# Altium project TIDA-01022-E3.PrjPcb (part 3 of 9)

## Sheet TIDA-01022-E3_ADC12DJxx00_1.SchDoc: ADC12DJxx00_1
size 431 x 279 mm; Date: Not shown in title block; ApprovedBy: Not shown in title block; CheckedBy: Not shown in title block; Author: Not shown in title block; CompanyName: Not shown in title block; DrawnBy: Avinash N; Engineer: Not shown in title block; Organization: Not shown in title block; Address1: Not shown in title block; Address2: Not shown in title block; Address3: Not shown in title block; Address4: Not shown in title block; DocumentNumber: 1; Revision: Use project parameter SCH_Rev; SheetNumber: 6; SheetTotal: 26; PageSetup: Record=PageOptions¦CenterHorizontal=True¦CenterVertical=True¦PrintScale=1.00¦XCorrection=1.00¦YCorrection=1.00¦PrintKind=0¦BorderSize=5000000¦LeftOffset=0¦BottomOffset=0¦Orientation=2¦PaperLength=1000¦PaperWidth=1000¦Scale=100¦PaperSource=15¦PrintQuality=600¦MediaType=1¦DitherType=10¦PaperKind=Letter¦PrintScaleMode=1

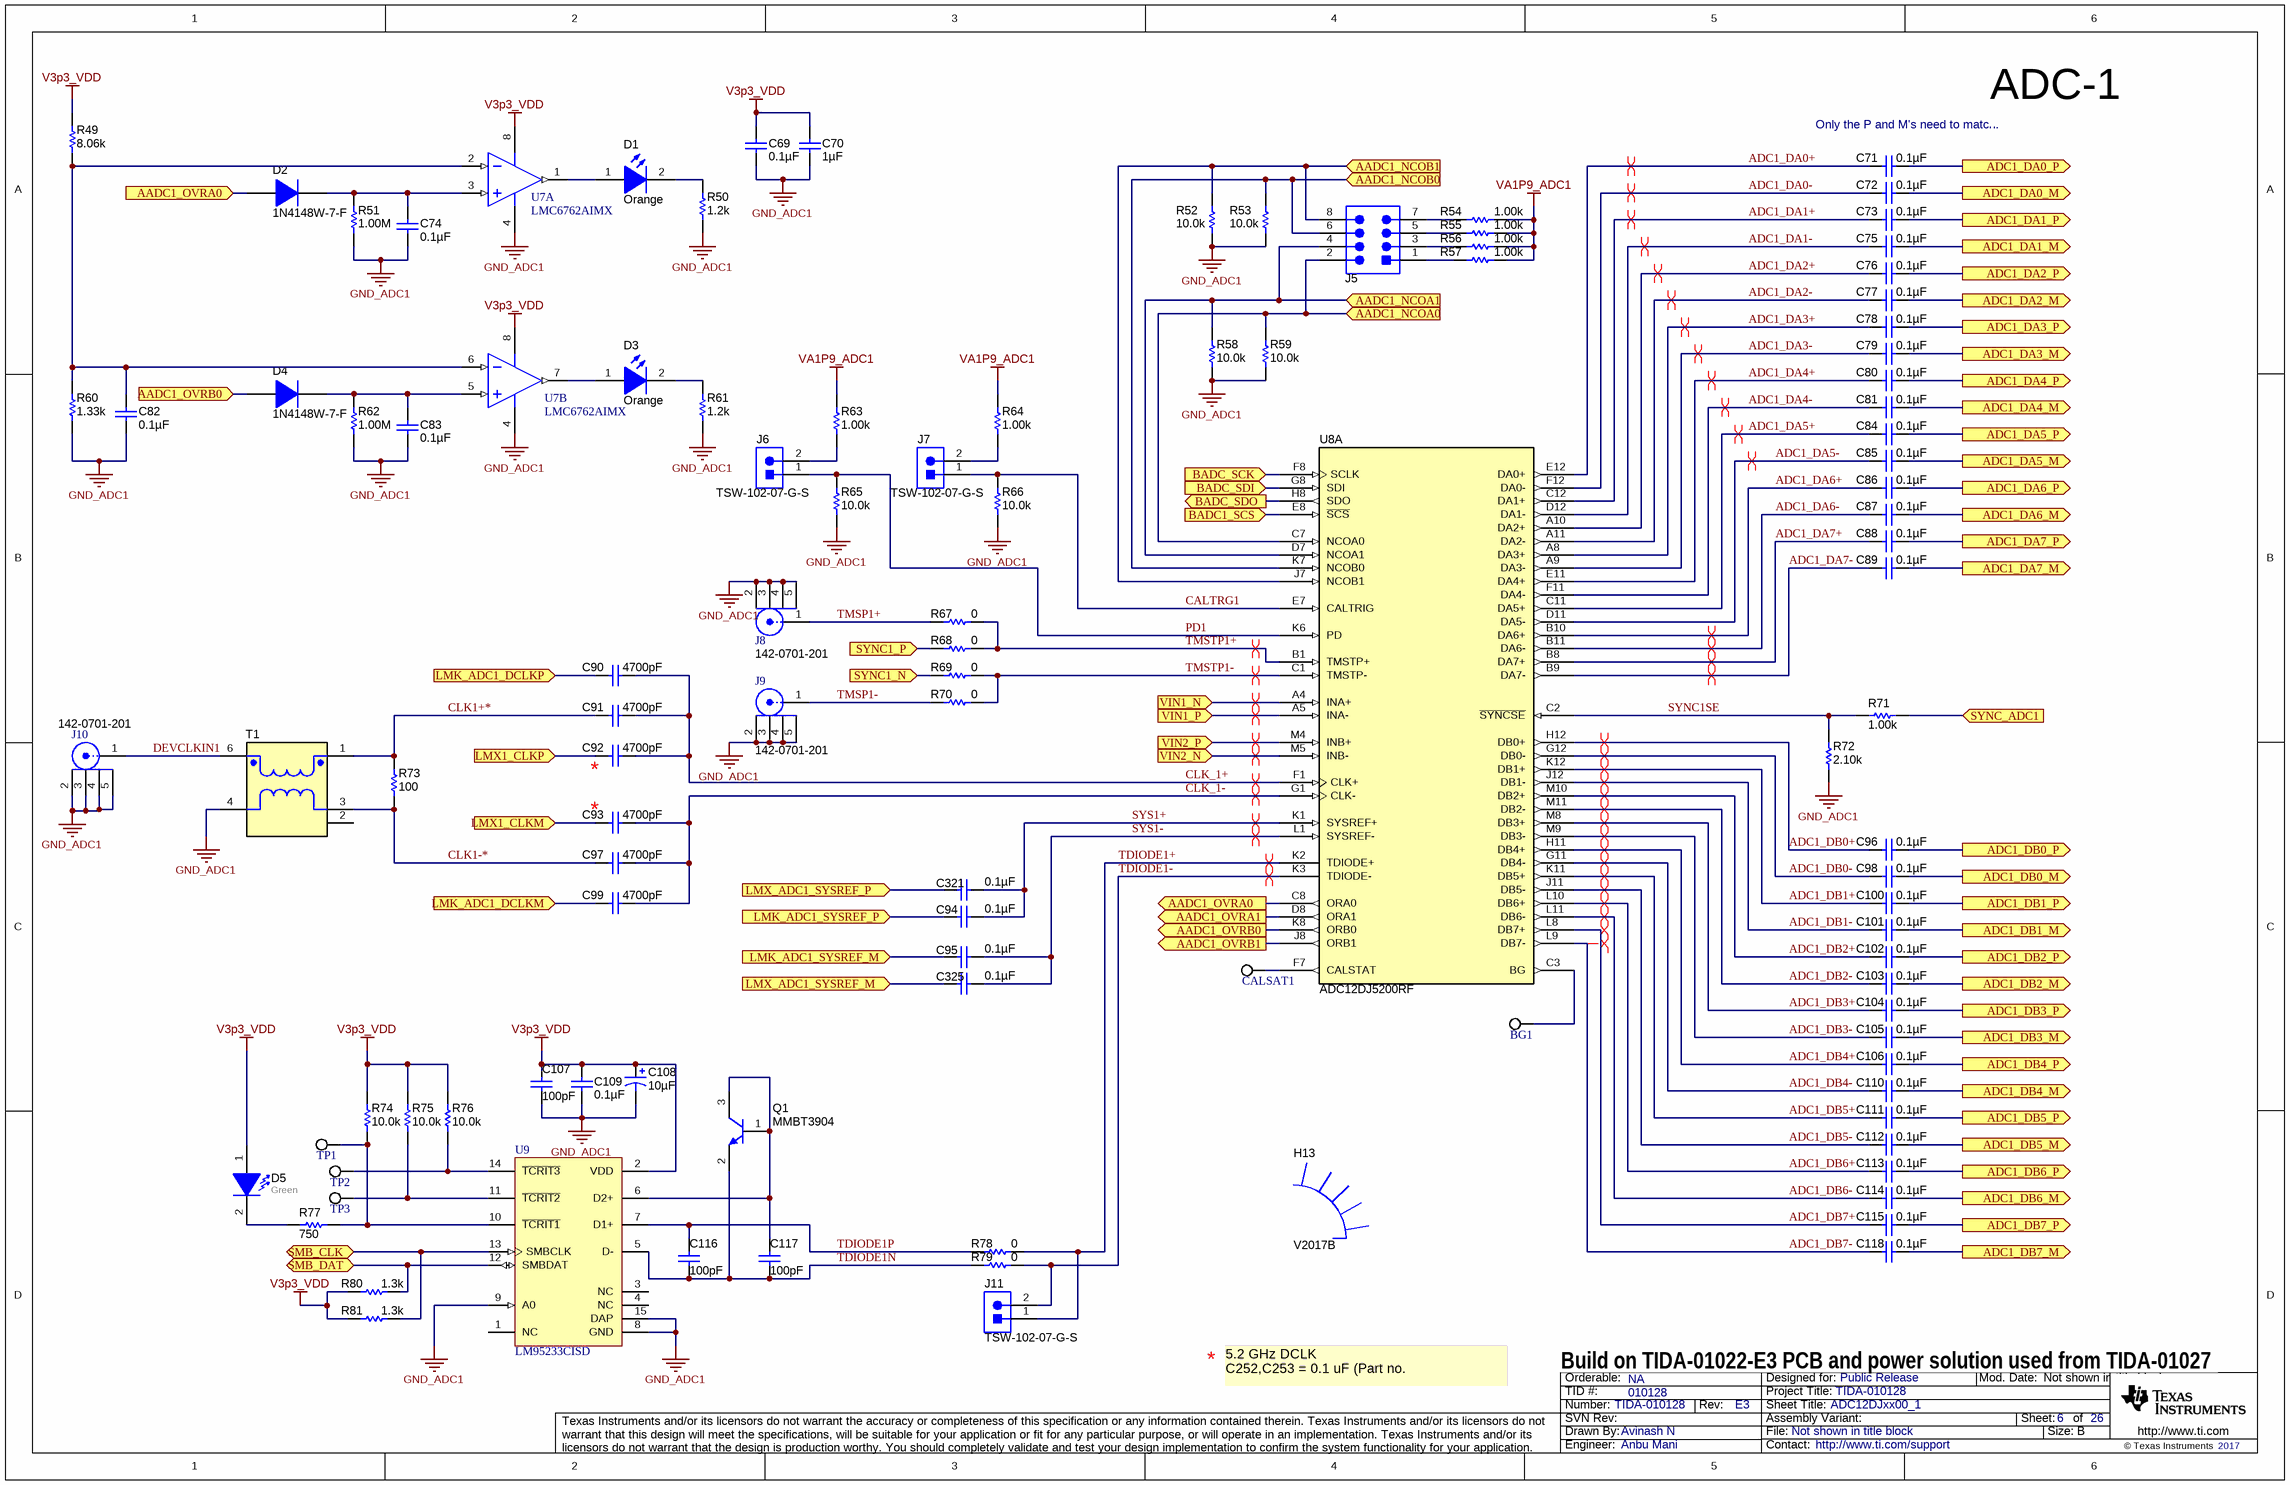
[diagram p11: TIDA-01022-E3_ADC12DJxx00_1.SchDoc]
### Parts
BG1  5002  [Keystone5002]  (value not drawn)
C69  ValueDisplayed: 0.1µF  [0402]  (hidden comment: C1005X7R1E104M050BB)
C70  ValueDisplayed: 1µF  [0603]  (hidden comment: C1608X5R1A105K080AC)
C71  ValueDisplayed: 0.1µF  [0201_adc]  (hidden comment: GRM033C71A104KE14D)
C72  ValueDisplayed: 0.1µF  [0201_adc]  (hidden comment: GRM033C71A104KE14D)
C73  ValueDisplayed: 0.1µF  [0201_adc]  (hidden comment: GRM033C71A104KE14D)
C74  ValueDisplayed: 0.1µF  [0402]  (hidden comment: C1005X7R1E104M050BB)
C75  ValueDisplayed: 0.1µF  [0201_adc]  (hidden comment: GRM033C71A104KE14D)
C76  ValueDisplayed: 0.1µF  [0201_adc]  (hidden comment: GRM033C71A104KE14D)
C77  ValueDisplayed: 0.1µF  [0201_adc]  (hidden comment: GRM033C71A104KE14D)
C78  ValueDisplayed: 0.1µF  [0201_adc]  (hidden comment: GRM033C71A104KE14D)
C79  ValueDisplayed: 0.1µF  [0201_adc]  (hidden comment: GRM033C71A104KE14D)
C80  ValueDisplayed: 0.1µF  [0201_adc]  (hidden comment: GRM033C71A104KE14D)
C81  ValueDisplayed: 0.1µF  [0201_adc]  (hidden comment: GRM033C71A104KE14D)
C82  ValueDisplayed: 0.1µF  [0402]  (hidden comment: C1005X7R1E104M050BB)
C83  ValueDisplayed: 0.1µF  [0402]  (hidden comment: C1005X7R1E104M050BB)
C84  ValueDisplayed: 0.1µF  [0201_adc]  (hidden comment: GRM033C71A104KE14D)
C85  ValueDisplayed: 0.1µF  [0201_adc]  (hidden comment: GRM033C71A104KE14D)
C86  ValueDisplayed: 0.1µF  [0201_adc]  (hidden comment: GRM033C71A104KE14D)
C87  ValueDisplayed: 0.1µF  [0201_adc]  (hidden comment: GRM033C71A104KE14D)
C88  ValueDisplayed: 0.1µF  [0201_adc]  (hidden comment: GRM033C71A104KE14D)
C89  ValueDisplayed: 0.1µF  [0201_adc]  (hidden comment: GRM033C71A104KE14D)
C90  ValueDisplayed: 4700pF  [0402]  (hidden comment: GRM155R71H472KA01D)
C91  ValueDisplayed: 4700pF  [0402]  (hidden comment: GRM155R71H472KA01D)
C92  ValueDisplayed: 4700pF  [0402]  (hidden comment: GRM155R71H472KA01D)
C93  ValueDisplayed: 4700pF  [0402]  (hidden comment: GRM155R71H472KA01D)
C94  ValueDisplayed: 0.1µF  [0402]  (hidden comment: C1005X7R1E104M050BB)
C95  ValueDisplayed: 0.1µF  [0402]  (hidden comment: C1005X7R1E104M050BB)
C96  ValueDisplayed: 0.1µF  [0201_adc]  (hidden comment: GRM033C71A104KE14D)
C97  ValueDisplayed: 4700pF  [0402]  (hidden comment: GRM155R71H472KA01D)
C98  ValueDisplayed: 0.1µF  [0201_adc]  (hidden comment: GRM033C71A104KE14D)
C99  ValueDisplayed: 4700pF  [0402]  (hidden comment: GRM155R71H472KA01D)
C100  ValueDisplayed: 0.1µF  [0201_adc]  (hidden comment: GRM033C71A104KE14D)
C101  ValueDisplayed: 0.1µF  [0201_adc]  (hidden comment: GRM033C71A104KE14D)
C102  ValueDisplayed: 0.1µF  [0201_adc]  (hidden comment: GRM033C71A104KE14D)
C103  ValueDisplayed: 0.1µF  [0201_adc]  (hidden comment: GRM033C71A104KE14D)
C104  ValueDisplayed: 0.1µF  [0201_adc]  (hidden comment: GRM033C71A104KE14D)
C105  ValueDisplayed: 0.1µF  [0201_adc]  (hidden comment: GRM033C71A104KE14D)
C106  ValueDisplayed: 0.1µF  [0201_adc]  (hidden comment: GRM033C71A104KE14D)
C107  ValueDisplayed: 100pF  [0402]  (hidden comment: GRM1555C1H101JA01D)
C108  ValueDisplayed: 10µF  [3528-21]  (hidden comment: 293D106X0010B2TE3)
C109  ValueDisplayed: 0.1µF  [0402]  (hidden comment: C1005X7R1E104M050BB)
C110  ValueDisplayed: 0.1µF  [0201_adc]  (hidden comment: GRM033C71A104KE14D)
C111  ValueDisplayed: 0.1µF  [0201_adc]  (hidden comment: GRM033C71A104KE14D)
C112  ValueDisplayed: 0.1µF  [0201_adc]  (hidden comment: GRM033C71A104KE14D)
C113  ValueDisplayed: 0.1µF  [0201_adc]  (hidden comment: GRM033C71A104KE14D)
C114  ValueDisplayed: 0.1µF  [0201_adc]  (hidden comment: GRM033C71A104KE14D)
C115  ValueDisplayed: 0.1µF  [0201_adc]  (hidden comment: GRM033C71A104KE14D)
C116  ValueDisplayed: 100pF  [0402]  (hidden comment: GRM1555C1H101JA01D)
C117  ValueDisplayed: 100pF  [0402]  (hidden comment: GRM1555C1H101JA01D)
C118  ValueDisplayed: 0.1µF  [0201_adc]  (hidden comment: GRM033C71A104KE14D)
C321  ValueDisplayed: 0.1µF  [0402]  (hidden comment: C1005X7R1E104M050BB)
C325  ValueDisplayed: 0.1µF  [0402]  (hidden comment: C1005X7R1E104M050BB)
CALSAT1  5002  [Keystone5002]  (value not drawn)
D1  value Orange  [LED_LTST-C190]  (hidden comment: LTST-C190KFKT)
D2  1N4148W-7-F  [SOD-123]
D3  value Orange  [LED_LTST-C190]  (hidden comment: LTST-C190KFKT)
D4  1N4148W-7-F  [SOD-123]
D5  value Green  [LED_LTST-C190]  (hidden comment: LTST-C190GKT)
H13  V2017B  [ASMN_V2017B]  (mechanical)
J5  TSW-104-07-G-D  [TSW-104-07-G-D]  (value not drawn)
J6  TSW-102-07-G-S  [TSW-102-07-G-S]
J7  TSW-102-07-G-S  [TSW-102-07-G-S]
J8  142-0701-201  [Johnson_142-0701-20x]
J9  142-0701-201  [Johnson_142-0701-20x]
J10  142-0701-201  [Johnson_142-0701-20x]
J11  TSW-102-07-G-S  [TSW-102-07-G-S]
Q1  MMBT3904  [SOT-23]
R49  ValueDisplayed: 8.06k  [0402]  (hidden comment: CRCW04028K06FKED)
R50  ValueDisplayed: 1.2k  [0402]  (hidden comment: CRCW04021K20JNED)
R51  ValueDisplayed: 1.00M  [0402]  (hidden comment: ERJ-2RKF1004X)
R52  ValueDisplayed: 10.0k  [0402]  (hidden comment: ERJ-2RKF1002X)
R53  ValueDisplayed: 10.0k  [0402]  (hidden comment: ERJ-2RKF1002X)
R54  ValueDisplayed: 1.00k  [0402]  (hidden comment: ERJ-2RKF1001X)
R55  ValueDisplayed: 1.00k  [0402]  (hidden comment: ERJ-2RKF1001X)
R56  ValueDisplayed: 1.00k  [0402]  (hidden comment: ERJ-2RKF1001X)
R57  ValueDisplayed: 1.00k  [0402]  (hidden comment: ERJ-2RKF1001X)
R58  ValueDisplayed: 10.0k  [0402]  (hidden comment: ERJ-2RKF1002X)
R59  ValueDisplayed: 10.0k  [0402]  (hidden comment: ERJ-2RKF1002X)
R60  ValueDisplayed: 1.33k  [0402]  (hidden comment: CRCW04021K33FKED)
R61  ValueDisplayed: 1.2k  [0402]  (hidden comment: CRCW04021K20JNED)
R62  ValueDisplayed: 1.00M  [0402]  (hidden comment: ERJ-2RKF1004X)
R63  ValueDisplayed: 1.00k  [0402]  (hidden comment: ERJ-2RKF1001X)
R64  ValueDisplayed: 1.00k  [0402]  (hidden comment: ERJ-2RKF1001X)
R65  ValueDisplayed: 10.0k  [0402]  (hidden comment: ERJ-2RKF1002X)
R66  ValueDisplayed: 10.0k  [0402]  (hidden comment: ERJ-2RKF1002X)
R67  ValueDisplayed: 0  [0402]  (hidden comment: CRCW04020000Z0ED)
R68  ValueDisplayed: 0  [0402]  (hidden comment: CRCW04020000Z0ED)
R69  ValueDisplayed: 0  [0402]  (hidden comment: CRCW04020000Z0ED)
R70  ValueDisplayed: 0  [0402]  (hidden comment: CRCW04020000Z0ED)
R71  ValueDisplayed: 1.00k  [0402]  (hidden comment: ERJ-2RKF1001X)
R72  ValueDisplayed: 2.10k  [0402]  (hidden comment: CRCW04022K10FKED)
R73  ValueDisplayed: 100  [0402]  (hidden comment: CRCW0402100RFKED)
R74  ValueDisplayed: 10.0k  [0402]  (hidden comment: ERJ-2RKF1002X)
R75  ValueDisplayed: 10.0k  [0402]  (hidden comment: ERJ-2RKF1002X)
R76  ValueDisplayed: 10.0k  [0402]  (hidden comment: ERJ-2RKF1002X)
R77  ValueDisplayed: 750  [0603]  (hidden comment: CRCW0603750RJNEA)
R78  ValueDisplayed: 0  [0402]  (hidden comment: CRCW04020000Z0ED)
R79  ValueDisplayed: 0  [0402]  (hidden comment: CRCW04020000Z0ED)
R80  ValueDisplayed: 1.3k  [0603]  (hidden comment: RC0603JR-071K3L)
R81  ValueDisplayed: 1.3k  [0603]  (hidden comment: RC0603JR-071K3L)
T1  TC1-1-43X+  [MNC_AT1521]  (value not drawn)
TP1  5002  [Keystone5002]  (value not drawn)
TP2  5002  [Keystone5002]  (value not drawn)
TP3  5002  [Keystone5002]  (value not drawn)
U7  LMC6762AIMX  [M08A_N]  (parts A,B of 2)
U8  ADC12DJ5200RF  [AAV0144A]  (part A of 2)
U9  LM95233CISD  [SDA14B]

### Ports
AADC1_NCOA0 (in), AADC1_NCOA1 (in), AADC1_NCOB0 (in), AADC1_NCOB1 (in), AADC1_OVRA0 (in), AADC1_OVRA0 (out), AADC1_OVRA1 (out), AADC1_OVRB0 (in), AADC1_OVRB0 (out), AADC1_OVRB1 (out), ADC1_DA0_M (out), ADC1_DA0_P (out), ADC1_DA1_M (out), ADC1_DA1_P (out), ADC1_DA2_M (out), ADC1_DA2_P (out), ADC1_DA3_M (out), ADC1_DA3_P (out), ADC1_DA4_M (out), ADC1_DA4_P (out), ADC1_DA5_M (out), ADC1_DA5_P (out), ADC1_DA6_M (out), ADC1_DA6_P (out), ADC1_DA7_M (out), ADC1_DA7_P (out), ADC1_DB0_M (out), ADC1_DB0_P (out), ADC1_DB1_M (out), ADC1_DB1_P (out), ADC1_DB2_M (out), ADC1_DB2_P (out), ADC1_DB3_M (out), ADC1_DB3_P (out), ADC1_DB4_M (out), ADC1_DB4_P (out), ADC1_DB5_M (out), ADC1_DB5_P (out), ADC1_DB6_M (out), ADC1_DB6_P (out), ADC1_DB7_M (out), ADC1_DB7_P (out), BADC1_SCS (in), BADC_SCK (in), BADC_SDI (in), BADC_SDO (out), LMK_ADC1_DCLKM (in), LMK_ADC1_DCLKP (in), LMK_ADC1_SYSREF_M (in), LMK_ADC1_SYSREF_P (in), LMX1_CLKM (in), LMX1_CLKP (in), LMX_ADC1_SYSREF_M (in), LMX_ADC1_SYSREF_P (in), SMB_CLK (bidir), SMB_DAT (bidir), SYNC1_N (in), SYNC1_P (in), SYNC_ADC1 (in), VIN1_N (in), VIN1_P (in), VIN2_N (in), VIN2_P (in)

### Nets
GND_ADC1: C69.1 C70.2 C74.1 C82.1 C83.1 C107.2 C108.2(-) C109.2 J8.2 J8.3 J8.4 J8.5 J9.2 J9.3 J9.4 J9.5 J10.2 J10.3 J10.4 J10.5 R50.1 R51.1 R52.2 R53.2 R58.2 R59.2 R60.1 R61.1 R62.1 R65.1 R66.1 R72.1 T1.4 U7.4(V-) U9.8(GND) U9.9(A0) U9.15(DAP)  [project net DGND]
V3p3_VDD: C69.2 C70.1 C107.1 C108.1(+) C109.1 D5.1(A) R49.2 R74.2 R75.2 R76.2 R80.2 R81.2 U7.8(V+) U9.2(VDD)
VA1P9_ADC1: R54.1 R55.1 R56.1 R57.1 R63.2 R64.2
AADC1_NCOA0: J5.2 R59.1 U8.C7(NCOA0) ; port AADC1_NCOA0
AADC1_NCOA1: J5.4 R58.1 U8.D7(NCOA1) ; port AADC1_NCOA1
AADC1_NCOB0: J5.6 R53.1 U8.K7(NCOB0) ; port AADC1_NCOB0
AADC1_NCOB1: J5.8 R52.1 U8.J7(NCOB1) ; port AADC1_NCOB1
AADC1_OVRA0: D2.2(A) U8.C8(ORA0) ; port AADC1_OVRA0
AADC1_OVRA1: U8.D8(ORA1) ; port AADC1_OVRA1
AADC1_OVRB0: D4.2(A) U8.K8(ORB0) ; port AADC1_OVRB0
AADC1_OVRB1: U8.J8(ORB1) ; port AADC1_OVRB1
ADC1_DA0+: C71.1 U8.E12(DA0+)
ADC1_DA0-: C72.1 U8.F12(DA0-)
ADC1_DA0_M: C72.2 ; port ADC1_DA0_M
ADC1_DA0_P: C71.2 ; port ADC1_DA0_P
ADC1_DA1+: C73.1 U8.C12(DA1+)
ADC1_DA1-: C75.1 U8.D12(DA1-)
ADC1_DA1_M: C75.2 ; port ADC1_DA1_M
ADC1_DA1_P: C73.2 ; port ADC1_DA1_P
ADC1_DA2+: C76.1 U8.A10(DA2+)
ADC1_DA2-: C77.1 U8.A11(DA2-)
ADC1_DA2_M: C77.2 ; port ADC1_DA2_M
ADC1_DA2_P: C76.2 ; port ADC1_DA2_P
ADC1_DA3+: C78.1 U8.A8(DA3+)
ADC1_DA3-: C79.1 U8.A9(DA3-)
ADC1_DA3_M: C79.2 ; port ADC1_DA3_M
ADC1_DA3_P: C78.2 ; port ADC1_DA3_P
ADC1_DA4+: C80.1 U8.E11(DA4+)
ADC1_DA4-: C81.1 U8.F11(DA4-)
ADC1_DA4_M: C81.2 ; port ADC1_DA4_M
ADC1_DA4_P: C80.2 ; port ADC1_DA4_P
ADC1_DA5+: C84.1 U8.C11(DA5+)
ADC1_DA5-: C85.1 U8.D11(DA5-)
ADC1_DA5_M: C85.2 ; port ADC1_DA5_M
ADC1_DA5_P: C84.2 ; port ADC1_DA5_P
ADC1_DA6+: C86.1 U8.B10(DA6+)
ADC1_DA6-: C87.1 U8.B11(DA6-)
ADC1_DA6_M: C87.2 ; port ADC1_DA6_M
ADC1_DA6_P: C86.2 ; port ADC1_DA6_P
ADC1_DA7+: C88.1 U8.B8(DA7+)
ADC1_DA7-: C89.1 U8.B9(DA7-)
ADC1_DA7_M: C89.2 ; port ADC1_DA7_M
ADC1_DA7_P: C88.2 ; port ADC1_DA7_P
ADC1_DB0+: C96.1 U8.H12(DB0+)
ADC1_DB0-: C98.1 U8.G12(DB0-)
ADC1_DB0_M: C98.2 ; port ADC1_DB0_M
ADC1_DB0_P: C96.2 ; port ADC1_DB0_P
ADC1_DB1+: C100.1 U8.K12(DB1+)
ADC1_DB1-: C101.1 U8.J12(DB1-)
ADC1_DB1_M: C101.2 ; port ADC1_DB1_M
ADC1_DB1_P: C100.2 ; port ADC1_DB1_P
ADC1_DB2+: C102.1 U8.M10(DB2+)
ADC1_DB2-: C103.1 U8.M11(DB2-)
ADC1_DB2_M: C103.2 ; port ADC1_DB2_M
ADC1_DB2_P: C102.2 ; port ADC1_DB2_P
ADC1_DB3+: C104.1 U8.M8(DB3+)
ADC1_DB3-: C105.1 U8.M9(DB3-)
ADC1_DB3_M: C105.2 ; port ADC1_DB3_M
ADC1_DB3_P: C104.2 ; port ADC1_DB3_P
ADC1_DB4+: C106.1 U8.H11(DB4+)
ADC1_DB4-: C110.1 U8.G11(DB4-)
ADC1_DB4_M: C110.2 ; port ADC1_DB4_M
ADC1_DB4_P: C106.2 ; port ADC1_DB4_P
ADC1_DB5+: C111.1 U8.K11(DB5+)
ADC1_DB5-: C112.1 U8.J11(DB5-)
ADC1_DB5_M: C112.2 ; port ADC1_DB5_M
ADC1_DB5_P: C111.2 ; port ADC1_DB5_P
ADC1_DB6+: C113.1 U8.L10(DB6+)
ADC1_DB6-: C114.1 U8.L11(DB6-)
ADC1_DB6_M: C114.2 ; port ADC1_DB6_M
ADC1_DB6_P: C113.2 ; port ADC1_DB6_P
ADC1_DB7+: C115.1 U8.L8(DB7+)
ADC1_DB7-: C118.1 U8.L9(DB7-)
ADC1_DB7_M: C118.2 ; port ADC1_DB7_M
ADC1_DB7_P: C115.2 ; port ADC1_DB7_P
BADC1_SCS: U8.E8(~{SCS}) ; port BADC1_SCS
BADC_SCK: U8.F8(SCLK) ; port BADC_SCK
BADC_SDI: U8.G8(SDI) ; port BADC_SDI
BADC_SDO: U8.H8(SDO) ; port BADC_SDO
CALTRG1: J7.1 R66.2 U8.E7(CALTRIG)
CLK1+*: C91.2 R73.2 T1.1
CLK1-*: C97.2 R73.1 T1.3
CLK_1+: C90.1 C91.1 C92.1 U8.F1(CLK+)
CLK_1-: C93.1 C97.1 C99.1 U8.G1(CLK-)
DEVCLKIN1: J10.1 T1.6
LMK_ADC1_DCLKM: C99.2 ; port LMK_ADC1_DCLKM
LMK_ADC1_DCLKP: C90.2 ; port LMK_ADC1_DCLKP
LMK_ADC1_SYSREF_M: C95.1 ; port LMK_ADC1_SYSREF_M
LMK_ADC1_SYSREF_P: C94.1 ; port LMK_ADC1_SYSREF_P
LMX1_CLKM: C93.2 ; port LMX1_CLKM
LMX1_CLKP: C92.2 ; port LMX1_CLKP
LMX_ADC1_SYSREF_M: C325.1 ; port LMX_ADC1_SYSREF_M
LMX_ADC1_SYSREF_P: C321.1 ; port LMX_ADC1_SYSREF_P
PD1: J6.1 R65.2 U8.K6(PD)
SMB_CLK: R81.1 U9.13(SMBCLK) ; port SMB_CLK
SMB_DAT: R80.1 U9.12(SMBDAT) ; port SMB_DAT
SYNC1_N: R69.1 ; port SYNC1_N
SYNC1_P: R68.1 ; port SYNC1_P
SYNC1SE: R71.1 R72.2 U8.C2(~{SYNCSE})
SYNC_ADC1: R71.2 ; port SYNC_ADC1
SYS1+: C94.2 C321.2 U8.K1(SYSREF+)
SYS1-: C95.2 C325.2 U8.L1(SYSREF-)
TDIODE1+: J11.1 R78.2 U8.K2(TDIODE+)
TDIODE1-: J11.2 R79.2 U8.K3(TDIODE-)
TDIODE1N: C116.2 C117.2 Q1.2(E) R79.1 U9.5(D-)
TDIODE1P: C116.1 R78.1 U9.7(D1+)
TMSP1+: J8.1 R67.1
TMSP1-: J9.1 R70.1
TMSTP1+: R67.2 R68.2 U8.B1(TMSTP+)
TMSTP1-: R69.2 R70.2 U8.C1(TMSTP-)
VIN1_N: U8.A4(INA+) ; port VIN1_N
VIN1_P: U8.A5(INA-) ; port VIN1_P
VIN2_N: U8.M5(INB-) ; port VIN2_N
VIN2_P: U8.M4(INB+) ; port VIN2_P
NetBG1_1: BG1.1 U8.C3(BG)
NetC74_2: C74.2 D2.1(K) R51.2 U7.3(INA+)
NetC82_2: C82.2 R49.1 R60.2 U7.2(INA-) U7.6(INB-)
NetC83_2: C83.2 D4.1(K) R62.2 U7.5(INB+)
NetC117_1: C117.1 Q1.1(B) Q1.3(C) U9.6(D2+)
NetCALSAT1_1: CALSAT1.1 U8.F7(CALSTAT)
NetD1_1: D1.1(A) U7.1(OUTA)
NetD1_2: D1.2(K) R50.2
NetD3_1: D3.1(A) U7.7(OUTB)
NetD3_2: D3.2(K) R61.2
NetD5_2: D5.2(K) R77.2
NetJ5_1: J5.1 R57.2
NetJ5_3: J5.3 R56.2
NetJ5_5: J5.5 R55.2
NetJ5_7: J5.7 R54.2
NetJ6_2: J6.2 R63.1
NetJ7_2: J7.2 R64.1
NetR74_1: R74.1 R77.1 TP1.1 U9.10(~{TCRIT1})
NetR75_1: R75.1 TP3.1 U9.11(~{TCRIT2})
NetR76_1: R76.1 TP2.1 U9.14(~{TCRIT3})

Not connected (* = marked no-connect by the designer): T1 2; U9 1(NC) 3(NC) 4(NC)

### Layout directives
differential pair: ADC1_DA0+, ADC1_DA0-, ADC1_DA1+, ADC1_DA1-, ADC1_DA2+, ADC1_DA2-, ADC1_DA3+, ADC1_DA3-, ADC1_DA4+, ADC1_DA4-, ADC1_DA5+, ADC1_DA5-, ADC1_DA6+, ADC1_DA6-, ADC1_DA7+, ADC1_DA7-, ADC1_DB0+, ADC1_DB0-, ADC1_DB1+, ADC1_DB1-, ADC1_DB2+, ADC1_DB2-, ADC1_DB3+, ADC1_DB3-, ADC1_DB4+, ADC1_DB4-, ADC1_DB5+, ADC1_DB5-, ADC1_DB6+, ADC1_DB6-, ADC1_DB7+, ADC1_DB7-, CLK_1+, CLK_1-, SYS1+, SYS1-, TDIODE1+, TDIODE1-, TMSTP1+, TMSTP1-, VIN1_N, VIN1_P, VIN2_N, VIN2_P

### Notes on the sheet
- (near C71) Only the P and M's need to match.
- ADC-1
- (near C92) *
- (near C93) *
- *
- Build on TIDA-01022-E3 PCB and power solution used from TIDA-01027
- 5.2 GHz DCLK
  C252,C253 = 0.1 uF (Part no. 530Z104KT10T))

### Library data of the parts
BG1 CALSAT1 TP1-TP3 = 5002: Test Point, Miniature, White, TH; Manufacturer: Keystone; CompType: Test Point Loop; ContactFinish: Silver; Green_Lifecycle: Active; Green_REACh: Passed
C69 C74 C82 C83 C94 C95 C109 C321 C325 = C1005X7R1E104M050BB: CAP, CERM, 0.1 µF, 25 V, +/- 20%, X7R, 0402; Manufacturer: TDK; Polarized: N; TaMax_C: 125; TaMin_C: -55; Tolerance_%: 20; VDC_V: 25; Cap_F: 0.0000001; CompType: Capacitor; Value: 0.1uF; Value1: Unknown; Value2: 25V; U/M: EA; SizeArea_mm2: 0.5; SizeAreaWB_mm2: 3; SizeX_mm: 1; SizeZ_mm: 0.6; AEC Category: Q200
C70 = C1608X5R1A105K080AC: CAP, CERM, 1 µF, 10 V, +/- 10%, X5R, 0603; Manufacturer: TDK; Polarized: N; CompType: Capacitor; Value: 1uF; U/M: EA; Cap_F: 0.000001; Tolerance_%: 10; Value1: Unknown; Value2: 10V; TaMin_C: -55; TaMax_C: 85; SizeArea_mm2: 1.28; SizeAreaWB_mm2: 4.68; SizeX_mm: 1.6; SizeY_mm: 0.8; SizeZ_mm: 1; AEC Category: Q200
C71-C73 C75-C81 C84-C89 C96 C98 C100-C106 C110-C115 C118 = GRM033C71A104KE14D: CAP, CERM, 0.1 µF, 10 V, +/- 10%, X7S, 0201; Manufacturer: MuRata; Cap_Case: 0201; Polarized: N; TaMax_C: 125; TaMin_C: -55; Tolerance_%: 10; Cap_F: 0.0000001; CompType: Capacitor; Value: 0.1uF; Value1: Unknown; Value2: 10V; U/M: EA; SizeArea_mm2: 0.18; SizeAreaWB_mm2: 2.08; SizeX_mm: 0.6; SizeY_mm: 0.3; SizeZ_mm: 0.26; AEC Category: Q200
C90-C93 C97 C99 = GRM155R71H472KA01D: CAP, CERM, 4700 pF, 50 V, +/- 10%, X7R, 0402; Manufacturer: MuRata; Polarized: N; CompType: Capacitor; Value: 4700pF; U/M: EA; Cap_F: 0.0000000047; Tolerance_%: 10; Value1: Unknown; VDC_V: 50; Value2: 50V; TaMin_C: -55; TaMax_C: 125; SizeArea_mm2: 0.5; SizeAreaWB_mm2: 3; SizeX_mm: 1; SizeZ_mm: 0.6; AEC Category: Q200
C107 C116 C117 = GRM1555C1H101JA01D: CAP, CERM, 100 pF, 50 V, +/- 5%, C0G/NP0, 0402; Manufacturer: MuRata; Polarized: N; CompType: Capacitor; Value: 100pF; U/M: EA; Cap_F: 0.0000000001; Tolerance_%: 5; Value1: Unknown; VDC_V: 50; Value2: 50V; TaMin_C: -55; TaMax_C: 125; SizeArea_mm2: 0.5; SizeAreaWB_mm2: 3; SizeX_mm: 1; SizeZ_mm: 0.6; AEC Category: Q200
C108 = 293D106X0010B2TE3: CAP, TA, 10 µF, 10 V, +/- 20%, 2.5 ohm, SMD; Manufacturer: Vishay-Sprague; Polarized: Y; CompType: Capacitor; Value: 10uF; U/M: EA; Cap_F: 0.00001; Tolerance_%: 20; Value1: 2.5 ohm; VDC_V: 10; Value2: 10V; ESR_ohm: 2.5; IRMS_A: 0.18; TaMin_C: -55; TaMax_C: 125; Cap_Case: B; SizeAreaWB_mm2: 17.1; SizeArea_mm2: 9.8; SizeX_mm: 3.5; SizeY_mm: 2.8; SizeZ_mm: 2.1; AEC Category: Q200
D1 D3 = LTST-C190KFKT: LED, Orange, SMD; Manufacturer: Lite-On; Type: AlInGaP; Vf_V: 2; Value2: 2V; Io_A: 0.02; Power_TotalModule: 0.075; Value1: 0.075W; U/M: EA
D2 D4 = 1N4148W-7-F: Diode, Ultrafast, 100 V, 0.15 A, SOD-123; Manufacturer: Diodes Inc.; U/M: EA; Vf_V: 1.25; Value: 100V; Value1: 0.15A; Value2: 1.25V; Io_A: 0.15; Vr_V: 100; TJmax_C: 150; SizeAreaWB_mm2: 13.095; SizeArea_mm2: 6.545; SizeX_mm: 3.85; SizeY_mm: 1.7; SizeZ_mm: 1.35; AEC Category: Q101
D5 = LTST-C190GKT: LED, Green, SMD; Manufacturer: Lite-On; Vf_V: 2.1; Value2: 2.1V; Io_A: 0.02; Power_TotalModule: 0.1; Value1: 0.1W; U/M: EA
H13 = V2017B: Heatsink, 10X10X7 mm; Manufacturer: Assman WSW; SymbolCreator: a0412235
J5 = TSW-104-07-G-D: Header, 100mil, 4x2, Gold, TH; Manufacturer: Samtec; SymbolCreator: a0411947; Pitch_mm: 2.54; Gender: Male; Shrouded: N; Row_Count: 2; Current_A: 6.3; Voltage_V: 550; Cert_CSA: Y
J6 J7 J11 = TSW-102-07-G-S: Header, 100mil, 2x1, Gold, TH; Manufacturer: Samtec; SymbolCreator: a0412235; Pitch_mm: 2.54; Gender: Male; Shrouded: N; Row_Count: 1; Current_A: 6.3; Voltage_V: 550; Cert_CSA: Y
J8 J9 = 142-0701-201: Connector, TH, SMA; Manufacturer: Emerson Network Power; SymbolCreator: X0208326
J10 = 142-0701-201: Connector, SMA, TH; Manufacturer: Cinch Connectivity; SymbolCreator: X0208326; Green_Lifecycle: Not Set; Green_REACh: Incomplete
Q1 = MMBT3904, Fairchild Semiconductor: Transistor, NPN, 40 V, 0.2 A, SOT-23; CompType: BJT; PNP: 0; NPN: 1; Vceo_V: 40; Vcesat1_V: 0.2; Value: 40 V; Value1: 0.2 A; HfeMax: 300; TaMin_C: -55; TaMax_C: 150; SizeAreaWB_mm2: 14; SizeArea_mm2: 7.5; SizeX_mm: 2.5; SizeY_mm: 3; SizeZ_mm: 1.1; U/M: EA; AEC Category: Q101
R49 = CRCW04028K06FKED: RES, 8.06 k, 1%, 0.063 W, 0402; Manufacturer: Vishay-Dale; CompType: Resistor; Value: 8.06k; Res_ohm: 8060; Value_Code: 8k06; Tolerance_%: 1; Power_W: 0.063; Value2: 0.063W; VDC_V: 50; TempCo: 100 ppm/C; SizeArea_mm2: 0.5; SizeZ_mm: 0.6; EIA_Code: E96; U/M: EA; AEC Category: Q200
R50 R61 = CRCW04021K20JNED: RES, 1.2 k, 5%, 0.063 W, 0402; Manufacturer: Vishay-Dale; CompType: Resistor; Value: 1.2k; Res_ohm: 1200; Value_Code: 1k20; Tolerance_%: 5; Power_W: 0.063; Value2: 0.063W; VDC_V: 50; TempCo: 200 ppm/C; SizeArea_mm2: 0.5; SizeX_mm: 1; SizeZ_mm: 0.6; EIA_Code: E24; U/M: EA; AEC Category: Q200
R51 R62 = ERJ-2RKF1004X: RES, 1.00 M, 1%, 0.1 W, 0402; Manufacturer: Panasonic; CompType: Resistor; Value: 1.00Meg; Res_ohm: 1000000; Value_Code: 1M00; Tolerance_%: 1; Power_W: 0.1; Value2: 0.1W; VDC_V: 50; TempCo: 100 ppm/C; SizeArea_mm2: 0.5; SizeZ_mm: 0.6; EIA_Code: E96; U/M: EA; AEC Category: Q200
R52 R53 R58 R59 R65 R66 R74-R76 = ERJ-2RKF1002X: RES, 10.0 k, 1%, 0.1 W, 0402; Manufacturer: Panasonic; CompType: Resistor; Value: 10.0k; Res_ohm: 10000; Value_Code: 10k0; Tolerance_%: 1; Power_W: 0.1; Value2: 0.1W; VDC_V: 50; TempCo: 100 ppm/C; SizeArea_mm2: 0.5; SizeZ_mm: 0.6; EIA_Code: E96; U/M: EA; AEC Category: Q200
R54-R57 R63 R64 R71 = ERJ-2RKF1001X: RES, 1.00 k, 1%, 0.1 W, 0402; Manufacturer: Panasonic; CompType: Resistor; Value: 1.00k; Res_ohm: 1000; Value_Code: 1k00; Tolerance_%: 1; Power_W: 0.1; Value2: 0.1W; VDC_V: 50; TempCo: 100 ppm/C; SizeArea_mm2: 0.5; SizeZ_mm: 0.6; EIA_Code: E96; U/M: EA; AEC Category: Q200
R60 = CRCW04021K33FKED: RES, 1.33 k, 1%, 0.063 W, 0402; Manufacturer: Vishay-Dale; CompType: Resistor; Value: 1.33k; Res_ohm: 1330; Value_Code: 1k33; Tolerance_%: 1; Power_W: 0.063; Value2: 0.063W; VDC_V: 50; TempCo: 100 ppm/C; SizeArea_mm2: 0.5; SizeZ_mm: 0.6; EIA_Code: E96; U/M: EA; AEC Category: Q200
R67-R70 R78 R79 = CRCW04020000Z0ED: RES, 0, 5%, 0.063 W, 0402; Manufacturer: Vishay-Dale; CompType: Resistor; Value: 0; Value_Code: 0000; Tolerance_%: 5; Power_W: 0.063; Value2: 0.063W; VDC_V: 50; TempCo: 200 ppm/C; SizeArea_mm2: 0.5; SizeX_mm: 1; SizeZ_mm: 0.6; EIA_Code: E24; U/M: EA; AEC Category: Q200
R72 = CRCW04022K10FKED: RES, 2.10 k, 1%, 0.063 W, 0402; Manufacturer: Vishay-Dale; CompType: Resistor; Value: 2.10k; Res_ohm: 2100; Value_Code: 2k10; Tolerance_%: 1; Power_W: 0.063; Value2: 0.063W; VDC_V: 50; TempCo: 100 ppm/C; SizeArea_mm2: 0.5; SizeZ_mm: 0.6; EIA_Code: E96; U/M: EA; AEC Category: Q200
R73 = CRCW0402100RFKED: RES, 100, 1%, 0.063 W, 0402; Manufacturer: Vishay-Dale; CompType: Resistor; Value: 100; Value_Code: 100R; Tolerance_%: 1; Power_W: 0.063; Value2: 0.063W; VDC_V: 50; TempCo: 100 ppm/C; SizeArea_mm2: 0.5; SizeZ_mm: 0.6; EIA_Code: E96; U/M: EA; AEC Category: Q200
R77 = CRCW0603750RJNEA: RES, 750, 5%, 0.1 W, 0603; Manufacturer: Vishay-Dale; CompType: Resistor; Value: 750; Value_Code: 750R; Tolerance_%: 5; Power_W: 0.1; Value2: 0.1W; VDC_V: 75; TempCo: 200 ppm/C; SizeArea_mm2: 1.28; SizeX_mm: 1.6; SizeY_mm: 0.8; SizeZ_mm: 1; EIA_Code: E24; U/M: EA; AEC Category: Q200
R80 R81 = RC0603JR-071K3L: RES, 1.3 k, 5%, 0.1 W, 0603; Manufacturer: Yageo America; CompType: Resistor; Value: 1.3k; Res_ohm: 1300; Value_Code: 1k30; Tolerance_%: 5; Power_W: 0.1; Value2: 0.1W; VDC_V: 50; TempCo: 100 ppm/C; SizeArea_mm2: 1.28; SizeX_mm: 1.6; SizeY_mm: 0.8; SizeZ_mm: 1; EIA_Code: E24; U/M: EA; AEC Category: Q200
T1 = TC1-1-43X+: RF Transformer, 50 ohm, SMT; Manufacturer: Minicircuits; SymbolCreator: Altium
U7 = LMC6762AIMX: Dual Micro-Power Rail-to-Rail Input CMOS Comparator with Push-Pull Output, 8-pin Narrow SOIC; PartNumber: LMC6762AIM/NOPB-ND; Manufacturer: Texas Instruments; PackageTopMarking: NSZXTT*LMC67*62AIM; PowerWise: N
U8 = ADC12DJ3200AAVR: 6.4-GSPS Single Channel or 3.2-GSPS Dual Channel 12-bit Analog-to-Digital Converter (ADC) Family, AAV0144A (FCBGA-144); Manufacturer: Texas Instruments; SymbolCreator: Altium; SizeArea_mm2: 100; SizeAreaWB_mm2: 144; SizeX_mm: 10; SizeZ_mm: 1.94; CompType: IC; U/M: EA
U9 = LM95233CISD: Dual Remote Diode and Local Temperature Sensor with SMBus Interface and TruTherm Technology, 15-pin LLP; PartNumber: LM95233CISD/NOPB; Manufacturer: Texas Instruments; PackageTopMarking: NS*UZXYTT*95233CI; PowerWise: Y; CompType: Temp Sensor IC

## Sheet TIDA-01022-E3_ADC12DJxx00_1PWR.SchDoc: ADC12DJxx00_1PWR
size 431 x 279 mm; Date: Not shown in title block; ApprovedBy: Not shown in title block; CheckedBy: Not shown in title block; Author: Not shown in title block; CompanyName: Not shown in title block; DrawnBy: Avinash N; Engineer: Not shown in title block; Organization: Not shown in title block; Address1: Not shown in title block; Address2: Not shown in title block; Address3: Not shown in title block; Address4: Not shown in title block; DocumentNumber: 1; Revision: Use project parameter SCH_Rev; SheetNumber: 7; SheetTotal: 26; PageSetup: Record=PageOptions¦CenterHorizontal=True¦CenterVertical=True¦PrintScale=1.00¦XCorrection=1.00¦YCorrection=1.00¦PrintKind=0¦BorderSize=5000000¦LeftOffset=0¦BottomOffset=0¦Orientation=2¦PaperLength=1000¦PaperWidth=1000¦Scale=100¦PaperSource=15¦PrintQuality=600¦MediaType=1¦DitherType=10¦PaperKind=Letter¦PrintScaleMode=1

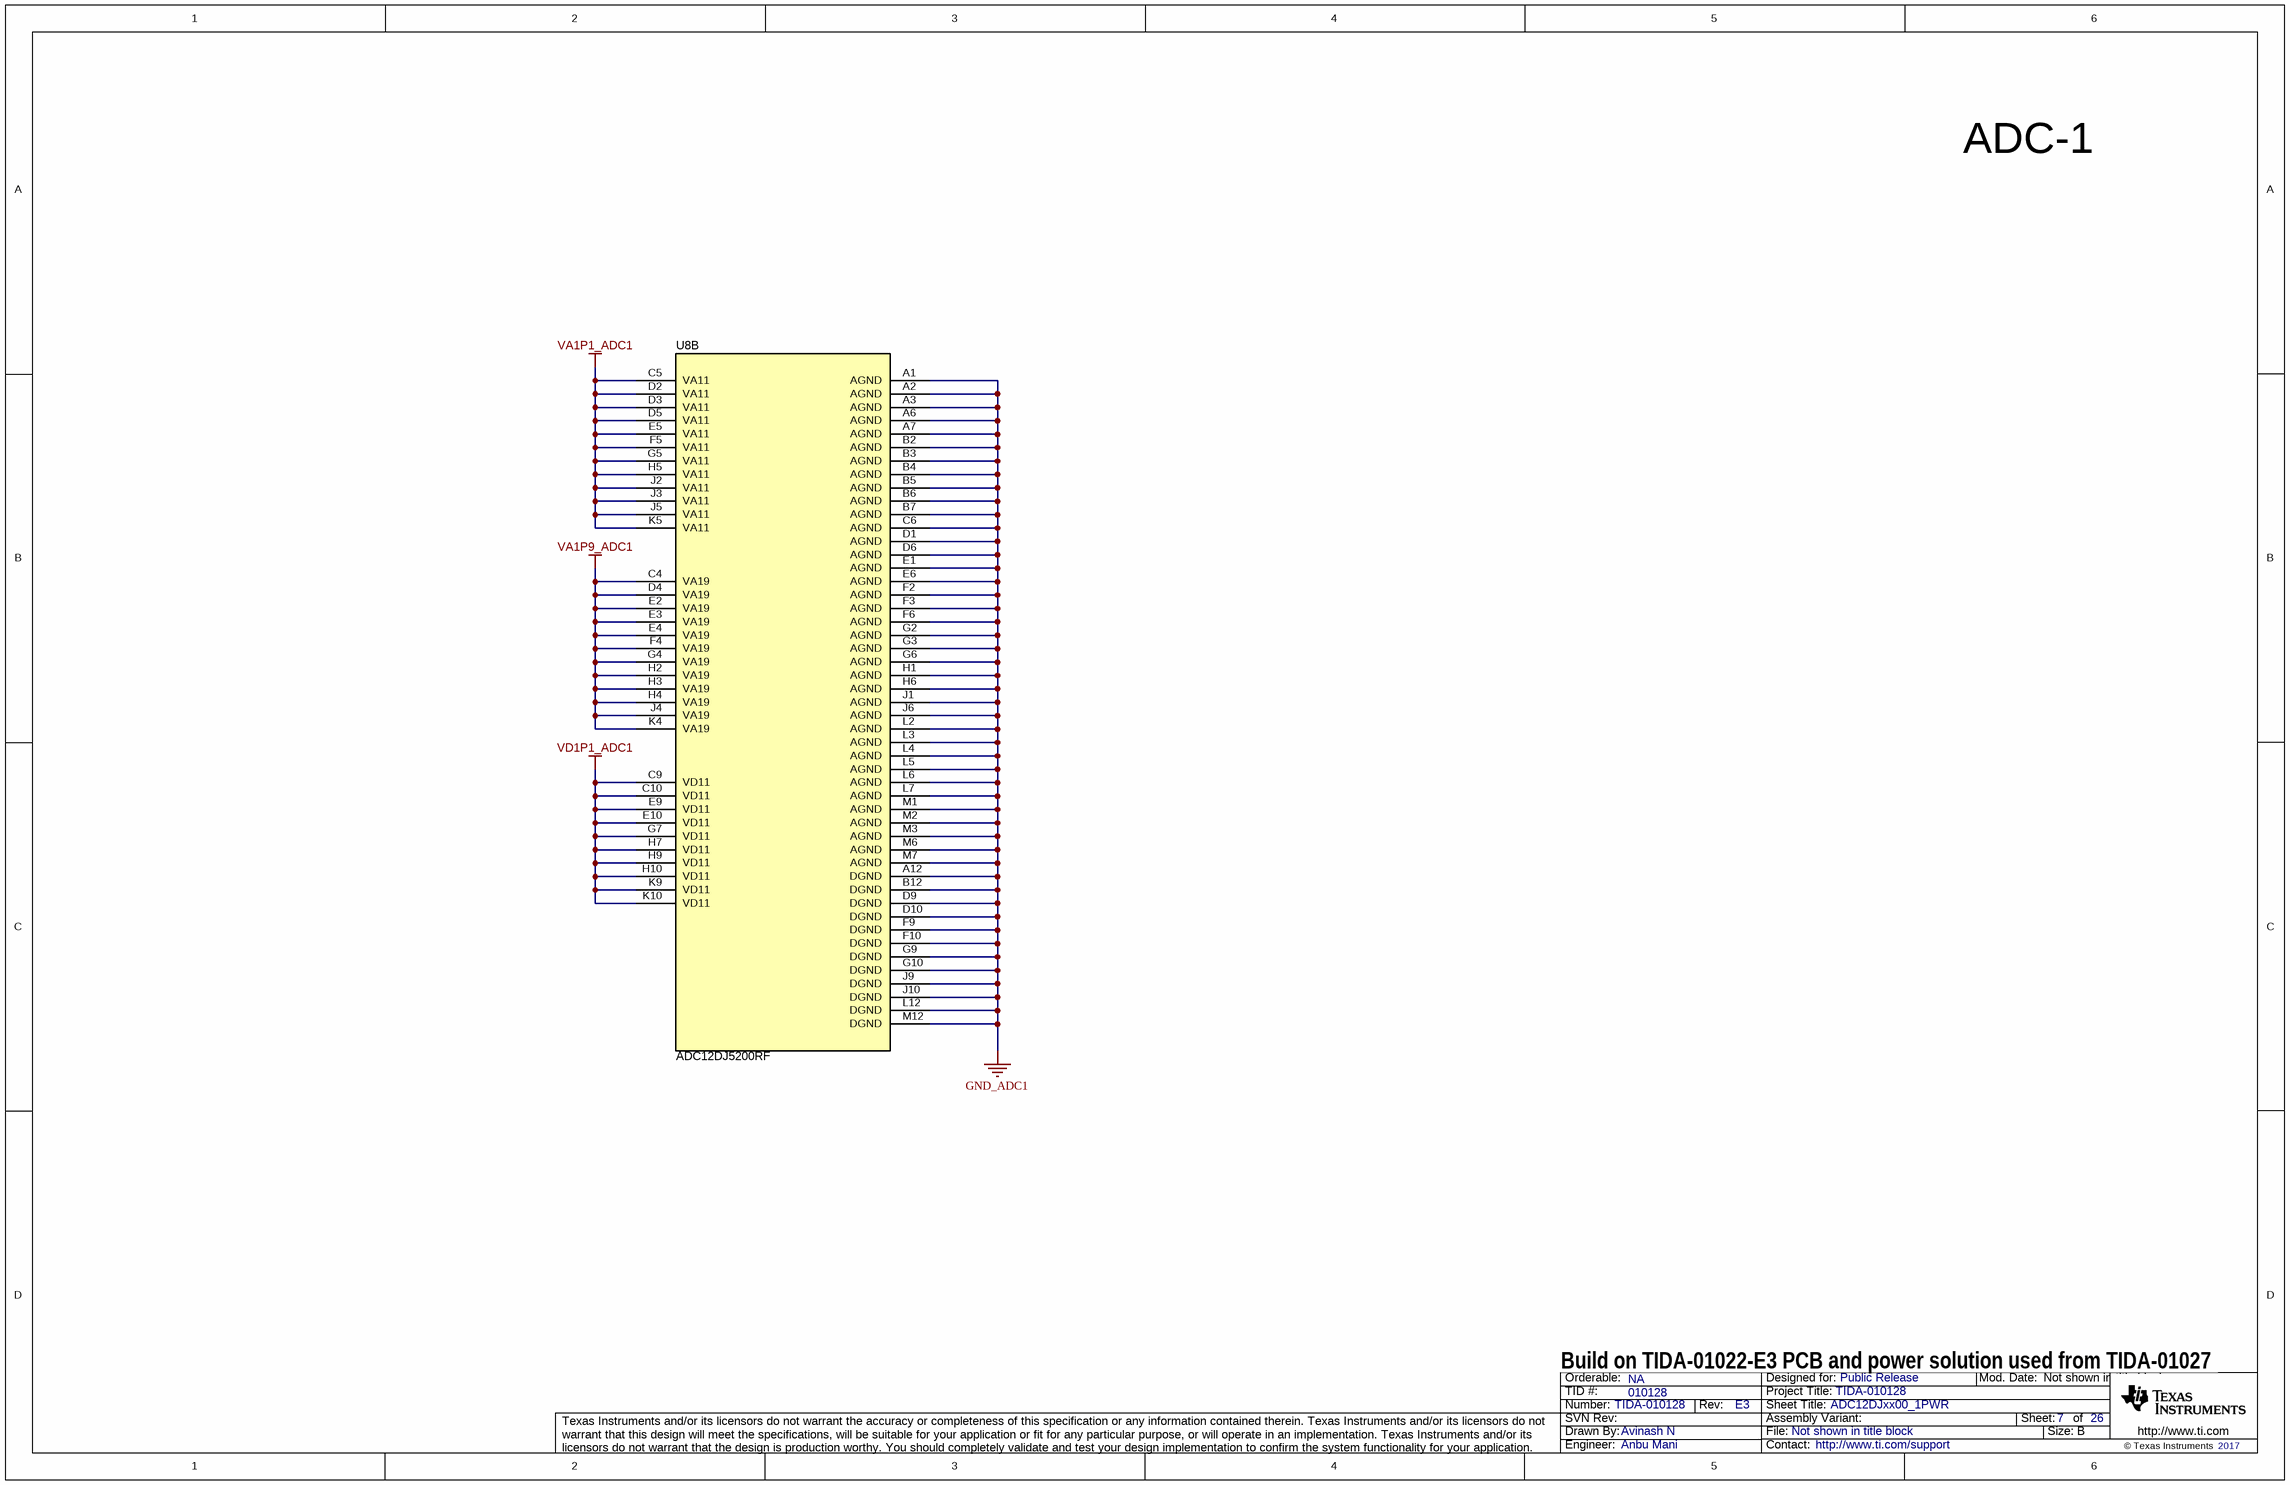
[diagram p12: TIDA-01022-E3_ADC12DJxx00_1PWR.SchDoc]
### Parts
U8  ADC12DJ5200RF  [AAV0144A]  (part B of 2)

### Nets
GND_ADC1: U8.A1(AGND) U8.A2(AGND) U8.A3(AGND) U8.A6(AGND) U8.A7(AGND) U8.A12(DGND) U8.B2(AGND) U8.B3(AGND) U8.B4(AGND) U8.B5(AGND) U8.B6(AGND) U8.B7(AGND) U8.B12(DGND) U8.C6(AGND) U8.D1(AGND) U8.D6(AGND) U8.D9(DGND) U8.D10(DGND) U8.E1(AGND) U8.E6(AGND) U8.F2(AGND) U8.F3(AGND) U8.F6(AGND) U8.F9(DGND) U8.F10(DGND) U8.G2(AGND) U8.G3(AGND) U8.G6(AGND) U8.G9(DGND) U8.G10(DGND) U8.H1(AGND) U8.H6(AGND) U8.J1(AGND) U8.J6(AGND) U8.J9(DGND) U8.J10(DGND) U8.L2(AGND) U8.L3(AGND) U8.L4(AGND) U8.L5(AGND) U8.L6(AGND) U8.L7(AGND) U8.L12(DGND) U8.M1(AGND) U8.M2(AGND) U8.M3(AGND) U8.M6(AGND) U8.M7(AGND) U8.M12(DGND)  [project net DGND]
VA1P1_ADC1: U8.C5(VA11) U8.D2(VA11) U8.D3(VA11) U8.D5(VA11) U8.E5(VA11) U8.F5(VA11) U8.G5(VA11) U8.H5(VA11) U8.J2(VA11) U8.J3(VA11) U8.J5(VA11) U8.K5(VA11)
VA1P9_ADC1: U8.C4(VA19) U8.D4(VA19) U8.E2(VA19) U8.E3(VA19) U8.E4(VA19) U8.F4(VA19) U8.G4(VA19) U8.H2(VA19) U8.H3(VA19) U8.H4(VA19) U8.J4(VA19) U8.K4(VA19)
VD1P1_ADC1: U8.C9(VD11) U8.C10(VD11) U8.E9(VD11) U8.E10(VD11) U8.G7(VD11) U8.H7(VD11) U8.H9(VD11) U8.H10(VD11) U8.K9(VD11) U8.K10(VD11)

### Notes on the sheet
- ADC-1
- Build on TIDA-01022-E3 PCB and power solution used from TIDA-01027

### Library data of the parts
U8 = ADC12DJ3200AAVR: as U8 on sheet TIDA-01022-E3_ADC12DJxx00_1

## Sheet TIDA-01022-E3_ADC12DJxx00_2.SchDoc: ADC12DJxx00_2
size 431 x 279 mm; Date: Not shown in title block; ApprovedBy: Not shown in title block; CheckedBy: Not shown in title block; Author: Not shown in title block; CompanyName: Not shown in title block; DrawnBy: Avinash N; Engineer: Not shown in title block; Organization: Not shown in title block; Address1: Not shown in title block; Address2: Not shown in title block; Address3: Not shown in title block; Address4: Not shown in title block; DocumentNumber: 1; Revision: Use project parameter SCH_Rev; SheetNumber: 8; SheetTotal: 26; PageSetup: Record=PageOptions¦CenterHorizontal=True¦CenterVertical=True¦PrintScale=1.00¦XCorrection=1.00¦YCorrection=1.00¦PrintKind=0¦BorderSize=5000000¦LeftOffset=0¦BottomOffset=0¦Orientation=2¦PaperLength=1000¦PaperWidth=1000¦Scale=100¦PaperSource=15¦PrintQuality=600¦MediaType=1¦DitherType=10¦PaperKind=Letter¦PrintScaleMode=1

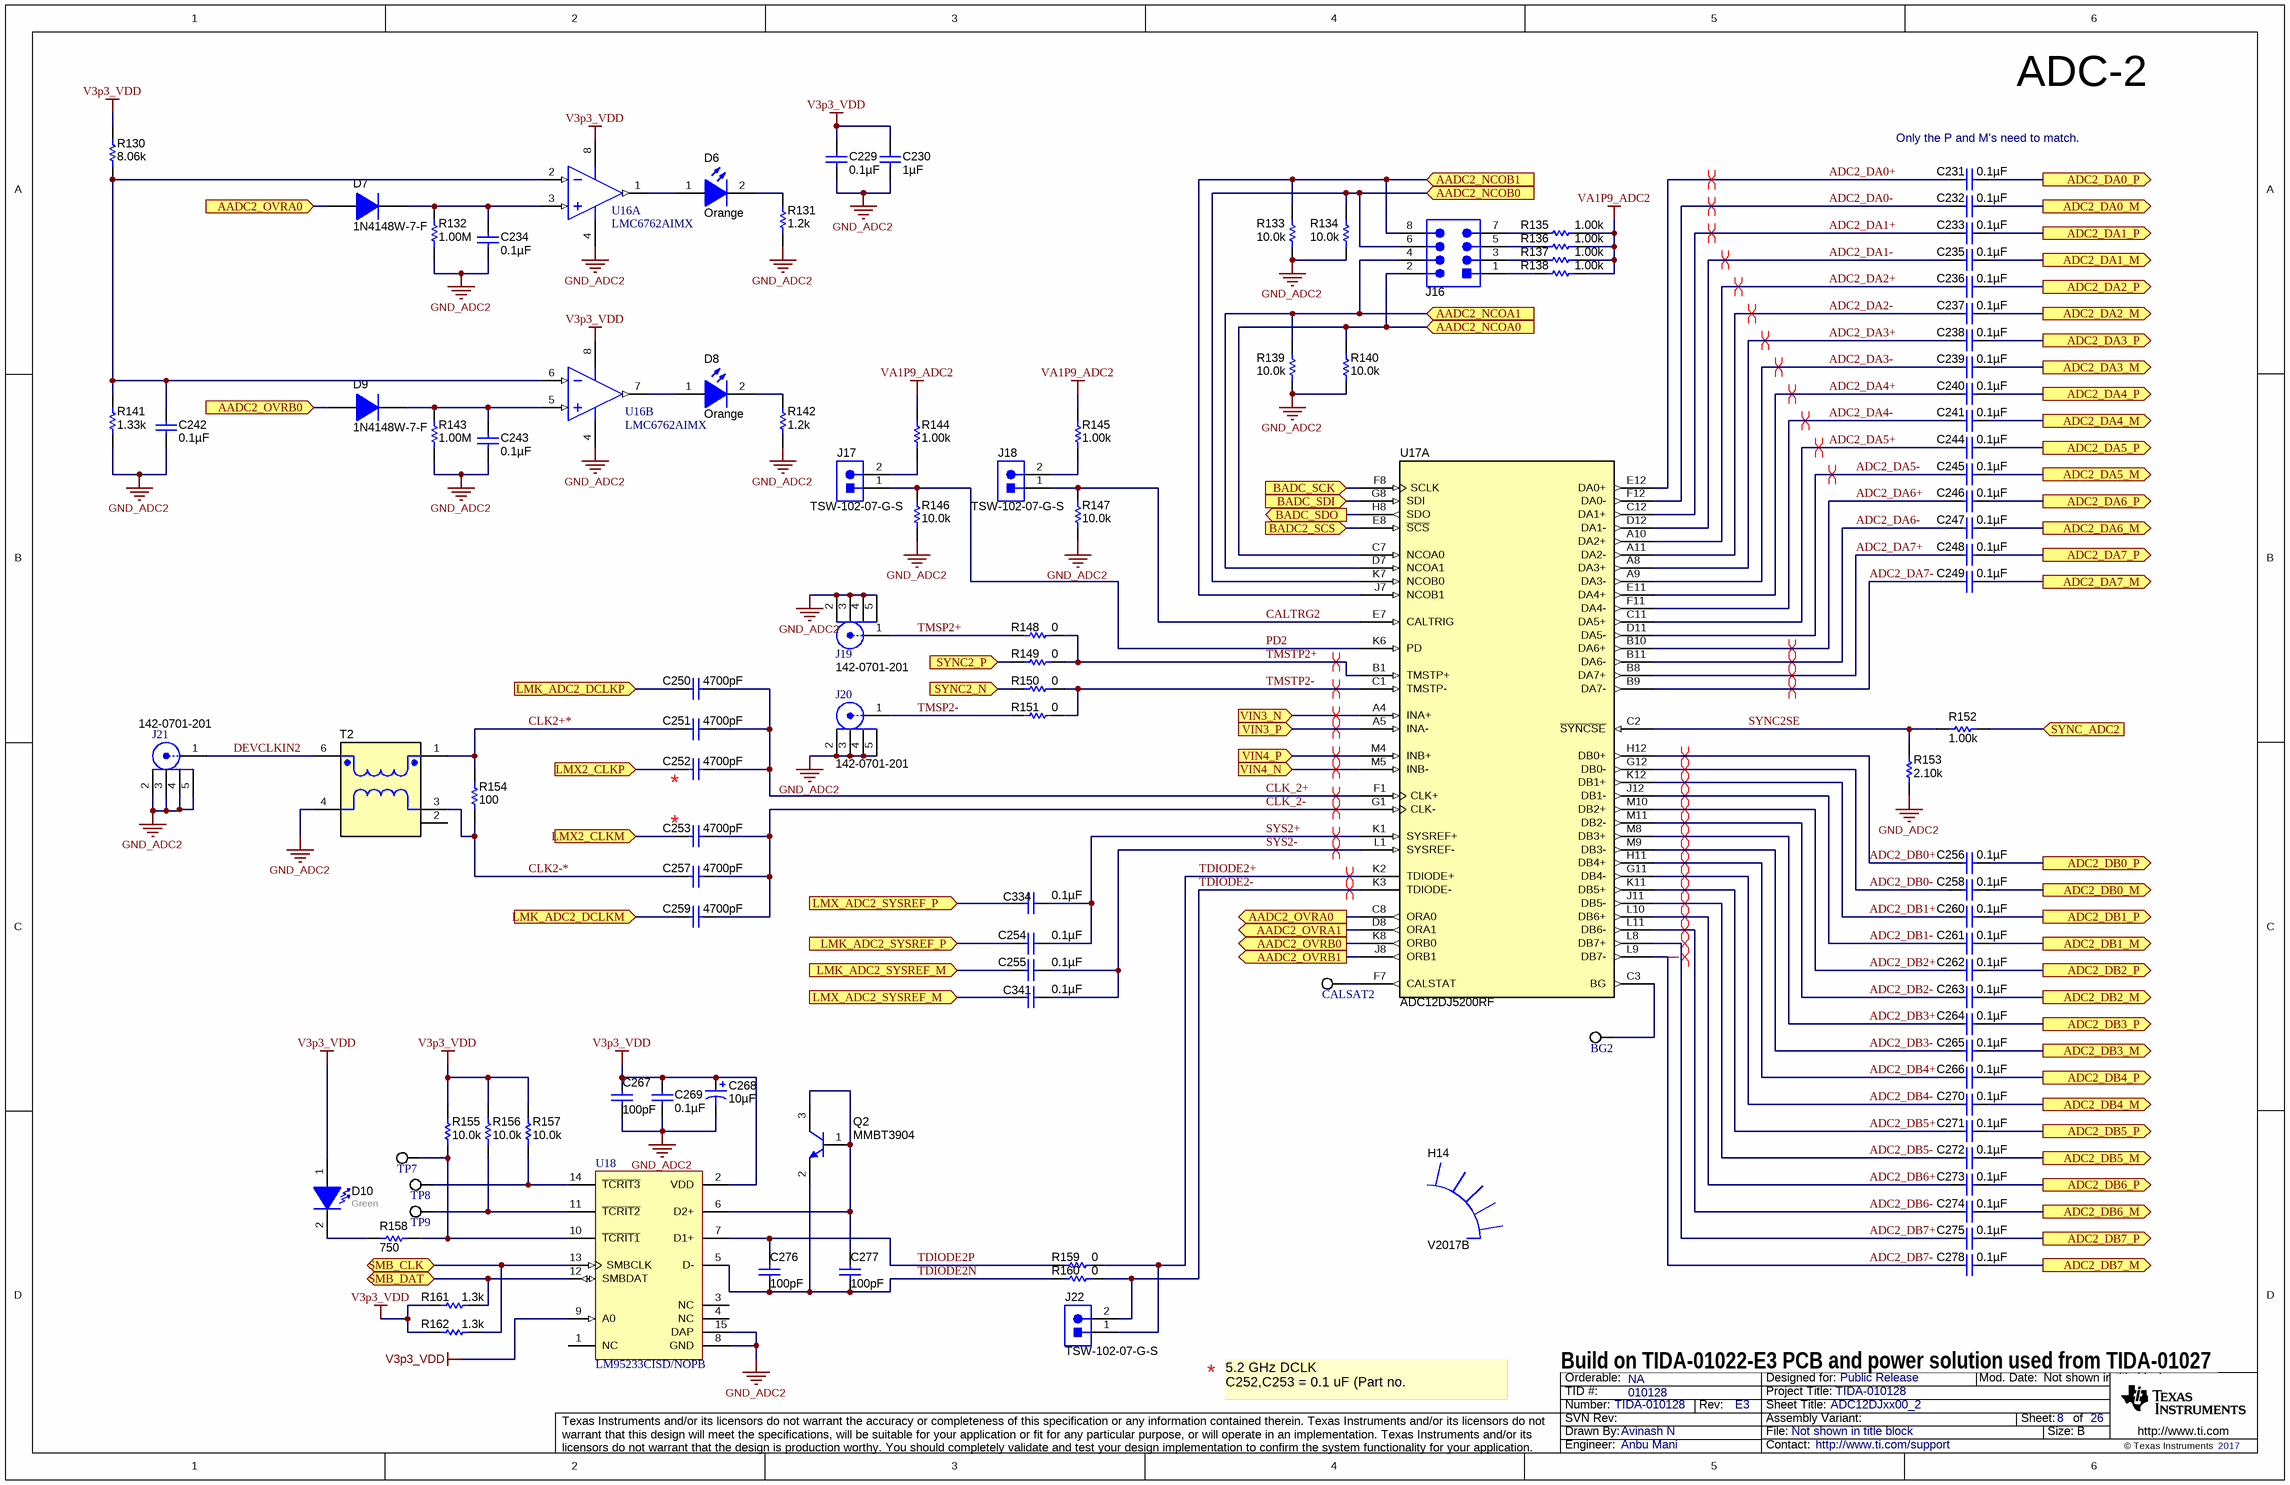
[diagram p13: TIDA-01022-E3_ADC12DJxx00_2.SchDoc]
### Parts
BG2  5002  [Keystone5002]  (value not drawn)
C229  ValueDisplayed: 0.1µF  [0402]  (hidden comment: C1005X7R1E104M050BB)
C230  ValueDisplayed: 1µF  [0603]  (hidden comment: C1608X5R1A105K080AC)
C231  ValueDisplayed: 0.1µF  [0201_adc]  (hidden comment: GRM033C71A104KE14D)
C232  ValueDisplayed: 0.1µF  [0201_adc]  (hidden comment: GRM033C71A104KE14D)
C233  ValueDisplayed: 0.1µF  [0201_adc]  (hidden comment: GRM033C71A104KE14D)
C234  ValueDisplayed: 0.1µF  [0402]  (hidden comment: C1005X7R1E104M050BB)
C235  ValueDisplayed: 0.1µF  [0201_adc]  (hidden comment: GRM033C71A104KE14D)
C236  ValueDisplayed: 0.1µF  [0201_adc]  (hidden comment: GRM033C71A104KE14D)
C237  ValueDisplayed: 0.1µF  [0201_adc]  (hidden comment: GRM033C71A104KE14D)
C238  ValueDisplayed: 0.1µF  [0201_adc]  (hidden comment: GRM033C71A104KE14D)
C239  ValueDisplayed: 0.1µF  [0201_adc]  (hidden comment: GRM033C71A104KE14D)
C240  ValueDisplayed: 0.1µF  [0201_adc]  (hidden comment: GRM033C71A104KE14D)
C241  ValueDisplayed: 0.1µF  [0201_adc]  (hidden comment: GRM033C71A104KE14D)
C242  ValueDisplayed: 0.1µF  [0402]  (hidden comment: C1005X7R1E104M050BB)
C243  ValueDisplayed: 0.1µF  [0402]  (hidden comment: C1005X7R1E104M050BB)
C244  ValueDisplayed: 0.1µF  [0201_adc]  (hidden comment: GRM033C71A104KE14D)
C245  ValueDisplayed: 0.1µF  [0201_adc]  (hidden comment: GRM033C71A104KE14D)
C246  ValueDisplayed: 0.1µF  [0201_adc]  (hidden comment: GRM033C71A104KE14D)
C247  ValueDisplayed: 0.1µF  [0201_adc]  (hidden comment: GRM033C71A104KE14D)
C248  ValueDisplayed: 0.1µF  [0201_adc]  (hidden comment: GRM033C71A104KE14D)
C249  ValueDisplayed: 0.1µF  [0201_adc]  (hidden comment: GRM033C71A104KE14D)
C250  ValueDisplayed: 4700pF  [0402]  (hidden comment: GRM155R71H472KA01D)
C251  ValueDisplayed: 4700pF  [0402]  (hidden comment: GRM155R71H472KA01D)
C252  ValueDisplayed: 4700pF  [0402]  (hidden comment: GRM155R71H472KA01D)
C253  ValueDisplayed: 4700pF  [0402]  (hidden comment: GRM155R71H472KA01D)
C254  ValueDisplayed: 0.1µF  [0402]  (hidden comment: C1005X7R1E104M050BB)
C255  ValueDisplayed: 0.1µF  [0402]  (hidden comment: C1005X7R1E104M050BB)
C256  ValueDisplayed: 0.1µF  [0201_adc]  (hidden comment: GRM033C71A104KE14D)
C257  ValueDisplayed: 4700pF  [0402]  (hidden comment: GRM155R71H472KA01D)
C258  ValueDisplayed: 0.1µF  [0201_adc]  (hidden comment: GRM033C71A104KE14D)
C259  ValueDisplayed: 4700pF  [0402]  (hidden comment: GRM155R71H472KA01D)
C260  ValueDisplayed: 0.1µF  [0201_adc]  (hidden comment: GRM033C71A104KE14D)
C261  ValueDisplayed: 0.1µF  [0201_adc]  (hidden comment: GRM033C71A104KE14D)
C262  ValueDisplayed: 0.1µF  [0201_adc]  (hidden comment: GRM033C71A104KE14D)
C263  ValueDisplayed: 0.1µF  [0201_adc]  (hidden comment: GRM033C71A104KE14D)
C264  ValueDisplayed: 0.1µF  [0201_adc]  (hidden comment: GRM033C71A104KE14D)
C265  ValueDisplayed: 0.1µF  [0201_adc]  (hidden comment: GRM033C71A104KE14D)
C266  ValueDisplayed: 0.1µF  [0201_adc]  (hidden comment: GRM033C71A104KE14D)
C267  ValueDisplayed: 100pF  [0402]  (hidden comment: GRM1555C1H101JA01D)
C268  ValueDisplayed: 10µF  [3528-21]  (hidden comment: 293D106X0010B2TE3)
C269  ValueDisplayed: 0.1µF  [0402]  (hidden comment: C1005X7R1E104M050BB)
C270  ValueDisplayed: 0.1µF  [0201_adc]  (hidden comment: GRM033C71A104KE14D)
C271  ValueDisplayed: 0.1µF  [0201_adc]  (hidden comment: GRM033C71A104KE14D)
C272  ValueDisplayed: 0.1µF  [0201_adc]  (hidden comment: GRM033C71A104KE14D)
C273  ValueDisplayed: 0.1µF  [0201_adc]  (hidden comment: GRM033C71A104KE14D)
C274  ValueDisplayed: 0.1µF  [0201_adc]  (hidden comment: GRM033C71A104KE14D)
C275  ValueDisplayed: 0.1µF  [0201_adc]  (hidden comment: GRM033C71A104KE14D)
C276  ValueDisplayed: 100pF  [0402]  (hidden comment: GRM1555C1H101JA01D)
C277  ValueDisplayed: 100pF  [0402]  (hidden comment: GRM1555C1H101JA01D)
C278  ValueDisplayed: 0.1µF  [0201_adc]  (hidden comment: GRM033C71A104KE14D)
C334  ValueDisplayed: 0.1µF  [0402]  (hidden comment: C1005X7R1E104M050BB)
C341  ValueDisplayed: 0.1µF  [0402]  (hidden comment: C1005X7R1E104M050BB)
CALSAT2  5002  [Keystone5002]  (value not drawn)
D6  value Orange  [LED_LTST-C190]  (hidden comment: LTST-C190KFKT)
D7  1N4148W-7-F  [SOD-123]
D8  value Orange  [LED_LTST-C190]  (hidden comment: LTST-C190KFKT)
D9  1N4148W-7-F  [SOD-123]
D10  value Green  [LED_LTST-C190]  (hidden comment: LTST-C190GKT)
H14  V2017B  [ASMN_V2017B]  (mechanical)
J16  TSW-104-07-G-D  [TSW-104-07-G-D]  (value not drawn)
J17  TSW-102-07-G-S  [TSW-102-07-G-S]
J18  TSW-102-07-G-S  [TSW-102-07-G-S]
J19  142-0701-201  [Johnson_142-0701-20x]
J20  142-0701-201  [Johnson_142-0701-20x]
J21  142-0701-201  [Johnson_142-0701-20x]
J22  TSW-102-07-G-S  [TSW-102-07-G-S]
Q2  MMBT3904  [SOT-23]
R130  ValueDisplayed: 8.06k  [0402]  (hidden comment: CRCW04028K06FKED)
R131  ValueDisplayed: 1.2k  [0402]  (hidden comment: CRCW04021K20JNED)
R132  ValueDisplayed: 1.00M  [0402]  (hidden comment: ERJ-2RKF1004X)
R133  ValueDisplayed: 10.0k  [0402]  (hidden comment: ERJ-2RKF1002X)
R134  ValueDisplayed: 10.0k  [0402]  (hidden comment: ERJ-2RKF1002X)
R135  ValueDisplayed: 1.00k  [0402]  (hidden comment: ERJ-2RKF1001X)
R136  ValueDisplayed: 1.00k  [0402]  (hidden comment: ERJ-2RKF1001X)
R137  ValueDisplayed: 1.00k  [0402]  (hidden comment: ERJ-2RKF1001X)
R138  ValueDisplayed: 1.00k  [0402]  (hidden comment: ERJ-2RKF1001X)
R139  ValueDisplayed: 10.0k  [0402]  (hidden comment: ERJ-2RKF1002X)
R140  ValueDisplayed: 10.0k  [0402]  (hidden comment: ERJ-2RKF1002X)
R141  ValueDisplayed: 1.33k  [0402]  (hidden comment: CRCW04021K33FKED)
R142  ValueDisplayed: 1.2k  [0402]  (hidden comment: CRCW04021K20JNED)
R143  ValueDisplayed: 1.00M  [0402]  (hidden comment: ERJ-2RKF1004X)
R144  ValueDisplayed: 1.00k  [0402]  (hidden comment: ERJ-2RKF1001X)
R145  ValueDisplayed: 1.00k  [0402]  (hidden comment: ERJ-2RKF1001X)
R146  ValueDisplayed: 10.0k  [0402]  (hidden comment: ERJ-2RKF1002X)
R147  ValueDisplayed: 10.0k  [0402]  (hidden comment: ERJ-2RKF1002X)
R148  ValueDisplayed: 0  [0402]  (hidden comment: CRCW04020000Z0ED)
R149  ValueDisplayed: 0  [0402]  (hidden comment: CRCW04020000Z0ED)
R150  ValueDisplayed: 0  [0402]  (hidden comment: CRCW04020000Z0ED)
R151  ValueDisplayed: 0  [0402]  (hidden comment: CRCW04020000Z0ED)
R152  ValueDisplayed: 1.00k  [0402]  (hidden comment: ERJ-2RKF1001X)
R153  ValueDisplayed: 2.10k  [0402]  (hidden comment: CRCW04022K10FKED)
R154  ValueDisplayed: 100  [0402]  (hidden comment: CRCW0402100RFKED)
R155  ValueDisplayed: 10.0k  [0402]  (hidden comment: ERJ-2RKF1002X)
R156  ValueDisplayed: 10.0k  [0402]  (hidden comment: ERJ-2RKF1002X)
R157  ValueDisplayed: 10.0k  [0402]  (hidden comment: ERJ-2RKF1002X)
R158  ValueDisplayed: 750  [0603]  (hidden comment: CRCW0603750RJNEA)
R159  ValueDisplayed: 0  [0402]  (hidden comment: CRCW04020000Z0ED)
R160  ValueDisplayed: 0  [0402]  (hidden comment: CRCW04020000Z0ED)
R161  ValueDisplayed: 1.3k  [0603]  (hidden comment: RC0603JR-071K3L)
R162  ValueDisplayed: 1.3k  [0603]  (hidden comment: RC0603JR-071K3L)
T2  TC1-1-43X+  [MNC_AT1521]  (value not drawn)
TP7  5002  [Keystone5002]  (value not drawn)
TP8  5002  [Keystone5002]  (value not drawn)
TP9  5002  [Keystone5002]  (value not drawn)
U16  LMC6762AIMX  [M08A_N]  (parts A,B of 2)
U17  ADC12DJ5200RF  [AAV0144A]  (part A of 2)
U18  LM95233CISD/NOPB  [SDA14B]

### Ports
AADC2_NCOA0 (in), AADC2_NCOA1 (in), AADC2_NCOB0 (in), AADC2_NCOB1 (in), AADC2_OVRA0 (in), AADC2_OVRA0 (out), AADC2_OVRA1 (out), AADC2_OVRB0 (in), AADC2_OVRB0 (out), AADC2_OVRB1 (out), ADC2_DA0_M (out), ADC2_DA0_P (out), ADC2_DA1_M (out), ADC2_DA1_P (out), ADC2_DA2_M (out), ADC2_DA2_P (out), ADC2_DA3_M (out), ADC2_DA3_P (out), ADC2_DA4_M (out), ADC2_DA4_P (out), ADC2_DA5_M (out), ADC2_DA5_P (out), ADC2_DA6_M (out), ADC2_DA6_P (out), ADC2_DA7_M (out), ADC2_DA7_P (out), ADC2_DB0_M (out), ADC2_DB0_P (out), ADC2_DB1_M (out), ADC2_DB1_P (out), ADC2_DB2_M (out), ADC2_DB2_P (out), ADC2_DB3_M (out), ADC2_DB3_P (out), ADC2_DB4_M (out), ADC2_DB4_P (out), ADC2_DB5_M (out), ADC2_DB5_P (out), ADC2_DB6_M (out), ADC2_DB6_P (out), ADC2_DB7_M (out), ADC2_DB7_P (out), BADC2_SCS (in), BADC_SCK (in), BADC_SDI (in), BADC_SDO (out), LMK_ADC2_DCLKM (in), LMK_ADC2_DCLKP (in), LMK_ADC2_SYSREF_M (in), LMK_ADC2_SYSREF_P (in), LMX2_CLKM (in), LMX2_CLKP (in), LMX_ADC2_SYSREF_M (in), LMX_ADC2_SYSREF_P (in), SMB_CLK (bidir), SMB_DAT (bidir), SYNC2_N (in), SYNC2_P (in), SYNC_ADC2 (in), VIN3_N (in), VIN3_P (in), VIN4_N (in), VIN4_P (in)

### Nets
GND_ADC2: C229.1 C230.2 C234.1 C242.1 C243.1 C267.2 C268.2(-) C269.2 J19.2 J19.3 J19.4 J19.5 J20.2 J20.3 J20.4 J20.5 J21.2 J21.3 J21.4 J21.5 R131.1 R132.1 R133.2 R134.2 R139.2 R140.2 R141.1 R142.1 R143.1 R146.1 R147.1 R153.1 T2.4 U16.4(V-) U18.8(GND) U18.15(DAP)  [project net DGND]
V3p3_VDD: C229.2 C230.1 C267.1 C268.1(+) C269.1 D10.1(A) R130.2 R155.2 R156.2 R157.2 R161.2 R162.2 U16.8(V+) U18.2(VDD) U18.9(A0)
VA1P9_ADC2: R135.1 R136.1 R137.1 R138.1 R144.2 R145.2
AADC2_NCOA0: J16.2 R140.1 U17.C7(NCOA0) ; port AADC2_NCOA0
AADC2_NCOA1: J16.4 R139.1 U17.D7(NCOA1) ; port AADC2_NCOA1
AADC2_NCOB0: J16.6 R134.1 U17.K7(NCOB0) ; port AADC2_NCOB0
AADC2_NCOB1: J16.8 R133.1 U17.J7(NCOB1) ; port AADC2_NCOB1
AADC2_OVRA0: D7.2(A) U17.C8(ORA0) ; port AADC2_OVRA0
AADC2_OVRA1: U17.D8(ORA1) ; port AADC2_OVRA1
AADC2_OVRB0: D9.2(A) U17.K8(ORB0) ; port AADC2_OVRB0
AADC2_OVRB1: U17.J8(ORB1) ; port AADC2_OVRB1
ADC2_DA0+: C231.1 U17.E12(DA0+)
ADC2_DA0-: C232.1 U17.F12(DA0-)
ADC2_DA0_M: C232.2 ; port ADC2_DA0_M
ADC2_DA0_P: C231.2 ; port ADC2_DA0_P
ADC2_DA1+: C233.1 U17.C12(DA1+)
ADC2_DA1-: C235.1 U17.D12(DA1-)
ADC2_DA1_M: C235.2 ; port ADC2_DA1_M
ADC2_DA1_P: C233.2 ; port ADC2_DA1_P
ADC2_DA2+: C236.1 U17.A10(DA2+)
ADC2_DA2-: C237.1 U17.A11(DA2-)
ADC2_DA2_M: C237.2 ; port ADC2_DA2_M
ADC2_DA2_P: C236.2 ; port ADC2_DA2_P
ADC2_DA3+: C238.1 U17.A8(DA3+)
ADC2_DA3-: C239.1 U17.A9(DA3-)
ADC2_DA3_M: C239.2 ; port ADC2_DA3_M
ADC2_DA3_P: C238.2 ; port ADC2_DA3_P
ADC2_DA4+: C240.1 U17.E11(DA4+)
ADC2_DA4-: C241.1 U17.F11(DA4-)
ADC2_DA4_M: C241.2 ; port ADC2_DA4_M
ADC2_DA4_P: C240.2 ; port ADC2_DA4_P
ADC2_DA5+: C244.1 U17.C11(DA5+)
ADC2_DA5-: C245.1 U17.D11(DA5-)
ADC2_DA5_M: C245.2 ; port ADC2_DA5_M
ADC2_DA5_P: C244.2 ; port ADC2_DA5_P
ADC2_DA6+: C246.1 U17.B10(DA6+)
ADC2_DA6-: C247.1 U17.B11(DA6-)
ADC2_DA6_M: C247.2 ; port ADC2_DA6_M
ADC2_DA6_P: C246.2 ; port ADC2_DA6_P
ADC2_DA7+: C248.1 U17.B8(DA7+)
ADC2_DA7-: C249.1 U17.B9(DA7-)
ADC2_DA7_M: C249.2 ; port ADC2_DA7_M
ADC2_DA7_P: C248.2 ; port ADC2_DA7_P
ADC2_DB0+: C256.1 U17.H12(DB0+)
ADC2_DB0-: C258.1 U17.G12(DB0-)
ADC2_DB0_M: C258.2 ; port ADC2_DB0_M
ADC2_DB0_P: C256.2 ; port ADC2_DB0_P
ADC2_DB1+: C260.1 U17.K12(DB1+)
ADC2_DB1-: C261.1 U17.J12(DB1-)
ADC2_DB1_M: C261.2 ; port ADC2_DB1_M
ADC2_DB1_P: C260.2 ; port ADC2_DB1_P
ADC2_DB2+: C262.1 U17.M10(DB2+)
ADC2_DB2-: C263.1 U17.M11(DB2-)
ADC2_DB2_M: C263.2 ; port ADC2_DB2_M
ADC2_DB2_P: C262.2 ; port ADC2_DB2_P
ADC2_DB3+: C264.1 U17.M8(DB3+)
ADC2_DB3-: C265.1 U17.M9(DB3-)
ADC2_DB3_M: C265.2 ; port ADC2_DB3_M
ADC2_DB3_P: C264.2 ; port ADC2_DB3_P
ADC2_DB4+: C266.1 U17.H11(DB4+)
ADC2_DB4-: C270.1 U17.G11(DB4-)
ADC2_DB4_M: C270.2 ; port ADC2_DB4_M
ADC2_DB4_P: C266.2 ; port ADC2_DB4_P
ADC2_DB5+: C271.1 U17.K11(DB5+)
ADC2_DB5-: C272.1 U17.J11(DB5-)
ADC2_DB5_M: C272.2 ; port ADC2_DB5_M
ADC2_DB5_P: C271.2 ; port ADC2_DB5_P
ADC2_DB6+: C273.1 U17.L10(DB6+)
ADC2_DB6-: C274.1 U17.L11(DB6-)
ADC2_DB6_M: C274.2 ; port ADC2_DB6_M
ADC2_DB6_P: C273.2 ; port ADC2_DB6_P
ADC2_DB7+: C275.1 U17.L8(DB7+)
ADC2_DB7-: C278.1 U17.L9(DB7-)
ADC2_DB7_M: C278.2 ; port ADC2_DB7_M
ADC2_DB7_P: C275.2 ; port ADC2_DB7_P
BADC2_SCS: U17.E8(~{SCS}) ; port BADC2_SCS
BADC_SCK: U17.F8(SCLK) ; port BADC_SCK
BADC_SDI: U17.G8(SDI) ; port BADC_SDI
BADC_SDO: U17.H8(SDO) ; port BADC_SDO
CALTRG2: J18.1 R147.2 U17.E7(CALTRIG)
CLK2+*: C251.2 R154.2 T2.1
CLK2-*: C257.2 R154.1 T2.3
CLK_2+: C250.1 C251.1 C252.1 U17.F1(CLK+)
CLK_2-: C253.1 C257.1 C259.1 U17.G1(CLK-)
DEVCLKIN2: J21.1 T2.6
LMK_ADC2_DCLKM: C259.2 ; port LMK_ADC2_DCLKM
LMK_ADC2_DCLKP: C250.2 ; port LMK_ADC2_DCLKP
LMK_ADC2_SYSREF_M: C255.1 ; port LMK_ADC2_SYSREF_M
LMK_ADC2_SYSREF_P: C254.1 ; port LMK_ADC2_SYSREF_P
LMX2_CLKM: C253.2 ; port LMX2_CLKM
LMX2_CLKP: C252.2 ; port LMX2_CLKP
LMX_ADC2_SYSREF_M: C341.1 ; port LMX_ADC2_SYSREF_M
LMX_ADC2_SYSREF_P: C334.1 ; port LMX_ADC2_SYSREF_P
PD2: J17.1 R146.2 U17.K6(PD)
SMB_CLK: R162.1 U18.13(SMBCLK) ; port SMB_CLK
SMB_DAT: R161.1 U18.12(SMBDAT) ; port SMB_DAT
SYNC2_N: R150.1 ; port SYNC2_N
SYNC2_P: R149.1 ; port SYNC2_P
SYNC2SE: R152.1 R153.2 U17.C2(~{SYNCSE})
SYNC_ADC2: R152.2 ; port SYNC_ADC2
SYS2+: C254.2 C334.2 U17.K1(SYSREF+)
SYS2-: C255.2 C341.2 U17.L1(SYSREF-)
TDIODE2+: J22.1 R159.2 U17.K2(TDIODE+)
TDIODE2-: J22.2 R160.2 U17.K3(TDIODE-)
TDIODE2N: C276.2 C277.2 Q2.2(E) R160.1 U18.5(D-)
TDIODE2P: C276.1 R159.1 U18.7(D1+)
TMSP2+: J19.1 R148.1
TMSP2-: J20.1 R151.1
TMSTP2+: R148.2 R149.2 U17.B1(TMSTP+)
TMSTP2-: R150.2 R151.2 U17.C1(TMSTP-)
VIN3_N: U17.A4(INA+) ; port VIN3_N
VIN3_P: U17.A5(INA-) ; port VIN3_P
VIN4_N: U17.M5(INB-) ; port VIN4_N
VIN4_P: U17.M4(INB+) ; port VIN4_P
NetBG2_1: BG2.1 U17.C3(BG)
NetC234_2: C234.2 D7.1(K) R132.2 U16.3(INA+)
NetC242_2: C242.2 R130.1 R141.2 U16.2(INA-) U16.6(INB-)
NetC243_2: C243.2 D9.1(K) R143.2 U16.5(INB+)
NetC277_1: C277.1 Q2.1(B) Q2.3(C) U18.6(D2+)
NetCALSAT2_1: CALSAT2.1 U17.F7(CALSTAT)
NetD6_1: D6.1(A) U16.1(OUTA)
NetD6_2: D6.2(K) R131.2
NetD8_1: D8.1(A) U16.7(OUTB)
NetD8_2: D8.2(K) R142.2
NetD10_2: D10.2(K) R158.2
NetJ16_1: J16.1 R138.2
NetJ16_3: J16.3 R137.2
NetJ16_5: J16.5 R136.2
NetJ16_7: J16.7 R135.2
NetJ17_2: J17.2 R144.1
NetJ18_2: J18.2 R145.1
NetR155_1: R155.1 R158.1 TP7.1 U18.10(~{TCRIT1})
NetR156_1: R156.1 TP9.1 U18.11(~{TCRIT2})
NetR157_1: R157.1 TP8.1 U18.14(~{TCRIT3})

Not connected (* = marked no-connect by the designer): T2 2; U18 1(NC) 3(NC) 4(NC)

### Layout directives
differential pair: ADC2_DA0+, ADC2_DA0-, ADC2_DA1+, ADC2_DA1-, ADC2_DA2+, ADC2_DA2-, ADC2_DA3+, ADC2_DA3-, ADC2_DA4+, ADC2_DA4-, ADC2_DA5+, ADC2_DA5-, ADC2_DA6+, ADC2_DA6-, ADC2_DA7+, ADC2_DA7-, ADC2_DB0+, ADC2_DB0-, ADC2_DB1+, ADC2_DB1-, ADC2_DB2+, ADC2_DB2-, ADC2_DB3+, ADC2_DB3-, ADC2_DB4+, ADC2_DB4-, ADC2_DB5+, ADC2_DB5-, ADC2_DB6+, ADC2_DB6-, ADC2_DB7+, ADC2_DB7-, CLK_2+, CLK_2-, SYS2+, SYS2-, TDIODE2+, TDIODE2-, TMSTP2+, TMSTP2-, VIN3_N, VIN3_P, VIN4_N, VIN4_P

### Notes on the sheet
- (near C231) Only the P and M's need to match.
- ADC-2
- (near C252) *
- (near C253) *
- *
- Build on TIDA-01022-E3 PCB and power solution used from TIDA-01027
- 5.2 GHz DCLK
  C252,C253 = 0.1 uF (Part no. 530Z104KT10T))

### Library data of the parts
BG2 CALSAT2 TP7-TP9 = 5002: as BG1 on sheet TIDA-01022-E3_ADC12DJxx00_1
C229 C234 C242 C243 C254 C255 C269 C334 C341 = C1005X7R1E104M050BB: as C69 on sheet TIDA-01022-E3_ADC12DJxx00_1
C230 = C1608X5R1A105K080AC: as C70 on sheet TIDA-01022-E3_ADC12DJxx00_1
C231-C233 C235-C241 C244-C249 C256 C258 C260-C266 C270-C275 C278 = GRM033C71A104KE14D: as C71 on sheet TIDA-01022-E3_ADC12DJxx00_1
C250-C253 C257 C259 = GRM155R71H472KA01D: as C90 on sheet TIDA-01022-E3_ADC12DJxx00_1
C267 C276 C277 = GRM1555C1H101JA01D: as C107 on sheet TIDA-01022-E3_ADC12DJxx00_1
C268 = 293D106X0010B2TE3: as C108 on sheet TIDA-01022-E3_ADC12DJxx00_1
D6 D8 = LTST-C190KFKT: as D1 on sheet TIDA-01022-E3_ADC12DJxx00_1
D7 D9 = 1N4148W-7-F: as D2 on sheet TIDA-01022-E3_ADC12DJxx00_1
D10 = LTST-C190GKT: as D5 on sheet TIDA-01022-E3_ADC12DJxx00_1
H14 = V2017B: as H13 on sheet TIDA-01022-E3_ADC12DJxx00_1
J16 = TSW-104-07-G-D: as J5 on sheet TIDA-01022-E3_ADC12DJxx00_1
J17 J18 J22 = TSW-102-07-G-S: as J6 on sheet TIDA-01022-E3_ADC12DJxx00_1
J19 J20 = 142-0701-201: as J8 on sheet TIDA-01022-E3_ADC12DJxx00_1
J21 = 142-0701-201: as J10 on sheet TIDA-01022-E3_ADC12DJxx00_1
Q2 = MMBT3904, Fairchild Semiconductor: as Q1 on sheet TIDA-01022-E3_ADC12DJxx00_1
R130 = CRCW04028K06FKED: as R49 on sheet TIDA-01022-E3_ADC12DJxx00_1
R131 R142 = CRCW04021K20JNED: as R50 on sheet TIDA-01022-E3_ADC12DJxx00_1
R132 R143 = ERJ-2RKF1004X: as R51 on sheet TIDA-01022-E3_ADC12DJxx00_1
R133 R134 R139 R140 R146 R147 R155-R157 = ERJ-2RKF1002X: as R52 on sheet TIDA-01022-E3_ADC12DJxx00_1
R135-R138 R144 R145 R152 = ERJ-2RKF1001X: as R54-R57 on sheet TIDA-01022-E3_ADC12DJxx00_1
R141 = CRCW04021K33FKED: as R60 on sheet TIDA-01022-E3_ADC12DJxx00_1
R148-R151 R159 R160 = CRCW04020000Z0ED: as R67-R70 on sheet TIDA-01022-E3_ADC12DJxx00_1
R153 = CRCW04022K10FKED: as R72 on sheet TIDA-01022-E3_ADC12DJxx00_1
R154 = CRCW0402100RFKED: as R73 on sheet TIDA-01022-E3_ADC12DJxx00_1
R158 = CRCW0603750RJNEA: as R77 on sheet TIDA-01022-E3_ADC12DJxx00_1
R161 R162 = RC0603JR-071K3L: as R80 on sheet TIDA-01022-E3_ADC12DJxx00_1
T2 = TC1-1-43X+: as T1 on sheet TIDA-01022-E3_ADC12DJxx00_1
U16 = LMC6762AIMX: Dual Micro-Power Rail-to-Rail Input CMOS Comparator with Push-Pull Output, 8-pin Narrow SOIC; Manufacturer: Texas Instruments; PackageTopMarking: NSZXTT*LMC67*62AIM; PowerWise: N
U17 = ADC12DJ3200AAVR: as U8 on sheet TIDA-01022-E3_ADC12DJxx00_1
U18 = LM95233CISD: Dual Remote Diode and Local Temperature Sensor with SMBus Interface and TruTherm Technology, 15-pin LLP; Manufacturer: Texas Instruments; PackageTopMarking: NS*UZXYTT*95233CI; PowerWise: Y; CompType: Temp Sensor IC

## Sheet TIDA-01022-E3_ADC12DJxx00_2PWR.SchDoc: ADC12DJxx00_1PWR
size 431 x 279 mm; Date: Not shown in title block; ApprovedBy: Not shown in title block; CheckedBy: Not shown in title block; Author: Not shown in title block; CompanyName: Not shown in title block; DrawnBy: Avinash N; Engineer: Not shown in title block; Organization: Not shown in title block; Address1: Not shown in title block; Address2: Not shown in title block; Address3: Not shown in title block; Address4: Not shown in title block; DocumentNumber: 1; Revision: Use project parameter SCH_Rev; SheetNumber: 9; SheetTotal: 26; PageSetup: Record=PageOptions¦CenterHorizontal=True¦CenterVertical=True¦PrintScale=1.00¦XCorrection=1.00¦YCorrection=1.00¦PrintKind=0¦BorderSize=5000000¦LeftOffset=0¦BottomOffset=0¦Orientation=2¦PaperLength=1000¦PaperWidth=1000¦Scale=100¦PaperSource=15¦PrintQuality=600¦MediaType=1¦DitherType=10¦PaperKind=Letter¦PrintScaleMode=1

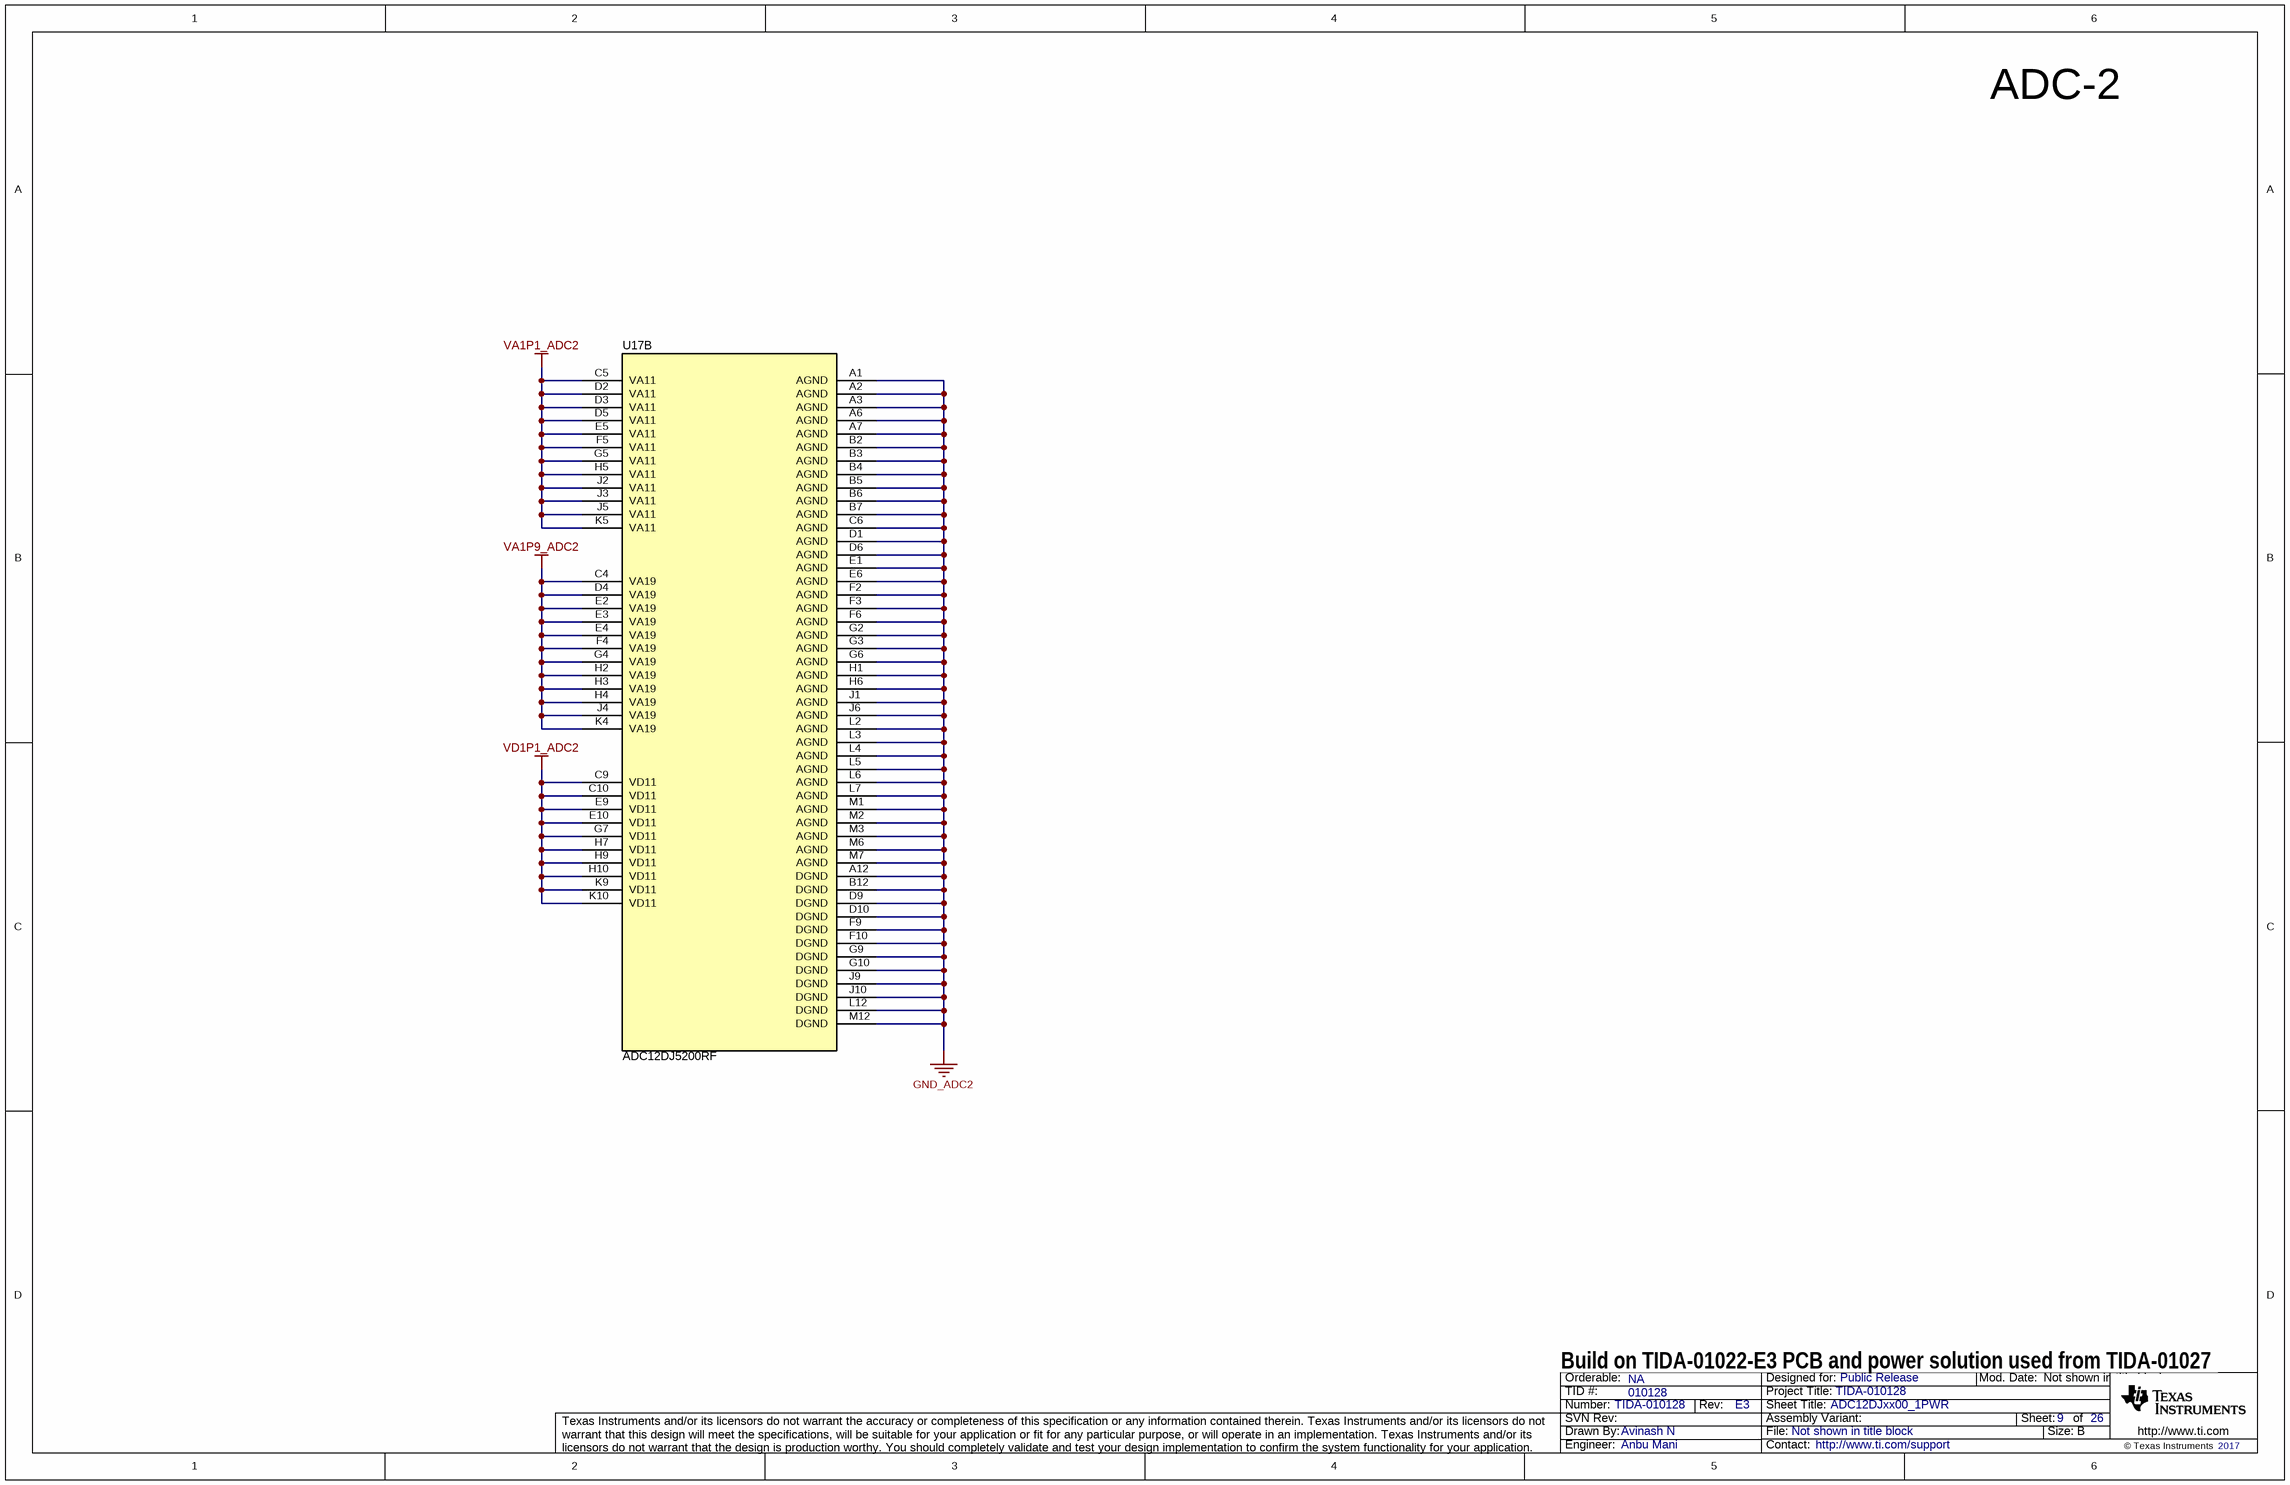
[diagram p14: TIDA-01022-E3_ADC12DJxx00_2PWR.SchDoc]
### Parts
U17  ADC12DJ5200RF  [AAV0144A]  (part B of 2)

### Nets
GND_ADC2: U17.A1(AGND) U17.A2(AGND) U17.A3(AGND) U17.A6(AGND) U17.A7(AGND) U17.A12(DGND) U17.B2(AGND) U17.B3(AGND) U17.B4(AGND) U17.B5(AGND) U17.B6(AGND) U17.B7(AGND) U17.B12(DGND) U17.C6(AGND) U17.D1(AGND) U17.D6(AGND) U17.D9(DGND) U17.D10(DGND) U17.E1(AGND) U17.E6(AGND) U17.F2(AGND) U17.F3(AGND) U17.F6(AGND) U17.F9(DGND) U17.F10(DGND) U17.G2(AGND) U17.G3(AGND) U17.G6(AGND) U17.G9(DGND) U17.G10(DGND) U17.H1(AGND) U17.H6(AGND) U17.J1(AGND) U17.J6(AGND) U17.J9(DGND) U17.J10(DGND) U17.L2(AGND) U17.L3(AGND) U17.L4(AGND) U17.L5(AGND) U17.L6(AGND) U17.L7(AGND) U17.L12(DGND) U17.M1(AGND) U17.M2(AGND) U17.M3(AGND) U17.M6(AGND) U17.M7(AGND) U17.M12(DGND)  [project net DGND]
VA1P1_ADC2: U17.C5(VA11) U17.D2(VA11) U17.D3(VA11) U17.D5(VA11) U17.E5(VA11) U17.F5(VA11) U17.G5(VA11) U17.H5(VA11) U17.J2(VA11) U17.J3(VA11) U17.J5(VA11) U17.K5(VA11)
VA1P9_ADC2: U17.C4(VA19) U17.D4(VA19) U17.E2(VA19) U17.E3(VA19) U17.E4(VA19) U17.F4(VA19) U17.G4(VA19) U17.H2(VA19) U17.H3(VA19) U17.H4(VA19) U17.J4(VA19) U17.K4(VA19)
VD1P1_ADC2: U17.C9(VD11) U17.C10(VD11) U17.E9(VD11) U17.E10(VD11) U17.G7(VD11) U17.H7(VD11) U17.H9(VD11) U17.H10(VD11) U17.K9(VD11) U17.K10(VD11)

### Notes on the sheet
- ADC-2
- Build on TIDA-01022-E3 PCB and power solution used from TIDA-01027

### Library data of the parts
U17 = ADC12DJ3200AAVR: as U8 on sheet TIDA-01022-E3_ADC12DJxx00_1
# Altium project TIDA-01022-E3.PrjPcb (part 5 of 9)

## Sheet TIDA-01022-E3_LMK0482x _PWR.SchDoc: LMK0482x_PWR
size 431 x 279 mm; Date: Not shown in title block; ApprovedBy: Not shown in title block; CheckedBy: Not shown in title block; Author: Not shown in title block; CompanyName: Not shown in title block; DrawnBy: Avinash N; Engineer: Not shown in title block; Organization: Not shown in title block; Address1: Not shown in title block; Address2: Not shown in title block; Address3: Not shown in title block; Address4: Not shown in title block; DocumentNumber: 1; Revision: Use project parameter SCH_Rev; SheetNumber: 14; SheetTotal: 26; PageSetup: Record=PageOptions¦CenterHorizontal=True¦CenterVertical=True¦PrintScale=1.00¦XCorrection=1.00¦YCorrection=1.00¦PrintKind=0¦BorderSize=5000000¦LeftOffset=0¦BottomOffset=0¦Orientation=2¦PaperLength=1000¦PaperWidth=1000¦Scale=100¦PaperSource=15¦PrintQuality=600¦MediaType=1¦DitherType=10¦PaperKind=Letter¦PrintScaleMode=1

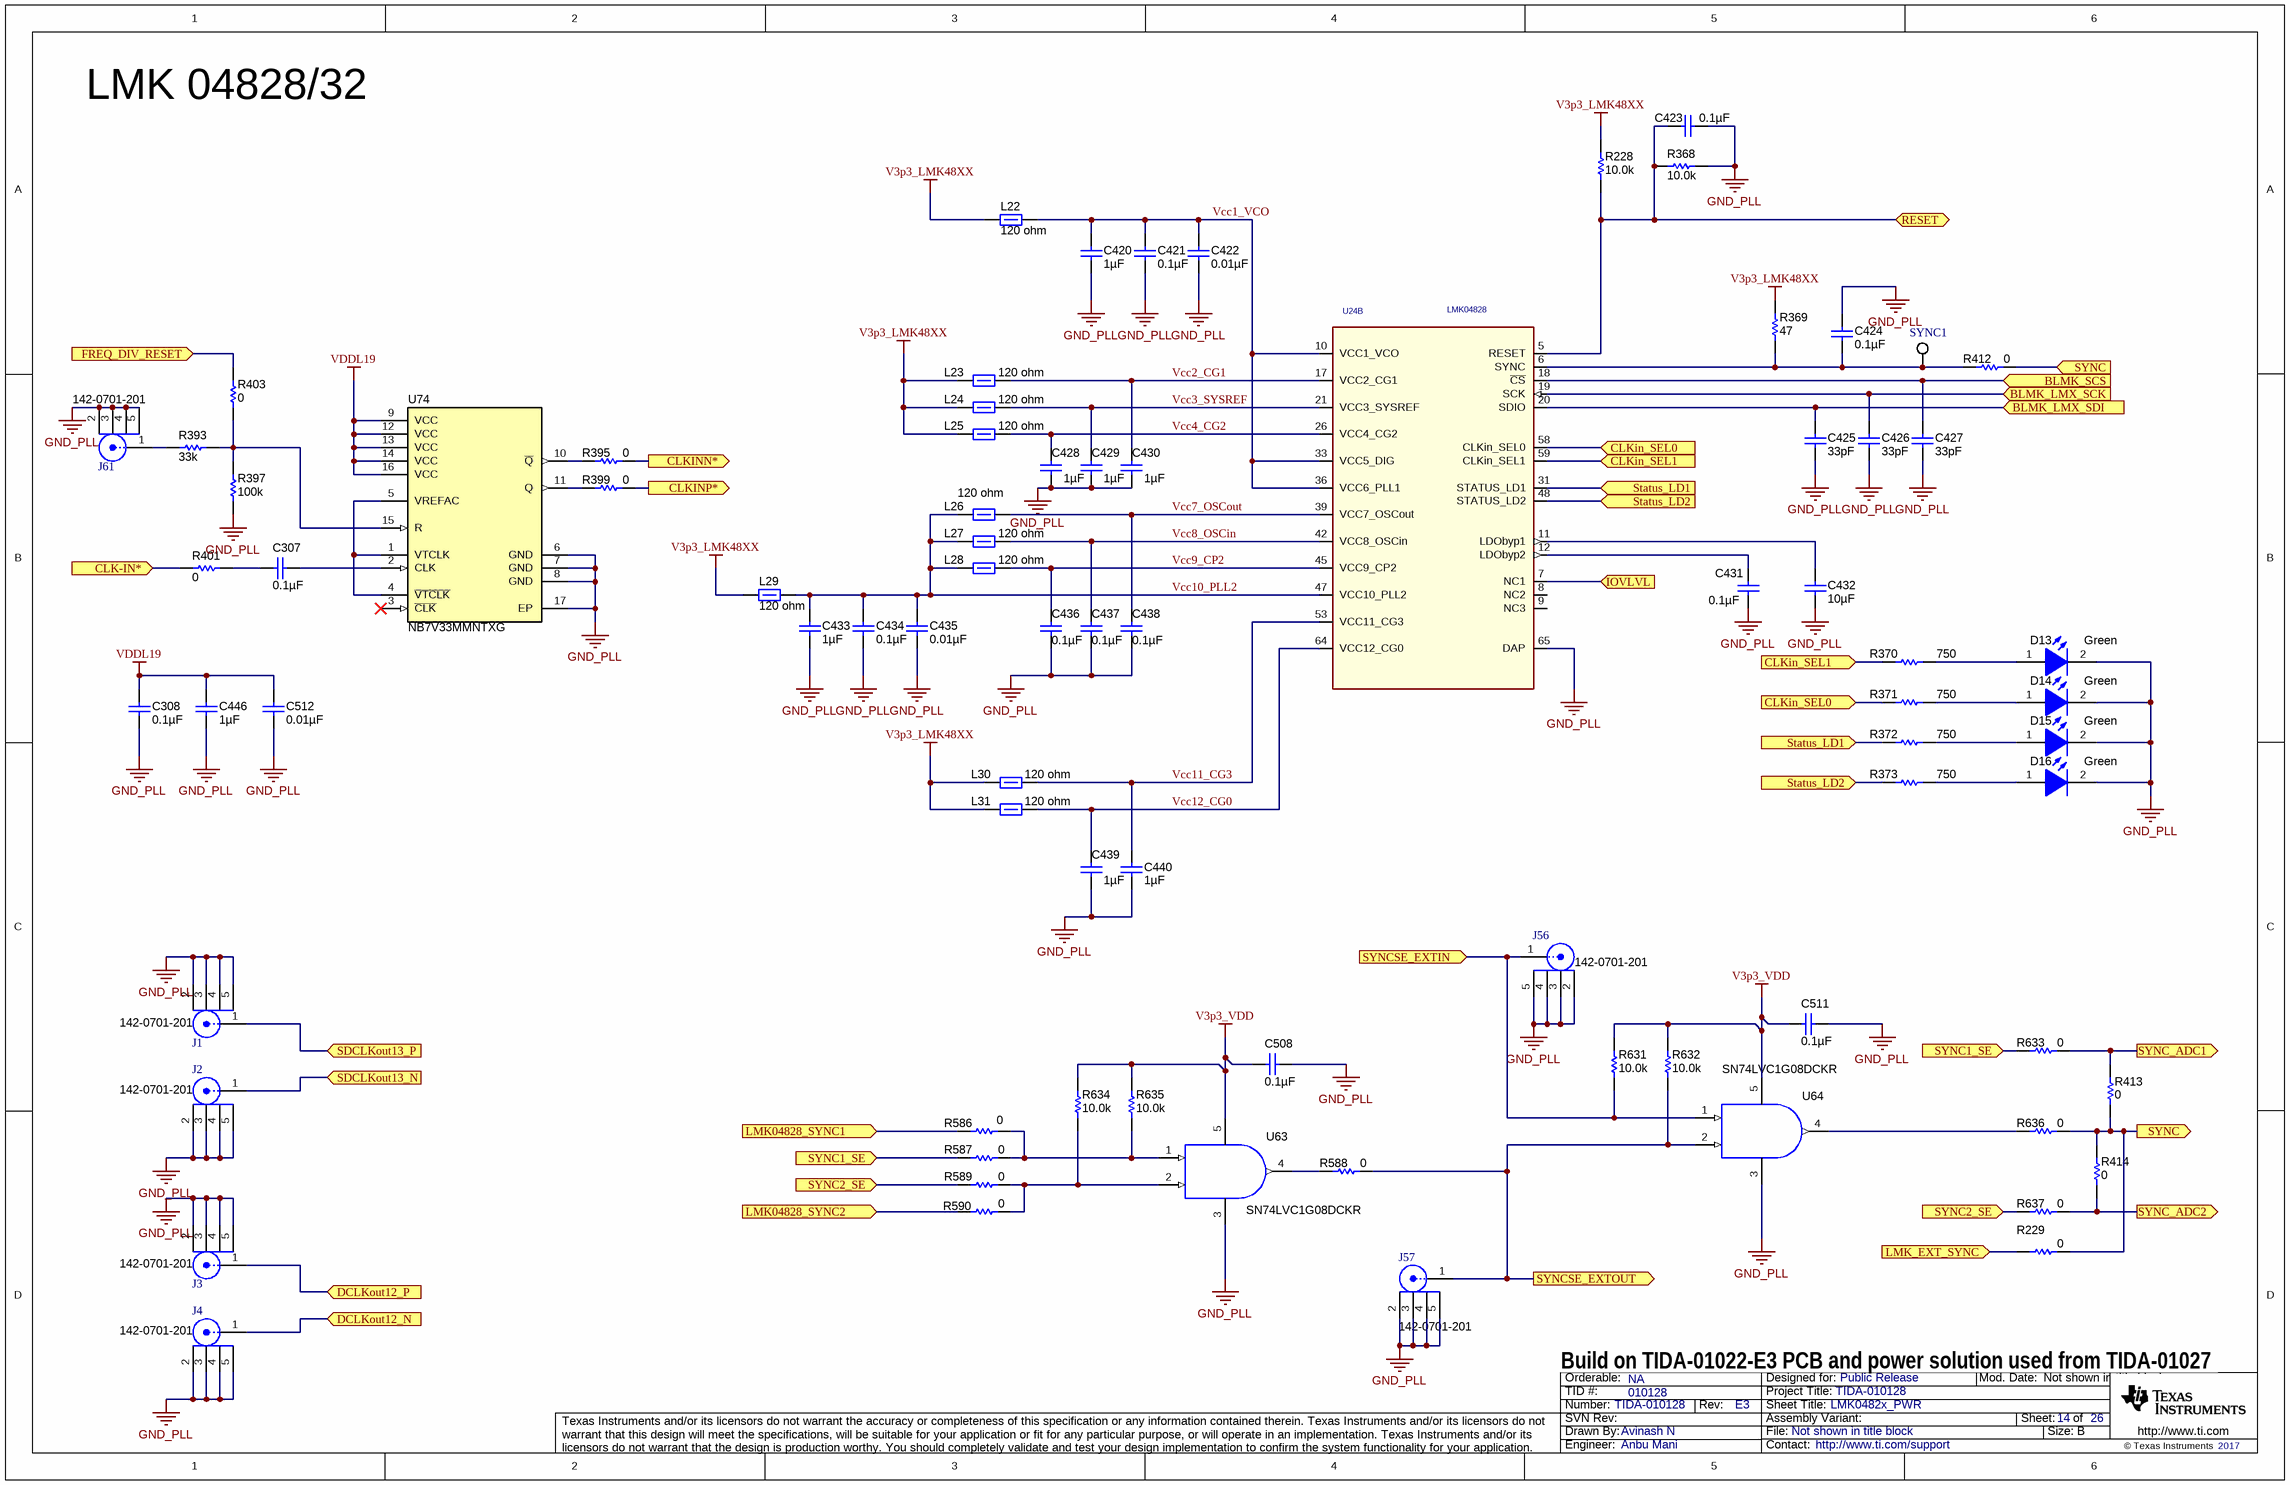
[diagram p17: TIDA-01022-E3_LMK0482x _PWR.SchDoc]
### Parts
C307  ValueDisplayed: 0.1µF  [0201_033]  (hidden comment: GRM033R60J104KE19D)
C308  ValueDisplayed: 0.1µF  [0402]  (hidden comment: C1005X7R1E104M050BB)
C420  ValueDisplayed: 1µF  [0402]  (hidden comment: C1005X7S1A105K050BC)
C421  ValueDisplayed: 0.1µF  [0402]  (hidden comment: GRM155R71C104KA88D)
C422  ValueDisplayed: 0.01µF  [0402]  (hidden comment: GRM155R71E103KA01D)
C423  ValueDisplayed: 0.1µF  [0402]  (hidden comment: C1005X7R1E104M050BB)
C424  ValueDisplayed: 0.1µF  [0402]  (hidden comment: C1005X7R1E104M050BB)
C425  ValueDisplayed: 33pF  [0603L]  (hidden comment: C0603C330J5GACTU)
C426  ValueDisplayed: 33pF  [0603L]  (hidden comment: C0603C330J5GACTU)
C427  ValueDisplayed: 33pF  [0603L]  (hidden comment: C0603C330J5GACTU)
C428  ValueDisplayed: 1µF  [0402]  (hidden comment: C1005X7S1A105K050BC)
C429  ValueDisplayed: 1µF  [0402]  (hidden comment: C1005X7S1A105K050BC)
C430  ValueDisplayed: 1µF  [0402]  (hidden comment: C1005X7S1A105K050BC)
C431  ValueDisplayed: 0.1µF  [0603]  (hidden comment: C0603C104J3RACTU)
C432  ValueDisplayed: 10µF  [0805_HV]  (hidden comment: C0805C106K8PACTU)
C433  ValueDisplayed: 1µF  [0402]  (hidden comment: C1005X7S1A105K050BC)
C434  ValueDisplayed: 0.1µF  [0402]  (hidden comment: GRM155R71C104KA88D)
C435  ValueDisplayed: 0.01µF  [0402]  (hidden comment: GRM155R71E103KA01D)
C436  ValueDisplayed: 0.1µF  [0402]  (hidden comment: C1005X7R1E104M050BB)
C437  ValueDisplayed: 0.1µF  [0402]  (hidden comment: C1005X7R1E104M050BB)
C438  ValueDisplayed: 0.1µF  [0402]  (hidden comment: C1005X7R1E104M050BB)
C439  ValueDisplayed: 1µF  [0402]  (hidden comment: C1005X7S1A105K050BC)
C440  ValueDisplayed: 1µF  [0402]  (hidden comment: C1005X7S1A105K050BC)
C446  ValueDisplayed: 1µF  [0402]  (hidden comment: C1005X7S1A105K050BC)
C508  ValueDisplayed: 0.1µF  [0402]  (hidden comment: GRM155R71C104KA88D)
C511  ValueDisplayed: 0.1µF  [0402]  (hidden comment: GRM155R71C104KA88D)
C512  ValueDisplayed: 0.01µF  [0402]  (hidden comment: GRM155R71E103KA01D)
D13  value Green  [LTST-C191_Green]  (hidden comment: LTST-C191TGKT)
D14  value Green  [LTST-C191_Green]  (hidden comment: LTST-C191TGKT)
D15  value Green  [LTST-C191_Green]  (hidden comment: LTST-C191TGKT)
D16  value Green  [LTST-C191_Green]  (hidden comment: LTST-C191TGKT)
J1  142-0701-201  [Johnson_142-0701-20x]
J2  142-0701-201  [Johnson_142-0701-20x]
J3  142-0701-201  [Johnson_142-0701-20x]
J4  142-0701-201  [Johnson_142-0701-20x]
J56  142-0701-201  [Johnson_142-0701-20x]
J57  142-0701-201  [Johnson_142-0701-20x]
J61  142-0701-201  [Johnson_142-0701-20x]
L22  ValueDisplayed: 120 ohm  [0603]  (hidden comment: BLM18AG121SN1D)
L23  ValueDisplayed: 120 ohm  [0603]  (hidden comment: BLM18AG121SN1D)
L24  ValueDisplayed: 120 ohm  [0603]  (hidden comment: BLM18AG121SN1D)
L25  ValueDisplayed: 120 ohm  [0603]  (hidden comment: BLM18AG121SN1D)
L26  ValueDisplayed: 120 ohm  [0603]  (hidden comment: BLM18AG121SN1D)
L27  ValueDisplayed: 120 ohm  [0603]  (hidden comment: BLM18AG121SN1D)
L28  ValueDisplayed: 120 ohm  [0603]  (hidden comment: BLM18AG121SN1D)
L29  ValueDisplayed: 120 ohm  [0603]  (hidden comment: BLM18AG121SN1D)
L30  ValueDisplayed: 120 ohm  [0603]  (hidden comment: BLM18AG121SN1D)
L31  ValueDisplayed: 120 ohm  [0603]  (hidden comment: BLM18AG121SN1D)
R228  ValueDisplayed: 10.0k  [0402]  (hidden comment: ERJ-2RKF1002X)
R229  ValueDisplayed: 0  [0402]  (hidden comment: CRCW04020000Z0ED)
R368  ValueDisplayed: 10.0k  [0402]  (hidden comment: ERJ-2RKF1002X)
R369  ValueDisplayed: 47  [0402]  (hidden comment: CRCW040247R0JNED)
R370  ValueDisplayed: 750  [0603]  (hidden comment: CRCW0603750RFKEA)
R371  ValueDisplayed: 750  [0603]  (hidden comment: CRCW0603750RFKEA)
R372  ValueDisplayed: 750  [0603]  (hidden comment: CRCW0603750RFKEA)
R373  ValueDisplayed: 750  [0603]  (hidden comment: CRCW0603750RFKEA)
R393  ValueDisplayed: 33k  [0402]  (hidden comment: CRCW040233K0JNED)
R395  ValueDisplayed: 0  [0201]  (hidden comment: ERJ-1GN0R00C)
R397  ValueDisplayed: 100k  [0402]  (hidden comment: CRCW0402100KFKED)
R399  ValueDisplayed: 0  [0201]  (hidden comment: ERJ-1GN0R00C)
R401  ValueDisplayed: 0  [0201_ADC]  (hidden comment: CRCW02010000Z0ED)
R403  ValueDisplayed: 0  [0603]  (hidden comment: CRCW06030000Z0EA)
R412  ValueDisplayed: 0  [0402]  (hidden comment: CRCW04020000Z0ED)
R413  ValueDisplayed: 0  [0402]  (hidden comment: CRCW04020000Z0ED)
R414  ValueDisplayed: 0  [0402]  (hidden comment: CRCW04020000Z0ED)
R586  ValueDisplayed: 0  [0402]  (hidden comment: CRCW04020000Z0ED)
R587  ValueDisplayed: 0  [0402]  (hidden comment: CRCW04020000Z0ED)
R588  ValueDisplayed: 0  [0402]  (hidden comment: CRCW04020000Z0ED)
R589  ValueDisplayed: 0  [0402]  (hidden comment: CRCW04020000Z0ED)
R590  ValueDisplayed: 0  [0402]  (hidden comment: CRCW04020000Z0ED)
R631  ValueDisplayed: 10.0k  [0603]  (hidden comment: RT0603DRE0710KL)
R632  ValueDisplayed: 10.0k  [0603]  (hidden comment: RT0603DRE0710KL)
R633  ValueDisplayed: 0  [0402]  (hidden comment: CRCW04020000Z0ED)
R634  ValueDisplayed: 10.0k  [0603]  (hidden comment: RT0603DRE0710KL)
R635  ValueDisplayed: 10.0k  [0603]  (hidden comment: RT0603DRE0710KL)
R636  ValueDisplayed: 0  [0402]  (hidden comment: CRCW04020000Z0ED)
R637  ValueDisplayed: 0  [0402]  (hidden comment: CRCW04020000Z0ED)
SYNC1  5002  [Keystone5002]  (value not drawn)
U24  LMK04828  [NKD0064A]  (part B of 2)
U63  SN74LVC1G08DCKR  [DCK0005A_N]
U64  SN74LVC1G08DCKR  [DCK0005A_N]
U74  NB7V33MMNTXG  [QFN16-3x3MM_0_5]

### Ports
BLMK_LMX_SCK (in), BLMK_LMX_SDI (in), BLMK_SCS (in), CLK-IN* (in), CLKin_SEL0 (in), CLKin_SEL1 (in), CLKINN* (out), CLKINP* (out), DCLKout12_N (in), DCLKout12_P (in), FREQ_DIV_RESET (in), IOVLVL (in), LMK04828_SYNC1 (in), LMK04828_SYNC2 (in), LMK_EXT_SYNC (in), RESET (bidir), SDCLKout13_N (in), SDCLKout13_P (in), Status_LD1 (in), Status_LD2 (in), SYNC1_SE (in), SYNC2_SE (in), SYNC (in), SYNC (out), SYNC_ADC1 (out), SYNC_ADC2 (out), SYNCSE_EXTIN (in), SYNCSE_EXTOUT (out)

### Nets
GND_PLL: C308.1 C420.2 C421.2 C422.2 C423.1 C424.1 C425.1 C426.1 C427.1 C428.2 C429.2 C430.2 C431.2 C432.2 C433.2 C434.2 C435.2 C436.1 C437.1 C438.1 C439.2 C440.2 C446.1 C508.2 C511.2 C512.1 D13.2(K) D14.2(K) D15.2(K) D16.2(K) J1.2 J1.3 J1.4 J1.5 J2.2 J2.3 J2.4 J2.5 J3.2 J3.3 J3.4 J3.5 J4.2 J4.3 J4.4 J4.5 J56.2 J56.3 J56.4 J56.5 J57.2 J57.3 J57.4 J57.5 J61.2 J61.3 J61.4 J61.5 R368.1 R397.1 U24.65(DAP) U63.3(V-) U64.3(V-) U74.6(GND) U74.7(GND) U74.8(GND) U74.17(EP)  [project net DGND]
V3p3_LMK48XX: L22.1 L23.1 L24.1 L25.1 L29.1 L30.1 L31.1 R228.1 R369.1
V3p3_VDD: C508.1 C511.1 R631.2 R632.2 R634.2 R635.2 U63.5(V+) U64.5(V+)
VDDL19: C308.2 C446.2 C512.2 U74.9(VCC) U74.12(VCC) U74.13(VCC) U74.14(VCC) U74.16(VCC)
BLMK_LMX_SCK: C426.2 U24.19(SCK) ; port BLMK_LMX_SCK
BLMK_LMX_SDI: C425.2 U24.20(SDIO) ; port BLMK_LMX_SDI
BLMK_SCS: C427.2 U24.18(~{CS}) ; port BLMK_SCS
CLK-IN*: R401.1 ; port CLK-IN*
CLKin_SEL0: R371.1 U24.58(CLKin_SEL0) ; port CLKin_SEL0
CLKin_SEL1: R370.1 U24.59(CLKin_SEL1) ; port CLKin_SEL1
CLKINN*: R395.1 ; port CLKINN*
CLKINP*: R399.1 ; port CLKINP*
DCLKout12_N: J4.1 ; port DCLKout12_N
DCLKout12_P: J3.1 ; port DCLKout12_P
FREQ_DIV_RESET: R403.2 ; port FREQ_DIV_RESET
IOVLVL: U24.7(NC1) ; port IOVLVL
LMK04828_SYNC1: R586.2 ; port LMK04828_SYNC1
LMK04828_SYNC2: R590.1 ; port LMK04828_SYNC2
LMK_EXT_SYNC: R229.1 ; port LMK_EXT_SYNC
RESET: C423.2 R228.2 R368.2 U24.5(RESET) ; port RESET
SDCLKout13_N: J2.1 ; port SDCLKout13_N
SDCLKout13_P: J1.1 ; port SDCLKout13_P
Status_LD1: R372.1 U24.31(STATUS_LD1) ; port Status_LD1
Status_LD2: R373.1 U24.48(STATUS_LD2) ; port Status_LD2
SYNC: R229.2 R412.2 R413.1 R414.2 R636.2 ; port SYNC
SYNC1_SE: R587.1 R633.1 ; port SYNC1_SE
SYNC2_SE: R589.1 R637.1 ; port SYNC2_SE
SYNC_ADC1: R413.2 R633.2 ; port SYNC_ADC1
SYNC_ADC2: R414.1 R637.2 ; port SYNC_ADC2
SYNCSE_EXTIN: J56.1 R631.1 U64.1(A) ; port SYNCSE_EXTIN
SYNCSE_EXTOUT: J57.1 R588.2 R632.1 U64.2(B) ; port SYNCSE_EXTOUT
Vcc1_VCO: C420.1 C421.1 C422.1 L22.2 U24.10(VCC1_VCO) U24.33(VCC5_DIG) U24.36(VCC6_PLL1)
Vcc2_CG1: C430.1 L23.2 U24.17(VCC2_CG1)
Vcc3_SYSREF: C429.1 L24.2 U24.21(VCC3_SYSREF)
Vcc4_CG2: C428.1 L25.2 U24.26(VCC4_CG2)
Vcc7_OSCout: C438.2 L26.2 U24.39(VCC7_OSCout)
Vcc8_OSCin: C437.2 L27.2 U24.42(VCC8_OSCin)
Vcc9_CP2: C436.2 L28.2 U24.45(VCC9_CP2)
Vcc10_PLL2: C433.1 C434.1 C435.1 L26.1 L27.1 L28.1 L29.2 U24.47(VCC10_PLL2)
Vcc11_CG3: C440.1 L30.2 U24.53(VCC11_CG3)
Vcc12_CG0: C439.1 L31.2 U24.64(VCC12_CG0)
NetC307_1: C307.1 R401.2
NetC307_2: C307.2 U74.2(CLK)
NetC424_2: C424.2 R369.2 R412.1 SYNC1.1 U24.6(SYNC)
NetC431_1: C431.1 U24.12(LDObyp2)
NetC432_1: C432.1 U24.11(LDObyp1)
NetD13_1: D13.1(A) R370.2
NetD14_1: D14.1(A) R371.2
NetD15_1: D15.1(A) R372.2
NetD16_1: D16.1(A) R373.2
NetJ61_1: J61.1 R393.1
NetR393_2: R393.2 R397.2 R403.1 U74.15(R)
NetR395_2: R395.2 U74.10(~{Q})
NetR399_2: R399.2 U74.11(Q)
NetR586_1: R586.1 R587.2 R635.1 U63.1(A)
NetR588_1: R588.1 U63.4(Y)
NetR589_2: R589.2 R590.2 R634.1 U63.2(B)
NetR636_1: R636.1 U64.4(Y)
NetU74_1: U74.1(VTCLK) U74.4(~{VTCLK}) U74.5(VREFAC)

Not connected (* = marked no-connect by the designer): U24 8(NC2) 9(NC3); U74 3(~{CLK})*

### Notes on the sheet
- LMK 04828/32
- Build on TIDA-01022-E3 PCB and power solution used from TIDA-01027

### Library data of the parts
C307 = GRM033R60J104KE19D: CAP, CERM, 0.1 µF, 6.3 V,+/- 10%, X5R, 0201; Manufacturer: MuRata; Cap_Case: 0201; Polarized: N; TaMax_C: 85; TaMin_C: -55; Tolerance_%: 10; VDC_V: 6.3; Cap_F: 0.0000001; CompType: Capacitor; Value: 0.1uF; Value2: 6.3V; U/M: EA; SizeArea_mm2: 0.18; SizeAreaWB_mm2: 2.08; SizeX_mm: 0.6; SizeY_mm: 0.3; SizeZ_mm: 0.33; AEC Category: Q200; Green_Lifecycle: Active; Green_REACh: Passed
C308 = C1005X7R1E104M050BB: CAP, CERM, 0.1 µF, 25 V,+/- 20%, X7R, 0402; Manufacturer: TDK; Polarized: N; TaMax_C: 125; TaMin_C: -55; Tolerance_%: 20; VDC_V: 25; Cap_F: 0.0000001; CompType: Capacitor; Value: 0.1uF; Value2: 25V; U/M: EA; SizeArea_mm2: 0.5; SizeAreaWB_mm2: 3; SizeX_mm: 1; SizeZ_mm: 0.6; AEC Category: Q200; Green_Lifecycle: NRND; Green_REACh: Passed
C420 C428-C430 C433 C439 C440 = C1005X7S1A105K050BC: CAP, CERM, 1 µF, 10 V, +/- 10%, X7S, 0402; Manufacturer: TDK; Polarized: N; CompType: Capacitor; Value: 1uF; U/M: EA; Cap_F: 0.000001; Tolerance_%: 10; ESR_ohm: 0.011416; Value1: 0.011416 ohm; Value2: 10V; IRMS_A: 1.483; TaMin_C: -55; TaMax_C: 125; SizeArea_mm2: 0.5; SizeAreaWB_mm2: 3; SizeX_mm: 1; SizeZ_mm: 0.6; AEC Category: Q200
C421 C434 C508 C511 = GRM155R71C104KA88D: CAP, CERM, 0.1 µF, 16 V, +/- 10%, X7R, 0402; Manufacturer: MuRata; Polarized: N; CompType: Capacitor; Value: 0.1uF; U/M: EA; Cap_F: 0.0000001; Tolerance_%: 10; Value1: Unknown; VDC_V: 16; Value2: 16V; TaMin_C: -55; TaMax_C: 125; SizeArea_mm2: 0.5; SizeAreaWB_mm2: 3; SizeX_mm: 1; SizeZ_mm: 0.6; AEC Category: Q200
C422 C435 = GRM155R71E103KA01D: CAP, CERM, 0.01 µF, 25 V, +/- 10%, X7R, 0402; Manufacturer: MuRata; Polarized: N; CompType: Capacitor; Value: 0.01uF; U/M: EA; Cap_F: 0.00000001; Tolerance_%: 10; Value1: Unknown; VDC_V: 25; Value2: 25V; TaMin_C: -55; TaMax_C: 125; SizeArea_mm2: 0.5; SizeAreaWB_mm2: 3; SizeX_mm: 1; SizeZ_mm: 0.6; AEC Category: Q200
C423 C424 C436-C438 = C1005X7R1E104M050BB: CAP, CERM, 0.1 µF, 25 V, +/- 20%, X7R, 0402; Manufacturer: TDK; Polarized: N; TaMax_C: 125; TaMin_C: -55; Tolerance_%: 20; VDC_V: 25; Cap_F: 0.0000001; CompType: Capacitor; Value: 0.1uF; Value1: Unknown; Value2: 25V; U/M: EA; SizeArea_mm2: 0.5; SizeAreaWB_mm2: 3; SizeX_mm: 1; SizeZ_mm: 0.6; AEC Category: Q200
C425-C427 = C0603C330J5GACTU: CAP, CERM, 33pF, 50V, +/-5%, C0G/NP0, 0603; Manufacturer: Kemet; Cap_Case: 0603; Polarized: N; TaMax_C: 125; TaMin_C: -55; Tolerance_%: 5; VDC_V: 50; Cap_F: 0.000000000033; CompType: Capacitor; U/M: EA; Value1: Unknown
C431 = C0603C104J3RACTU: CAP, CERM, 0.1uF, 25V, +/-5%, X7R, 0603; Manufacturer: Kemet; Polarized: N; TaMax_C: 125; TaMin_C: -55; Tolerance_%: 5; VDC_V: 25; Cap_F: 0.0000001; CompType: Capacitor; Value1: Unknown; U/M: EA
C432 = C0805C106K8PACTU: CAP, CERM, 10uF, 10V, +/-10%, X5R, 0805; Manufacturer: Kemet; Cap_Case: 0805; ESR_Ohm: 0.003; IRMS_A: 11.43; Polarized: N; TaMax_C: 85; TaMin_C: -55; Tolerance_%: 10; Cap_F: 0.00001; CompType: Capacitor; Value1: 0.003 ohm; U/M: EA
C446 = C1005X7S1A105K050BC: CAP, CERM, 1 µF, 10 V,+/- 10%, X7S, 0402; Manufacturer: TDK; ESR_ohm: 0.011416; IRMS_A: 1.483; Polarized: N; TaMax_C: 125; TaMin_C: -55; Tolerance_%: 10; Cap_F: 0.000001; CompType: Capacitor; Value: 1uF; Value1: 0.011416 ohm; Value2: 10V; U/M: EA; SizeArea_mm2: 0.5; SizeAreaWB_mm2: 3; SizeX_mm: 1; SizeZ_mm: 0.6; AEC Category: Q200; Green_Lifecycle: Active; Green_REACh: Passed
C512 = GRM155R71E103KA01D: CAP, CERM, 0.01 µF, 25 V,+/- 10%, X7R, 0402; Manufacturer: MuRata; Polarized: N; TaMax_C: 125; TaMin_C: -55; Tolerance_%: 10; VDC_V: 25; Cap_F: 0.00000001; CompType: Capacitor; Value: 0.01uF; Value2: 25V; U/M: EA; SizeArea_mm2: 0.5; SizeAreaWB_mm2: 3; SizeX_mm: 1; SizeZ_mm: 0.6; AEC Category: Q200; Green_Lifecycle: Active; Green_REACh: Passed
D13-D16 = LTST-C191TGKT: LED, Green, SMD; Manufacturer: Lite-On; Type: InGaN; Vf_V: 3.2; Value2: 3.2V; Io_A: 0.02; Value1: W; U/M: EA
J1-J4 J56 J57 J61 = 142-0701-201: Connector, TH, SMA; Manufacturer: Emerson Network Power; SymbolCreator: X0208326
L22-L31 = BLM18AG121SN1D: Ferrite Bead, 120 ohm @ 100 MHz, 0.5 A, 0603; Manufacturer: MuRata; Value: 120 ohm; Imax_A: 0.5; DCR_ohm: 0.18; Value1: 0.18 ohm; Value2: 0.5A; SizeAreaWB_mm2: 4.68; SizeArea_mm2: 1.28; SizeX_mm: 1.6; SizeY_mm: 0.8; SizeZ_mm: 1; ZTyp@100MHz_Ohm: 120
R228 R368 = ERJ-2RKF1002X: RES, 10.0 k, 1%, 0.1 W, 0402; Manufacturer: Panasonic; CompType: Resistor; Value: 10.0k; Res_ohm: 10000; Value_Code: 10k0; Tolerance_%: 1; Power_W: 0.1; Value2: 0.1W; VDC_V: 50; TempCo: 100 ppm/C; SizeArea_mm2: 0.5; SizeZ_mm: 0.6; EIA_Code: E96; U/M: EA; AEC Category: Q200
R229 R412-R414 R586-R590 R633 R636 R637 = CRCW04020000Z0ED: RES, 0, 5%, 0.063 W, 0402; Manufacturer: Vishay-Dale; CompType: Resistor; Value: 0; Value_Code: 0000; Tolerance_%: 5; Power_W: 0.063; Value2: 0.063W; VDC_V: 50; TempCo: 200 ppm/C; SizeArea_mm2: 0.5; SizeX_mm: 1; SizeZ_mm: 0.6; EIA_Code: E24; U/M: EA; AEC Category: Q200
R369 = CRCW040247R0JNED: RES, 47, 5%, 0.063 W, 0402; Manufacturer: Vishay-Dale; CompType: Resistor; Value: 47; Value_Code: 47R0; Tolerance_%: 5; Power_W: 0.063; Value2: 0.063W; VDC_V: 50; TempCo: 200 ppm/C; SizeArea_mm2: 0.5; SizeX_mm: 1; SizeZ_mm: 0.6; EIA_Code: E24; U/M: EA; AEC Category: Q200
R370-R373 = CRCW0603750RFKEA: RES, 750, 1%, 0.1 W, 0603; Manufacturer: Vishay-Dale; CompType: Resistor; Value: 750; Value_Code: 750R; Tolerance_%: 1; Power_W: 0.1; Value2: 0.1W; VDC_V: 75; TempCo: 100 ppm/C; SizeArea_mm2: 1.28; SizeX_mm: 1.6; SizeY_mm: 0.8; EIA_Code: E96; U/M: EA; AEC Category: Q200
R393 = CRCW040233K0JNED: RES, 33 k, 5%, 0.063 W, 0402; Manufacturer: Vishay-Dale; CompType: Resistor; Value: 33k; Res_ohm: 33000; Value_Code: 33k0; Tolerance_%: 5; Power_W: 0.063; Value2: 0.063W; VDC_V: 50; TempCo: 200 ppm/C; SizeArea_mm2: 0.5; SizeX_mm: 1; SizeZ_mm: 0.6; EIA_Code: E24; U/M: EA; AEC Category: Q200; Green_Lifecycle: Active; Green_REACh: Passed
R395 R399 = ERJ-1GN0R00C: RES, 0, 5%, 0.05 W, AEC-Q200 Grade 0, 0201; Manufacturer: Panasonic; CompType: Resistor; Tolerance_%: 5; Power_W: 0.05; Value: 0; U/M: EA; Value_Code: 0000; Value2: 0.05W; EIA_Code: E24; TempCo: ppm/C; SizeArea_mm2: 0.18; SizeX_mm: 0.6; SizeY_mm: 0.3; SizeZ_mm: 0.26; AEC Category: Q200; AEC Qualified: Y
R397 = CRCW0402100KFKED: RES, 100 k, 1%, 0.063 W, 0402; Manufacturer: Vishay-Dale; CompType: Resistor; Value: 100k; Res_ohm: 100000; Tolerance_%: 1; Power_W: 0.063; Value2: 0.063W; VDC_V: 50; TempCo: 100 ppm/C; SizeArea_mm2: 0.5; SizeZ_mm: 0.6; EIA_Code: E96; U/M: EA; AEC Category: Q200; Green_Lifecycle: Active; Green_REACh: Passed
R401 = CRCW02010000Z0ED: RES, 0, 5%, 0.05 W, 0201; Manufacturer: Vishay-Dale; CompType: Resistor; Tolerance_%: 5; Power_W: 0.05; Value: 0; U/M: EA; Value_Code: 0000; Value2: 0.05W; EIA_Code: E24; TempCo: ppm/C; SizeArea_mm2: 0.18; SizeX_mm: 0.6; SizeY_mm: 0.3; SizeZ_mm: 0.26; AEC Category: Q200; AEC Qualified: N
R403 = CRCW06030000Z0EA: RES, 0, 5%, 0.1 W, 0603; Manufacturer: Vishay-Dale; CompType: Resistor; Tolerance_%: 5; VDC_V: 75; Power_W: 0.1; Value: 0; U/M: EA; Value_Code: 0000; Value2: 0.1W; EIA_Code: E24; TempCo: 200 ppm/C; SizeArea_mm2: 1.28; SizeX_mm: 1.6; SizeY_mm: 0.8; SizeZ_mm: 1; AEC Category: Q200; Green_Lifecycle: Active; Green_REACh: Passed
R631 R632 R634 R635 = RT0603DRE0710KL: RES, 10.0 k, 0.5%, 0.1 W, 0603; Manufacturer: Yageo America; CompType: Resistor; Value: 10.0k; Res_ohm: 10000; Value_Code: 10k0; Tolerance_%: 0.5; Power_W: 0.1; Value2: 0.1W; VDC_V: 75; TempCo: 50 ppm/C; SizeArea_mm2: 1.28; SizeX_mm: 1.6; SizeY_mm: 0.8; SizeZ_mm: 1; EIA_Code: E192; U/M: EA; AEC Category: Q200
SYNC1 = 5002: Test Point, Miniature, White, TH; Manufacturer: Keystone; CompType: Test Point Loop; ContactFinish: Silver; Green_Lifecycle: Active; Green_REACh: Passed
U24 = LMK04828: LMK04828BISQE/NOPB; Manufacturer: Texas Instruments
U63 U64 = SN74LVC1G08DCKR: Single 2-Input Positive-AND Gate, DCK0005A (SOT-5); Alternate PartNumber: SN74LVC1G08DCKT; Manufacturer: Texas Instruments; CompType: IC; SizeArea_mm2: 4.2; SizeAreaWB_mm2: 9.3; SizeX_mm: 2.1; SizeY_mm: 2; SizeZ_mm: 1.1; U/M: EA
U74 = NB7V32M: 1.8V / 2.5V, 10GHz ÷4 Clock Divider with CML Outputs, QFN-16; Manufacturer: ON Semiconductor

## Sheet TIDA-01022-E3_LMX2594R_1.SchDoc: LMX2594R
size 431 x 279 mm; Date: Not shown in title block; ApprovedBy: Not shown in title block; CheckedBy: Not shown in title block; Author: Not shown in title block; CompanyName: Not shown in title block; DrawnBy: Avinash N; Engineer: Not shown in title block; Organization: Not shown in title block; Address1: Not shown in title block; Address2: Not shown in title block; Address3: Not shown in title block; Address4: Not shown in title block; DocumentNumber: 1; Revision: Use project parameter SCH_Rev; SheetNumber: 10; SheetTotal: 26; PageSetup: Record=PageOptions¦CenterHorizontal=True¦CenterVertical=True¦PrintScale=1.00¦XCorrection=1.00¦YCorrection=1.00¦PrintKind=0¦BorderSize=5000000¦LeftOffset=0¦BottomOffset=0¦Orientation=2¦PaperLength=1000¦PaperWidth=1000¦Scale=100¦PaperSource=15¦PrintQuality=600¦MediaType=1¦DitherType=10¦PaperKind=Letter¦PrintScaleMode=1

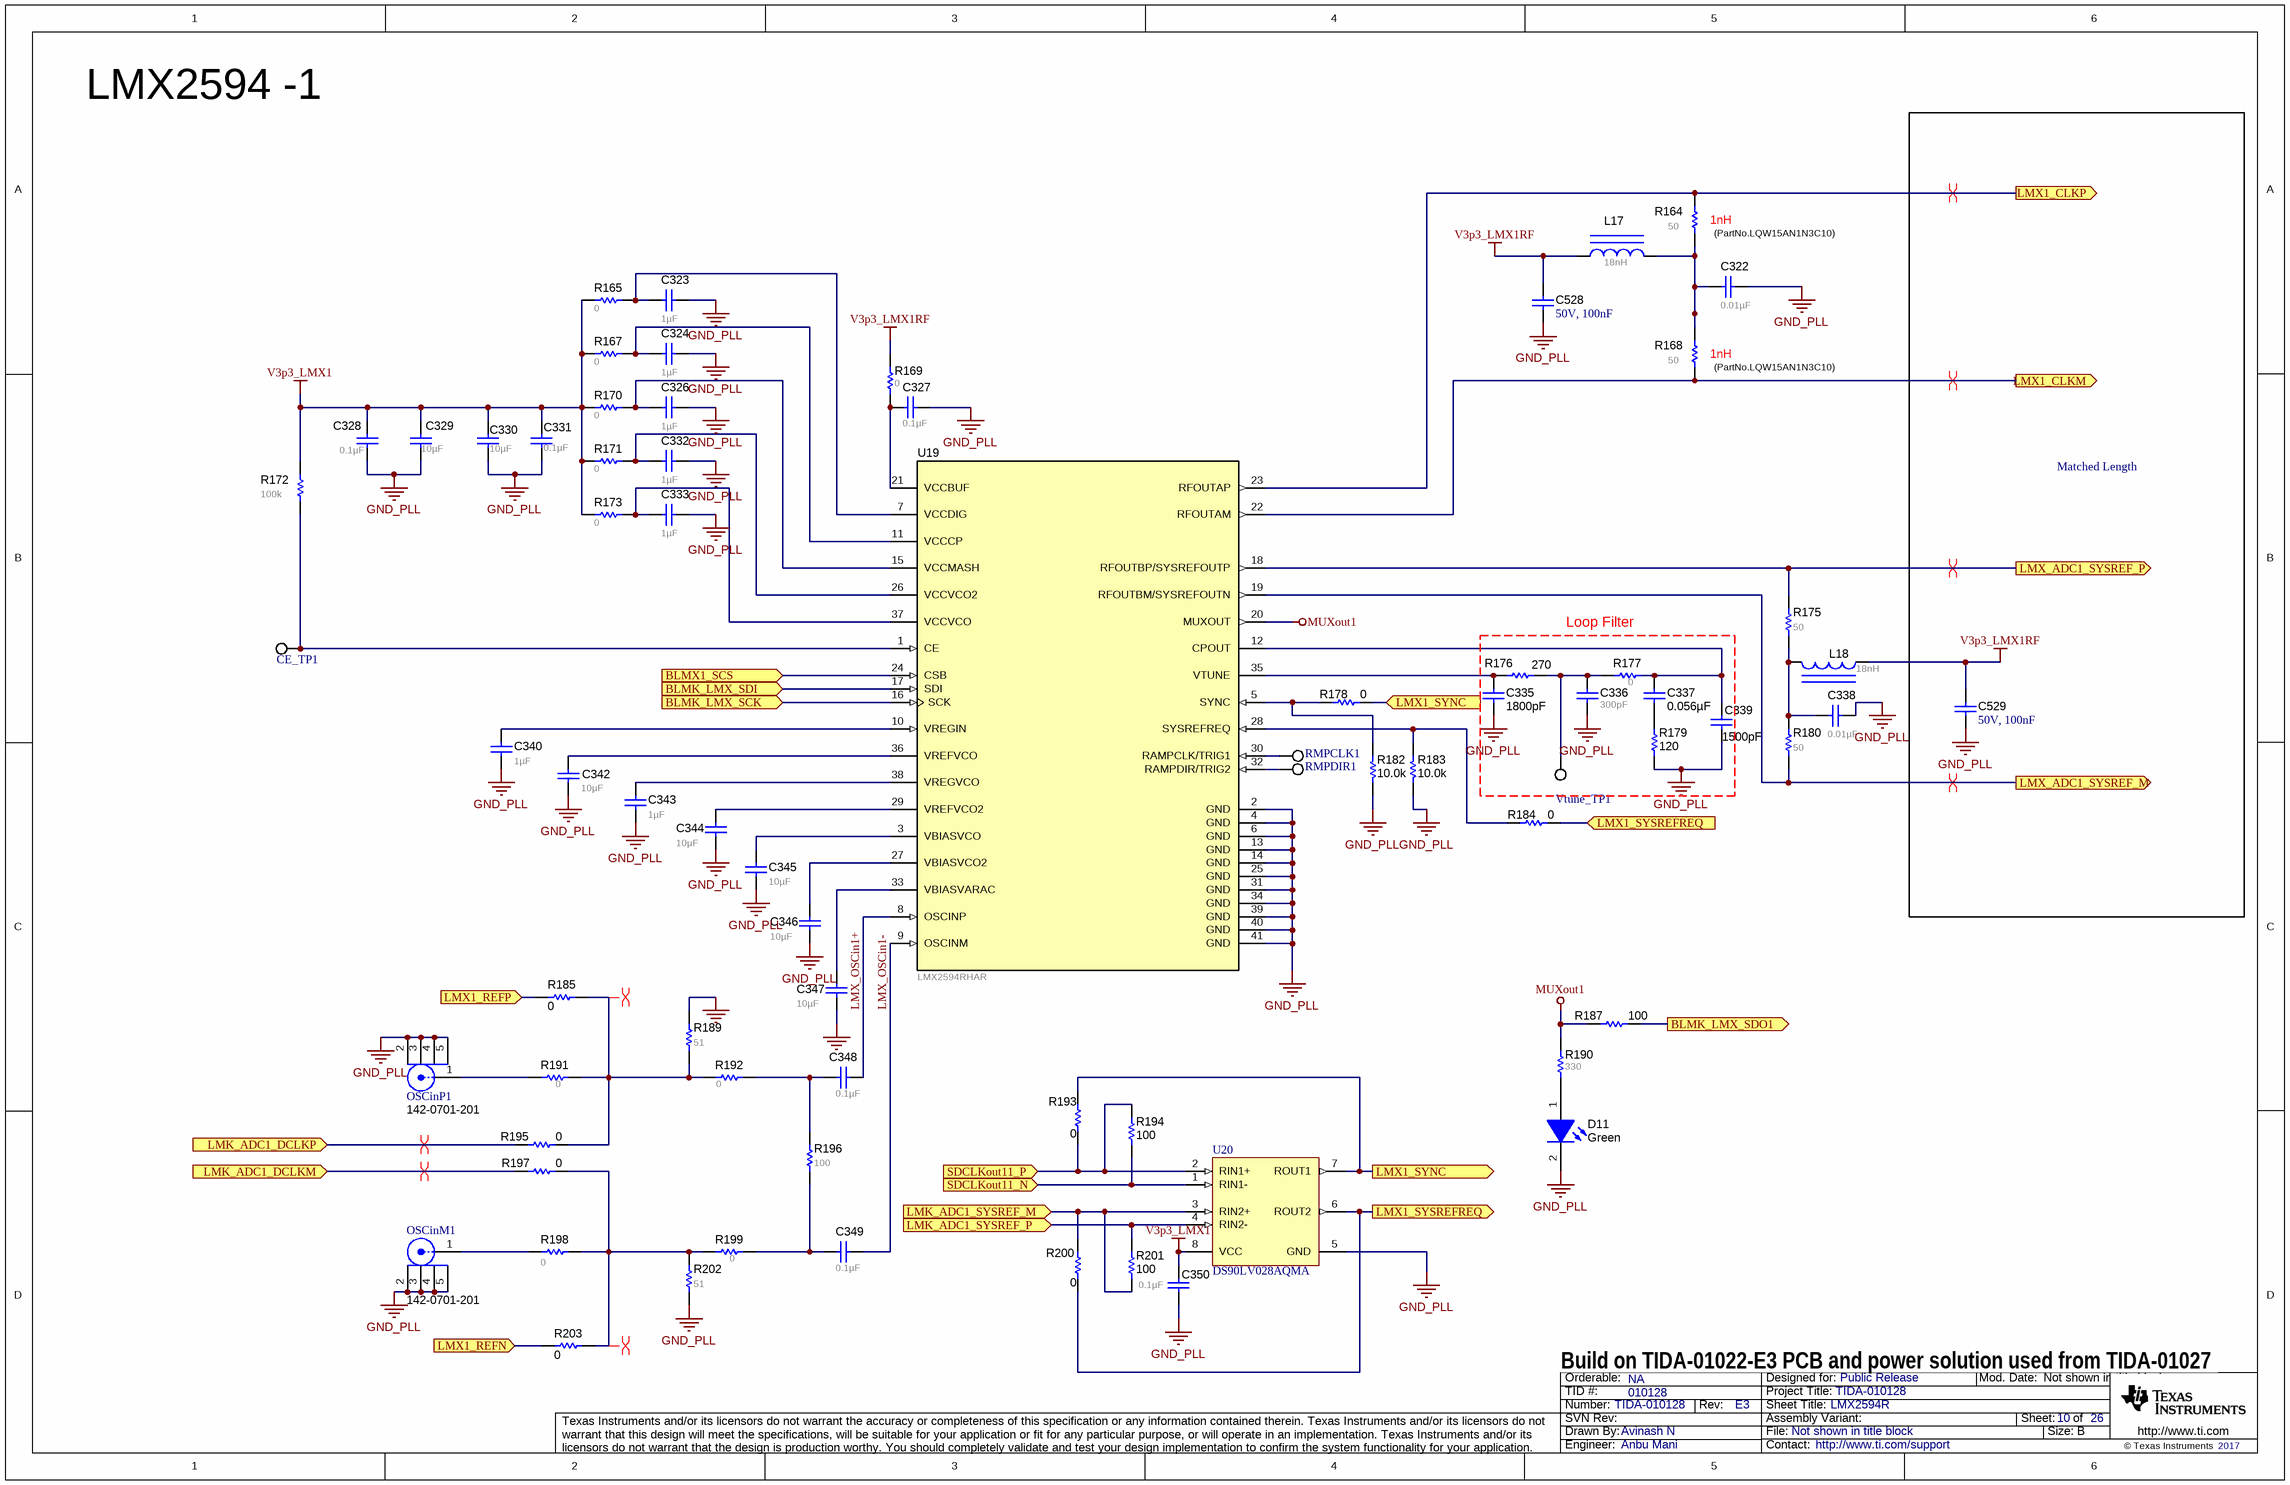
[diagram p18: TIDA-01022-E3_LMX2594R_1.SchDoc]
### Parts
C322  ValueDisplayed: 0.01µF  [0402_065]  (hidden comment: 520L103KT16T)
C323  ValueDisplayed: 1µF  [0603]  (hidden comment: C1608X7R1C105K080AC)
C324  ValueDisplayed: 1µF  [0603L]  (hidden comment: C1608X7R1C105K080AC)
C326  ValueDisplayed: 1µF  [0603L]  (hidden comment: C1608X7R1C105K080AC)
C327  ValueDisplayed: 0.1µF  [0603L]  (hidden comment: 0603YC104JAT2A)
C328  ValueDisplayed: 0.1µF  [0603]  (hidden comment: 0603YC104JAT2A)
C329  ValueDisplayed: 10µF  [0805]  (hidden comment: C0805C106K8PACTU)
C330  ValueDisplayed: 10µF  [0805]  (hidden comment: C0805C106K8PACTU)
C331  ValueDisplayed: 0.1µF  [0603]  (hidden comment: 0603YC104JAT2A)
C332  ValueDisplayed: 1µF  [0603]  (hidden comment: C1608X7R1C105K080AC)
C333  ValueDisplayed: 1µF  [0603]  (hidden comment: C1608X7R1C105K080AC)
C335  ValueDisplayed: 1800pF  [0603]  (hidden comment: GRM1885C1H182JA01D)
C336  ValueDisplayed: 300pF  [0603]  (hidden comment: GRM1885C2A301JA01D)
C337  ValueDisplayed: 0.056µF  [0603]  (hidden comment: C0603C563J4RACTU)
C338  ValueDisplayed: 0.01µF  [0402_065]  (hidden comment: 520L103KT16T)
C339  ValueDisplayed: 1500pF  [0603]  (hidden comment: 06031C152JAT2A)
C340  ValueDisplayed: 1µF  [0603]  (hidden comment: C1608X7R1C105K080AC)
C342  ValueDisplayed: 10µF  [0603]  (hidden comment: C1608X5R1A106M080AC)
C343  ValueDisplayed: 1µF  [0603]  (hidden comment: C1608X7R1C105K080AC)
C344  ValueDisplayed: 10µF  [0603]  (hidden comment: C1608X5R1A106M080AC)
C345  ValueDisplayed: 10µF  [0603]  (hidden comment: C1608X5R1A106M080AC)
C346  ValueDisplayed: 10µF  [0603]  (hidden comment: C1608X5R1A106M080AC)
C347  ValueDisplayed: 10µF  [0603]  (hidden comment: C1608X5R1A106M080AC)
C348  ValueDisplayed: 0.1µF  [0603L]  (hidden comment: 0603YC104JAT2A)
C349  ValueDisplayed: 0.1µF  [0603L]  (hidden comment: 0603YC104JAT2A)
C350  ValueDisplayed: 0.1µF  [0603]  (hidden comment: 0603YC104JAT2A)
C528  50V, 100nF  [0603_1.6x0.8x0.8mm_Reflow Soldering]
C529  50V, 100nF  [0603_1.6x0.8x0.8mm_Reflow Soldering]
CE_TP1  5002  [Keystone5002]  (value not drawn)
D11  value Green  [LTST-C191_Green]  (hidden comment: LTST-C191TGKT)
L17  ValueDisplayed: 18nH  [IND_LQG15H]  (hidden comment: LQG15HS18NJ02D)
L18  ValueDisplayed: 18nH  [IND_LQG15H]  (hidden comment: LQG15HS18NJ02D)
OSCinM1  142-0701-201  [Johnson_142-0701-20x]
OSCinP1  142-0701-201  [Johnson_142-0701-20x]
R164  ValueDisplayed: 50  [0402L]  (hidden comment: FC0402E50R0BST1)
R165  value 0  [0603]  (hidden comment: CRCW06030000Z0EA)
R167  value 0  [0603L]  (hidden comment: CRCW06030000Z0EA)
R168  ValueDisplayed: 50  [0402L]  (hidden comment: FC0402E50R0BST1)
R169  value 0  [0603L]  (hidden comment: CRCW06030000Z0EA)
R170  value 0  [0603L]  (hidden comment: CRCW06030000Z0EA)
R171  value 0  [0603]  (hidden comment: CRCW06030000Z0EA)
R172  ValueDisplayed: 100k  [0603]  (hidden comment: CRCW0603100KJNEA)
R173  value 0  [0603]  (hidden comment: CRCW06030000Z0EA)
R175  ValueDisplayed: 50  [0402L]  (hidden comment: FC0402E50R0BST1)
R176  ValueDisplayed: 270  [0603]  (hidden comment: RC0603JR-07270RL)
R177  ValueDisplayed: 0  [0603]  (hidden comment: CRCW06030000Z0EA)
R178  ValueDisplayed: 0  [0402]  (hidden comment: CRCW04020000Z0ED)
R179  ValueDisplayed: 120  [0603]  (hidden comment: RT0603DRE07120RL)
R180  ValueDisplayed: 50  [0402L]  (hidden comment: FC0402E50R0BST1)
R182  ValueDisplayed: 10.0k  [0402]  (hidden comment: CRCW040210K0DHEDP)
R183  ValueDisplayed: 10.0k  [0402]  (hidden comment: CRCW040210K0DHEDP)
R184  ValueDisplayed: 0  [0402]  (hidden comment: CRCW04020000Z0ED)
R185  ValueDisplayed: 0  [0402]  (hidden comment: CRCW04020000Z0ED)
R187  ValueDisplayed: 100  [0603]  (hidden comment: CRCW0603100RFKEA)
R189  ValueDisplayed: 51  [0603]  (hidden comment: CRCW060351R0JNEA)
R190  value 330  [0603]  (hidden comment: RC0603JR-07330RL)
R191  ValueDisplayed: 0  [0603]  (hidden comment: CRCW06030000Z0EA)
R192  ValueDisplayed: 0  [0603]  (hidden comment: CRCW06030000Z0EA)
R193  ValueDisplayed: 0  [0402]  (hidden comment: CRCW04020000Z0ED)
R194  ValueDisplayed: 100  [0402]  (hidden comment: CRCW0402100RJNED)
R195  ValueDisplayed: 0  [0402]  (hidden comment: CRCW04020000Z0ED)
R196  ValueDisplayed: 100  [0603L]  (hidden comment: CRCW0603100RFKEA)
R197  ValueDisplayed: 0  [0402]  (hidden comment: CRCW04020000Z0ED)
R198  ValueDisplayed: 0  [0603]  (hidden comment: CRCW06030000Z0EA)
R199  ValueDisplayed: 0  [0603]  (hidden comment: CRCW06030000Z0EA)
R200  ValueDisplayed: 0  [0402]  (hidden comment: CRCW04020000Z0ED)
R201  ValueDisplayed: 100  [0402]  (hidden comment: CRCW0402100RJNED)
R202  ValueDisplayed: 51  [0603]  (hidden comment: CRCW060351R0JNEA)
R203  ValueDisplayed: 0  [0402]  (hidden comment: CRCW04020000Z0ED)
RMPCLK1  5002  [Keystone5002]  (value not drawn)
RMPDIR1  5002  [Keystone5002]  (value not drawn)
U19  LMX2594RHAR  [RHA0040A]
U20  DS90LV028AQMA  [M08A_N]
Vtune_TP1  5002  [Keystone5002]  (value not drawn)

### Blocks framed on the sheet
Matched Length: C529
Loop Filter: C335-C337 C339 R176 R177 R179 Vtune_TP1

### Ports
BLMK_LMX_SCK (in), BLMK_LMX_SDI (in), BLMK_LMX_SDO1 (out), BLMX1_SCS (in), LMK_ADC1_DCLKM (in), LMK_ADC1_DCLKP (in), LMK_ADC1_SYSREF_M (in), LMK_ADC1_SYSREF_P (in), LMX1_CLKM (out), LMX1_CLKP (out), LMX1_REFN (in), LMX1_REFP (in), LMX1_SYNC (in), LMX1_SYNC (out), LMX1_SYSREFREQ (in), LMX1_SYSREFREQ (out), LMX_ADC1_SYSREF_M (out), LMX_ADC1_SYSREF_P (out), SDCLKout11_N (in), SDCLKout11_P (in)

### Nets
GND_PLL: C322.1 C323.1 C324.1 C326.2 C327.1 C328.1 C329.1 C330.1 C331.1 C332.1 C333.1 C335.1 C336.2 C338.1 C339.2 C340.1 C342.2 C343.1 C344.2 C345.2 C346.1 C347.1 C350.1 C528.2 C529.2 D11.2(K) OSCinM1.2 OSCinM1.3 OSCinM1.4 OSCinM1.5 OSCinP1.2 OSCinP1.3 OSCinP1.4 OSCinP1.5 R179.2 R182.2 R183.2 R189.2 R202.1 U19.2(GND) U19.4(GND) U19.6(GND) U19.13(GND) U19.14(GND) U19.25(GND) U19.31(GND) U19.34(GND) U19.39(GND) U19.40(GND) U19.41(GND) U20.5(GND)  [project net DGND]
MUXout1: R187.1 R190.2 U19.20(MUXOUT)
V3p3_LMX1: C328.2 C329.2 C330.2 C331.2 C350.2 R165.1 R167.1 R170.1 R171.2 R172.1 R173.2 U20.8(VCC)
V3p3_LMX1RF: C528.1 C529.1 L17.1 L18.1 R169.1
BLMK_LMX_SCK: U19.16(SCK) ; port BLMK_LMX_SCK
BLMK_LMX_SDI: U19.17(SDI) ; port BLMK_LMX_SDI
BLMK_LMX_SDO1: R187.2 ; port BLMK_LMX_SDO1
BLMX1_SCS: U19.24(CSB) ; port BLMX1_SCS
LMK_ADC1_DCLKM: R197.1 ; port LMK_ADC1_DCLKM
LMK_ADC1_DCLKP: R195.1 ; port LMK_ADC1_DCLKP
LMK_ADC1_SYSREF_M: R200.1 R201.1 U20.3(RIN2+) ; port LMK_ADC1_SYSREF_M
LMK_ADC1_SYSREF_P: R201.2 U20.4(RIN2-) ; port LMK_ADC1_SYSREF_P
LMX1_CLKM: R168.1 U19.22(RFOUTAM) ; port LMX1_CLKM
LMX1_CLKP: R164.1 U19.23(RFOUTAP) ; port LMX1_CLKP
LMX1_REFN: R203.1 ; port LMX1_REFN
LMX1_REFP: R185.2 ; port LMX1_REFP
LMX1_SYNC: R178.2 R193.1 U20.7(ROUT1) ; port LMX1_SYNC
LMX1_SYSREFREQ: R184.2 R200.2 U20.6(ROUT2) ; port LMX1_SYSREFREQ
LMX_ADC1_SYSREF_M: R180.1 U19.19(RFOUTBM/SYSREFOUTN) ; port LMX_ADC1_SYSREF_M
LMX_ADC1_SYSREF_P: R175.2 U19.18(RFOUTBP/SYSREFOUTP) ; port LMX_ADC1_SYSREF_P
LMX_OSCin1+: C348.2 U19.8(OSCINP)
LMX_OSCin1-: C349.2 U19.9(OSCINM)
SDCLKout11_N: R194.1 U20.1(RIN1-) ; port SDCLKout11_N
SDCLKout11_P: R193.2 R194.2 U20.2(RIN1+) ; port SDCLKout11_P
NetC322_2: C322.2 L17.2 R164.2 R168.2
NetC323_2: C323.2 R165.2 U19.7(VCCDIG)
NetC324_2: C324.2 R167.2 U19.11(VCCCP)
NetC326_1: C326.1 R170.2 U19.15(VCCMASH)
NetC327_2: C327.2 R169.2 U19.21(VCCBUF)
NetC332_2: C332.2 R171.1 U19.26(VCCVCO2)
NetC333_2: C333.2 R173.1 U19.37(VCCVCO)
NetC335_2: C335.2 R176.1 U19.35(VTUNE)
NetC336_1: C336.1 R176.2 R177.2 Vtune_TP1.1
NetC337_1: C337.1 C339.1 R177.1 U19.12(CPOUT)
NetC337_2: C337.2 R179.1
NetC338_2: C338.2 L18.2 R175.1 R180.2
NetC340_2: C340.2 U19.10(VREGIN)
NetC342_1: C342.1 U19.36(VREFVCO)
NetC343_2: C343.2 U19.38(VREGVCO)
NetC344_1: C344.1 U19.29(VREFVCO2)
NetC345_1: C345.1 U19.3(VBIASVCO)
NetC346_2: C346.2 U19.27(VBIASVCO2)
NetC347_2: C347.2 U19.33(VBIASVARAC)
NetC348_1: C348.1 R192.2 R196.2
NetC349_1: C349.1 R196.1 R199.1
NetCE_TP1_1: CE_TP1.1 R172.2 U19.1(CE)
NetD11_1: D11.1(A) R190.1
NetOSCinM1_1: OSCinM1.1 R198.1
NetOSCinP1_1: OSCinP1.1 R191.1
NetR178_1: R178.1 R182.1 U19.5(SYNC)
NetR183_1: R183.1 R184.1 U19.28(SYSREFREQ)
NetR185_1: R185.1 R189.1 R191.2 R192.1 R195.2
NetR197_2: R197.2 R198.2 R199.2 R202.2 R203.2
NetRMPCLK1_1: RMPCLK1.1 U19.30(RAMPCLK/TRIG1)
NetRMPDIR1_1: RMPDIR1.1 U19.32(RAMPDIR/TRIG2)

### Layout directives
differential pair: LMK_ADC1_DCLKM, LMK_ADC1_DCLKP, LMX1_CLKM, LMX1_CLKP, LMX_ADC1_SYSREF_M, LMX_ADC1_SYSREF_P, NetR185_1, NetR197_2

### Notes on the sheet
- LMX2594 -1
- (near R164) 1nH
- (near R164) (PartNo.LQW15AN1N3C10)
- (near R168) 1nH
- (near R168) (PartNo.LQW15AN1N3C10)
- Build on TIDA-01022-E3 PCB and power solution used from TIDA-01027

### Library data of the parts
C322 C338 = 520L103KT16T: CAP, CERM, 0.01 µF, 16 V, +/- 10%, X7R, 0402; Manufacturer: AT Ceramics; Polarized: N; CompType: Capacitor; Value: 0.01uF; U/M: EA; Cap_F: 0.00000001; Tolerance_%: 10; Value1: Unknown; VDC_V: 16; Value2: 16V; TaMin_C: -55; TaMax_C: 125; Cap_Case: 0402; AEC Category: Q200; SizeArea_mm2: 0.5; SizeAreaWB_mm2: 3; SizeX_mm: 1; SizeZ_mm: 0.65
C323 C332 C333 = C1608X7R1C105K080AC: CAP, CERM, 1 µF, 16 V, +/- 10%, X7R, 0603; Manufacturer: TDK; ESR_ohm: 0.0057; Polarized: N; TaMax_C: 125; TaMin_C: -55; Tolerance_%: 10; VDC_V: 16; Cap_F: 0.000001; CompType: Capacitor; Value: 1uF; Value1: 0.0057 ohm; Value2: 16V; U/M: EA; SizeArea_mm2: 1.28; SizeAreaWB_mm2: 4.68; SizeX_mm: 1.6; SizeY_mm: 0.8; SizeZ_mm: 1; AEC Category: Q200
C324 C326 = C1608X7R1C105K080AC: CAP, CERM, 1 µF, 16 V, +/- 10%, X7R, 0603; Manufacturer: TDK; Cap_Case: 0603; ESR_ohm: 0.0057; Polarized: N; TaMax_C: 125; TaMin_C: -55; Tolerance_%: 10; VDC_V: 16; Cap_F: 0.000001; CompType: Capacitor; Value: 1uF; Value1: 0.0057 ohm; Value2: 16V; U/M: EA; SizeArea_mm2: 1.28; SizeAreaWB_mm2: 4.68; SizeX_mm: 1.6; SizeY_mm: 0.8; SizeZ_mm: 1; AEC Category: Q200
C327 C348 C349 = 0603YC104JAT2A: CAP, CERM, 0.1uF, 16V, +/-5%, X7R, 0603; Manufacturer: AVX; Cap_Case: 0603; ESR_Ohm: 0.039; Polarized: N; TaMax_C: 125; TaMin_C: -55; Tolerance_%: 5; VDC_V: 16; Cap_F: 0.0000001; CompType: Capacitor; Value1: 0.039 ohm; U/M: EA
C328 C331 C350 = 0603YC104JAT2A: CAP, CERM, 0.1uF, 16V, +/-5%, X7R, 0603; Manufacturer: AVX; ESR_Ohm: 0.039; Polarized: N; TaMax_C: 125; TaMin_C: -55; Tolerance_%: 5; VDC_V: 16; Cap_F: 0.0000001; CompType: Capacitor; Value1: 0.039 ohm; U/M: EA
C329 C330 = C0805C106K8PACTU: CAP, CERM, 10uF, 10V, +/-10%, X5R, 0805; Manufacturer: Kemet; ESR_Ohm: 0.003; IRMS_A: 11.43; Polarized: N; TaMax_C: 85; TaMin_C: -55; Tolerance_%: 10; Cap_F: 0.00001; CompType: Capacitor; U/M: EA; Value1: 0.003 ohm
C335 = GRM1885C1H182JA01D: CAP, CERM, 1800 pF, 50 V, +/- 5%, C0G/NP0, 0603; Manufacturer: MuRata; Polarized: N; TaMax_C: 125; TaMin_C: -55; Tolerance_%: 5; VDC_V: 50; Cap_F: 0.0000000018; CompType: Capacitor; Value: 1800pF; Value1: Unknown; Value2: 50V; U/M: EA; SizeArea_mm2: 1.28; SizeAreaWB_mm2: 4.68; SizeX_mm: 1.6; SizeY_mm: 0.8; SizeZ_mm: 1; AEC Category: Q200
C336 = GRM1885C2A301JA01D: CAP, CERM, 300pF, 100V, +/-5%, C0G/NP0, 0603; Manufacturer: MuRata; Polarized: N; TaMax_C: 125; TaMin_C: -55; Tolerance_%: 5; VDC_V: 100; Cap_F: 0.0000000003; CompType: Capacitor; Value1: Unknown; U/M: EA
C337 = C0603C563J4RACTU: CAP, CERM, 0.056 µF, 16 V, +/- 5%, X7R, 0603; Manufacturer: Kemet; Polarized: N; TaMax_C: 125; TaMin_C: -55; Tolerance_%: 5; VDC_V: 16; Cap_F: 0.000000056; CompType: Capacitor; Value: 0.056uF; Value1: Unknown; Value2: 16V; U/M: EA; AEC Category: Q200; SizeArea_mm2: 1.28; SizeAreaWB_mm2: 4.68; SizeX_mm: 1.6; SizeY_mm: 0.8; SizeZ_mm: 1
C339 = 06031C152JAT2A: CAP, CERM, 1500 pF, 100 V, +/- 5%, X7R, 0603; Manufacturer: AVX; ESR_ohm: 0.229; Polarized: N; TaMax_C: 125; TaMin_C: -55; Tolerance_%: 5; VDC_V: 100; Cap_F: 0.0000000015; CompType: Capacitor; Value: 1500pF; Value1: 0.229 ohm; Value2: 100V; U/M: EA; AEC Category: Q200; SizeArea_mm2: 1.28; SizeAreaWB_mm2: 4.68; SizeX_mm: 1.6; SizeY_mm: 0.8; SizeZ_mm: 1
C340 = C1608X7R1C105K080AC: CAP, CERM, 1 µF, 16 V, +/- 10%, X7R, 0603; Manufacturer: TDK; Polarized: N; CompType: Capacitor; Value: 1uF; U/M: EA; Cap_F: 0.000001; Tolerance_%: 10; ESR_ohm: 0.0057; Value1: 0.0057 ohm; VDC_V: 16; Value2: 16V; TaMin_C: -55; TaMax_C: 125; AEC Category: Q200
C342 C344-C347 = C1608X5R1A106M080AC: CAP, CERM, 10 µF, 10 V, +/- 20%, X5R, 0603; Manufacturer: TDK; ESR_ohm: 0.0078; IRMS_A: 1.85; Polarized: N; TaMax_C: 85; TaMin_C: -55; Tolerance_%: 20; VDC_V: 10; Cap_F: 0.00001; CompType: Capacitor; Value: 10uF; U/M: EA; Value1: 0.0078 ohm; Value2: 10V; AEC Category: Q200
C343 = C1608X7R1C105K080AC: CAP, CERM, 1 µF, 16 V, +/- 10%, X7R, 0603; Manufacturer: TDK; ESR_ohm: 0.0057; Polarized: N; TaMax_C: 125; TaMin_C: -55; Tolerance_%: 10; VDC_V: 16; Cap_F: 0.000001; CompType: Capacitor; Value: 1uF; U/M: EA; Value1: 0.0057 ohm; Value2: 16V; AEC Category: Q200
C528 C529 = 885012206095: WCAP-CSGP Ceramic Capacitors, 0603, X7R, 50V, 100nF; Rated Voltage: 50V DC
CE_TP1 RMPCLK1 RMPDIR1 Vtune_TP1 = 5002: as SYNC1 on sheet TIDA-01022-E3_LMK0482x _PWR
D11 = LTST-C191TGKT: as D13 on sheet TIDA-01022-E3_LMK0482x _PWR
L17 L18 = LQG15HS18NJ02D: Inductor, Multilayer, Air Core, 18 nH, 0.3 A, 0.36 ohm, SMD; Manufacturer: MuRata; Value: 18nH; Ind_H: 18.0E-9; Imax_A: 0.3; Irms: 0.3A @ C rise; Isat: 0.3A @ % inductance drop; DCR_ohm: 0.36; Value2: 0.3A; AEC Category: Q200
OSCinM1 OSCinP1 = 142-0701-201: as J1-J4 on sheet TIDA-01022-E3_LMK0482x _PWR
R164 R168 R175 R180 = FC0402E50R0BST1: RES, 50, 0.1%, 0.05 W, 0402; Manufacturer: Vishay-Dale; CompType: Resistor; Value: 50; Value_Code: 50R0; Tolerance_%: 0.1; Power_W: 0.05; Value2: 0.05W; TempCo: 25 ppm/C; U/M: EA; SizeArea_mm2: 0.5; SizeX_mm: 1; SizeZ_mm: 0.6; AEC Category: Q200; AEC Qualified: N
R165 R167 R169-R171 R173 = CRCW06030000Z0EA: RES, 0 ohm, 5%, 0.1W, 0603; Manufacturer: Vishay-Dale; CompType: Resistor; Tolerance_%: 5; VDC_V: 75; Power_W: 0.1; U/M: EA; Value_Code: 0000; EIA_Code: E24
R172 = CRCW0603100KJNEA: RES, 100 k, 5%, 0.1 W, 0603; Manufacturer: Vishay-Dale; CompType: Resistor; Tolerance_%: 5; VDC_V: 75; Power_W: 0.1; Res_ohm: 100000; Value: 100k; U/M: EA; Value2: 0.1W; EIA_Code: E24; TempCo: 200 ppm/C; SizeArea_mm2: 1.28; SizeX_mm: 1.6; SizeY_mm: 0.8; SizeZ_mm: 1; AEC Category: Q200
R176 = RC0603JR-07270RL: RES, 270, 5%, 0.1 W, 0603; Manufacturer: Yageo America; CompType: Resistor; Tolerance_%: 5; VDC_V: 50; Power_W: 0.1; Value: 270; U/M: EA; Value_Code: 270R; Value2: 0.1W; EIA_Code: E24; TempCo: 100 ppm/C; SizeArea_mm2: 1.28; SizeX_mm: 1.6; SizeY_mm: 0.8; SizeZ_mm: 1; AEC Category: Q200
R177 R191 R192 R198 R199 = CRCW06030000Z0EA: RES, 0, 5%, 0.1 W, 0603; Manufacturer: Vishay-Dale; CompType: Resistor; Tolerance_%: 5; VDC_V: 75; Power_W: 0.1; Value: 0; U/M: EA; Value_Code: 0000; Value2: 0.1W; EIA_Code: E24; TempCo: 200 ppm/C; SizeArea_mm2: 1.28; SizeX_mm: 1.6; SizeY_mm: 0.8; SizeZ_mm: 1; AEC Category: Q200
R178 R184 R193 R195 R197 R200 = CRCW04020000Z0ED: as R229 on sheet TIDA-01022-E3_LMK0482x _PWR
R179 = RT0603DRE07120RL: RES, 120, 0.5%, 0.1 W, 0603; Manufacturer: Yageo America; CompType: Resistor; Tolerance_%: 0.5; VDC_V: 75; Power_W: 0.1; Value: 120; U/M: EA; Value_Code: 120R; Value2: 0.1W; TempCo: 50 ppm/C; EIA_Code: E192; SizeArea_mm2: 1.28; SizeX_mm: 1.6; SizeY_mm: 0.8; SizeZ_mm: 1; AEC Category: Q200
R182 R183 = CRCW040210K0DHEDP: RES, 10.0 k, 0.5%, 0.063 W, 0402; Manufacturer: Vishay-Dale; CompType: Resistor; Value: 10.0k; Res_ohm: 10000; Value_Code: 10k0; Tolerance_%: 0.5; Power_W: 0.063; Value2: 0.063W; VDC_V: 50; TempCo: 50 ppm/C; SizeX_mm: 1; SizeZ_mm: 0.6; EIA_Code: E192; U/M: EA; AEC Category: Q200
R185 R203 = CRCW04020000Z0ED: RES, 0, 5%, 0.063 W, 0402; Manufacturer: Vishay-Dale; CompType: Resistor; Tolerance_%: 5; VDC_V: 50; Power_W: 0.063; Value: 0; U/M: EA; Value_Code: 0000; Value2: 0.063W; EIA_Code: E24; TempCo: 200 ppm/C; SizeArea_mm2: 0.5; SizeX_mm: 1; SizeZ_mm: 0.6; AEC Category: Q200
R187 = CRCW0603100RFKEA: RES, 100, 1%, 0.1 W, 0603; Manufacturer: Vishay-Dale; CompType: Resistor; Value: 100; Value_Code: 100R; Tolerance_%: 1; Power_W: 0.1; Value2: 0.1W; VDC_V: 75; TempCo: 100 ppm/C; SizeArea_mm2: 1.28; SizeX_mm: 1.6; SizeY_mm: 0.8; EIA_Code: E96; U/M: EA; AEC Category: Q200
R189 R202 = CRCW060351R0JNEA: RES, 51, 5%, 0.1 W, 0603; Manufacturer: Vishay-Dale; CompType: Resistor; Value: 51; Value_Code: 51R0; Tolerance_%: 5; Power_W: 0.1; Value2: 0.1W; VDC_V: 75; TempCo: 200 ppm/C; EIA_Code: E24; U/M: EA; SizeArea_mm2: 1.28; SizeX_mm: 1.6; SizeY_mm: 0.8; SizeZ_mm: 1; AEC Category: Q200
R190 = RC0603JR-07330RL: RES, 330 ohm, 5%, 0.1W, 0603; Manufacturer: Yageo America; CompType: Resistor; Tolerance_%: 5; VDC_V: 50; Power_W: 0.1; U/M: EA; Value_Code: 330R; EIA_Code: E24
R194 R201 = CRCW0402100RJNED: RES, 100, 5%, 0.063 W, 0402; Manufacturer: Vishay-Dale; CompType: Resistor; Value: 100; Value_Code: 100R; Tolerance_%: 5; Power_W: 0.063; Value2: 0.063W; VDC_V: 50; TempCo: 200 ppm/C; SizeArea_mm2: 0.5; SizeX_mm: 1; SizeZ_mm: 0.6; EIA_Code: E24; U/M: EA; AEC Category: Q200
R196 = CRCW0603100RFKEA: RES, 100, 1%, 0.1 W, 0603; Manufacturer: Vishay-Dale; CompType: Resistor; Tolerance_%: 1; VDC_V: 75; Power_W: 0.1; Value: 100; U/M: EA; Value_Code: 100R; Value2: 0.1W; EIA_Code: E96; TempCo: 100 ppm/C; SizeArea_mm2: 1.28; SizeX_mm: 1.6; SizeY_mm: 0.8; AEC Category: Q200
U19 = LMX2594RHAR: High Performance, Wideband PLLatinum RF Synthesizer, RHA0040A (VQFN-40); Alternate PartNumber: LMX2594RHAT; Manufacturer: Texas Instruments; SymbolCreator: Altium; SizeArea_mm2: 36; SizeAreaWB_mm2: 64; SizeX_mm: 6; SizeZ_mm: 1; CompType: IC; U/M: EA
U20 = DS90LV028AQMA: Automotive LVDS Dual Differential Line Receiver, 8-pin Narrow SOIC; Manufacturer: Texas Instruments; PackageTopMarking: NSZXTT*90LV0*28AQM; PowerWise: N; CompType: Interface IC

## Sheet TIDA-01022-E3_LMX2594R_2.SchDoc: LMX2594R
size 431 x 279 mm; Date: Not shown in title block; ApprovedBy: Not shown in title block; CheckedBy: Not shown in title block; Author: Not shown in title block; CompanyName: Not shown in title block; DrawnBy: Avinash N; Engineer: Not shown in title block; Organization: Not shown in title block; Address1: Not shown in title block; Address2: Not shown in title block; Address3: Not shown in title block; Address4: Not shown in title block; DocumentNumber: 1; Revision: Use project parameter SCH_Rev; SheetNumber: 11; SheetTotal: 26; PageSetup: Record=PageOptions¦CenterHorizontal=True¦CenterVertical=True¦PrintScale=0.59¦XCorrection=1.00¦YCorrection=1.00¦PrintKind=0¦BorderSize=5000000¦LeftOffset=0¦BottomOffset=0¦Orientation=2¦PaperLength=1000¦PaperWidth=1000¦Scale=100¦PaperSource=15¦PrintQuality=600¦MediaType=1¦DitherType=10¦PrintScaleMode=1¦PaperKind=Letter

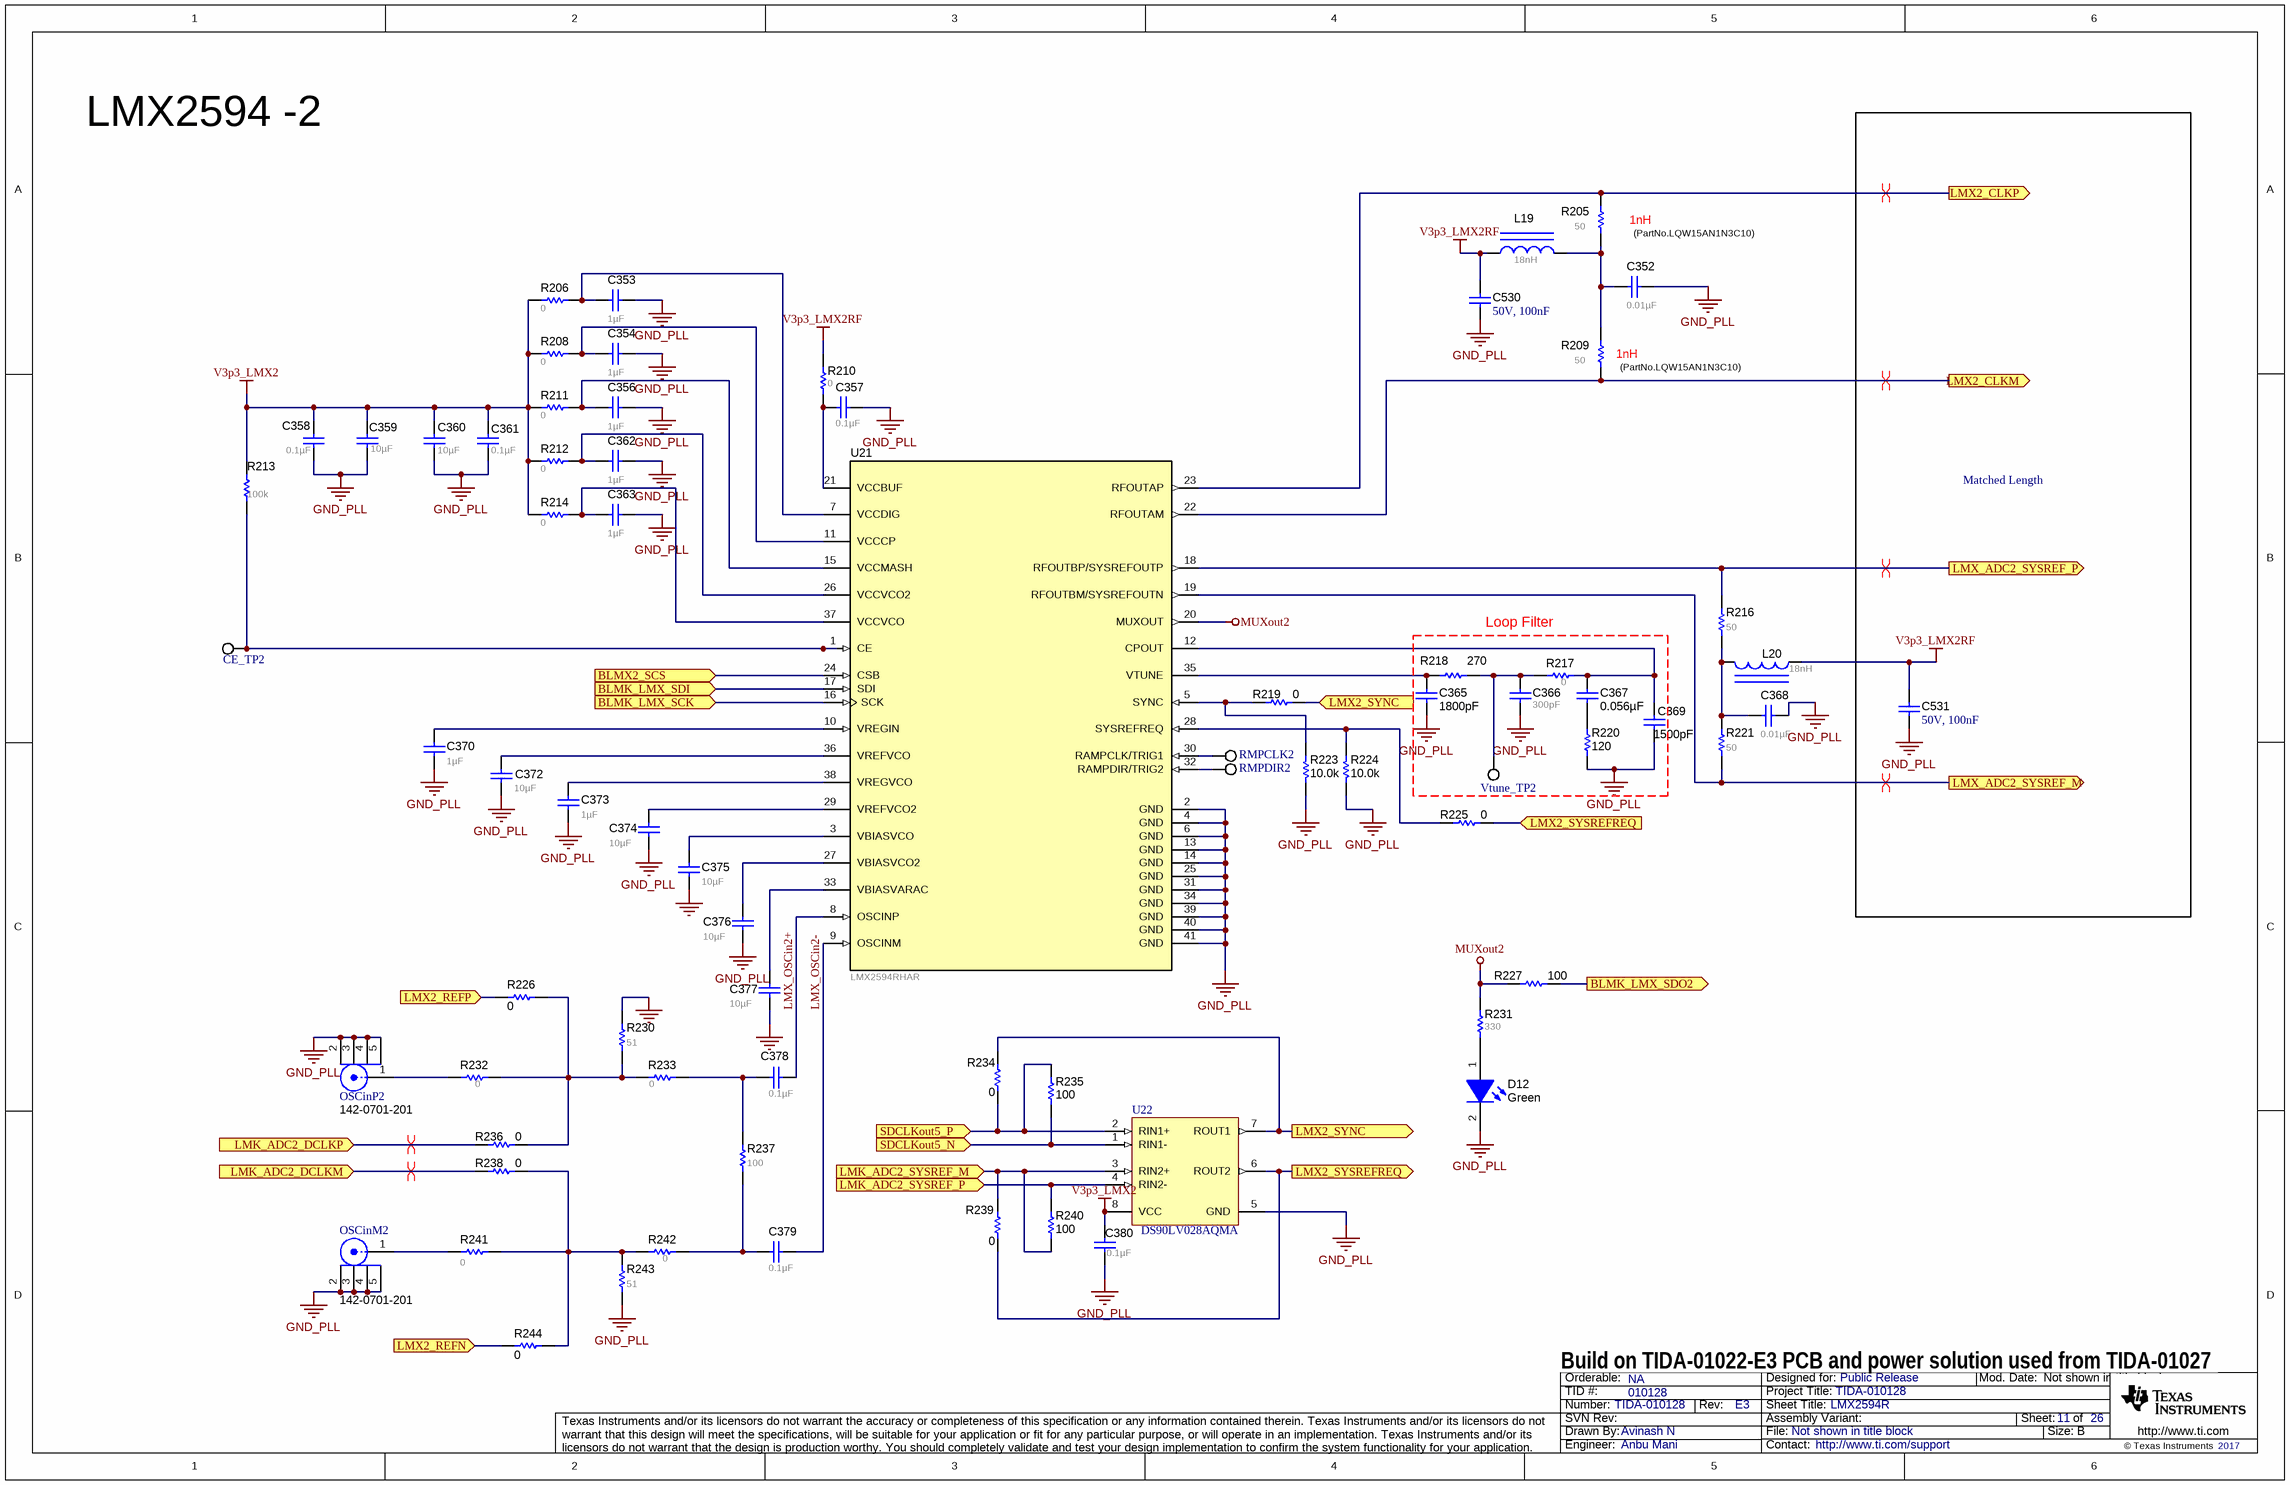
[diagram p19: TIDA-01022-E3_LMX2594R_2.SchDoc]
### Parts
C352  ValueDisplayed: 0.01µF  [0402_065]  (hidden comment: 520L103KT16T)
C353  ValueDisplayed: 1µF  [0603]  (hidden comment: C1608X7R1C105K080AC)
C354  ValueDisplayed: 1µF  [0603L]  (hidden comment: C1608X7R1C105K080AC)
C356  ValueDisplayed: 1µF  [0603L]  (hidden comment: C1608X7R1C105K080AC)
C357  ValueDisplayed: 0.1µF  [0603L]  (hidden comment: 0603YC104JAT2A)
C358  ValueDisplayed: 0.1µF  [0603]  (hidden comment: 0603YC104JAT2A)
C359  ValueDisplayed: 10µF  [0805]  (hidden comment: C0805C106K8PACTU)
C360  ValueDisplayed: 10µF  [0805]  (hidden comment: C0805C106K8PACTU)
C361  ValueDisplayed: 0.1µF  [0603]  (hidden comment: 0603YC104JAT2A)
C362  ValueDisplayed: 1µF  [0603]  (hidden comment: C1608X7R1C105K080AC)
C363  ValueDisplayed: 1µF  [0603]  (hidden comment: C1608X7R1C105K080AC)
C365  ValueDisplayed: 1800pF  [0603]  (hidden comment: GRM1885C1H182JA01D)
C366  ValueDisplayed: 300pF  [0603]  (hidden comment: GRM1885C2A301JA01D)
C367  ValueDisplayed: 0.056µF  [0603]  (hidden comment: C0603C563J4RACTU)
C368  ValueDisplayed: 0.01µF  [0402_065]  (hidden comment: 520L103KT16T)
C369  ValueDisplayed: 1500pF  [0603]  (hidden comment: 06031C152JAT2A)
C370  ValueDisplayed: 1µF  [0603]  (hidden comment: C1608X7R1C105K080AC)
C372  ValueDisplayed: 10µF  [0603]  (hidden comment: C1608X5R1A106M080AC)
C373  ValueDisplayed: 1µF  [0603]  (hidden comment: C1608X7R1C105K080AC)
C374  ValueDisplayed: 10µF  [0603]  (hidden comment: C1608X5R1A106M080AC)
C375  ValueDisplayed: 10µF  [0603]  (hidden comment: C1608X5R1A106M080AC)
C376  ValueDisplayed: 10µF  [0603]  (hidden comment: C1608X5R1A106M080AC)
C377  ValueDisplayed: 10µF  [0603]  (hidden comment: C1608X5R1A106M080AC)
C378  ValueDisplayed: 0.1µF  [0603L]  (hidden comment: 0603YC104JAT2A)
C379  ValueDisplayed: 0.1µF  [0603L]  (hidden comment: 0603YC104JAT2A)
C380  ValueDisplayed: 0.1µF  [0603]  (hidden comment: 0603YC104JAT2A)
C530  50V, 100nF  [0603_1.6x0.8x0.8mm_Reflow Soldering]
C531  50V, 100nF  [0603_1.6x0.8x0.8mm_Reflow Soldering]
CE_TP2  5002  [Keystone5002]  (value not drawn)
D12  value Green  [LTST-C191_Green]  (hidden comment: LTST-C191TGKT)
L19  ValueDisplayed: 18nH  [IND_LQG15H]  (hidden comment: LQG15HS18NJ02D)
L20  ValueDisplayed: 18nH  [IND_LQG15H]  (hidden comment: LQG15HS18NJ02D)
OSCinM2  142-0701-201  [Johnson_142-0701-20x]
OSCinP2  142-0701-201  [Johnson_142-0701-20x]
R205  ValueDisplayed: 50  [0402L]  (hidden comment: FC0402E50R0BST1)
R206  value 0  [0603]  (hidden comment: CRCW06030000Z0EA)
R208  value 0  [0603L]  (hidden comment: CRCW06030000Z0EA)
R209  ValueDisplayed: 50  [0402L]  (hidden comment: FC0402E50R0BST1)
R210  value 0  [0603L]  (hidden comment: CRCW06030000Z0EA)
R211  value 0  [0603L]  (hidden comment: CRCW06030000Z0EA)
R212  value 0  [0603]  (hidden comment: CRCW06030000Z0EA)
R213  ValueDisplayed: 100k  [0603]  (hidden comment: CRCW0603100KJNEA)
R214  value 0  [0603]  (hidden comment: CRCW06030000Z0EA)
R216  ValueDisplayed: 50  [0402L]  (hidden comment: FC0402E50R0BST1)
R217  ValueDisplayed: 0  [0603]  (hidden comment: CRCW06030000Z0EA)
R218  ValueDisplayed: 270  [0603]  (hidden comment: RC0603JR-07270RL)
R219  ValueDisplayed: 0  [0402]  (hidden comment: CRCW04020000Z0ED)
R220  ValueDisplayed: 120  [0603]  (hidden comment: RT0603DRE07120RL)
R221  ValueDisplayed: 50  [0402L]  (hidden comment: FC0402E50R0BST1)
R223  ValueDisplayed: 10.0k  [0402]  (hidden comment: CRCW040210K0DHEDP)
R224  ValueDisplayed: 10.0k  [0402]  (hidden comment: CRCW040210K0DHEDP)
R225  ValueDisplayed: 0  [0402]  (hidden comment: CRCW04020000Z0ED)
R226  ValueDisplayed: 0  [0402]  (hidden comment: CRCW04020000Z0ED)
R227  ValueDisplayed: 100  [0603]  (hidden comment: CRCW0603100RFKEA)
R230  ValueDisplayed: 51  [0603]  (hidden comment: CRCW060351R0JNEA)
R231  value 330  [0603]  (hidden comment: RC0603JR-07330RL)
R232  ValueDisplayed: 0  [0603]  (hidden comment: CRCW06030000Z0EA)
R233  ValueDisplayed: 0  [0603]  (hidden comment: CRCW06030000Z0EA)
R234  ValueDisplayed: 0  [0402]  (hidden comment: CRCW04020000Z0ED)
R235  ValueDisplayed: 100  [0402]  (hidden comment: CRCW0402100RJNED)
R236  ValueDisplayed: 0  [0402]  (hidden comment: CRCW04020000Z0ED)
R237  ValueDisplayed: 100  [0603L]  (hidden comment: CRCW0603100RFKEA)
R238  ValueDisplayed: 0  [0402]  (hidden comment: CRCW04020000Z0ED)
R239  ValueDisplayed: 0  [0402]  (hidden comment: CRCW04020000Z0ED)
R240  ValueDisplayed: 100  [0402]  (hidden comment: CRCW0402100RJNED)
R241  ValueDisplayed: 0  [0603]  (hidden comment: CRCW06030000Z0EA)
R242  ValueDisplayed: 0  [0603]  (hidden comment: CRCW06030000Z0EA)
R243  ValueDisplayed: 51  [0603]  (hidden comment: CRCW060351R0JNEA)
R244  ValueDisplayed: 0  [0402]  (hidden comment: CRCW04020000Z0ED)
RMPCLK2  5002  [Keystone5002]  (value not drawn)
RMPDIR2  5002  [Keystone5002]  (value not drawn)
U21  LMX2594RHAR  [RHA0040A]
U22  DS90LV028AQMA  [M08A_N]
Vtune_TP2  5002  [Keystone5002]  (value not drawn)

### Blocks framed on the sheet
Matched Length: C531
Loop Filter: C365-C367 C369 R217 R218 R220 Vtune_TP2

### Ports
BLMK_LMX_SCK (in), BLMK_LMX_SDI (in), BLMK_LMX_SDO2 (out), BLMX2_SCS (in), LMK_ADC2_DCLKM (in), LMK_ADC2_DCLKP (in), LMK_ADC2_SYSREF_M (in), LMK_ADC2_SYSREF_P (in), LMX2_CLKM (out), LMX2_CLKP (out), LMX2_REFN (in), LMX2_REFP (in), LMX2_SYNC (in), LMX2_SYNC (out), LMX2_SYSREFREQ (in), LMX2_SYSREFREQ (out), LMX_ADC2_SYSREF_M (out), LMX_ADC2_SYSREF_P (out), SDCLKout5_N (in), SDCLKout5_P (in)

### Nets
GND_PLL: C352.1 C353.1 C354.1 C356.2 C357.1 C358.1 C359.1 C360.1 C361.1 C362.1 C363.1 C365.1 C366.2 C368.1 C369.2 C370.1 C372.2 C373.1 C374.2 C375.2 C376.1 C377.1 C380.1 C530.2 C531.2 D12.2(K) OSCinM2.2 OSCinM2.3 OSCinM2.4 OSCinM2.5 OSCinP2.2 OSCinP2.3 OSCinP2.4 OSCinP2.5 R220.2 R223.2 R224.2 R230.2 R243.1 U21.2(GND) U21.4(GND) U21.6(GND) U21.13(GND) U21.14(GND) U21.25(GND) U21.31(GND) U21.34(GND) U21.39(GND) U21.40(GND) U21.41(GND) U22.5(GND)  [project net DGND]
MUXout2: R227.1 R231.2 U21.20(MUXOUT)
V3p3_LMX2: C358.2 C359.2 C360.2 C361.2 C380.2 R206.1 R208.1 R211.1 R212.2 R213.1 R214.2 U22.8(VCC)
V3p3_LMX2RF: C530.1 C531.1 L19.1 L20.1 R210.1
BLMK_LMX_SCK: U21.16(SCK) ; port BLMK_LMX_SCK
BLMK_LMX_SDI: U21.17(SDI) ; port BLMK_LMX_SDI
BLMK_LMX_SDO2: R227.2 ; port BLMK_LMX_SDO2
BLMX2_SCS: U21.24(CSB) ; port BLMX2_SCS
LMK_ADC2_DCLKM: R238.1 ; port LMK_ADC2_DCLKM
LMK_ADC2_DCLKP: R236.1 ; port LMK_ADC2_DCLKP
LMK_ADC2_SYSREF_M: R239.1 R240.1 U22.3(RIN2+) ; port LMK_ADC2_SYSREF_M
LMK_ADC2_SYSREF_P: R240.2 U22.4(RIN2-) ; port LMK_ADC2_SYSREF_P
LMX2_CLKM: R209.1 U21.22(RFOUTAM) ; port LMX2_CLKM
LMX2_CLKP: R205.1 U21.23(RFOUTAP) ; port LMX2_CLKP
LMX2_REFN: R244.1 ; port LMX2_REFN
LMX2_REFP: R226.2 ; port LMX2_REFP
LMX2_SYNC: R219.2 R234.1 U22.7(ROUT1) ; port LMX2_SYNC
LMX2_SYSREFREQ: R225.2 R239.2 U22.6(ROUT2) ; port LMX2_SYSREFREQ
LMX_ADC2_SYSREF_M: R221.1 U21.19(RFOUTBM/SYSREFOUTN) ; port LMX_ADC2_SYSREF_M
LMX_ADC2_SYSREF_P: R216.2 U21.18(RFOUTBP/SYSREFOUTP) ; port LMX_ADC2_SYSREF_P
LMX_OSCin2+: C378.2 U21.8(OSCINP)
LMX_OSCin2-: C379.2 U21.9(OSCINM)
SDCLKout5_N: R235.1 U22.1(RIN1-) ; port SDCLKout5_N
SDCLKout5_P: R234.2 R235.2 U22.2(RIN1+) ; port SDCLKout5_P
NetC352_2: C352.2 L19.2 R205.2 R209.2
NetC353_2: C353.2 R206.2 U21.7(VCCDIG)
NetC354_2: C354.2 R208.2 U21.11(VCCCP)
NetC356_1: C356.1 R211.2 U21.15(VCCMASH)
NetC357_2: C357.2 R210.2 U21.21(VCCBUF)
NetC362_2: C362.2 R212.1 U21.26(VCCVCO2)
NetC363_2: C363.2 R214.1 U21.37(VCCVCO)
NetC365_2: C365.2 R218.1 U21.35(VTUNE)
NetC366_1: C366.1 R217.2 R218.2 Vtune_TP2.1
NetC367_1: C367.1 C369.1 R217.1 U21.12(CPOUT)
NetC367_2: C367.2 R220.1
NetC368_2: C368.2 L20.2 R216.1 R221.2
NetC370_2: C370.2 U21.10(VREGIN)
NetC372_1: C372.1 U21.36(VREFVCO)
NetC373_2: C373.2 U21.38(VREGVCO)
NetC374_1: C374.1 U21.29(VREFVCO2)
NetC375_1: C375.1 U21.3(VBIASVCO)
NetC376_2: C376.2 U21.27(VBIASVCO2)
NetC377_2: C377.2 U21.33(VBIASVARAC)
NetC378_1: C378.1 R233.2 R237.2
NetC379_1: C379.1 R237.1 R242.1
NetCE_TP2_1: CE_TP2.1 R213.2 U21.1(CE)
NetD12_1: D12.1(A) R231.1
NetOSCinM2_1: OSCinM2.1 R241.1
NetOSCinP2_1: OSCinP2.1 R232.1
NetR219_1: R219.1 R223.1 U21.5(SYNC)
NetR224_1: R224.1 R225.1 U21.28(SYSREFREQ)
NetR226_1: R226.1 R230.1 R232.2 R233.1 R236.2
NetR238_2: R238.2 R241.2 R242.2 R243.2 R244.2
NetRMPCLK2_1: RMPCLK2.1 U21.30(RAMPCLK/TRIG1)
NetRMPDIR2_1: RMPDIR2.1 U21.32(RAMPDIR/TRIG2)

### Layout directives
differential pair: LMK_ADC2_DCLKM, LMK_ADC2_DCLKP, LMX2_CLKM, LMX2_CLKP, LMX_ADC2_SYSREF_M, LMX_ADC2_SYSREF_P

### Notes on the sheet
- LMX2594 -2
- (near R205) 1nH
- (PartNo.LQW15AN1N3C10)
- (near R209) 1nH
- (near R209) (PartNo.LQW15AN1N3C10)
- Build on TIDA-01022-E3 PCB and power solution used from TIDA-01027

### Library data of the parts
C352 C368 = 520L103KT16T: as C322 on sheet TIDA-01022-E3_LMX2594R_1
C353 C362 C363 = C1608X7R1C105K080AC: as C323 on sheet TIDA-01022-E3_LMX2594R_1
C354 C356 = C1608X7R1C105K080AC: as C324 on sheet TIDA-01022-E3_LMX2594R_1
C357 C378 C379 = 0603YC104JAT2A: as C327 on sheet TIDA-01022-E3_LMX2594R_1
C358 C361 C380 = 0603YC104JAT2A: as C328 on sheet TIDA-01022-E3_LMX2594R_1
C359 C360 = C0805C106K8PACTU: as C329 on sheet TIDA-01022-E3_LMX2594R_1
C365 = GRM1885C1H182JA01D: as C335 on sheet TIDA-01022-E3_LMX2594R_1
C366 = GRM1885C2A301JA01D: as C336 on sheet TIDA-01022-E3_LMX2594R_1
C367 = C0603C563J4RACTU: as C337 on sheet TIDA-01022-E3_LMX2594R_1
C369 = 06031C152JAT2A: as C339 on sheet TIDA-01022-E3_LMX2594R_1
C370 = C1608X7R1C105K080AC: as C340 on sheet TIDA-01022-E3_LMX2594R_1
C372 C374-C377 = C1608X5R1A106M080AC: as C342 on sheet TIDA-01022-E3_LMX2594R_1
C373 = C1608X7R1C105K080AC: as C343 on sheet TIDA-01022-E3_LMX2594R_1
C530 C531 = 885012206095: as C528 on sheet TIDA-01022-E3_LMX2594R_1
CE_TP2 RMPCLK2 RMPDIR2 Vtune_TP2 = 5002: as SYNC1 on sheet TIDA-01022-E3_LMK0482x _PWR
D12 = LTST-C191TGKT: as D13 on sheet TIDA-01022-E3_LMK0482x _PWR
L19 L20 = LQG15HS18NJ02D: as L17 on sheet TIDA-01022-E3_LMX2594R_1
OSCinM2 OSCinP2 = 142-0701-201: as J1-J4 on sheet TIDA-01022-E3_LMK0482x _PWR
R205 R209 R216 R221 = FC0402E50R0BST1: as R164 on sheet TIDA-01022-E3_LMX2594R_1
R206 R208 R210-R212 R214 = CRCW06030000Z0EA: as R165 on sheet TIDA-01022-E3_LMX2594R_1
R213 = CRCW0603100KJNEA: as R172 on sheet TIDA-01022-E3_LMX2594R_1
R217 R232 R233 R241 R242 = CRCW06030000Z0EA: as R177 on sheet TIDA-01022-E3_LMX2594R_1
R218 = RC0603JR-07270RL: as R176 on sheet TIDA-01022-E3_LMX2594R_1
R219 R225 R234 R236 R238 R239 = CRCW04020000Z0ED: as R229 on sheet TIDA-01022-E3_LMK0482x _PWR
R220 = RT0603DRE07120RL: as R179 on sheet TIDA-01022-E3_LMX2594R_1
R223 R224 = CRCW040210K0DHEDP: as R182 on sheet TIDA-01022-E3_LMX2594R_1
R226 R244 = CRCW04020000Z0ED: as R185 on sheet TIDA-01022-E3_LMX2594R_1
R227 = CRCW0603100RFKEA: as R187 on sheet TIDA-01022-E3_LMX2594R_1
R230 R243 = CRCW060351R0JNEA: as R189 on sheet TIDA-01022-E3_LMX2594R_1
R231 = RC0603JR-07330RL: as R190 on sheet TIDA-01022-E3_LMX2594R_1
R235 R240 = CRCW0402100RJNED: as R194 on sheet TIDA-01022-E3_LMX2594R_1
R237 = CRCW0603100RFKEA: as R196 on sheet TIDA-01022-E3_LMX2594R_1
U21 = LMX2594RHAR: as U19 on sheet TIDA-01022-E3_LMX2594R_1
U22 = DS90LV028AQMA: as U20 on sheet TIDA-01022-E3_LMX2594R_1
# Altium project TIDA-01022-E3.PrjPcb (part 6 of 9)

## Sheet TIDA-01022-E3_Programming for ADC_LMK _LMX.SchDoc: Programming for ADC, LMK , LMX
size 431 x 279 mm; Date: Not shown in title block; ApprovedBy: Not shown in title block; CheckedBy: Not shown in title block; Author: Not shown in title block; CompanyName: Not shown in title block; DrawnBy: Avinash N; Engineer: Anbu Mani; Organization: Not shown in title block; Address1: Not shown in title block; Address2: Not shown in title block; Address3: Not shown in title block; Address4: Not shown in title block; DocumentNumber: 1; Revision: Use project parameter SCH_Rev; SheetNumber: 15; SheetTotal: 26; PageSetup: Record=PageOptions¦CenterHorizontal=True¦CenterVertical=True¦PrintScale=1.00¦XCorrection=1.00¦YCorrection=1.00¦PrintKind=0¦BorderSize=5000000¦LeftOffset=0¦BottomOffset=0¦Orientation=2¦PaperLength=1000¦PaperWidth=1000¦Scale=100¦PaperSource=15¦PrintQuality=600¦MediaType=1¦DitherType=10¦PaperKind=Letter¦PrintScaleMode=1

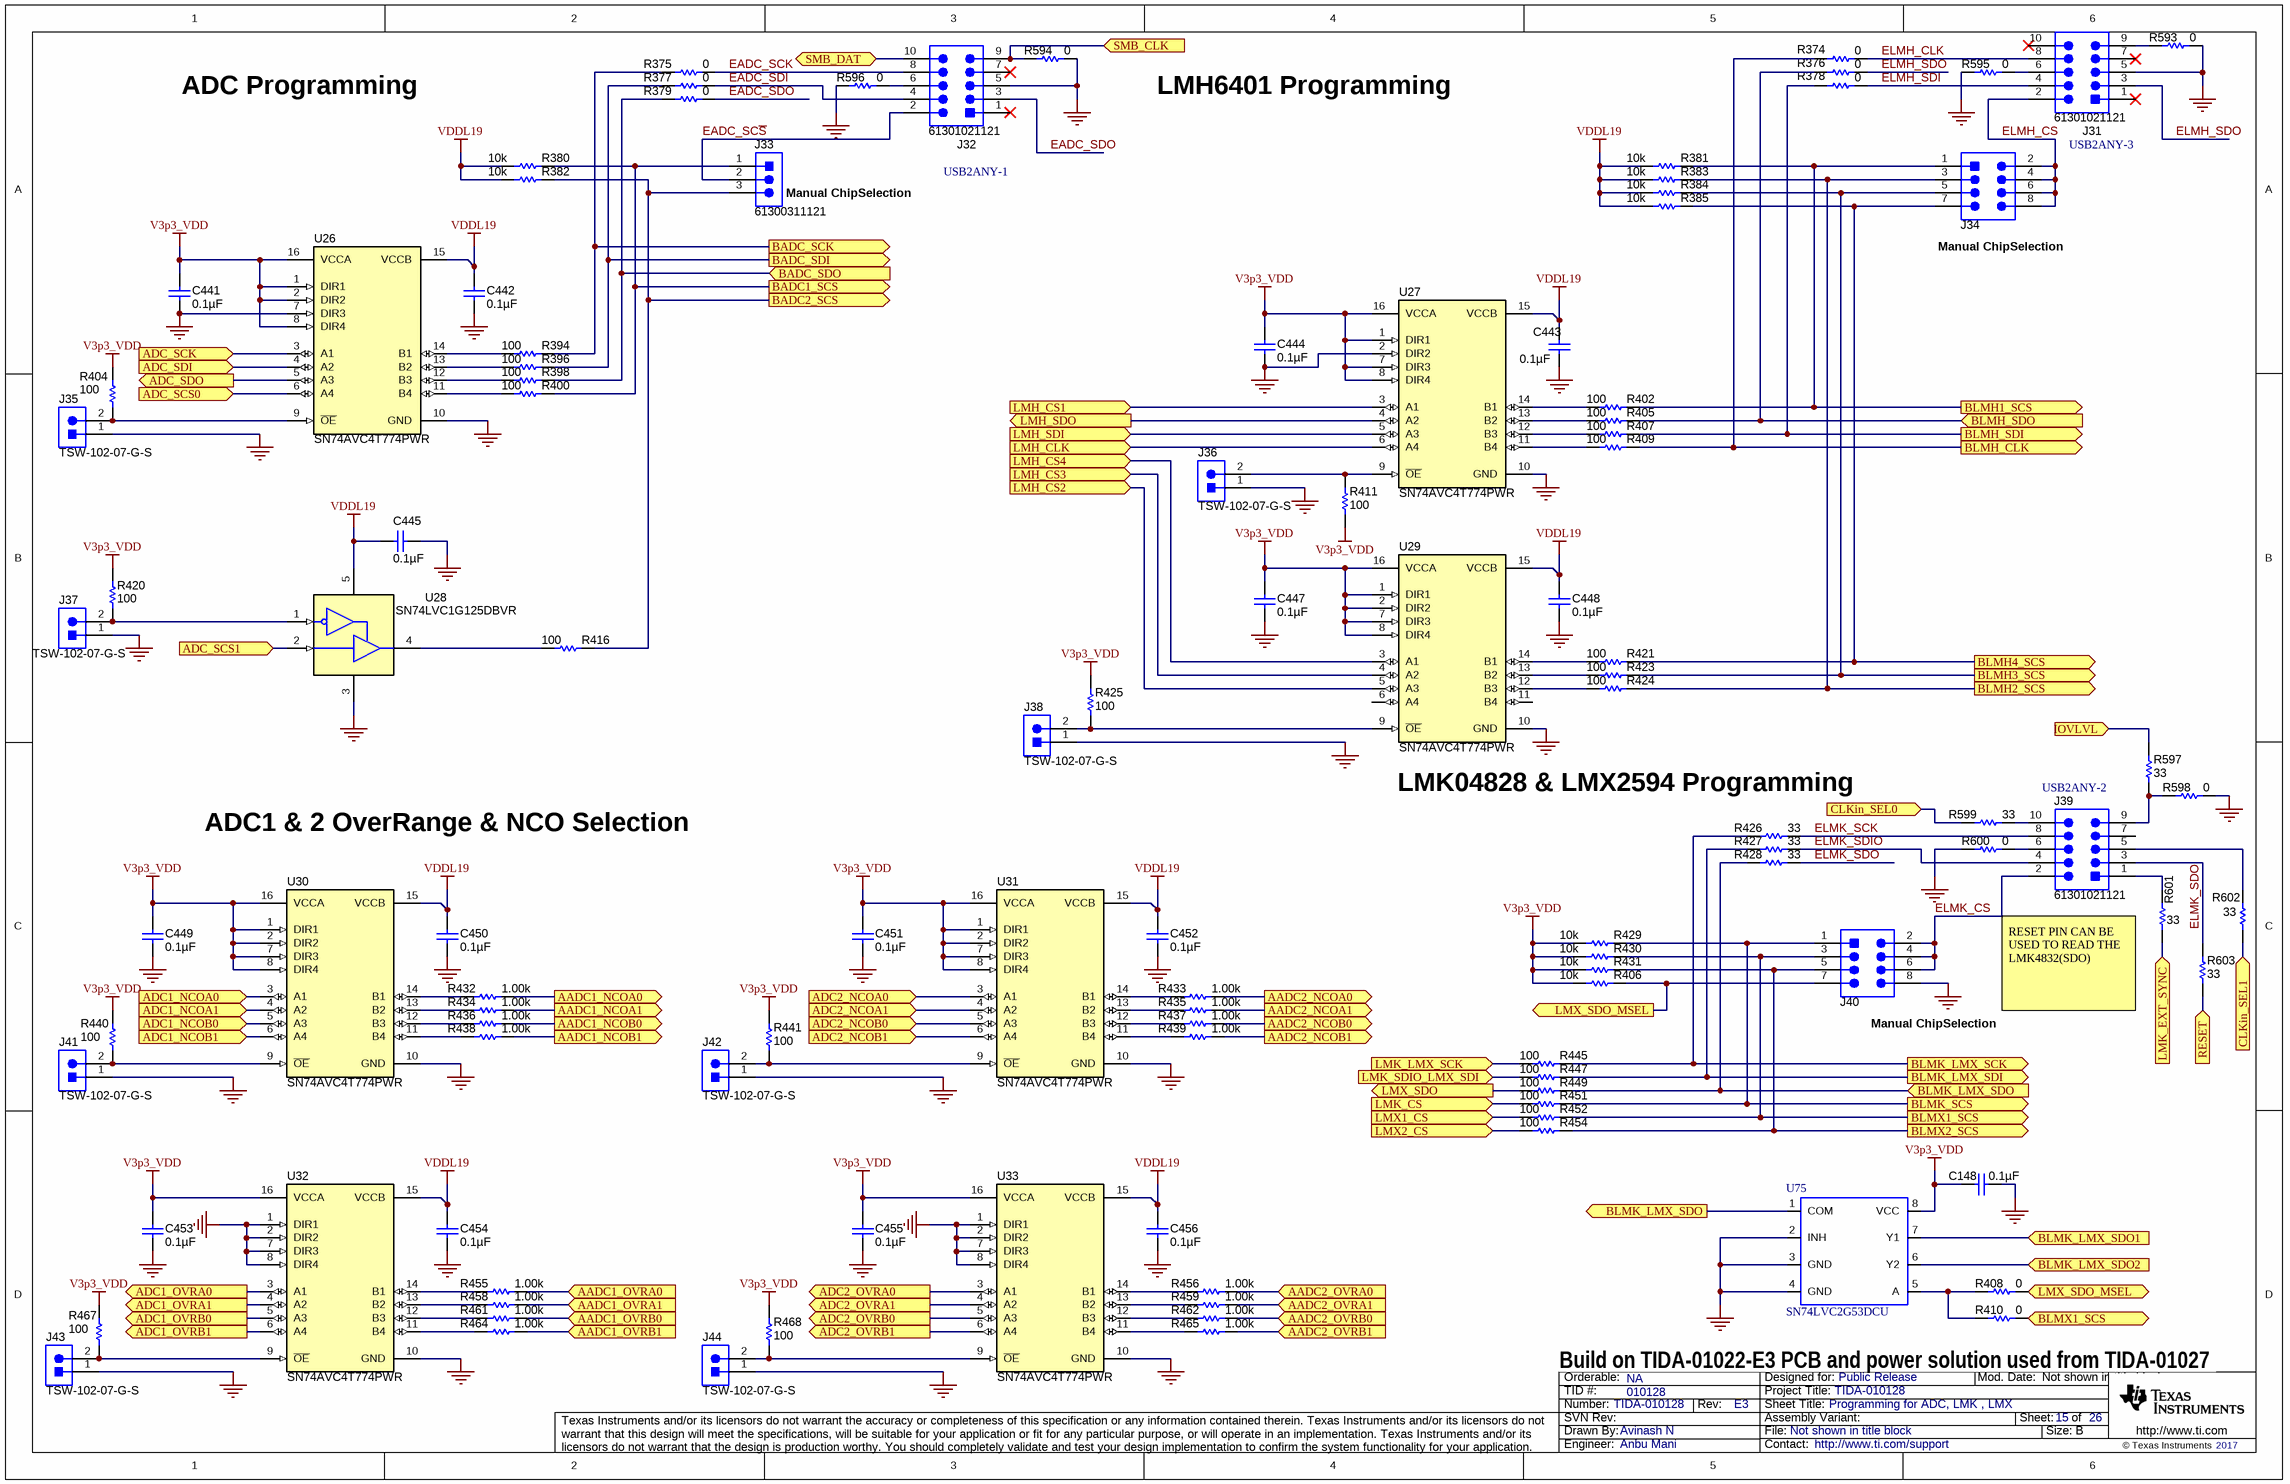
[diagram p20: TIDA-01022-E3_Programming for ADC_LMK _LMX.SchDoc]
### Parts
C148  ValueDisplayed: 0.1µF  [0603]  (hidden comment: C0603C104J3RACTU)
C441  ValueDisplayed: 0.1µF  [0603]  (hidden comment: C0603C104J3RACTU)
C442  ValueDisplayed: 0.1µF  [0603]  (hidden comment: C0603C104J3RACTU)
C443  ValueDisplayed: 0.1µF  [0603]  (hidden comment: C0603C104J3RACTU)
C444  ValueDisplayed: 0.1µF  [0603]  (hidden comment: C0603C104J3RACTU)
C445  ValueDisplayed: 0.1µF  [0603]  (hidden comment: C0603C104J3RACTU)
C447  ValueDisplayed: 0.1µF  [0603]  (hidden comment: C0603C104J3RACTU)
C448  ValueDisplayed: 0.1µF  [0603]  (hidden comment: C0603C104J3RACTU)
C449  ValueDisplayed: 0.1µF  [0603]  (hidden comment: C0603C104J3RACTU)
C450  ValueDisplayed: 0.1µF  [0603]  (hidden comment: C0603C104J3RACTU)
C451  ValueDisplayed: 0.1µF  [0603]  (hidden comment: C0603C104J3RACTU)
C452  ValueDisplayed: 0.1µF  [0603]  (hidden comment: C0603C104J3RACTU)
C453  ValueDisplayed: 0.1µF  [0603]  (hidden comment: C0603C104J3RACTU)
C454  ValueDisplayed: 0.1µF  [0603]  (hidden comment: C0603C104J3RACTU)
C455  ValueDisplayed: 0.1µF  [0603]  (hidden comment: C0603C104J3RACTU)
C456  ValueDisplayed: 0.1µF  [0603]  (hidden comment: C0603C104J3RACTU)
J31  61301021121  [WURTH_61301021121]
J32  61301021121  [WURTH_61301021121]
J33  61300311121  [WURTH_61300311121]
J34  TSW-104-07-G-D  [TSW-104-07-G-D]  (value not drawn)
J35  TSW-102-07-G-S  [TSW-102-07-G-S]
J36  TSW-102-07-G-S  [TSW-102-07-G-S]
J37  TSW-102-07-G-S  [TSW-102-07-G-S]
J38  TSW-102-07-G-S  [TSW-102-07-G-S]
J39  61301021121  [WURTH_61301021121]
J40  TSW-104-07-G-D  [TSW-104-07-G-D]  (value not drawn)
J41  TSW-102-07-G-S  [TSW-102-07-G-S]
J42  TSW-102-07-G-S  [TSW-102-07-G-S]
J43  TSW-102-07-G-S  [TSW-102-07-G-S]
J44  TSW-102-07-G-S  [TSW-102-07-G-S]
R374  ValueDisplayed: 0  [0603]  (hidden comment: CRCW06030000Z0EA)
R375  ValueDisplayed: 0  [0603]  (hidden comment: CRCW06030000Z0EA)
R376  ValueDisplayed: 0  [0603]  (hidden comment: CRCW06030000Z0EA)
R377  ValueDisplayed: 0  [0603]  (hidden comment: CRCW06030000Z0EA)
R378  ValueDisplayed: 0  [0603]  (hidden comment: CRCW06030000Z0EA)
R379  ValueDisplayed: 0  [0603]  (hidden comment: CRCW06030000Z0EA)
R380  ValueDisplayed: 10k  [0603]  (hidden comment: CRCW060310K0JNEA)
R381  ValueDisplayed: 10k  [0603]  (hidden comment: CRCW060310K0JNEA)
R382  ValueDisplayed: 10k  [0603]  (hidden comment: CRCW060310K0JNEA)
R383  ValueDisplayed: 10k  [0603]  (hidden comment: CRCW060310K0JNEA)
R384  ValueDisplayed: 10k  [0603]  (hidden comment: CRCW060310K0JNEA)
R385  ValueDisplayed: 10k  [0603]  (hidden comment: CRCW060310K0JNEA)
R394  ValueDisplayed: 100  [0603]  (hidden comment: RC0603FR-07100RL)
R396  ValueDisplayed: 100  [0603]  (hidden comment: RC0603FR-07100RL)
R398  ValueDisplayed: 100  [0603]  (hidden comment: RC0603FR-07100RL)
R400  ValueDisplayed: 100  [0603]  (hidden comment: RC0603FR-07100RL)
R402  ValueDisplayed: 100  [0603]  (hidden comment: RC0603FR-07100RL)
R404  ValueDisplayed: 100  [0603]  (hidden comment: RC0603FR-07100RL)
R405  ValueDisplayed: 100  [0603]  (hidden comment: RC0603FR-07100RL)
R406  ValueDisplayed: 10k  [0603]  (hidden comment: CRCW060310K0JNEA)
R407  ValueDisplayed: 100  [0603]  (hidden comment: RC0603FR-07100RL)
R408  ValueDisplayed: 0  [0603]  (hidden comment: CRCW06030000Z0EA)
R409  ValueDisplayed: 100  [0603]  (hidden comment: RC0603FR-07100RL)
R410  ValueDisplayed: 0  [0603]  (hidden comment: CRCW06030000Z0EA)
R411  ValueDisplayed: 100  [0603]  (hidden comment: RC0603FR-07100RL)
R416  ValueDisplayed: 100  [0603]  (hidden comment: RC0603FR-07100RL)
R420  ValueDisplayed: 100  [0603]  (hidden comment: RC0603FR-07100RL)
R421  ValueDisplayed: 100  [0603]  (hidden comment: RC0603FR-07100RL)
R423  ValueDisplayed: 100  [0603]  (hidden comment: RC0603FR-07100RL)
R424  ValueDisplayed: 100  [0603]  (hidden comment: RC0603FR-07100RL)
R425  ValueDisplayed: 100  [0603]  (hidden comment: RC0603FR-07100RL)
R426  ValueDisplayed: 33  [0603]  (hidden comment: CRCW060333R0JNEA)
R427  ValueDisplayed: 33  [0603]  (hidden comment: CRCW060333R0JNEA)
R428  ValueDisplayed: 33  [0603]  (hidden comment: CRCW060333R0JNEA)
R429  ValueDisplayed: 10k  [0603]  (hidden comment: CRCW060310K0JNEA)
R430  ValueDisplayed: 10k  [0603]  (hidden comment: CRCW060310K0JNEA)
R431  ValueDisplayed: 10k  [0603]  (hidden comment: CRCW060310K0JNEA)
R432  ValueDisplayed: 1.00k  [0603]  (hidden comment: CRCW06031K00FKEA)
R433  ValueDisplayed: 1.00k  [0603]  (hidden comment: CRCW06031K00FKEA)
R434  ValueDisplayed: 1.00k  [0603]  (hidden comment: CRCW06031K00FKEA)
R435  ValueDisplayed: 1.00k  [0603]  (hidden comment: CRCW06031K00FKEA)
R436  ValueDisplayed: 1.00k  [0603]  (hidden comment: CRCW06031K00FKEA)
R437  ValueDisplayed: 1.00k  [0603]  (hidden comment: CRCW06031K00FKEA)
R438  ValueDisplayed: 1.00k  [0603]  (hidden comment: CRCW06031K00FKEA)
R439  ValueDisplayed: 1.00k  [0603]  (hidden comment: CRCW06031K00FKEA)
R440  ValueDisplayed: 100  [0603]  (hidden comment: RC0603FR-07100RL)
R441  ValueDisplayed: 100  [0603]  (hidden comment: RC0603FR-07100RL)
R445  ValueDisplayed: 100  [0603]  (hidden comment: RC0603FR-07100RL)
R447  ValueDisplayed: 100  [0603]  (hidden comment: RC0603FR-07100RL)
R449  ValueDisplayed: 100  [0603]  (hidden comment: RC0603FR-07100RL)
R451  ValueDisplayed: 100  [0603]  (hidden comment: RC0603FR-07100RL)
R452  ValueDisplayed: 100  [0603]  (hidden comment: RC0603FR-07100RL)
R454  ValueDisplayed: 100  [0603]  (hidden comment: RC0603FR-07100RL)
R455  ValueDisplayed: 1.00k  [0603]  (hidden comment: CRCW06031K00FKEA)
R456  ValueDisplayed: 1.00k  [0603]  (hidden comment: CRCW06031K00FKEA)
R458  ValueDisplayed: 1.00k  [0603]  (hidden comment: CRCW06031K00FKEA)
R459  ValueDisplayed: 1.00k  [0603]  (hidden comment: CRCW06031K00FKEA)
R461  ValueDisplayed: 1.00k  [0603]  (hidden comment: CRCW06031K00FKEA)
R462  ValueDisplayed: 1.00k  [0603]  (hidden comment: CRCW06031K00FKEA)
R464  ValueDisplayed: 1.00k  [0603]  (hidden comment: CRCW06031K00FKEA)
R465  ValueDisplayed: 1.00k  [0603]  (hidden comment: CRCW06031K00FKEA)
R467  ValueDisplayed: 100  [0603]  (hidden comment: RC0603FR-07100RL)
R468  ValueDisplayed: 100  [0603]  (hidden comment: RC0603FR-07100RL)
R593  ValueDisplayed: 0  [0603]  (hidden comment: CRCW06030000Z0EA)
R594  ValueDisplayed: 0  [0603]  (hidden comment: CRCW06030000Z0EA)
R595  ValueDisplayed: 0  [0603]  (hidden comment: CRCW06030000Z0EA)
R596  ValueDisplayed: 0  [0603]  (hidden comment: CRCW06030000Z0EA)
R597  ValueDisplayed: 33  [0603]  (hidden comment: CRCW060333R0JNEA)
R598  ValueDisplayed: 0  [0603]  (hidden comment: CRCW06030000Z0EA)
R599  ValueDisplayed: 33  [0603]  (hidden comment: CRCW060333R0JNEA)
R600  ValueDisplayed: 0  [0603]  (hidden comment: CRCW06030000Z0EA)
R601  ValueDisplayed: 33  [0603]  (hidden comment: CRCW060333R0JNEA)
R602  ValueDisplayed: 33  [0603]  (hidden comment: CRCW060333R0JNEA)
R603  ValueDisplayed: 33  [0603]  (hidden comment: CRCW060333R0JNEA)
U26  SN74AVC4T774PWR  [PW0016A_N]
U27  SN74AVC4T774PWR  [PW0016A_N]
U28  SN74LVC1G125DBVR  [DBV0005A_N]
U29  SN74AVC4T774PWR  [PW0016A_N]
U30  SN74AVC4T774PWR  [PW0016A_N]
U31  SN74AVC4T774PWR  [PW0016A_N]
U32  SN74AVC4T774PWR  [PW0016A_N]
U33  SN74AVC4T774PWR  [PW0016A_N]
U75  SN74LVC2G53DCU  [DCU0008A_N]

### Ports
AADC1_NCOA0 (out), AADC1_NCOA1 (out), AADC1_NCOB0 (out), AADC1_NCOB1 (out), AADC1_OVRA0 (in), AADC1_OVRA1 (in), AADC1_OVRB0 (in), AADC1_OVRB1 (in), AADC2_NCOA0 (out), AADC2_NCOA1 (out), AADC2_NCOB0 (out), AADC2_NCOB1 (out), AADC2_OVRA0 (in), AADC2_OVRA1 (in), AADC2_OVRB0 (in), AADC2_OVRB1 (in), ADC1_NCOA0 (in), ADC1_NCOA1 (in), ADC1_NCOB0 (in), ADC1_NCOB1 (in), ADC1_OVRA0 (out), ADC1_OVRA1 (out), ADC1_OVRB0 (out), ADC1_OVRB1 (out), ADC2_NCOA0 (in), ADC2_NCOA1 (in), ADC2_NCOB0 (in), ADC2_NCOB1 (in), ADC2_OVRA0 (out), ADC2_OVRA1 (out), ADC2_OVRB0 (out), ADC2_OVRB1 (out), ADC_SCK (in), ADC_SCS0 (in), ADC_SCS1 (in), ADC_SDI (in), ADC_SDO (out), BADC1_SCS (out), BADC2_SCS (out), BADC_SCK (out), BADC_SDI (out), BADC_SDO (in), BLMH1_SCS (out), BLMH2_SCS (out), BLMH3_SCS (out), BLMH4_SCS (out), BLMH_CLK (out), BLMH_SDI (out), BLMH_SDO (in), BLMK_LMX_SCK (out), BLMK_LMX_SDI (out), BLMK_LMX_SDO1 (in), BLMK_LMX_SDO2 (in), BLMK_LMX_SDO (in), BLMK_LMX_SDO (out), BLMK_SCS (out), BLMX1_SCS (in), BLMX1_SCS (out), BLMX2_SCS (out), CLKin_SEL0 (in), CLKin_SEL1 (in), IOVLVL (in), LMH_CLK (in), LMH_CS1 (in), LMH_CS2 (in), LMH_CS3 (in), LMH_CS4 (in), LMH_SDI (in), LMH_SDO (out), LMK_CS (in), LMK_EXT_SYNC (in), LMK_LMX_SCK (in), LMK_SDIO_LMX_SDI (in), LMX1_CS (in), LMX2_CS (in), LMX_SDO (out), LMX_SDO_MSEL (in), LMX_SDO_MSEL (out), RESET (in), SMB_CLK (in), SMB_DAT (bidir)

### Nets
GND_PLL: C148.2 C441.1 C442.1 C443.1 C444.1 C445.1 C447.1 C448.1 C449.1 C450.1 C451.1 C452.1 C453.1 C454.1 C455.1 C456.1 J31.5 J32.5 J35.1 J36.1 J37.1 J38.1 J40.8 J41.1 J42.1 J43.1 J44.1 R593.2 R594.2 R595.1 R596.1 R598.2 R600.1 U26.7(DIR3) U26.10(GND) U27.2(DIR2) U27.10(GND) U28.3(GND) U29.10(GND) U30.10(GND) U31.10(GND) U32.1(DIR1) U32.2(DIR2) U32.7(DIR3) U32.8(DIR4) U32.10(GND) U33.1(DIR1) U33.2(DIR2) U33.7(DIR3) U33.8(DIR4) U33.10(GND) U75.2(INH) U75.3(GND) U75.4(GND)  [project net DGND]
V3p3_VDD: C148.1 C441.2 C444.2 C447.2 C449.2 C451.2 C453.2 C455.2 R404.1 R406.1 R411.1 R420.1 R425.1 R429.1 R430.1 R431.1 R440.1 R441.1 R467.1 R468.1 U26.1(DIR1) U26.2(DIR2) U26.8(DIR4) U26.16(VCCA) U27.1(DIR1) U27.7(DIR3) U27.8(DIR4) U27.16(VCCA) U29.1(DIR1) U29.2(DIR2) U29.7(DIR3) U29.8(DIR4) U29.16(VCCA) U30.1(DIR1) U30.2(DIR2) U30.7(DIR3) U30.8(DIR4) U30.16(VCCA) U31.1(DIR1) U31.2(DIR2) U31.7(DIR3) U31.8(DIR4) U31.16(VCCA) U32.16(VCCA) U33.16(VCCA) U75.8(VCC)
VDDL19: C442.2 C443.2 C445.2 C448.2 C450.2 C452.2 C454.2 C456.2 R380.1 R381.1 R382.1 R383.1 R384.1 R385.1 U26.15(VCCB) U27.15(VCCB) U28.5(VCC) U29.15(VCCB) U30.15(VCCB) U31.15(VCCB) U32.15(VCCB) U33.15(VCCB)
AADC1_NCOA0: R432.2 ; port AADC1_NCOA0
AADC1_NCOA1: R434.2 ; port AADC1_NCOA1
AADC1_NCOB0: R436.2 ; port AADC1_NCOB0
AADC1_NCOB1: R438.2 ; port AADC1_NCOB1
AADC1_OVRA0: R455.2 ; port AADC1_OVRA0
AADC1_OVRA1: R458.2 ; port AADC1_OVRA1
AADC1_OVRB0: R461.2 ; port AADC1_OVRB0
AADC1_OVRB1: R464.2 ; port AADC1_OVRB1
AADC2_NCOA0: R433.2 ; port AADC2_NCOA0
AADC2_NCOA1: R435.2 ; port AADC2_NCOA1
AADC2_NCOB0: R437.2 ; port AADC2_NCOB0
AADC2_NCOB1: R439.2 ; port AADC2_NCOB1
AADC2_OVRA0: R456.2 ; port AADC2_OVRA0
AADC2_OVRA1: R459.2 ; port AADC2_OVRA1
AADC2_OVRB0: R462.2 ; port AADC2_OVRB0
AADC2_OVRB1: R465.2 ; port AADC2_OVRB1
ADC1_NCOA0: U30.3(A1) ; port ADC1_NCOA0
ADC1_NCOA1: U30.4(A2) ; port ADC1_NCOA1
ADC1_NCOB0: U30.5(A3) ; port ADC1_NCOB0
ADC1_NCOB1: U30.6(A4) ; port ADC1_NCOB1
ADC1_OVRA0: U32.3(A1) ; port ADC1_OVRA0
ADC1_OVRA1: U32.4(A2) ; port ADC1_OVRA1
ADC1_OVRB0: U32.5(A3) ; port ADC1_OVRB0
ADC1_OVRB1: U32.6(A4) ; port ADC1_OVRB1
ADC2_NCOA0: U31.3(A1) ; port ADC2_NCOA0
ADC2_NCOA1: U31.4(A2) ; port ADC2_NCOA1
ADC2_NCOB0: U31.5(A3) ; port ADC2_NCOB0
ADC2_NCOB1: U31.6(A4) ; port ADC2_NCOB1
ADC2_OVRA0: U33.3(A1) ; port ADC2_OVRA0
ADC2_OVRA1: U33.4(A2) ; port ADC2_OVRA1
ADC2_OVRB0: U33.5(A3) ; port ADC2_OVRB0
ADC2_OVRB1: U33.6(A4) ; port ADC2_OVRB1
ADC_SCK: U26.3(A1) ; port ADC_SCK
ADC_SCS0: U26.6(A4) ; port ADC_SCS0
ADC_SCS1: U28.2(A) ; port ADC_SCS1
ADC_SDI: U26.4(A2) ; port ADC_SDI
ADC_SDO: U26.5(A3) ; port ADC_SDO
BADC1_SCS: J33.1 R380.2 R400.2 ; port BADC1_SCS
BADC2_SCS: J33.3 R382.2 R416.2 ; port BADC2_SCS
BADC_SCK: R375.1 R394.2 ; port BADC_SCK
BADC_SDI: R377.1 R396.2 ; port BADC_SDI
BADC_SDO: R379.1 R398.2 ; port BADC_SDO
BLMH1_SCS: J34.1 R381.2 R402.2 ; port BLMH1_SCS
BLMH2_SCS: J34.3 R383.2 R424.2 ; port BLMH2_SCS
BLMH3_SCS: J34.5 R384.2 R423.2 ; port BLMH3_SCS
BLMH4_SCS: J34.7 R385.2 R421.2 ; port BLMH4_SCS
BLMH_CLK: R374.1 R409.2 ; port BLMH_CLK
BLMH_SDI: R378.1 R407.2 ; port BLMH_SDI
BLMH_SDO: R376.1 R405.2 ; port BLMH_SDO
BLMK_LMX_SCK: R426.1 R445.2 ; port BLMK_LMX_SCK
BLMK_LMX_SDI: R427.1 R447.2 ; port BLMK_LMX_SDI
BLMK_LMX_SDO: R428.1 R449.2 U75.1(COM) ; port BLMK_LMX_SDO
BLMK_LMX_SDO1: U75.7(Y1) ; port BLMK_LMX_SDO1
BLMK_LMX_SDO2: U75.6(Y2) ; port BLMK_LMX_SDO2
BLMK_SCS: J40.1 R429.2 R451.2 ; port BLMK_SCS
BLMX1_SCS: J40.3 R410.2 R430.2 R452.2 ; port BLMX1_SCS
BLMX2_SCS: J40.5 R431.2 R454.2 ; port BLMX2_SCS
CLKin_SEL0: R599.2 ; port CLKin_SEL0
CLKin_SEL1: R602.1 ; port CLKin_SEL1
EADC_SCK: J32.8 R375.2
EADC_SC~{S}: J32.2 J33.2
EADC_SDI: J32.4 R377.2
EADC_SDO: J32.3 R379.2
ELMH_CLK: J31.8 R374.2
ELMH_CS: J31.2 J34.2 J34.4 J34.6 J34.8
ELMH_SDI: J31.4 R378.2
ELMH_SDO: J31.3 R376.2
ELMK_CS: J39.2 J40.2 J40.4 J40.6
ELMK_SCK: J39.8 R426.2
ELMK_SDIO: J39.4 R427.2
ELMK_SDO: J39.3 R428.2 R603.2
IOVLVL: R597.2 ; port IOVLVL
LMH_CLK: U27.6(A4) ; port LMH_CLK
LMH_CS1: U27.3(A1) ; port LMH_CS1
LMH_CS2: U29.5(A3) ; port LMH_CS2
LMH_CS3: U29.4(A2) ; port LMH_CS3
LMH_CS4: U29.3(A1) ; port LMH_CS4
LMH_SDI: U27.5(A3) ; port LMH_SDI
LMH_SDO: U27.4(A2) ; port LMH_SDO
LMK_CS: R451.1 ; port LMK_CS
LMK_EXT_SYNC: R601.1 ; port LMK_EXT_SYNC
LMK_LMX_SCK: R445.1 ; port LMK_LMX_SCK
LMK_SDIO_LMX_SDI: R447.1 ; port LMK_SDIO_LMX_SDI
LMX1_CS: R452.1 ; port LMX1_CS
LMX2_CS: R454.1 ; port LMX2_CS
LMX_SDO: R449.1 ; port LMX_SDO
LMX_SDO_MSEL: J40.7 R406.2 R408.2 ; port LMX_SDO_MSEL
RESET: R603.1 ; port RESET
SMB_CLK: J32.9 R594.1 ; port SMB_CLK
SMB_DAT: J32.10 ; port SMB_DAT
NetJ31_6: J31.6 R595.2
NetJ31_9: J31.9 R593.1
NetJ32_6: J32.6 R596.2
NetJ35_2: J35.2 R404.2 U26.9(~{OE})
NetJ36_2: J36.2 R411.2 U27.9(~{OE})
NetJ37_2: J37.2 R420.2 U28.1(~{OE})
NetJ38_2: J38.2 R425.2 U29.9(~{OE})
NetJ39_1: J39.1 R601.2
NetJ39_5: J39.5 R602.2
NetJ39_6: J39.6 R600.2
NetJ39_9: J39.9 R597.1 R598.1
NetJ39_10: J39.10 R599.1
NetJ41_2: J41.2 R440.2 U30.9(~{OE})
NetJ42_2: J42.2 R441.2 U31.9(~{OE})
NetJ43_2: J43.2 R467.2 U32.9(~{OE})
NetJ44_2: J44.2 R468.2 U33.9(~{OE})
NetR394_1: R394.1 U26.14(B1)
NetR396_1: R396.1 U26.13(B2)
NetR398_1: R398.1 U26.12(B3)
NetR400_1: R400.1 U26.11(B4)
NetR402_1: R402.1 U27.14(B1)
NetR405_1: R405.1 U27.13(B2)
NetR407_1: R407.1 U27.12(B3)
NetR408_1: R408.1 R410.1 U75.5(A)
NetR409_1: R409.1 U27.11(B4)
NetR416_1: R416.1 U28.4(Y)
NetR421_1: R421.1 U29.14(B1)
NetR423_1: R423.1 U29.13(B2)
NetR424_1: R424.1 U29.12(B3)
NetR432_1: R432.1 U30.14(B1)
NetR433_1: R433.1 U31.14(B1)
NetR434_1: R434.1 U30.13(B2)
NetR435_1: R435.1 U31.13(B2)
NetR436_1: R436.1 U30.12(B3)
NetR437_1: R437.1 U31.12(B3)
NetR438_1: R438.1 U30.11(B4)
NetR439_1: R439.1 U31.11(B4)
NetR455_1: R455.1 U32.14(B1)
NetR456_1: R456.1 U33.14(B1)
NetR458_1: R458.1 U32.13(B2)
NetR459_1: R459.1 U33.13(B2)
NetR461_1: R461.1 U32.12(B3)
NetR462_1: R462.1 U33.12(B3)
NetR464_1: R464.1 U32.11(B4)
NetR465_1: R465.1 U33.11(B4)

Not connected (* = marked no-connect by the designer): J31 1* 7* 10*; J32 1* 7*; J39 7; U29 6(A4) 11(B4)

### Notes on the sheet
- ADC Programming
- LMH6401 Programming
- USB2ANY-3
- (near J33) Manual ChipSelection
- USB2ANY-1
- (near J34) Manual ChipSelection
- ADC1 & 2 OverRange & NCO Selection
- LMK04828 & LMX2594 Programming
- (near J39) USB2ANY-2
- (near J40) Manual ChipSelection
- RESET PIN CAN BE USED TO READ THE LMK4832(SDO)
- (near R410) Build on TIDA-01022-E3 PCB and power solution used from TIDA-01027

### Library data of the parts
C148 C441-C445 C447-C456 = C0603C104J3RACTU: CAP, CERM, 0.1uF, 25V, +/-5%, X7R, 0603; Manufacturer: Kemet; Polarized: N; TaMax_C: 125; TaMin_C: -55; Tolerance_%: 5; VDC_V: 25; Cap_F: 0.0000001; CompType: Capacitor; Value1: Unknown; U/M: EA
J31 J32 J39 = 61301021121: Header, 2.54 mm, 5x2, Gold, TH; Manufacturer: Wurth Elektronik; SymbolCreator: a0412235; Green_Lifecycle: Active; Green_REACh: Passed
J33 = 61300311121: Header, 2.54 mm, 3x1, Gold, TH; Manufacturer: Wurth Elektronik; SymbolCreator: a0799628
J34 J40 = TSW-104-07-G-D: Header, 100mil, 4x2, Gold, TH; Manufacturer: Samtec; SymbolCreator: a0411947; Pitch_mm: 2.54; Gender: Male; Shrouded: N; Row_Count: 2; Current_A: 6.3; Voltage_V: 550; Cert_CSA: Y
J35-J38 J41-J44 = TSW-102-07-G-S: Header, 100mil, 2x1, Gold, TH; Manufacturer: Samtec; SymbolCreator: a0412235; Pitch_mm: 2.54; Gender: Male; Shrouded: N; Row_Count: 1; Current_A: 6.3; Voltage_V: 550; Cert_CSA: Y
R374-R379 R408 R410 R593-R596 R598 R600 = CRCW06030000Z0EA: RES, 0, 5%, 0.1 W, 0603; Manufacturer: Vishay-Dale; CompType: Resistor; Value: 0; Value_Code: 0000; Tolerance_%: 5; Power_W: 0.1; Value2: 0.1W; VDC_V: 75; TempCo: 200 ppm/C; SizeArea_mm2: 1.28; SizeX_mm: 1.6; SizeY_mm: 0.8; SizeZ_mm: 1; EIA_Code: E24; U/M: EA; AEC Category: Q200
R380-R385 R406 R429-R431 = CRCW060310K0JNEA: RES, 10 k, 5%, 0.1 W, 0603; Manufacturer: Vishay-Dale; CompType: Resistor; Value: 10k; Res_ohm: 10000; Value_Code: 10k0; Tolerance_%: 5; Power_W: 0.1; Value2: 0.1W; VDC_V: 75; TempCo: 200 ppm/C; SizeArea_mm2: 1.28; SizeX_mm: 1.6; SizeY_mm: 0.8; SizeZ_mm: 1; EIA_Code: E24; U/M: EA; AEC Category: Q200
R394 R396 R398 R400 R402 R404 R405 R407 R409 R411 R416 R420 R421 R423-R425 R440 R441 R445 R447 R449 R451 R452 R454 R467 R468 = RC0603FR-07100RL: RES, 100, 1%, 0.1 W, 0603; Manufacturer: Yageo America; CompType: Resistor; Value: 100; Value_Code: 100R; Tolerance_%: 1; Power_W: 0.1; Value2: 0.1W; VDC_V: 150; TempCo: 200 ppm/C; SizeArea_mm2: 1.28; SizeX_mm: 1.6; SizeY_mm: 0.8; EIA_Code: E96; U/M: EA; AEC Category: Q200
R426-R428 R597 R599 R601-R603 = CRCW060333R0JNEA: RES, 33, 5%, 0.1 W, 0603; Manufacturer: Vishay-Dale; CompType: Resistor; Value: 33; Value_Code: 33R0; Tolerance_%: 5; Power_W: 0.1; Value2: 0.1W; VDC_V: 75; TempCo: 200 ppm/C; SizeArea_mm2: 1.28; SizeX_mm: 1.6; SizeY_mm: 0.8; SizeZ_mm: 1; EIA_Code: E24; U/M: EA; AEC Category: Q200
R432-R439 R455 R456 R458 R459 R461 R462 R464 R465 = CRCW06031K00FKEA: RES, 1.00 k, 1%, 0.1 W, 0603; Manufacturer: Vishay-Dale; CompType: Resistor; Value: 1.00k; Res_ohm: 1000; Value_Code: 1k00; Tolerance_%: 1; Power_W: 0.1; Value2: 0.1W; VDC_V: 75; TempCo: 100 ppm/C; SizeArea_mm2: 1.28; SizeX_mm: 1.6; SizeY_mm: 0.8; EIA_Code: E96; U/M: EA; AEC Category: Q200
U26 U27 U29-U33 = SN74AVC4T774PWR: 4-Bit Dual-Supply Bus Transceiver With Configurable Voltage-Level Shifting and 3-State Outputs, PW0016A (TSSOP-16); Manufacturer: Texas Instruments; SymbolCreator: a0411947; SizeArea_mm2: 32; SizeAreaWB_mm2: 58.8; SizeX_mm: 6.4; SizeY_mm: 5; SizeZ_mm: 1.2; CompType: IC; U/M: EA
U28 = SN74LVC1G125DBVR: Single Bus Buffer Gate With 3-State Outputs, DBV0005A (SOT-5); Alternate PartNumber: SN74LVC1G125DBVT; Manufacturer: Texas Instruments; SymbolCreator: Altium; SizeArea_mm2: 8.12; SizeAreaWB_mm2: 14.82; SizeX_mm: 2.8; SizeY_mm: 2.9; SizeZ_mm: 1.45; CompType: IC; U/M: EA
U75 = SN74LVC2G53DCU: IC, SPDT Analog Switch; Manufacturer: TI; Alternate Manufacturer: None; Area: 36735

## Sheet TIDA-01022-E3_USB.SchDoc: USB
size 431 x 279 mm; Date: Not shown in title block; ApprovedBy: Not shown in title block; CheckedBy: Not shown in title block; Author: Not shown in title block; CompanyName: Not shown in title block; DrawnBy: Avinash N; Engineer: Not shown in title block; Organization: Not shown in title block; Address1: Not shown in title block; Address2: Not shown in title block; Address3: Not shown in title block; Address4: Not shown in title block; DocumentNumber: 1; Revision: Use project parameter SCH_Rev; SheetNumber: 16; SheetTotal: 26; PageSetup: Record=PageOptions¦CenterHorizontal=True¦CenterVertical=True¦PrintScale=1.00¦XCorrection=1.00¦YCorrection=1.00¦PrintKind=0¦BorderSize=5000000¦LeftOffset=0¦BottomOffset=0¦Orientation=2¦PaperLength=1000¦PaperWidth=1000¦Scale=100¦PaperSource=15¦PrintQuality=600¦MediaType=1¦DitherType=10¦PaperKind=Letter¦PrintScaleMode=1

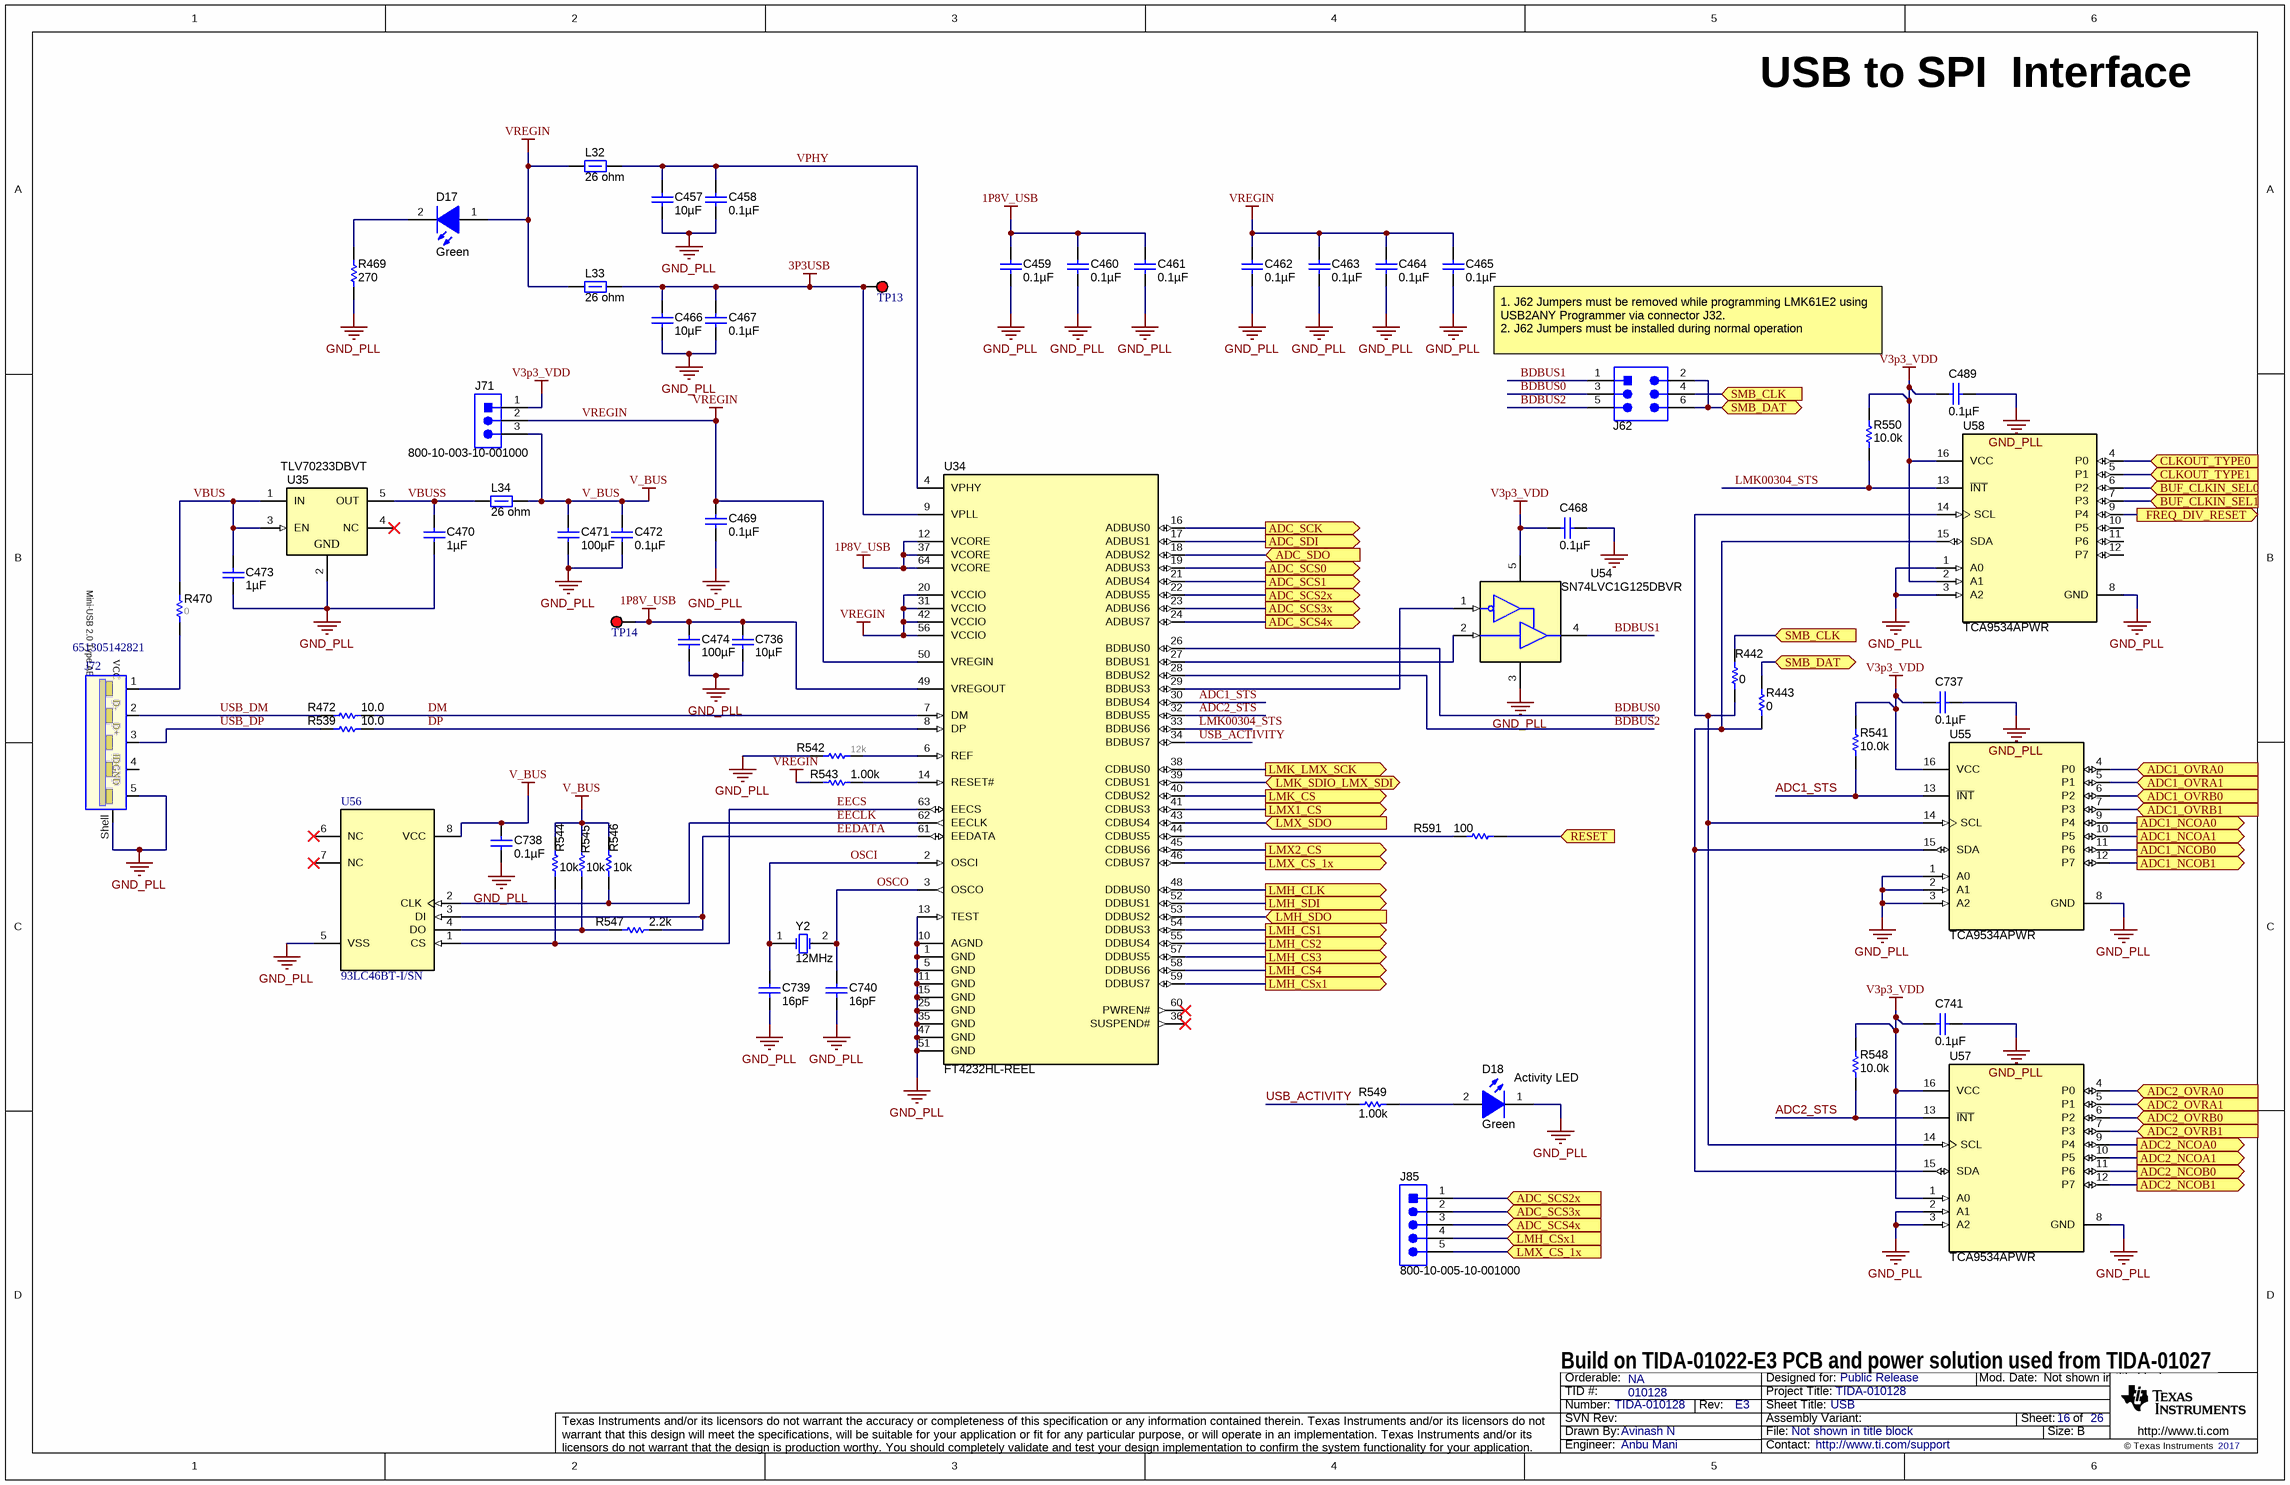
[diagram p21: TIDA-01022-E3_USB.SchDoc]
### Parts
C457  ValueDisplayed: 10µF  [0603]  (hidden comment: GRM188R61A106ME69D)
C458  ValueDisplayed: 0.1µF  [0603]  (hidden comment: C0603C104J3RACTU)
C459  ValueDisplayed: 0.1µF  [0603]  (hidden comment: C0603C104J3RACTU)
C460  ValueDisplayed: 0.1µF  [0603]  (hidden comment: C0603C104J3RACTU)
C461  ValueDisplayed: 0.1µF  [0603]  (hidden comment: C0603C104J3RACTU)
C462  ValueDisplayed: 0.1µF  [0603]  (hidden comment: C0603C104J3RACTU)
C463  ValueDisplayed: 0.1µF  [0603]  (hidden comment: C0603C104J3RACTU)
C464  ValueDisplayed: 0.1µF  [0603]  (hidden comment: C0603C104J3RACTU)
C465  ValueDisplayed: 0.1µF  [0603]  (hidden comment: C0603C104J3RACTU)
C466  ValueDisplayed: 10µF  [0603]  (hidden comment: GRM188R61A106ME69D)
C467  ValueDisplayed: 0.1µF  [0603]  (hidden comment: C0603C104J3RACTU)
C468  ValueDisplayed: 0.1µF  [0603]  (hidden comment: C0603C104J3RACTU)
C469  ValueDisplayed: 0.1µF  [0603]  (hidden comment: C0603C104J3RACTU)
C470  ValueDisplayed: 1µF  [0603]  (hidden comment: C1608X7R1C105K080AC)
C471  ValueDisplayed: 100µF  [1210_270]  (hidden comment: GRM32ER61A107ME20L)
C472  ValueDisplayed: 0.1µF  [0603]  (hidden comment: C0603C104J3RACTU)
C473  ValueDisplayed: 1µF  [0603]  (hidden comment: C1608X7R1C105K080AC)
C474  ValueDisplayed: 100µF  [1210_270]  (hidden comment: GRM32ER61A107ME20L)
C489  ValueDisplayed: 0.1µF  [0603]  (hidden comment: C0603C104J3RACTU)
C736  ValueDisplayed: 10µF  [0603]  (hidden comment: GRM188R61A106ME69D)
C737  ValueDisplayed: 0.1µF  [0603]  (hidden comment: C0603C104J3RACTU)
C738  ValueDisplayed: 0.1µF  [0603]  (hidden comment: C0603C104J3RACTU)
C739  ValueDisplayed: 16pF  [0603]  (hidden comment: GRM1885C2A160JA01D)
C740  ValueDisplayed: 16pF  [0603]  (hidden comment: GRM1885C2A160JA01D)
C741  ValueDisplayed: 0.1µF  [0603]  (hidden comment: C0603C104J3RACTU)
D17  value Green  [LTST-C191_Green]  (hidden comment: LTST-C191TGKT)
D18  value Green  [WL-SMCW_Green_0805]  (hidden comment: 150080GS75000)
J62  802-10-006-10-001000  [Mill-Max_802-10-006-10-001000]  (value not drawn)
J71  800-10-003-10-001000  [Mill-Max_800-10-003-10-001000]
J72  651305142821  [651305142821]
J85  800-10-005-10-001000  [Mill-Max_800-10-005-10-001000]
L32  ValueDisplayed: 26 ohm  [0603]  (hidden comment: BLM18SG260TN1D)
L33  ValueDisplayed: 26 ohm  [0603]  (hidden comment: BLM18SG260TN1D)
L34  ValueDisplayed: 26 ohm  [0603]  (hidden comment: BLM18SG260TN1D)
R442  ValueDisplayed: 0  [0603]  (hidden comment: CRCW06030000Z0EA)
R443  ValueDisplayed: 0  [0603]  (hidden comment: CRCW06030000Z0EA)
R469  ValueDisplayed: 270  [0603]  (hidden comment: CRCW0603270RJNEA)
R470  value 0  [0603]  (hidden comment: CRCW06030000Z0EA)
R472  ValueDisplayed: 10.0  [0603]  (hidden comment: CRCW060310R0FKEAHP)
R539  ValueDisplayed: 10.0  [0603]  (hidden comment: CRCW060310R0FKEAHP)
R541  ValueDisplayed: 10.0k  [1206]  (hidden comment: RC1206FR-0710KL)
R542  value 12k  [0603]  (hidden comment: CRCW060312K0JNEA)
R543  ValueDisplayed: 1.00k  [0603]  (hidden comment: CRCW06031K00FKEA)
R544  ValueDisplayed: 10k  [0603]  (hidden comment: CRCW060310K0JNEA)
R545  ValueDisplayed: 10k  [0603]  (hidden comment: CRCW060310K0JNEA)
R546  ValueDisplayed: 10k  [0603]  (hidden comment: CRCW060310K0JNEA)
R547  ValueDisplayed: 2.2k  [0603]  (hidden comment: CRCW06032K20JNEA)
R548  ValueDisplayed: 10.0k  [1206]  (hidden comment: RC1206FR-0710KL)
R549  ValueDisplayed: 1.00k  [0603]  (hidden comment: CRCW06031K00FKEA)
R550  ValueDisplayed: 10.0k  [1206]  (hidden comment: RC1206FR-0710KL)
R591  ValueDisplayed: 100  [0603]  (hidden comment: RC0603FR-07100RL)
TP13  5000  [Keystone5000]  (value not drawn)
TP14  5000  [Keystone5000]  (value not drawn)
U34  FT4232HL-REEL  [LQFP64_N]
U35  TLV70233DBVT  [DBV0005A_N]
U54  SN74LVC1G125DBVR  [DBV0005A_N]
U55  TCA9534APWR  [PW0016A_N]
U56  93LC46BT-I/SN  [SOIC-8]
U57  TCA9534APWR  [PW0016A_N]
U58  TCA9534APWR  [PW0016A_N]
Y2  Frequency: 12MHz  [XTAL_ABM3]  (hidden comment: ABM3-12.000MHZ-D2Y-T)

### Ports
ADC1_NCOA0 (out), ADC1_NCOA1 (out), ADC1_NCOB0 (out), ADC1_NCOB1 (out), ADC1_OVRA0 (in), ADC1_OVRA1 (in), ADC1_OVRB0 (in), ADC1_OVRB1 (in), ADC2_NCOA0 (out), ADC2_NCOA1 (out), ADC2_NCOB0 (out), ADC2_NCOB1 (out), ADC2_OVRA0 (in), ADC2_OVRA1 (in), ADC2_OVRB0 (in), ADC2_OVRB1 (in), ADC_SCK (out), ADC_SCS0 (out), ADC_SCS1 (out), ADC_SCS2x (in), ADC_SCS2x (out), ADC_SCS3x (in), ADC_SCS3x (out), ADC_SCS4x (in), ADC_SCS4x (out), ADC_SDI (out), ADC_SDO (in), BUF_CLKIN_SEL0 (in), BUF_CLKIN_SEL1 (in), CLKOUT_TYPE0 (in), CLKOUT_TYPE1 (in), FREQ_DIV_RESET (out), LMH_CLK (out), LMH_CS1 (out), LMH_CS2 (out), LMH_CS3 (out), LMH_CS4 (out), LMH_CSx1 (in), LMH_CSx1 (out), LMH_SDI (out), LMH_SDO (in), LMK_CS (out), LMK_LMX_SCK (out), LMK_SDIO_LMX_SDI (bidir), LMX1_CS (out), LMX2_CS (out), LMX_CS_1x (in), LMX_CS_1x (out), LMX_SDO (in), RESET (in), SMB_CLK (in), SMB_DAT (bidir)

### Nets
1P8V_USB: C459.2 C460.2 C461.2 C474.1 C736.1 TP14.1 U34.12(VCORE) U34.37(VCORE) U34.49(VREGOUT) U34.64(VCORE)
3P3USB: C466.1 C467.2 L33.2 TP13.1 U34.9(VPLL)
GND_PLL: C457.2 C458.1 C459.1 C460.1 C461.1 C462.1 C463.1 C464.1 C465.1 C466.2 C467.1 C468.1 C469.1 C470.2 C471.2 C472.1 C473.2 C474.2 C489.1 C736.2 C737.1 C738.1 C739.2 C740.2 C741.1 D18.1(K) J72.5(GND) J72.Shell R469.1 R542.2 U34.1(GND) U34.5(GND) U34.10(AGND) U34.11(GND) U34.13(TEST) U34.15(GND) U34.25(GND) U34.35(GND) U34.47(GND) U34.51(GND) U35.2(GND) U54.3(GND) U55.1(A0) U55.2(A1) U55.3(A2) U55.8(GND) U56.5(VSS) U57.2(A1) U57.3(A2) U57.8(GND) U58.1(A0) U58.3(A2) U58.8(GND)  [project net DGND]
V3p3_VDD: C468.2 C489.2 C737.2 C741.2 J71.1 R541.2 R548.2 R550.2 U54.5(VCC) U55.16(VCC) U57.1(A0) U57.16(VCC) U58.2(A1) U58.16(VCC)
V_BUS: C471.1 C472.2 C738.2 J71.3 L34.2 R544.2 R545.2 R546.2 U56.8(VCC)
VREGIN: C462.2 C463.2 C464.2 C465.2 C469.2 D17.1(A) J71.2 L32.1 L33.1 R543.1 U34.20(VCCIO) U34.31(VCCIO) U34.42(VCCIO) U34.50(VREGIN) U34.56(VCCIO)
ADC1_NCOA0: U55.9(P4) ; port ADC1_NCOA0
ADC1_NCOA1: U55.10(P5) ; port ADC1_NCOA1
ADC1_NCOB0: U55.11(P6) ; port ADC1_NCOB0
ADC1_NCOB1: U55.12(P7) ; port ADC1_NCOB1
ADC1_OVRA0: U55.4(P0) ; port ADC1_OVRA0
ADC1_OVRA1: U55.5(P1) ; port ADC1_OVRA1
ADC1_OVRB0: U55.6(P2) ; port ADC1_OVRB0
ADC1_OVRB1: U55.7(P3) ; port ADC1_OVRB1
ADC1_STS: R541.1 U34.30(BDBUS4) U55.13(~{INT})
ADC2_NCOA0: U57.9(P4) ; port ADC2_NCOA0
ADC2_NCOA1: U57.10(P5) ; port ADC2_NCOA1
ADC2_NCOB0: U57.11(P6) ; port ADC2_NCOB0
ADC2_NCOB1: U57.12(P7) ; port ADC2_NCOB1
ADC2_OVRA0: U57.4(P0) ; port ADC2_OVRA0
ADC2_OVRA1: U57.5(P1) ; port ADC2_OVRA1
ADC2_OVRB0: U57.6(P2) ; port ADC2_OVRB0
ADC2_OVRB1: U57.7(P3) ; port ADC2_OVRB1
ADC2_STS: R548.1 U34.32(BDBUS5) U57.13(~{INT})
ADC_SCK: U34.16(ADBUS0) ; port ADC_SCK
ADC_SCS0: U34.19(ADBUS3) ; port ADC_SCS0
ADC_SCS1: U34.21(ADBUS4) ; port ADC_SCS1
ADC_SCS2x: J85.1 U34.22(ADBUS5) ; port ADC_SCS2x
ADC_SCS3x: J85.2 U34.23(ADBUS6) ; port ADC_SCS3x
ADC_SCS4x: J85.3 U34.24(ADBUS7) ; port ADC_SCS4x
ADC_SDI: U34.17(ADBUS1) ; port ADC_SDI
ADC_SDO: U34.18(ADBUS2) ; port ADC_SDO
BDBUS0: J62.3 U34.26(BDBUS0)
BDBUS1: J62.1 U54.4(Y)
BDBUS2: J62.5 U34.28(BDBUS2)
BUF_CLKIN_SEL0: U58.6(P2) ; port BUF_CLKIN_SEL0
BUF_CLKIN_SEL1: U58.7(P3) ; port BUF_CLKIN_SEL1
CLKOUT_TYPE0: U58.4(P0) ; port CLKOUT_TYPE0
CLKOUT_TYPE1: U58.5(P1) ; port CLKOUT_TYPE1
DM: R472.2 U34.7(DM)
DP: R539.2 U34.8(DP)
EECLK: R546.1 U34.62(EECLK) U56.2(CLK)
EECS: R544.1 U34.63(EECS) U56.1(CS)
EEDATA: R547.2 U34.61(EEDATA) U56.3(DI)
FREQ_DIV_RESET: U58.9(P4) ; port FREQ_DIV_RESET
LMH_CLK: U34.48(DDBUS0) ; port LMH_CLK
LMH_CS1: U34.54(DDBUS3) ; port LMH_CS1
LMH_CS2: U34.55(DDBUS4) ; port LMH_CS2
LMH_CS3: U34.57(DDBUS5) ; port LMH_CS3
LMH_CS4: U34.58(DDBUS6) ; port LMH_CS4
LMH_CSx1: J85.4 U34.59(DDBUS7) ; port LMH_CSx1
LMH_SDI: U34.52(DDBUS1) ; port LMH_SDI
LMH_SDO: U34.53(DDBUS2) ; port LMH_SDO
LMK00304_STS: R550.1 U34.33(BDBUS6) U58.13(~{INT})
LMK_CS: U34.40(CDBUS2) ; port LMK_CS
LMK_LMX_SCK: U34.38(CDBUS0) ; port LMK_LMX_SCK
LMK_SDIO_LMX_SDI: U34.39(CDBUS1) ; port LMK_SDIO_LMX_SDI
LMX1_CS: U34.41(CDBUS3) ; port LMX1_CS
LMX2_CS: U34.45(CDBUS6) ; port LMX2_CS
LMX_CS_1x: J85.5 U34.46(CDBUS7) ; port LMX_CS_1x
LMX_SDO: U34.43(CDBUS4) ; port LMX_SDO
OSCI: C739.1 U34.2(OSCI) Y2.1(OSC1)
OSCO: C740.1 U34.3(OSCO) Y2.2(OSC2)
RESET: R591.2 ; port RESET
SMB_CLK: J62.4 R442.2 ; port SMB_CLK
SMB_DAT: J62.2 J62.6 R443.2 ; port SMB_DAT
USB_ACTIVITY: R549.1 U34.34(BDBUS7)
USB_DM: J72.2(D-) R472.1
USB_DP: J72.3(D+) R539.1
VBUS: C473.1 R470.2 U35.1(IN) U35.3(EN)
VBUSS: C470.1 L34.1 U35.5(OUT)
VPHY: C457.1 C458.2 L32.2 U34.4(VPHY)
NetD17_2: D17.2(K) R469.2
NetD18_2: D18.2(A) R549.2
NetJ72_1: J72.1(VCC) R470.1
NetR442_1: R442.1 U55.14(SCL) U57.14(SCL) U58.14(SCL)
NetR443_1: R443.1 U55.15(SDA) U57.15(SDA) U58.15(SDA)
NetR542_1: R542.1 U34.6(REF)
NetR543_2: R543.2 U34.14(RESET#)
NetR545_1: R545.1 R547.1 U56.4(DO)
NetR591_1: R591.1 U34.44(CDBUS5)
NetU34_27: U34.27(BDBUS1) U54.2(A)
NetU34_29: U34.29(BDBUS3) U54.1(~{OE})

Not connected (* = marked no-connect by the designer): J72 4(ID); U34 36(SUSPEND#)* 60(PWREN#)*; U35 4(NC)*; U56 6(NC)* 7(NC)*; U58 10(P5) 11(P6) 12(P7)

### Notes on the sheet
- USB to SPI  Interface
- 1. J62 Jumpers must be removed while programming LMK61E2 using      USB2ANY Programmer via connector J32.
  2. J62 Jumpers must be installed during normal operation
- (near D18) Activity LED
- Build on TIDA-01022-E3 PCB and power solution used from TIDA-01027

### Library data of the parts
C457 C466 C736 = GRM188R61A106ME69D: CAP, CERM, 10 µF, 10 V, +/- 20%, X5R, 0603; Manufacturer: MuRata; Polarized: N; CompType: Capacitor; Value: 10uF; U/M: EA; Cap_F: 0.00001; Tolerance_%: 20; Value1: Unknown; VDC_V: 10; Value2: 10V; TaMin_C: -55; TaMax_C: 85; SizeArea_mm2: 1.28; SizeAreaWB_mm2: 4.68; SizeX_mm: 1.6; SizeY_mm: 0.8; SizeZ_mm: 1; AEC Category: Q200
C458-C465 C467-C469 C472 C489 C737 C738 C741 = C0603C104J3RACTU: as C148 on sheet TIDA-01022-E3_Programming for ADC_LMK _LMX
C470 C473 = C1608X7R1C105K080AC: CAP, CERM, 1 µF, 16 V, +/- 10%, X7R, 0603; Manufacturer: TDK; Polarized: N; CompType: Capacitor; Value: 1uF; U/M: EA; Cap_F: 0.000001; Tolerance_%: 10; ESR_ohm: 0.0057; Value1: 0.0057 ohm; VDC_V: 16; Value2: 16V; TaMin_C: -55; TaMax_C: 125; SizeArea_mm2: 1.28; SizeAreaWB_mm2: 4.68; SizeX_mm: 1.6; SizeY_mm: 0.8; SizeZ_mm: 1; AEC Category: Q200
C471 C474 = GRM32ER61A107ME20L: CAP, CERM, 100 µF, 10 V, +/- 20%, X5R, 1210; Manufacturer: MuRata; Polarized: N; CompType: Capacitor; Value: 100uF; U/M: EA; Cap_F: 0.0001; Tolerance_%: 20; Value1: Unknown; VDC_V: 10; Value2: 10V; TaMin_C: -55; TaMax_C: 85; Cap_Case: 1210; SizeArea_mm2: 8; SizeAreaWB_mm2: 14.7; SizeX_mm: 3.2; SizeY_mm: 2.5; SizeZ_mm: 2.7; AEC Category: Q200
C739 C740 = GRM1885C2A160JA01D: CAP, CERM, 16 pF, 100 V, +/- 5%, C0G/NP0, 0603; Manufacturer: MuRata; Polarized: N; CompType: Capacitor; Value: 16pF; U/M: EA; Cap_F: 0.000000000016; Tolerance_%: 5; Value1: Unknown; VDC_V: 100; Value2: 100V; TaMin_C: -55; TaMax_C: 125; SizeArea_mm2: 1.28; SizeAreaWB_mm2: 4.68; SizeX_mm: 1.6; SizeY_mm: 0.8; SizeZ_mm: 1; AEC Category: Q200
D17 = LTST-C191TGKT: LED, Green, SMD; Manufacturer: Lite-On; Type: InGaN; Vf_V: 3.2; Value2: 3.2V; Io_A: 0.02; Value1: W; U/M: EA
D18 = 150080GS75000: LED, Green, SMD; Manufacturer: Wurth Elektronik; Type: InGaN; Vf_V: 3.2; Value2: 3.2V; Io_A: 0.02; Vr_V: 5; Ir_A: 1e-005; Tjmax_C: 85; Power_TotalModule: 0.105; Value1: 0.105W; Angle: 140; U/M: EA
J62 = 802-10-006-10-001000: Header, 2.54 mm, 3x2, Gold, TH; Manufacturer: Mill-Max; SymbolCreator: a0412235; Pitch_mm: 2.54; Gender: Male; Shrouded: N; Row_Count: 2
J71 = 800-10-003-10-001000: Header, 100mil, 3x1, TH; Manufacturer: Mill-Max; SymbolCreator: a0799628
J72 = 651305142821: WR-COM Mini USB 2.0 Type AB SMT Horizontal 5 Contacts
J85 = 800-10-005-10-001000: Header, 100mil, 5x1, TH; Manufacturer: Mill-Max; SymbolCreator: a0412235
L32-L34 = BLM18SG260TN1D: Ferrite Bead, 26 ohm @ 100 MHz, 6 A, 0603; Manufacturer: MuRata; Value: 26 ohm; Imax_A: 6; DCR_ohm: 0.007; Value1: 0.007 ohm; Value2: 6A; SizeAreaWB_mm2: 4.68; SizeArea_mm2: 1.28; SizeX_mm: 1.6; SizeY_mm: 0.8; SizeZ_mm: 1; ZTyp@100MHz_Ohm: 26
R442 R443 = CRCW06030000Z0EA: as R374 on sheet TIDA-01022-E3_Programming for ADC_LMK _LMX
R469 = CRCW0603270RJNEA: RES, 270, 5%, 0.1 W, 0603; Manufacturer: Vishay-Dale; CompType: Resistor; Value: 270; Value_Code: 270R; Tolerance_%: 5; Power_W: 0.1; Value2: 0.1W; VDC_V: 75; TempCo: 200 ppm/C; SizeArea_mm2: 1.28; SizeX_mm: 1.6; SizeY_mm: 0.8; SizeZ_mm: 1; EIA_Code: E24; U/M: EA; AEC Category: Q200
R470 = CRCW06030000Z0EA: RES, 0 ohm, 5%, 0.1W, 0603; Manufacturer: Vishay-Dale; CompType: Resistor; Tolerance_%: 5; VDC_V: 75; Power_W: 0.1; U/M: EA; Value_Code: 0000; EIA_Code: E24
R472 R539 = CRCW060310R0FKEAHP: RES, 10.0, 1%, 0.25 W, 0603; Manufacturer: Vishay-Dale; CompType: Resistor; Value: 10.0; Res_ohm: 10; Value_Code: 10R0; Tolerance_%: 1; Power_W: 0.25; Value2: 0.25W; VDC_V: 75; TempCo: 100 ppm/C; SizeArea_mm2: 1.28; SizeX_mm: 1.6; SizeY_mm: 0.8; EIA_Code: E96; U/M: EA; AEC Category: Q200
R541 R548 R550 = RC1206FR-0710KL: RES, 10.0 k, 1%, 0.25 W, 1206; Manufacturer: Yageo America; CompType: Resistor; Value: 10.0k; Res_ohm: 10000; Value_Code: 10k0; Tolerance_%: 1; Power_W: 0.25; Value2: 0.25W; VDC_V: 200; TempCo: 100 ppm/C; SizeArea_mm2: 5.12; SizeX_mm: 3.2; SizeY_mm: 1.6; SizeZ_mm: 1.35; EIA_Code: E96; U/M: EA; AEC Category: Q200
R542 = CRCW060312K0JNEA: RES, 12k ohm, 5%, 0.1W, 0603; Manufacturer: Vishay-Dale; CompType: Resistor; Tolerance_%: 5; VDC_V: 75; Power_W: 0.1; Res_ohm: 12000; U/M: EA; Value_Code: 12k0; EIA_Code: E24
R543 R549 = CRCW06031K00FKEA: as R432 on sheet TIDA-01022-E3_Programming for ADC_LMK _LMX
R544-R546 = CRCW060310K0JNEA: as R380 on sheet TIDA-01022-E3_Programming for ADC_LMK _LMX
R547 = CRCW06032K20JNEA: RES, 2.2 k, 5%, 0.1 W, 0603; Manufacturer: Vishay-Dale; CompType: Resistor; Value: 2.2k; Res_ohm: 2200; Value_Code: 2k20; Tolerance_%: 5; Power_W: 0.1; Value2: 0.1W; VDC_V: 75; TempCo: 200 ppm/C; SizeArea_mm2: 1.28; SizeX_mm: 1.6; SizeY_mm: 0.8; SizeZ_mm: 1; EIA_Code: E24; U/M: EA; AEC Category: Q200
R591 = RC0603FR-07100RL: as R394 on sheet TIDA-01022-E3_Programming for ADC_LMK _LMX
TP13 TP14 = 5000: Test Point, Miniature, Red, TH; Manufacturer: Keystone; CompType: Test Point Loop; ContactFinish: Silver
U34 = FT4232HL: Quad High Speed USB to Multipurpose UART/MPSSE IC; Manufacturer: FTDI; SymbolCreator: a0411947
U35 = TLV70233DBVT: Single Output LDO, 300 mA, Fixed 3.3 V Output, 2 to 5.5 V Input, with Low IQ, 5-pin SOT-23 (DBV), -40 to 125 degC, Green (RoHS & no Sb/Br); Manufacturer: Texas Instruments; Alternate PartNumber: Equivalent; Accuracy(%): 2; Fixed Output Options(V): 3.3; Iout(Max)(A): 0.3; Iq(Typ)(mA): 0.03; SubFamily: Single Channel LDO; Vdo(Typ)(mV): 220; Vin(Max)(V): 5.5
U54 = SN74LVC1G125DBVR: as U28 on sheet TIDA-01022-E3_Programming for ADC_LMK _LMX
U55 U57 U58 = TCA9534APWR: Remote 8-Bit I2C and Low-Power I/O Expander With Interrupt Output and Configuration Registers, PW0016A (TSSOP-16); Manufacturer: Texas Instruments; SymbolCreator: Altium; SizeArea_mm2: 32; SizeAreaWB_mm2: 58.8; SizeX_mm: 6.4; SizeY_mm: 5; SizeZ_mm: 1.2; CompType: IC; U/M: EA
U56 = 93LC46BT-I/SN: 1K Microwire Compatible Serial EEPROM; Manufacturer: Microchip; SymbolCreator: Altium; SizeAreaWB_mm2: 55.131; SizeArea_mm2: 29.351; SizeX_mm: 5.99; SizeY_mm: 4.9; SizeZ_mm: 1.75
Y2 = ABM3-12.000MHZ-D2Y-T: Crystal, 12 MHz, 18 pF, SMD; Manufacturer: Abracon Corporation; SymbolCreator: a0412235; U/M: EA; TaMin_C: -40; TaMax_C: 85; Frequency Stability: ±30ppm

## Sheet TIDA-01022-E3_FMC+CONN1_1.SchDoc: FMC+CONN1
size 431 x 279 mm; Date: Not shown in title block; ApprovedBy: Not shown in title block; CheckedBy: Not shown in title block; Author: Not shown in title block; CompanyName: Not shown in title block; DrawnBy: Avinash N; Engineer: Not shown in title block; Organization: Not shown in title block; Address1: Not shown in title block; Address2: Not shown in title block; Address3: Not shown in title block; Address4: Not shown in title block; DocumentNumber: 1; Revision: Use project parameter SCH_Rev; SheetNumber: 17; SheetTotal: 26; PageSetup: Record=PageOptions¦CenterHorizontal=True¦CenterVertical=True¦PrintScale=1.00¦XCorrection=1.00¦YCorrection=1.00¦PrintKind=0¦BorderSize=5000000¦LeftOffset=0¦BottomOffset=0¦Orientation=2¦PaperLength=1000¦PaperWidth=1000¦Scale=100¦PaperSource=15¦PrintQuality=600¦MediaType=1¦DitherType=10¦PaperKind=Letter¦PrintScaleMode=1

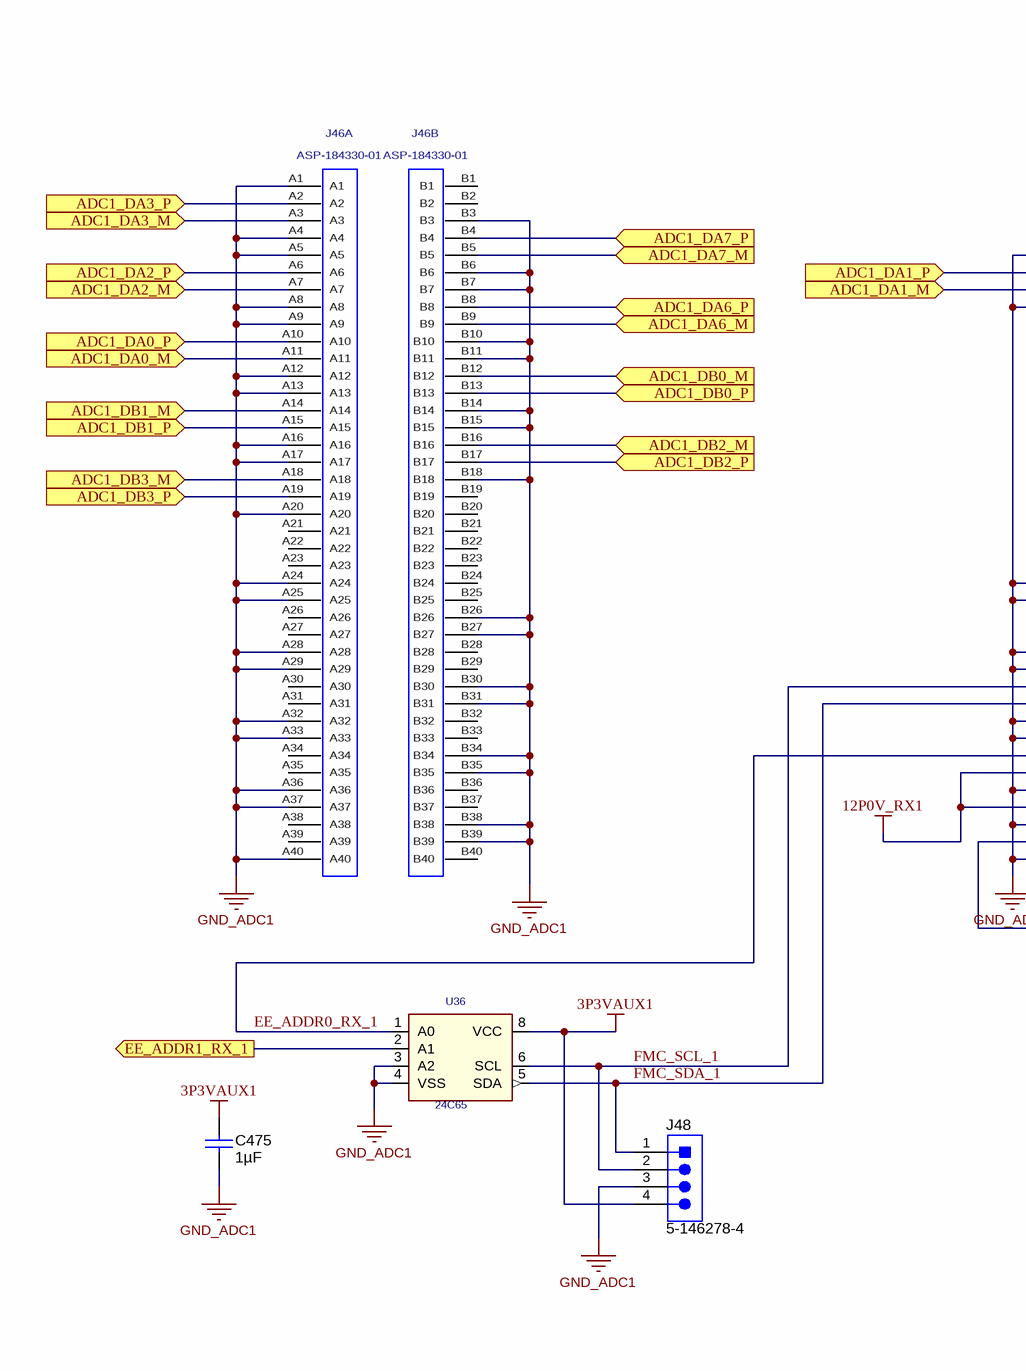
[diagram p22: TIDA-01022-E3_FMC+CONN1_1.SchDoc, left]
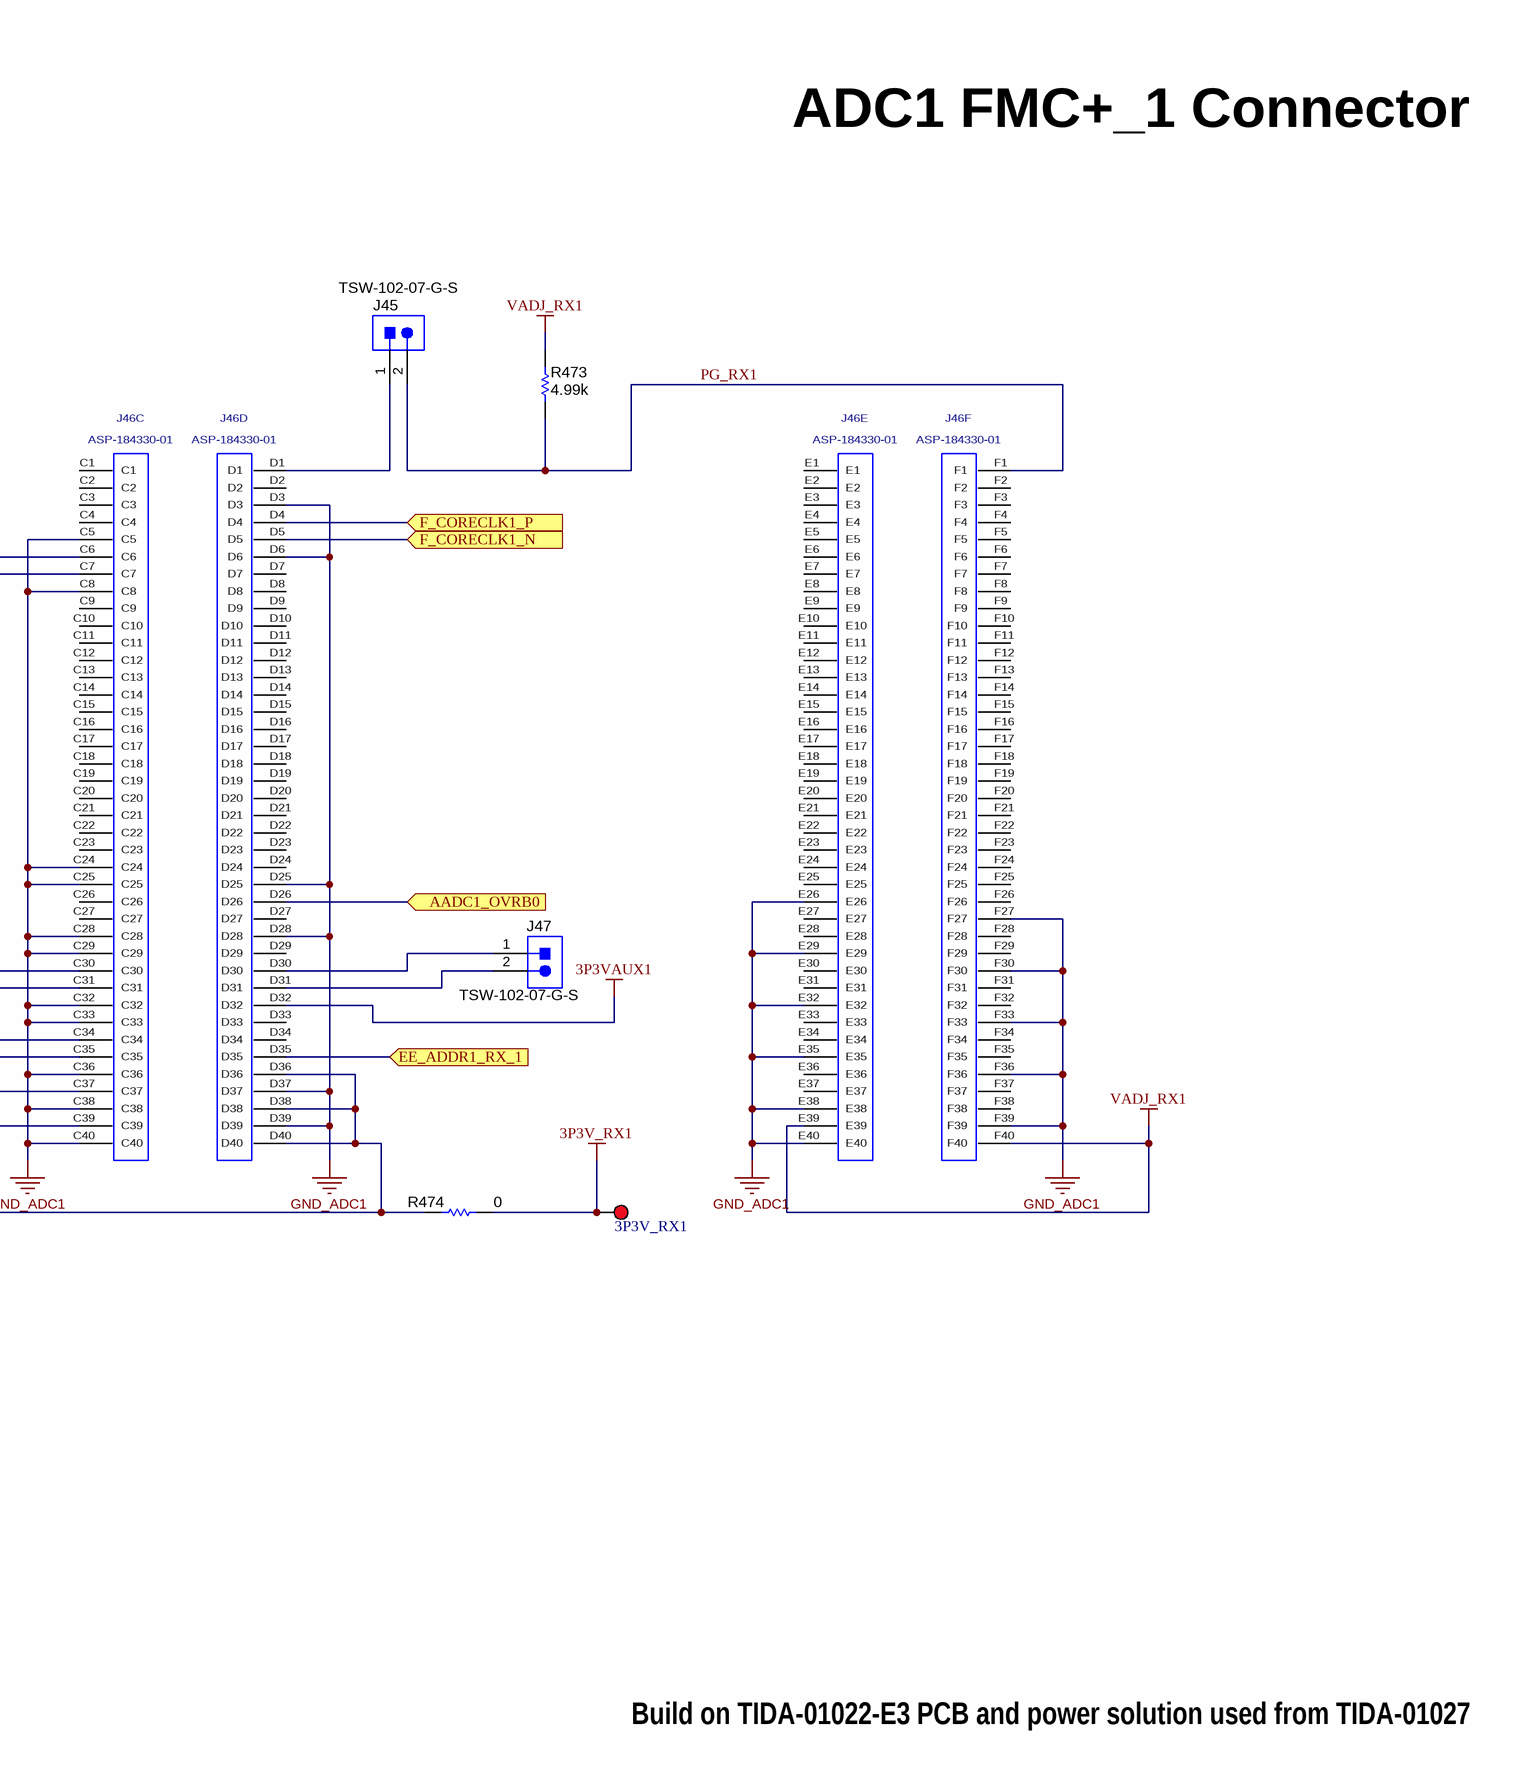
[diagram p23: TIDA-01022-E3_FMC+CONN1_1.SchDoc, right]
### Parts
3P3V_RX1  5000  [Keystone5000]  (value not drawn)
C475  ValueDisplayed: 1µF  [0603]  (hidden comment: C1608X5R1A105K080AC)
J45  TSW-102-07-G-S  [TSW-102-07-G-S]
J46  ASP-184330-01  [ASP-184330-01]  (parts A,B,C,D,E,F of 14)
J47  TSW-102-07-G-S  [TSW-102-07-G-S]
J48  5-146278-4  [TE_5-146278-4]
R473  ValueDisplayed: 4.99k  [0402]  (hidden comment: CRCW04024K99FKED)
R474  ValueDisplayed: 0  [0402]  (hidden comment: CRCW04020000Z0ED)
U36  24C65  [SOIC127P800X216-8N]

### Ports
AADC1_OVRB0 (in), ADC1_DA0_M (in), ADC1_DA0_P (in), ADC1_DA1_M (in), ADC1_DA1_P (in), ADC1_DA2_M (in), ADC1_DA2_P (in), ADC1_DA3_M (in), ADC1_DA3_P (in), ADC1_DA6_M (in), ADC1_DA6_P (in), ADC1_DA7_M (in), ADC1_DA7_P (in), ADC1_DB0_M (in), ADC1_DB0_P (in), ADC1_DB1_M (in), ADC1_DB1_P (in), ADC1_DB2_M (in), ADC1_DB2_P (in), ADC1_DB3_M (in), ADC1_DB3_P (in), EE_ADDR1_RX_1 (in), EE_ADDR1_RX_1 (out), F_CORECLK1_N (in), F_CORECLK1_P (in)

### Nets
3P3V_RX1: 3P3V_RX1.1 R474.1
3P3VAUX1: C475.1 J46.D32 J48.4 U36.8(VCC)
12P0V_RX1: J46.C35 J46.C37
GND_ADC1: C475.2 J46.A1 J46.A4 J46.A5 J46.A8 J46.A9 J46.A12 J46.A13 J46.A16 J46.A17 J46.A20 J46.A24 J46.A25 J46.A28 J46.A29 J46.A32 J46.A33 J46.A36 J46.A37 J46.A40 J46.B3 J46.B6 J46.B7 J46.B10 J46.B11 J46.B14 J46.B15 J46.B18 J46.B26 J46.B27 J46.B30 J46.B31 J46.B34 J46.B35 J46.B38 J46.B39 J46.C5 J46.C8 J46.C24 J46.C25 J46.C28 J46.C29 J46.C32 J46.C33 J46.C36 J46.C38 J46.C40 J46.D3 J46.D6 J46.D25 J46.D28 J46.D37 J46.D39 J46.E26 J46.E29 J46.E32 J46.E35 J46.E38 J46.E40 J46.F27 J46.F30 J46.F33 J46.F36 J46.F39 J48.3 U36.3(A2) U36.4(VSS)  [project net DGND]
VADJ_RX1: J46.E39 J46.F40 R473.2
AADC1_OVRB0: J46.D26 ; port AADC1_OVRB0
ADC1_DA0_M: J46.A11 ; port ADC1_DA0_M
ADC1_DA0_P: J46.A10 ; port ADC1_DA0_P
ADC1_DA1_M: J46.C7 ; port ADC1_DA1_M
ADC1_DA1_P: J46.C6 ; port ADC1_DA1_P
ADC1_DA2_M: J46.A7 ; port ADC1_DA2_M
ADC1_DA2_P: J46.A6 ; port ADC1_DA2_P
ADC1_DA3_M: J46.A3 ; port ADC1_DA3_M
ADC1_DA3_P: J46.A2 ; port ADC1_DA3_P
ADC1_DA6_M: J46.B9 ; port ADC1_DA6_M
ADC1_DA6_P: J46.B8 ; port ADC1_DA6_P
ADC1_DA7_M: J46.B5 ; port ADC1_DA7_M
ADC1_DA7_P: J46.B4 ; port ADC1_DA7_P
ADC1_DB0_M: J46.B12 ; port ADC1_DB0_M
ADC1_DB0_P: J46.B13 ; port ADC1_DB0_P
ADC1_DB1_M: J46.A14 ; port ADC1_DB1_M
ADC1_DB1_P: J46.A15 ; port ADC1_DB1_P
ADC1_DB2_M: J46.B16 ; port ADC1_DB2_M
ADC1_DB2_P: J46.B17 ; port ADC1_DB2_P
ADC1_DB3_M: J46.A18 ; port ADC1_DB3_M
ADC1_DB3_P: J46.A19 ; port ADC1_DB3_P
EE_ADDR0_RX_1: J46.C34 U36.1(A0)
EE_ADDR1_RX_1: J46.D35 U36.2(A1) ; port EE_ADDR1_RX_1
F_CORECLK1_N: J46.D5 ; port F_CORECLK1_N
F_CORECLK1_P: J46.D4 ; port F_CORECLK1_P
FMC_SCL_1: J46.C30 J48.2 U36.6(SCL)
FMC_SDA_1: J46.C31 J48.1 U36.5(SDA)
PG_RX1: J45.2 J46.F1 R473.1
NetJ45_1: J45.1 J46.D1
NetJ46_C39: J46.C39 J46.D36 J46.D38 J46.D40 R474.2
NetJ46_D30: J46.D30 J47.1
NetJ46_D31: J46.D31 J47.2

Not connected (* = marked no-connect by the designer): J46 A21 A22 A23 A26 A27 A30 A31 A34 A35 A38 A39 B1 B2 B19 B20 B21 B22 B23 B24 B25 B28 B29 B32 B33 B36 B37 B40 C1 C2 C3 C4 C9 C10 C11 C12 C13 C14 C15 C16 C17 C18 C19 C20 C21 C22 C23 C26 C27 D2 D7 D8 D9 D10 D11 D12 D13 D14 D15 D16 D17 D18 D19 D20 D21 D22 D23 D24 D27 D29 D33 D34 E1 E2 E3 E4 E5 E6 E7 E8 E9 E10 E11 E12 E13 E14 E15 E16 E17 E18 E19 E20 E21 E22 E23 E24 E25 E27 E28 E30 E31 E33 E34 E36 E37 F2 F3 F4 F5 F6 F7 F8 F9 F10 F11 F12 F13 F14 F15 F16 F17 F18 F19 F20 F21 F22 F23 F24 F25 F26 F28 F29 F31 F32 F34 F35 F37 F38

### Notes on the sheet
- ADC1 FMC+_1 Connector
- Build on TIDA-01022-E3 PCB and power solution used from TIDA-01027

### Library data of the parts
3P3V_RX1 = 5000: Test Point, Miniature, Red, TH; Manufacturer: Keystone; CompType: Test Point Loop; ContactFinish: Silver; Green_Lifecycle: Active; Green_REACh: Passed
C475 = C1608X5R1A105K080AC: CAP, CERM, 1 µF, 10 V, +/- 10%, X5R, 0603; Manufacturer: TDK; Polarized: N; CompType: Capacitor; Value: 1uF; U/M: EA; Cap_F: 0.000001; Tolerance_%: 10; Value1: Unknown; Value2: 10V; TaMin_C: -55; TaMax_C: 85; SizeArea_mm2: 1.28; SizeAreaWB_mm2: 4.68; SizeX_mm: 1.6; SizeY_mm: 0.8; SizeZ_mm: 1; AEC Category: Q200
J45 J47 = TSW-102-07-G-S: as J35-J38 on sheet TIDA-01022-E3_Programming for ADC_LMK _LMX
J46 = ASP-184330-01: 14 ROW .050 PITCH TERMINAL ARRAY ASM.; Manufacturer: SAMTEC
J48 = 5-146278-4: Header, 100mil, 4x1, Tin, TH; Manufacturer: TE Connectivity; SymbolCreator: a0412235
R473 = CRCW04024K99FKED: RES, 4.99 k, 1%, 0.063 W, 0402; Manufacturer: Vishay-Dale; CompType: Resistor; Value: 4.99k; Res_ohm: 4990; Value_Code: 4k99; Tolerance_%: 1; Power_W: 0.063; Value2: 0.063W; VDC_V: 50; TempCo: 100 ppm/C; SizeArea_mm2: 0.5; SizeZ_mm: 0.6; EIA_Code: E96; U/M: EA; AEC Category: Q200
R474 = CRCW04020000Z0ED: RES, 0, 5%, 0.063 W, 0402; Manufacturer: Vishay-Dale; CompType: Resistor; Value: 0; Value_Code: 0000; Tolerance_%: 5; Power_W: 0.063; Value2: 0.063W; VDC_V: 50; TempCo: 200 ppm/C; SizeArea_mm2: 0.5; SizeX_mm: 1; SizeZ_mm: 0.6; EIA_Code: E24; U/M: EA; AEC Category: Q200
U36 = 24LC65: 64K I2C Smart Serial EEPROM, SOIC-8; PartNumber: 24C65T-I/SM; Manufacturer: MICROCHIP TECHNOLOGY_DNI; NC: 7

## Sheet TIDA-01022-E3_FMC+CONN1_2.SchDoc: FMC+CONN1
size 431 x 279 mm; Date: Not shown in title block; ApprovedBy: Not shown in title block; CheckedBy: Not shown in title block; Author: Not shown in title block; CompanyName: Not shown in title block; DrawnBy: Avinash N; Engineer: Not shown in title block; Organization: Not shown in title block; Address1: Not shown in title block; Address2: Not shown in title block; Address3: Not shown in title block; Address4: Not shown in title block; DocumentNumber: 1; Revision: Use project parameter SCH_Rev; SheetNumber: 18; SheetTotal: 26; PageSetup: Record=PageOptions¦CenterHorizontal=True¦CenterVertical=True¦PrintScale=1.00¦XCorrection=1.00¦YCorrection=1.00¦PrintKind=0¦BorderSize=5000000¦LeftOffset=0¦BottomOffset=0¦Orientation=2¦PaperLength=1000¦PaperWidth=1000¦Scale=100¦PaperSource=15¦PrintQuality=600¦MediaType=1¦DitherType=10¦PaperKind=Letter¦PrintScaleMode=1

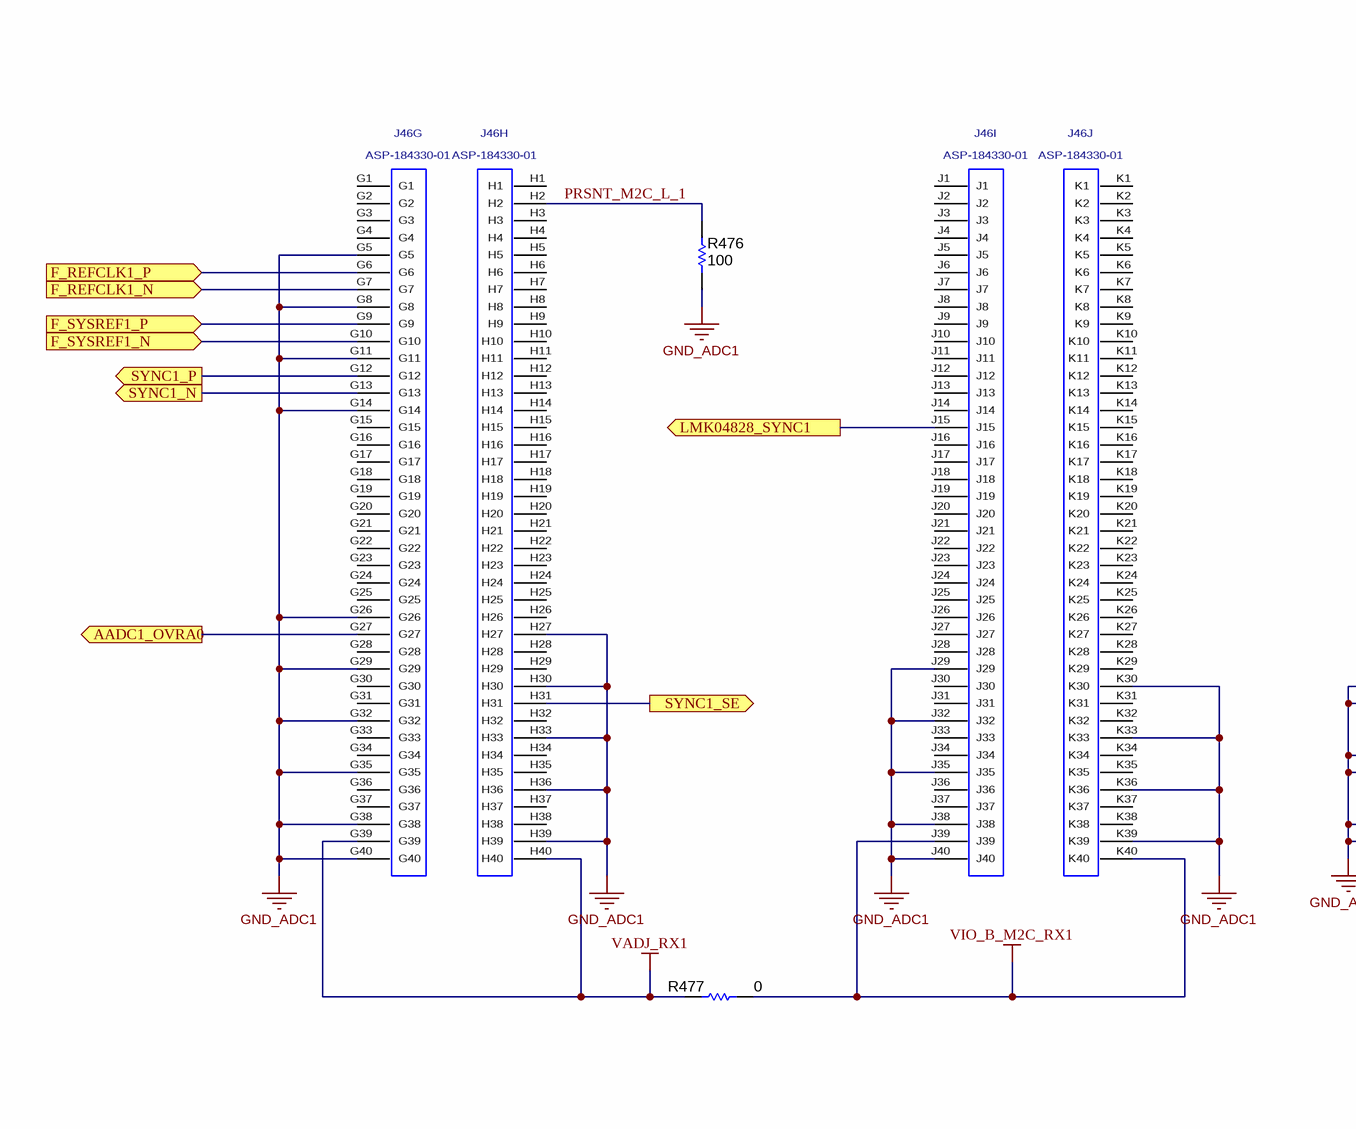
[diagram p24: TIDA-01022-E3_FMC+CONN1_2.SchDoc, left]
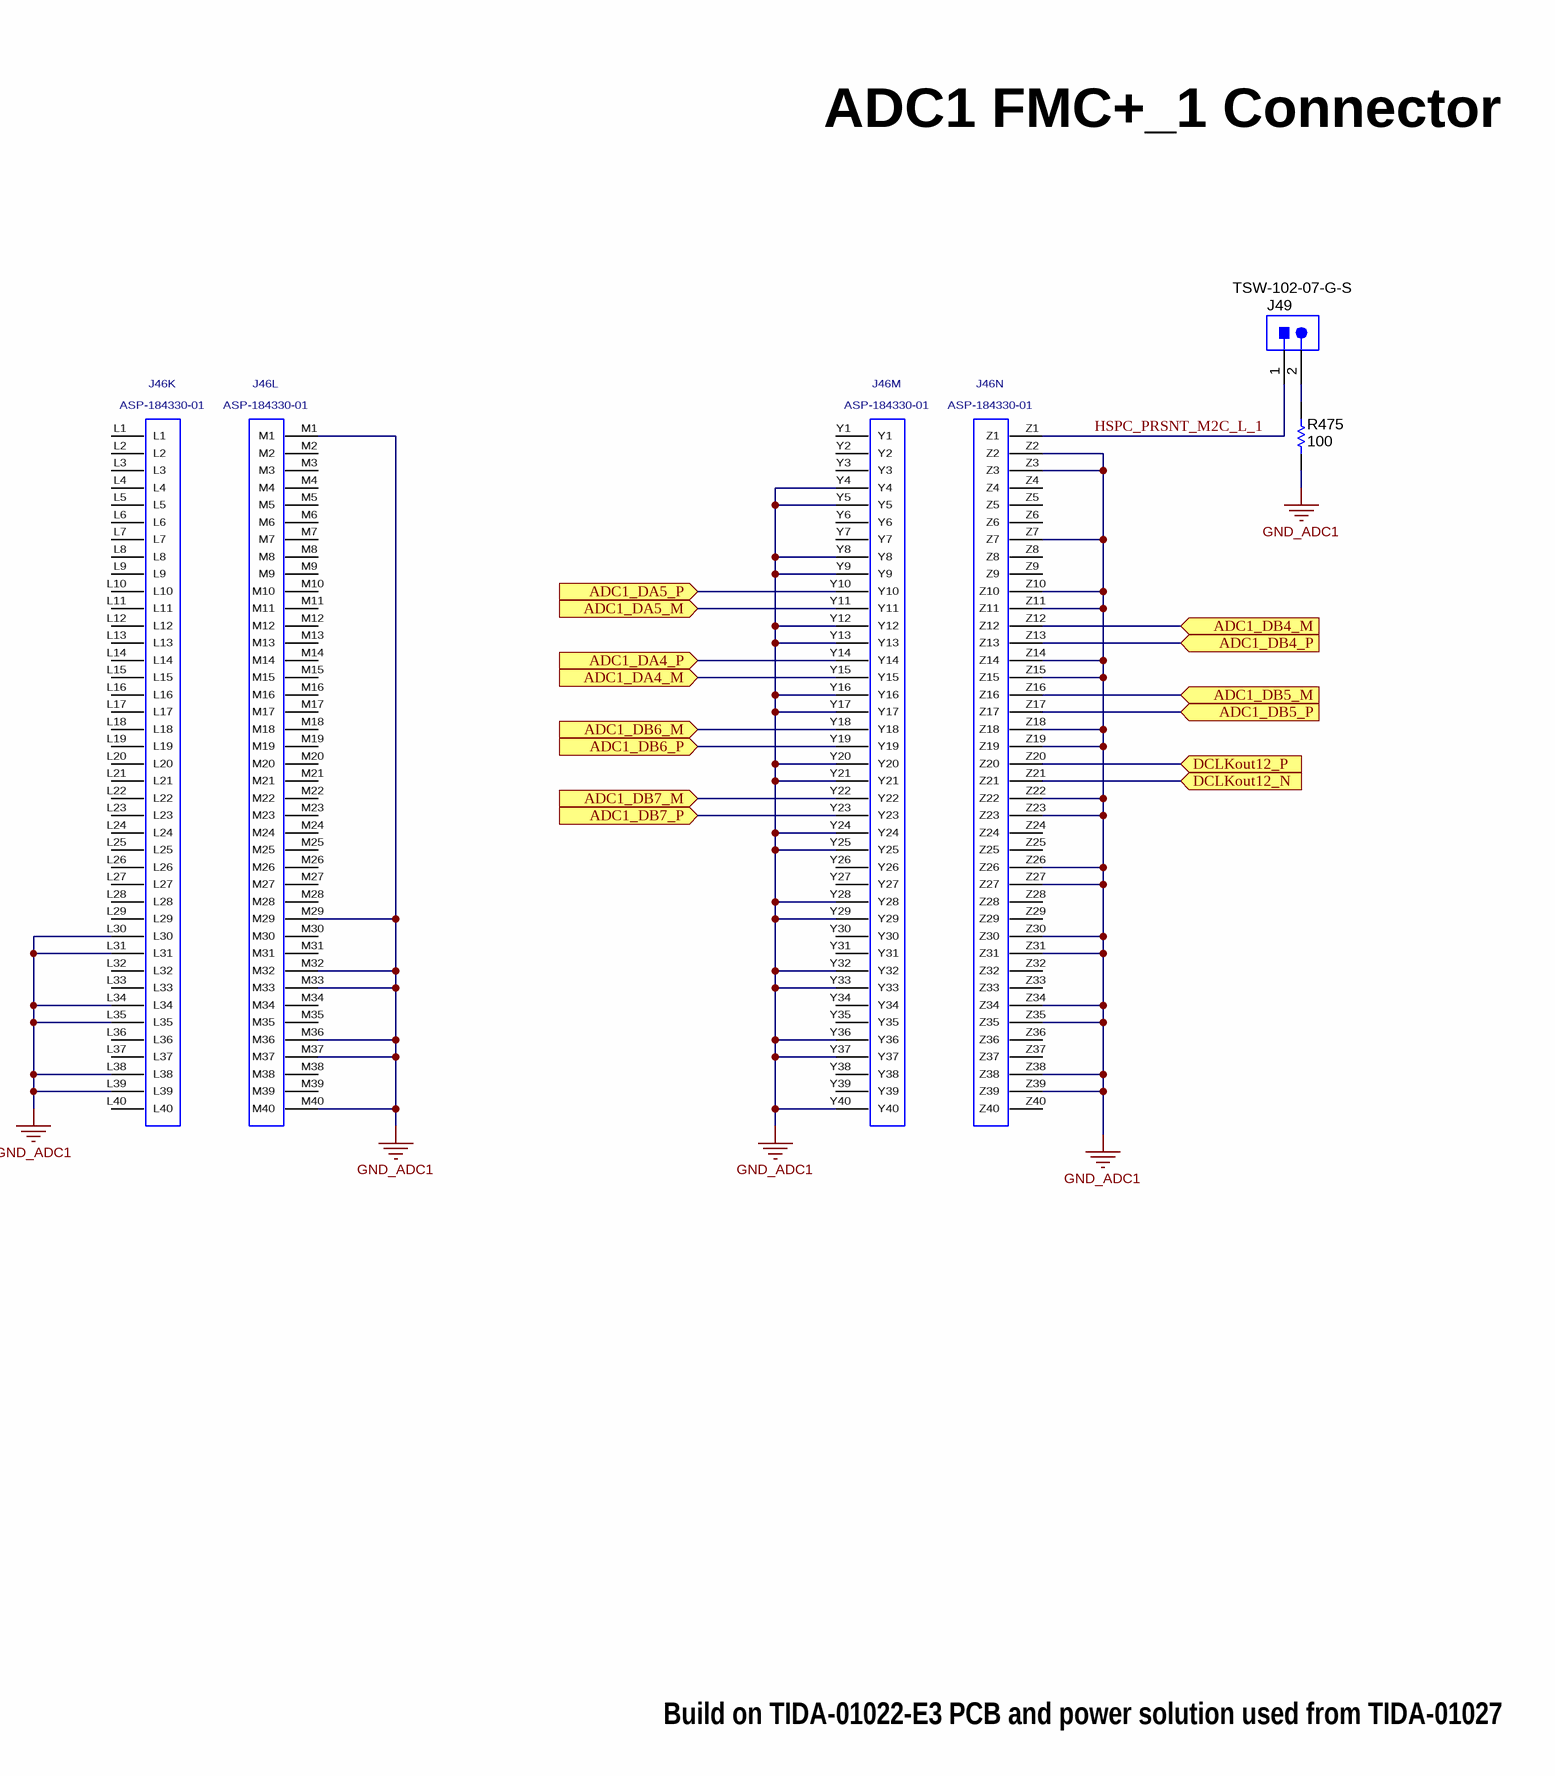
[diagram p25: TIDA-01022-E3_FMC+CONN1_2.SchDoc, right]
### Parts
J46  ASP-184330-01  [ASP-184330-01]  (parts G,H,I,J,K,L,M,N of 14)
J49  TSW-102-07-G-S  [TSW-102-07-G-S]
R475  ValueDisplayed: 100  [0402]  (hidden comment: CRCW0402100RJNED)
R476  ValueDisplayed: 100  [0402]  (hidden comment: CRCW0402100RJNED)
R477  ValueDisplayed: 0  [0402]  (hidden comment: CRCW04020000Z0ED)

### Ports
AADC1_OVRA0 (out), ADC1_DA4_M (in), ADC1_DA4_P (in), ADC1_DA5_M (in), ADC1_DA5_P (in), ADC1_DB4_M (in), ADC1_DB4_P (in), ADC1_DB5_M (in), ADC1_DB5_P (in), ADC1_DB6_M (in), ADC1_DB6_P (in), ADC1_DB7_M (in), ADC1_DB7_P (in), DCLKout12_N (in), DCLKout12_P (in), F_REFCLK1_N (in), F_REFCLK1_P (in), F_SYSREF1_N (in), F_SYSREF1_P (in), LMK04828_SYNC1 (out), SYNC1_N (out), SYNC1_P (out), SYNC1_SE (out)

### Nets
GND_ADC1: J46.G5 J46.G8 J46.G11 J46.G14 J46.G26 J46.G29 J46.G32 J46.G35 J46.G38 J46.G40 J46.H27 J46.H30 J46.H33 J46.H36 J46.H39 J46.J29 J46.J32 J46.J35 J46.J38 J46.J40 J46.K30 J46.K33 J46.K36 J46.K39 J46.L30 J46.L31 J46.L34 J46.L35 J46.L38 J46.L39 J46.M1 J46.M29 J46.M32 J46.M33 J46.M36 J46.M37 J46.M40 J46.Y4 J46.Y5 J46.Y8 J46.Y9 J46.Y12 J46.Y13 J46.Y16 J46.Y17 J46.Y20 J46.Y21 J46.Y24 J46.Y25 J46.Y28 J46.Y29 J46.Y32 J46.Y33 J46.Y36 J46.Y37 J46.Y40 J46.Z2 J46.Z3 J46.Z7 J46.Z10 J46.Z11 J46.Z14 J46.Z15 J46.Z18 J46.Z19 J46.Z22 J46.Z23 J46.Z26 J46.Z27 J46.Z30 J46.Z31 J46.Z34 J46.Z35 J46.Z38 J46.Z39 R475.1 R476.1  [project net DGND]
VADJ_RX1: J46.G39 J46.H40 R477.2
VIO_B_M2C_RX1: J46.J39 J46.K40 R477.1
AADC1_OVRA0: J46.G27 ; port AADC1_OVRA0
ADC1_DA4_M: J46.Y15 ; port ADC1_DA4_M
ADC1_DA4_P: J46.Y14 ; port ADC1_DA4_P
ADC1_DA5_M: J46.Y11 ; port ADC1_DA5_M
ADC1_DA5_P: J46.Y10 ; port ADC1_DA5_P
ADC1_DB4_M: J46.Z12 ; port ADC1_DB4_M
ADC1_DB4_P: J46.Z13 ; port ADC1_DB4_P
ADC1_DB5_M: J46.Z16 ; port ADC1_DB5_M
ADC1_DB5_P: J46.Z17 ; port ADC1_DB5_P
ADC1_DB6_M: J46.Y18 ; port ADC1_DB6_M
ADC1_DB6_P: J46.Y19 ; port ADC1_DB6_P
ADC1_DB7_M: J46.Y22 ; port ADC1_DB7_M
ADC1_DB7_P: J46.Y23 ; port ADC1_DB7_P
DCLKout12_N: J46.Z21 ; port DCLKout12_N
DCLKout12_P: J46.Z20 ; port DCLKout12_P
F_REFCLK1_N: J46.G7 ; port F_REFCLK1_N
F_REFCLK1_P: J46.G6 ; port F_REFCLK1_P
F_SYSREF1_N: J46.G10 ; port F_SYSREF1_N
F_SYSREF1_P: J46.G9 ; port F_SYSREF1_P
HSPC_PRSNT_M2C_L_1: J46.Z1 J49.1
LMK04828_SYNC1: J46.J15 ; port LMK04828_SYNC1
PRSNT_M2C_L_1: J46.H2 R476.2
SYNC1_N: J46.G13 ; port SYNC1_N
SYNC1_P: J46.G12 ; port SYNC1_P
SYNC1_SE: J46.H31 ; port SYNC1_SE
NetJ49_2: J49.2 R475.2

Not connected (* = marked no-connect by the designer): J46 G1 G2 G3 G4 G15 G16 G17 G18 G19 G20 G21 G22 G23 G24 G25 G28 G30 G31 G33 G34 G36 G37 H1 H3 H4 H5 H6 H7 H8 H9 H10 H11 H12 H13 H14 H15 H16 H17 H18 H19 H20 H21 H22 H23 H24 H25 H26 H28 H29 H32 H34 H35 H37 H38 J1 J2 J3 J4 J5 J6 J7 J8 J9 J10 J11 J12 J13 J14 J16 J17 J18 J19 J20 J21 J22 J23 J24 J25 J26 J27 J28 J30 J31 J33 J34 J36 J37 K1 K2 K3 K4 K5 K6 K7 K8 K9 K10 K11 K12 K13 K14 K15 K16 K17 K18 K19 K20 K21 K22 K23 K24 K25 K26 K27 K28 K29 K31 K32 K34 K35 K37 K38 L1 L2 L3 L4 L5 L6 L7 L8 L9 L10 L11 L12 L13 L14 L15 L16 L17 L18 L19 L20 L21 L22 L23 L24 L25 L26 L27 L28 L29 L32 L33 L36 L37 L40 M2 M3 M4 M5 M6 M7 M8 M9 M10 M11 M12 M13 M14 M15 M16 M17 M18 M19 M20 M21 M22 M23 M24 M25 M26 M27 M28 M30 M31 M34 M35 M38 M39 Y1 Y2 Y3 Y6 Y7 Y26 Y27 Y30 Y31 Y34 Y35 Y38 Y39 Z4 Z5 Z6 Z8 Z9 Z24 Z25 Z28 Z29 Z32 Z33 Z36 Z37 Z40

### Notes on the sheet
- ADC1 FMC+_1 Connector
- Build on TIDA-01022-E3 PCB and power solution used from TIDA-01027

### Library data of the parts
J46 = ASP-184330-01: as J46 on sheet TIDA-01022-E3_FMC+CONN1_1
J49 = TSW-102-07-G-S: as J35-J38 on sheet TIDA-01022-E3_Programming for ADC_LMK _LMX
R475 R476 = CRCW0402100RJNED: RES, 100, 5%, 0.063 W, 0402; Manufacturer: Vishay-Dale; CompType: Resistor; Value: 100; Value_Code: 100R; Tolerance_%: 5; Power_W: 0.063; Value2: 0.063W; VDC_V: 50; TempCo: 200 ppm/C; SizeArea_mm2: 0.5; SizeX_mm: 1; SizeZ_mm: 0.6; EIA_Code: E24; U/M: EA; AEC Category: Q200
R477 = CRCW04020000Z0ED: as R474 on sheet TIDA-01022-E3_FMC+CONN1_1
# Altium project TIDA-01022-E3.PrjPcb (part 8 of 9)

## Sheet TIDA-01022-E3_Power3.SchDoc: Power Supplies
size 431 x 279 mm; Date: Not shown in title block; ApprovedBy: Not shown in title block; CheckedBy: Not shown in title block; Author: Not shown in title block; CompanyName: Not shown in title block; DrawnBy: Avinash N; Engineer: Not shown in title block; Organization: Not shown in title block; Address1: Not shown in title block; Address2: Not shown in title block; Address3: Not shown in title block; Address4: Not shown in title block; DocumentNumber: 1; Revision: Use project parameter SCH_Rev; SheetNumber: 23; SheetTotal: 26; PageSetup: Record=PageOptions¦CenterHorizontal=True¦CenterVertical=True¦PrintScale=1.00¦XCorrection=1.00¦YCorrection=1.00¦PrintKind=0¦BorderSize=5000000¦LeftOffset=0¦BottomOffset=0¦Orientation=2¦PaperLength=1000¦PaperWidth=1000¦Scale=100¦PaperSource=15¦PrintQuality=600¦MediaType=1¦DitherType=10¦PaperKind=Letter¦PrintScaleMode=1

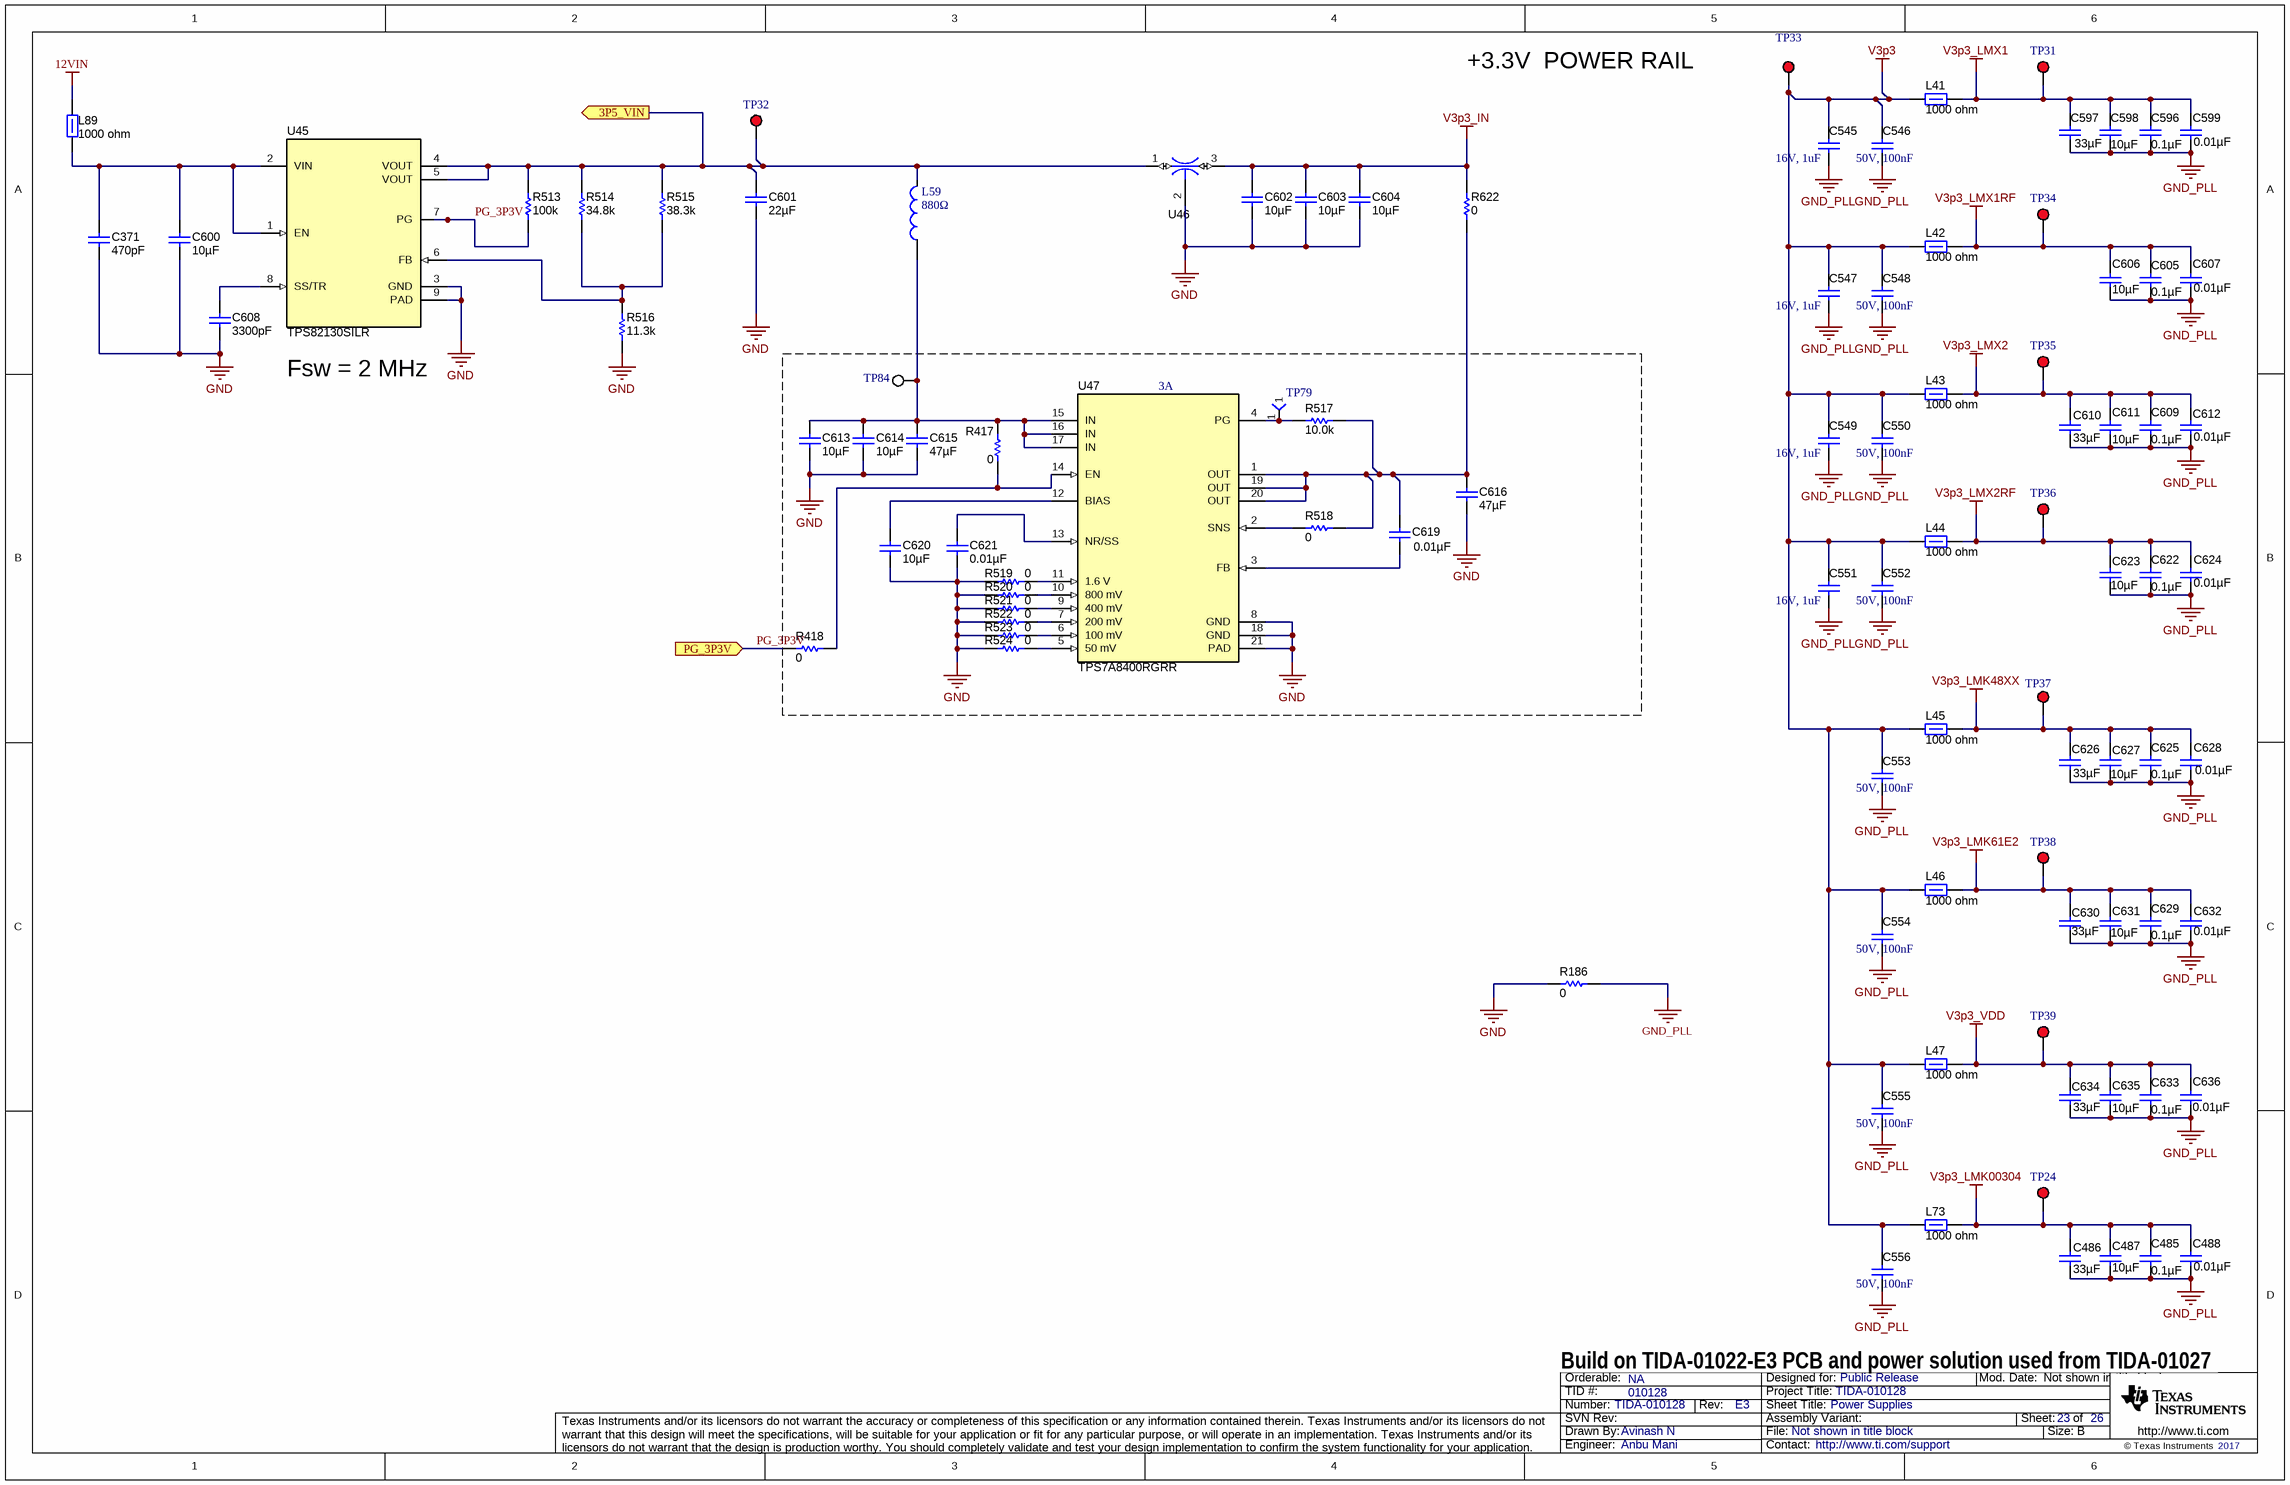
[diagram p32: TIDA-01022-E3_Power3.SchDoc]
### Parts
C371  ValueDisplayed: 470pF  [0402]  (hidden comment: GRM1555C1H471JA01D)
C485  ValueDisplayed: 0.1µF  [0603]  (hidden comment: CGA3E2X7R1H104K080AA)
C486  ValueDisplayed: 33µF  [1206_180]  (hidden comment: C3216X5R1E336M160AC)
C487  ValueDisplayed: 10µF  [1206_190]  (hidden comment: C3216X7R1E106M160AE)
C488  ValueDisplayed: 0.01µF  [0603]  (hidden comment: GCM188R71H103KA37D)
C545  16V, 1uF  [0603_1.6x0.8x0.8mm_Reflow Soldering]
C546  50V, 100nF  [0603_1.6x0.8x0.8mm_Reflow Soldering]
C547  16V, 1uF  [0603_1.6x0.8x0.8mm_Reflow Soldering]
C548  50V, 100nF  [0603_1.6x0.8x0.8mm_Reflow Soldering]
C549  16V, 1uF  [0603_1.6x0.8x0.8mm_Reflow Soldering]
C550  50V, 100nF  [0603_1.6x0.8x0.8mm_Reflow Soldering]
C551  16V, 1uF  [0603_1.6x0.8x0.8mm_Reflow Soldering]
C552  50V, 100nF  [0603_1.6x0.8x0.8mm_Reflow Soldering]
C553  50V, 100nF  [0603_1.6x0.8x0.8mm_Reflow Soldering]
C554  50V, 100nF  [0603_1.6x0.8x0.8mm_Reflow Soldering]
C555  50V, 100nF  [0603_1.6x0.8x0.8mm_Reflow Soldering]
C556  50V, 100nF  [0603_1.6x0.8x0.8mm_Reflow Soldering]
C596  ValueDisplayed: 0.1µF  [0603]  (hidden comment: CGA3E2X7R1H104K080AA)
C597  ValueDisplayed: 33µF  [1206_180]  (hidden comment: C3216X5R1E336M160AC)
C598  ValueDisplayed: 10µF  [1206_190]  (hidden comment: C3216X7R1E106M160AE)
C599  ValueDisplayed: 0.01µF  [0603]  (hidden comment: GCM188R71H103KA37D)
C600  ValueDisplayed: 10µF  [1206_190]  (hidden comment: C3216X7R1E106M160AE)
C601  ValueDisplayed: 22µF  [0805_HV]  (hidden comment: JMK212BJ226MG-T)
C602  ValueDisplayed: 10µF  [1206_190]  (hidden comment: C3216X7R1E106M160AE)
C603  ValueDisplayed: 10µF  [1206_190]  (hidden comment: C3216X7R1E106M160AE)
C604  ValueDisplayed: 10µF  [1206_190]  (hidden comment: C3216X7R1E106M160AE)
C605  ValueDisplayed: 0.1µF  [0603]  (hidden comment: CGA3E2X7R1H104K080AA)
C606  ValueDisplayed: 10µF  [1206_190]  (hidden comment: C3216X7R1E106M160AE)
C607  ValueDisplayed: 0.01µF  [0603]  (hidden comment: GCM188R71H103KA37D)
C608  ValueDisplayed: 3300pF  [0603]  (hidden comment: GRM1885C1H332JA01D)
C609  ValueDisplayed: 0.1µF  [0603]  (hidden comment: CGA3E2X7R1H104K080AA)
C610  ValueDisplayed: 33µF  [1206_180]  (hidden comment: C3216X5R1E336M160AC)
C611  ValueDisplayed: 10µF  [1206_190]  (hidden comment: C3216X7R1E106M160AE)
C612  ValueDisplayed: 0.01µF  [0603]  (hidden comment: GCM188R71H103KA37D)
C613  ValueDisplayed: 10µF  [0805_HV]  (hidden comment: GRM21BR61C106KE15L)
C614  ValueDisplayed: 10µF  [0805_HV]  (hidden comment: GRM21BR61C106KE15L)
C615  ValueDisplayed: 47µF  [0805_HV]  (hidden comment: GRM219R60G476ME44D)
C616  ValueDisplayed: 47µF  [0805_HV]  (hidden comment: GRM219R60G476ME44D)
C619  ValueDisplayed: 0.01µF  [0603]  (hidden comment: GRM188R71H103KA01D)
C620  ValueDisplayed: 10µF  [0805_HV]  (hidden comment: GRM21BR61C106KE15L)
C621  ValueDisplayed: 0.01µF  [0603]  (hidden comment: GRM188R71H103KA01D)
C622  ValueDisplayed: 0.1µF  [0603]  (hidden comment: CGA3E2X7R1H104K080AA)
C623  ValueDisplayed: 10µF  [1206_190]  (hidden comment: C3216X7R1E106M160AE)
C624  ValueDisplayed: 0.01µF  [0603]  (hidden comment: GCM188R71H103KA37D)
C625  ValueDisplayed: 0.1µF  [0603]  (hidden comment: CGA3E2X7R1H104K080AA)
C626  ValueDisplayed: 33µF  [1206_180]  (hidden comment: C3216X5R1E336M160AC)
C627  ValueDisplayed: 10µF  [1206_190]  (hidden comment: C3216X7R1E106M160AE)
C628  ValueDisplayed: 0.01µF  [0603]  (hidden comment: GCM188R71H103KA37D)
C629  ValueDisplayed: 0.1µF  [0603]  (hidden comment: CGA3E2X7R1H104K080AA)
C630  ValueDisplayed: 33µF  [1206_180]  (hidden comment: C3216X5R1E336M160AC)
C631  ValueDisplayed: 10µF  [1206_190]  (hidden comment: C3216X7R1E106M160AE)
C632  ValueDisplayed: 0.01µF  [0603]  (hidden comment: GCM188R71H103KA37D)
C633  ValueDisplayed: 0.1µF  [0603]  (hidden comment: CGA3E2X7R1H104K080AA)
C634  ValueDisplayed: 33µF  [1206_180]  (hidden comment: C3216X5R1E336M160AC)
C635  ValueDisplayed: 10µF  [1206_190]  (hidden comment: C3216X7R1E106M160AE)
C636  ValueDisplayed: 0.01µF  [0603]  (hidden comment: GCM188R71H103KA37D)
L41  ValueDisplayed: 1000 ohm  [1806_HighSpeed]  (hidden comment: BLM41PG102SN1L)
L42  ValueDisplayed: 1000 ohm  [1806_HighSpeed]  (hidden comment: BLM41PG102SN1L)
L43  ValueDisplayed: 1000 ohm  [1806_HighSpeed]  (hidden comment: BLM41PG102SN1L)
L44  ValueDisplayed: 1000 ohm  [1806_HighSpeed]  (hidden comment: BLM41PG102SN1L)
L45  ValueDisplayed: 1000 ohm  [1806_HighSpeed]  (hidden comment: BLM41PG102SN1L)
L46  ValueDisplayed: 1000 ohm  [1806_HighSpeed]  (hidden comment: BLM41PG102SN1L)
L47  ValueDisplayed: 1000 ohm  [1806_HighSpeed]  (hidden comment: BLM41PG102SN1L)
L59  880Ω  [WE-CBF_1812_High Current]
L73  ValueDisplayed: 1000 ohm  [1806_HighSpeed]  (hidden comment: BLM41PG102SN1L)
L89  ValueDisplayed: 1000 ohm  [1806_HighSpeed]  (hidden comment: BLM41PG102SN1L)
R186  ValueDisplayed: 0  [1206]  (hidden comment: CRCW12060000Z0EA)
R417  ValueDisplayed: 0  [0603]  (hidden comment: CRCW06030000Z0EA)
R418  ValueDisplayed: 0  [0603]  (hidden comment: CRCW06030000Z0EA)
R513  ValueDisplayed: 100k  [0402]  (hidden comment: CRCW0402100KFKED)
R514  ValueDisplayed: 34.8k  [0603]  (hidden comment: CRCW060334K8FKEA)
R515  ValueDisplayed: 38.3k  [0402]  (hidden comment: CRCW040238K3FKED)
R516  ValueDisplayed: 11.3k  [0402]  (hidden comment: CRCW040211K3FKED)
R517  ValueDisplayed: 10.0k  [0603]  (hidden comment: CRCW060310K0FKEA)
R518  ValueDisplayed: 0  [0603]  (hidden comment: CRCW06030000Z0EA)
R519  ValueDisplayed: 0  [0402]  (hidden comment: CRCW04020000Z0ED)
R520  ValueDisplayed: 0  [0402]  (hidden comment: CRCW04020000Z0ED)
R521  ValueDisplayed: 0  [0402]  (hidden comment: CRCW04020000Z0ED)
R522  ValueDisplayed: 0  [0402]  (hidden comment: CRCW04020000Z0ED)
R523  ValueDisplayed: 0  [0402]  (hidden comment: CRCW04020000Z0ED)
R524  ValueDisplayed: 0  [0402]  (hidden comment: CRCW04020000Z0ED)
R622  ValueDisplayed: 0  [1206]  (hidden comment: CRCW12060000Z0EA)
TP24  5000  [Keystone5000]  (value not drawn)
TP31  5000  [Keystone5000]  (value not drawn)
TP32  5000  [Keystone5000]  (value not drawn)
TP33  5000  [Keystone5000]  (value not drawn)
TP34  5000  [Keystone5000]  (value not drawn)
TP35  5000  [Keystone5000]  (value not drawn)
TP36  5000  [Keystone5000]  (value not drawn)
TP37  5000  [Keystone5000]  (value not drawn)
TP38  5000  [Keystone5000]  (value not drawn)
TP39  5000  [Keystone5000]  (value not drawn)
TP79  TP-025-SMT  [PROBE_POINT_30PAD]  (value not drawn)
TP84  5015  [Testpoint_Keystone_Miniature]  (value not drawn)
U45  TPS82130SILR  [SIL0008D_SMD]
U46  NFM31PC276B0J3L  [Murata_NFM31P]  (value not drawn)
U47  TPS7A8400RGRR  [RGR0020A]

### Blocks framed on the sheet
3A: C613-C616 C619-C621 R417 R418 R517-R524 TP79 TP84 U47

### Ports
3P5_VIN (out), PG_3P3V (in)

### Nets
12VIN: L89.2
GND: C371.2 C600.2 C601.2 C602.1 C603.1 C604.1 C608.1 C613.2 C614.2 C615.2 C616.2 C620.2 C621.2 R186.1 R516.1 R519.1 R520.1 R521.1 R522.1 R523.1 R524.1 U45.3(GND) U45.9(PAD) U46.2 U47.8(GND) U47.18(GND) U47.21(PAD)
GND_PLL: C485.2 C486.2 C487.1 C488.2 C545.2 C546.1 C547.2 C548.1 C549.2 C550.1 C551.2 C552.1 C553.1 C554.1 C555.1 C556.1 C596.2 C597.2 C598.1 C599.2 C605.2 C606.1 C607.2 C609.2 C610.2 C611.1 C612.2 C622.2 C623.1 C624.2 C625.2 C626.2 C627.1 C628.2 C629.2 C630.2 C631.1 C632.2 C633.2 C634.2 C635.1 C636.2 R186.2  [project net DGND]
V3p3: C545.1 C546.2 C547.1 C548.2 C549.1 C550.2 C551.1 C552.2 C553.2 C554.2 C555.2 C556.2 L41.1 L42.1 L43.1 L44.1 L45.1 L46.1 L47.1 L73.1 TP33.1
V3p3_IN: C602.2 C603.2 C604.2 R622.2 U46.3
V3p3_LMK48XX: C625.1 C626.1 C627.2 C628.1 L45.2 TP37.1
V3p3_LMK61E2: C629.1 C630.1 C631.2 C632.1 L46.2 TP38.1
V3p3_LMK00304: C485.1 C486.1 C487.2 C488.1 L73.2 TP24.1
V3p3_LMX1: C596.1 C597.1 C598.2 C599.1 L41.2 TP31.1
V3p3_LMX1RF: C605.1 C606.2 C607.1 L42.2 TP34.1
V3p3_LMX2: C609.1 C610.1 C611.2 C612.1 L43.2 TP35.1
V3p3_LMX2RF: C622.1 C623.2 C624.1 L44.2 TP36.1
V3p3_VDD: C633.1 C634.1 C635.2 C636.1 L47.2 TP39.1
3P5_VIN: C601.1 L59.2 R513.2 R514.2 R515.2 TP32.1 U45.4(VOUT) U45.5(VOUT) U46.1 ; port 3P5_VIN
PG_3P3V: R418.2 R513.1 U45.7(PG) ; port PG_3P3V
NetC371_1: C371.1 C600.1 L89.1 U45.1(EN) U45.2(VIN)
NetC608_2: C608.2 U45.8(SS/TR)
NetC613_1: C613.1 C614.1 C615.1 L59.1 R417.1 TP84.1 U47.15(IN) U47.16(IN) U47.17(IN)
NetC616_1: C616.1 C619.1 R517.1 R518.2 R622.1 U47.1(OUT) U47.19(OUT) U47.20(OUT)
NetC619_2: C619.2 U47.3(FB)
NetC620_1: C620.1 U47.12(BIAS)
NetC621_1: C621.1 U47.13(NR/SS)
NetR417_2: R417.2 R418.1 U47.14(EN)
NetR514_1: R514.1 R515.1 R516.2 U45.6(FB)
NetR517_2: R517.2 TP79.1 U47.4(PG)
NetR518_1: R518.1 U47.2(SNS)
NetR519_2: R519.2 U47.11(1.6_V)
NetR520_2: R520.2 U47.10(800_mV)
NetR521_2: R521.2 U47.9(400_mV)
NetR522_2: R522.2 U47.7(200_mV)
NetR523_2: R523.2 U47.6(100_mV)
NetR524_2: R524.2 U47.5(50_mV)

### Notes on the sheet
- +3.3V  POWER RAIL
- Fsw = 2 MHz
- Build on TIDA-01022-E3 PCB and power solution used from TIDA-01027

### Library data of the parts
C371 = GRM1555C1H471JA01D: CAP, CERM, 470 pF, 50 V, +/- 5%, C0G/NP0, 0402; Manufacturer: MuRata; Polarized: N; CompType: Capacitor; Value: 470pF; U/M: EA; Cap_F: 0.00000000047; Tolerance_%: 5; Value1: Unknown; VDC_V: 50; Value2: 50V; TaMin_C: -55; TaMax_C: 125; SizeArea_mm2: 0.5; SizeAreaWB_mm2: 3; SizeX_mm: 1; SizeZ_mm: 0.6; AEC Category: Q200
C485 C596 C605 C609 C622 C625 C629 C633 = CGA3E2X7R1H104K080AA: CAP, CERM, 0.1 µF, 50 V, +/- 10%, X7R, AEC-Q200 Grade 1, 0603; Manufacturer: TDK; Polarized: N; CompType: Capacitor; Value: 0.1uF; U/M: EA; Cap_F: 0.0000001; Tolerance_%: 10; ESR_ohm: 0.0296; Value1: 0.0296 ohm; VDC_V: 50; Value2: 50V; IRMS_A: 0.97199; TaMin_C: -55; TaMax_C: 125; SizeArea_mm2: 1.28; SizeAreaWB_mm2: 4.68; SizeX_mm: 1.6; SizeY_mm: 0.8; SizeZ_mm: 1; AEC Category: Q200; AEC Qualified: Y
C486 C597 C610 C626 C630 C634 = C3216X5R1E336M160AC: CAP, CERM, 33 µF, 25 V, +/- 20%, X5R, 1206; Manufacturer: TDK; Polarized: N; CompType: Capacitor; Value: 33uF; U/M: EA; Cap_F: 0.000033; Tolerance_%: 20; ESR_ohm: 0.002648; Value1: 0.002648 ohm; VDC_V: 25; Value2: 25V; IRMS_A: 4.45864; TaMin_C: -55; TaMax_C: 85; SizeArea_mm2: 5.12; SizeAreaWB_mm2: 10.92; SizeX_mm: 3.2; SizeY_mm: 1.6; SizeZ_mm: 1.8; AEC Category: Q200
C487 C598 C600 C602-C604 C606 C611 C623 C627 C631 C635 = C3216X7R1E106M160AE: CAP, CERM, 10 µF, 25 V, +/- 20%, X7R, 1206_190; Manufacturer: TDK; Polarized: N; CompType: Capacitor; Value: 10uF; U/M: EA; Cap_F: 0.00001; Tolerance_%: 20; Value1: Unknown; VDC_V: 25; Value2: 25V; TaMin_C: -55; TaMax_C: 125; Cap_Case: 1206; SizeArea_mm2: 5.12; SizeAreaWB_mm2: 10.92; SizeX_mm: 3.2; SizeY_mm: 1.6; SizeZ_mm: 1.9; AEC Category: Q200
C488 C599 C607 C612 C624 C628 C632 C636 = GCM188R71H103KA37D: CAP, CERM, 0.01 µF, 50 V, +/- 10%, X7R, AEC-Q200 Grade 1, 0603; Manufacturer: MuRata; Polarized: N; CompType: Capacitor; Value: 0.01uF; U/M: EA; Cap_F: 0.00000001; Tolerance_%: 10; Value1: Unknown; VDC_V: 50; Value2: 50V; TaMin_C: -55; TaMax_C: 125; SizeArea_mm2: 1.28; SizeAreaWB_mm2: 4.68; SizeX_mm: 1.6; SizeY_mm: 0.8; SizeZ_mm: 1; AEC Category: Q200; AEC Qualified: Y
C545 C547 C549 C551 = 885012206052: WCAP-CSGP Ceramic Capacitors, 0603, X7R, 16V, 1uF; Rated Voltage: 16V DC
C546 C548 C550 C552-C556 = 885012206095: WCAP-CSGP Ceramic Capacitors, 0603, X7R, 50V, 100nF; Rated Voltage: 50V DC
C601 = JMK212BJ226MG-T: CAP, CERM, 22 µF, 6.3 V, +/- 20%, X5R, 0805; Manufacturer: Taiyo Yuden; Polarized: N; CompType: Capacitor; Value: 22uF; U/M: EA; Cap_F: 0.000022; Tolerance_%: 20; Value1: Unknown; VDC_V: 6.3; Value2: 6.3V; TaMin_C: -55; TaMax_C: 85; Cap_Case: 0805; SizeArea_mm2: 2.5; SizeAreaWB_mm2: 6.75; SizeX_mm: 2; SizeY_mm: 1.25; SizeZ_mm: 1.45; AEC Category: Q200
C608 = GRM1885C1H332JA01D: CAP, CERM, 3300 pF, 50 V, +/- 5%, C0G/NP0, 0603; Manufacturer: MuRata; Polarized: N; CompType: Capacitor; Value: 3300pF; U/M: EA; Cap_F: 0.0000000033; Tolerance_%: 5; Value1: Unknown; VDC_V: 50; Value2: 50V; TaMin_C: -55; TaMax_C: 125; SizeArea_mm2: 1.28; SizeAreaWB_mm2: 4.68; SizeX_mm: 1.6; SizeY_mm: 0.8; SizeZ_mm: 1; AEC Category: Q200
C613 C614 C620 = GRM21BR61C106KE15L: CAP, CERM, 10 µF, 16 V, +/- 10%, X5R, 0805; Manufacturer: MuRata; Polarized: N; CompType: Capacitor; Value: 10uF; U/M: EA; Cap_F: 0.00001; Tolerance_%: 10; ESR_ohm: 0.008; Value1: 0.008 ohm; VDC_V: 16; Value2: 16V; TaMin_C: -55; TaMax_C: 85; Cap_Case: 0805; SizeArea_mm2: 2.5; SizeAreaWB_mm2: 6.75; SizeX_mm: 2; SizeY_mm: 1.25; SizeZ_mm: 1.45; AEC Category: Q200
C615 C616 = GRM219R60G476ME44D: CAP, CERM, 47 µF, 4 V, +/- 20%, X5R, 0805; Manufacturer: MuRata; Polarized: N; CompType: Capacitor; Value: 47uF; U/M: EA; Cap_F: 0.000047; Tolerance_%: 20; Value1: Unknown; VDC_V: 4; Value2: 4V; TaMin_C: -55; TaMax_C: 85; Cap_Case: 0805; SizeArea_mm2: 2.5; SizeAreaWB_mm2: 6.75; SizeX_mm: 2; SizeY_mm: 1.25; SizeZ_mm: 1.45; AEC Category: Q200
C619 C621 = GRM188R71H103KA01D: CAP, CERM, 0.01 µF, 50 V, +/- 10%, X7R, 0603; Manufacturer: MuRata; Polarized: N; CompType: Capacitor; Value: 0.01uF; U/M: EA; Cap_F: 0.00000001; Tolerance_%: 10; Value1: Unknown; VDC_V: 50; Value2: 50V; TaMin_C: -55; TaMax_C: 125; SizeArea_mm2: 1.28; SizeAreaWB_mm2: 4.68; SizeX_mm: 1.6; SizeY_mm: 0.8; SizeZ_mm: 1; AEC Category: Q200
L41-L47 L73 L89 = BLM41PG102SN1L: Ferrite Bead, 1000 ohm @ 100 MHz, 1.5 A, 1806; Manufacturer: MuRata; Imax_A: 1.5; DCR_ohm: 0.09; Value1: 0.09 ohm; Value2: 1.5A; SizeAreaWB_mm2: 14.3; SizeArea_mm2: 7.2; SizeX_mm: 4.5; SizeY_mm: 1.6; SizeZ_mm: 1.85; ZTyp@100MHz_Ohm: 1000
L59 = WE-CBF, 74279252: WE-CBF SMD EMI Suppression Ferrite Bead, 1812, 880Ω; Type: High Current
R186 = CRCW12060000Z0EA: RES, 0, 5%, 0.25 W, 1206; Manufacturer: Vishay-Dale; CompType: Resistor; Value: 0; Value_Code: 0000; Tolerance_%: 5; Power_W: 0.25; Value2: 0.25W; VDC_V: 200; TempCo: 200 ppm/C; SizeArea_mm2: 5.12; SizeX_mm: 3.2; SizeY_mm: 1.6; SizeZ_mm: 1.35; EIA_Code: E24; U/M: EA; AEC Category: Q200; Green_Lifecycle: Active; Green_REACh: Passed
R417 R418 = CRCW06030000Z0EA: RES, 0, 5%, 0.1 W, 0603; Manufacturer: Vishay-Dale; CompType: Resistor; Value: 0; Value_Code: 0000; Tolerance_%: 5; Power_W: 0.1; Value2: 0.1W; VDC_V: 75; TempCo: 200 ppm/C; SizeArea_mm2: 1.28; SizeX_mm: 1.6; SizeY_mm: 0.8; SizeZ_mm: 1; EIA_Code: E24; U/M: EA; AEC Category: Q200; Green_Lifecycle: Active; Green_REACh: Passed
R513 = CRCW0402100KFKED: RES, 100 k, 1%, 0.063 W, 0402; Manufacturer: Vishay-Dale; CompType: Resistor; Value: 100k; Res_ohm: 100000; Tolerance_%: 1; Power_W: 0.063; Value2: 0.063W; VDC_V: 50; TempCo: 100 ppm/C; SizeArea_mm2: 0.5; SizeZ_mm: 0.6; EIA_Code: E96; U/M: EA; AEC Category: Q200
R514 = CRCW060334K8FKEA: RES, 34.8 k, 1%, 0.1 W, 0603; Manufacturer: Vishay-Dale; CompType: Resistor; Value: 34.8k; Res_ohm: 34800; Value_Code: 34k8; Tolerance_%: 1; Power_W: 0.1; Value2: 0.1W; VDC_V: 75; TempCo: 100 ppm/C; SizeArea_mm2: 1.28; SizeX_mm: 1.6; SizeY_mm: 0.8; EIA_Code: E96; U/M: EA; AEC Category: Q200
R515 = CRCW040238K3FKED: RES, 38.3 k, 1%, 0.063 W, 0402; Manufacturer: Vishay-Dale; CompType: Resistor; Value: 38.3k; Res_ohm: 38300; Value_Code: 38k3; Tolerance_%: 1; Power_W: 0.063; Value2: 0.063W; VDC_V: 50; TempCo: 100 ppm/C; SizeArea_mm2: 0.5; SizeZ_mm: 0.6; EIA_Code: E96; U/M: EA; AEC Category: Q200; Green_Lifecycle: Active; Green_REACh: Passed
R516 = CRCW040211K3FKED: RES, 11.3 k, 1%, 0.063 W, 0402; Manufacturer: Vishay-Dale; CompType: Resistor; Value: 11.3k; Res_ohm: 11300; Value_Code: 11k3; Tolerance_%: 1; Power_W: 0.063; Value2: 0.063W; VDC_V: 50; TempCo: 100 ppm/C; SizeArea_mm2: 0.5; SizeZ_mm: 0.6; EIA_Code: E96; U/M: EA; AEC Category: Q200
R517 = CRCW060310K0FKEA: RES, 10.0 k, 1%, 0.1 W, 0603; Manufacturer: Vishay-Dale; CompType: Resistor; Value: 10.0k; Res_ohm: 10000; Value_Code: 10k0; Tolerance_%: 1; Power_W: 0.1; Value2: 0.1W; VDC_V: 75; TempCo: 100 ppm/C; SizeArea_mm2: 1.28; SizeX_mm: 1.6; SizeY_mm: 0.8; EIA_Code: E96; U/M: EA; AEC Category: Q200
R518 = CRCW06030000Z0EA: RES, 0, 5%, 0.1 W, 0603; Manufacturer: Vishay-Dale; CompType: Resistor; Value: 0; Value_Code: 0000; Tolerance_%: 5; Power_W: 0.1; Value2: 0.1W; VDC_V: 75; TempCo: 200 ppm/C; SizeArea_mm2: 1.28; SizeX_mm: 1.6; SizeY_mm: 0.8; SizeZ_mm: 1; EIA_Code: E24; U/M: EA; AEC Category: Q200
R519-R524 = CRCW04020000Z0ED: RES, 0, 5%, 0.063 W, 0402; Manufacturer: Vishay-Dale; CompType: Resistor; Value: 0; Value_Code: 0000; Tolerance_%: 5; Power_W: 0.063; Value2: 0.063W; VDC_V: 50; TempCo: 200 ppm/C; SizeArea_mm2: 0.5; SizeX_mm: 1; SizeZ_mm: 0.6; EIA_Code: E24; U/M: EA; AEC Category: Q200
R622 = CRCW12060000Z0EA: RES, 0, 5%, 0.25 W, 1206; Manufacturer: Vishay-Dale; CompType: Resistor; Value: 0; Value_Code: 0000; Tolerance_%: 5; Power_W: 0.25; Value2: 0.25W; VDC_V: 200; TempCo: 200 ppm/C; SizeArea_mm2: 5.12; SizeX_mm: 3.2; SizeY_mm: 1.6; SizeZ_mm: 1.35; EIA_Code: E24; U/M: EA; AEC Category: Q200
TP24 TP31-TP39 = 5000: Test Point, Miniature, Red, TH; Manufacturer: Keystone; CompType: Test Point Loop; ContactFinish: Silver; Green_Lifecycle: Active; Green_REACh: Passed
TP79 = TP-025-SMT: Test Point, O.025"; Manufacturer: STD; Value: STD
TP84 = 5015: Test Point, Miniature, SMT; Manufacturer: Keystone; CompType: Test Point Loop; Green_Lifecycle: Active; Green_REACh: Passed
U45 = TPS82130SILR: 3-A 17V Step-down Converter Module with Integrated Inductor, SIL0008D (uSIP-8); Alternate PartNumber: TPS82130SILT; Manufacturer: Texas Instruments; SymbolCreator: Altium; SizeArea_mm2: 12.25; SizeAreaWB_mm2: 20.25; SizeX_mm: 3.5; SizeZ_mm: 1.53; CompType: IC; U/M: EA
U46 = NFM31PC276B0J3L: FILTER LC HIGH FREQ 27uF 1206; Manufacturer: MuRata; SymbolCreator: Altium
U47 = TPS7A8400RGRR: High-Current (3 A), High-Accuracy (1%), Low-Noise (4.4 μVRMS), LDO Voltage Regulator, RGR0020A (VQFN-20); Alternate PartNumber: TPS7A8400RGRT; Manufacturer: Texas Instruments; SymbolCreator: a0411947; SizeArea_mm2: 12.25; SizeAreaWB_mm2: 20.25; SizeX_mm: 3.5; SizeZ_mm: 1; CompType: IC; U/M: EA

## Sheet TIDA-01022-E3_Power4.SchDoc: Power Supplies
size 431 x 279 mm; Date: Not shown in title block; ApprovedBy: Not shown in title block; CheckedBy: Not shown in title block; Author: Not shown in title block; CompanyName: Not shown in title block; DrawnBy: Avinash N; Engineer: Not shown in title block; Organization: Not shown in title block; Address1: Not shown in title block; Address2: Not shown in title block; Address3: Not shown in title block; Address4: Not shown in title block; DocumentNumber: 1; Revision: Use project parameter SCH_Rev; SheetNumber: 24; SheetTotal: 26; PageSetup: Record=PageOptions¦CenterHorizontal=True¦CenterVertical=True¦PrintScale=1.00¦XCorrection=1.00¦YCorrection=1.00¦PrintKind=0¦BorderSize=5000000¦LeftOffset=0¦BottomOffset=0¦Orientation=2¦PaperLength=1000¦PaperWidth=1000¦Scale=100¦PaperSource=15¦PrintQuality=600¦MediaType=1¦DitherType=10¦PaperKind=Letter¦PrintScaleMode=1

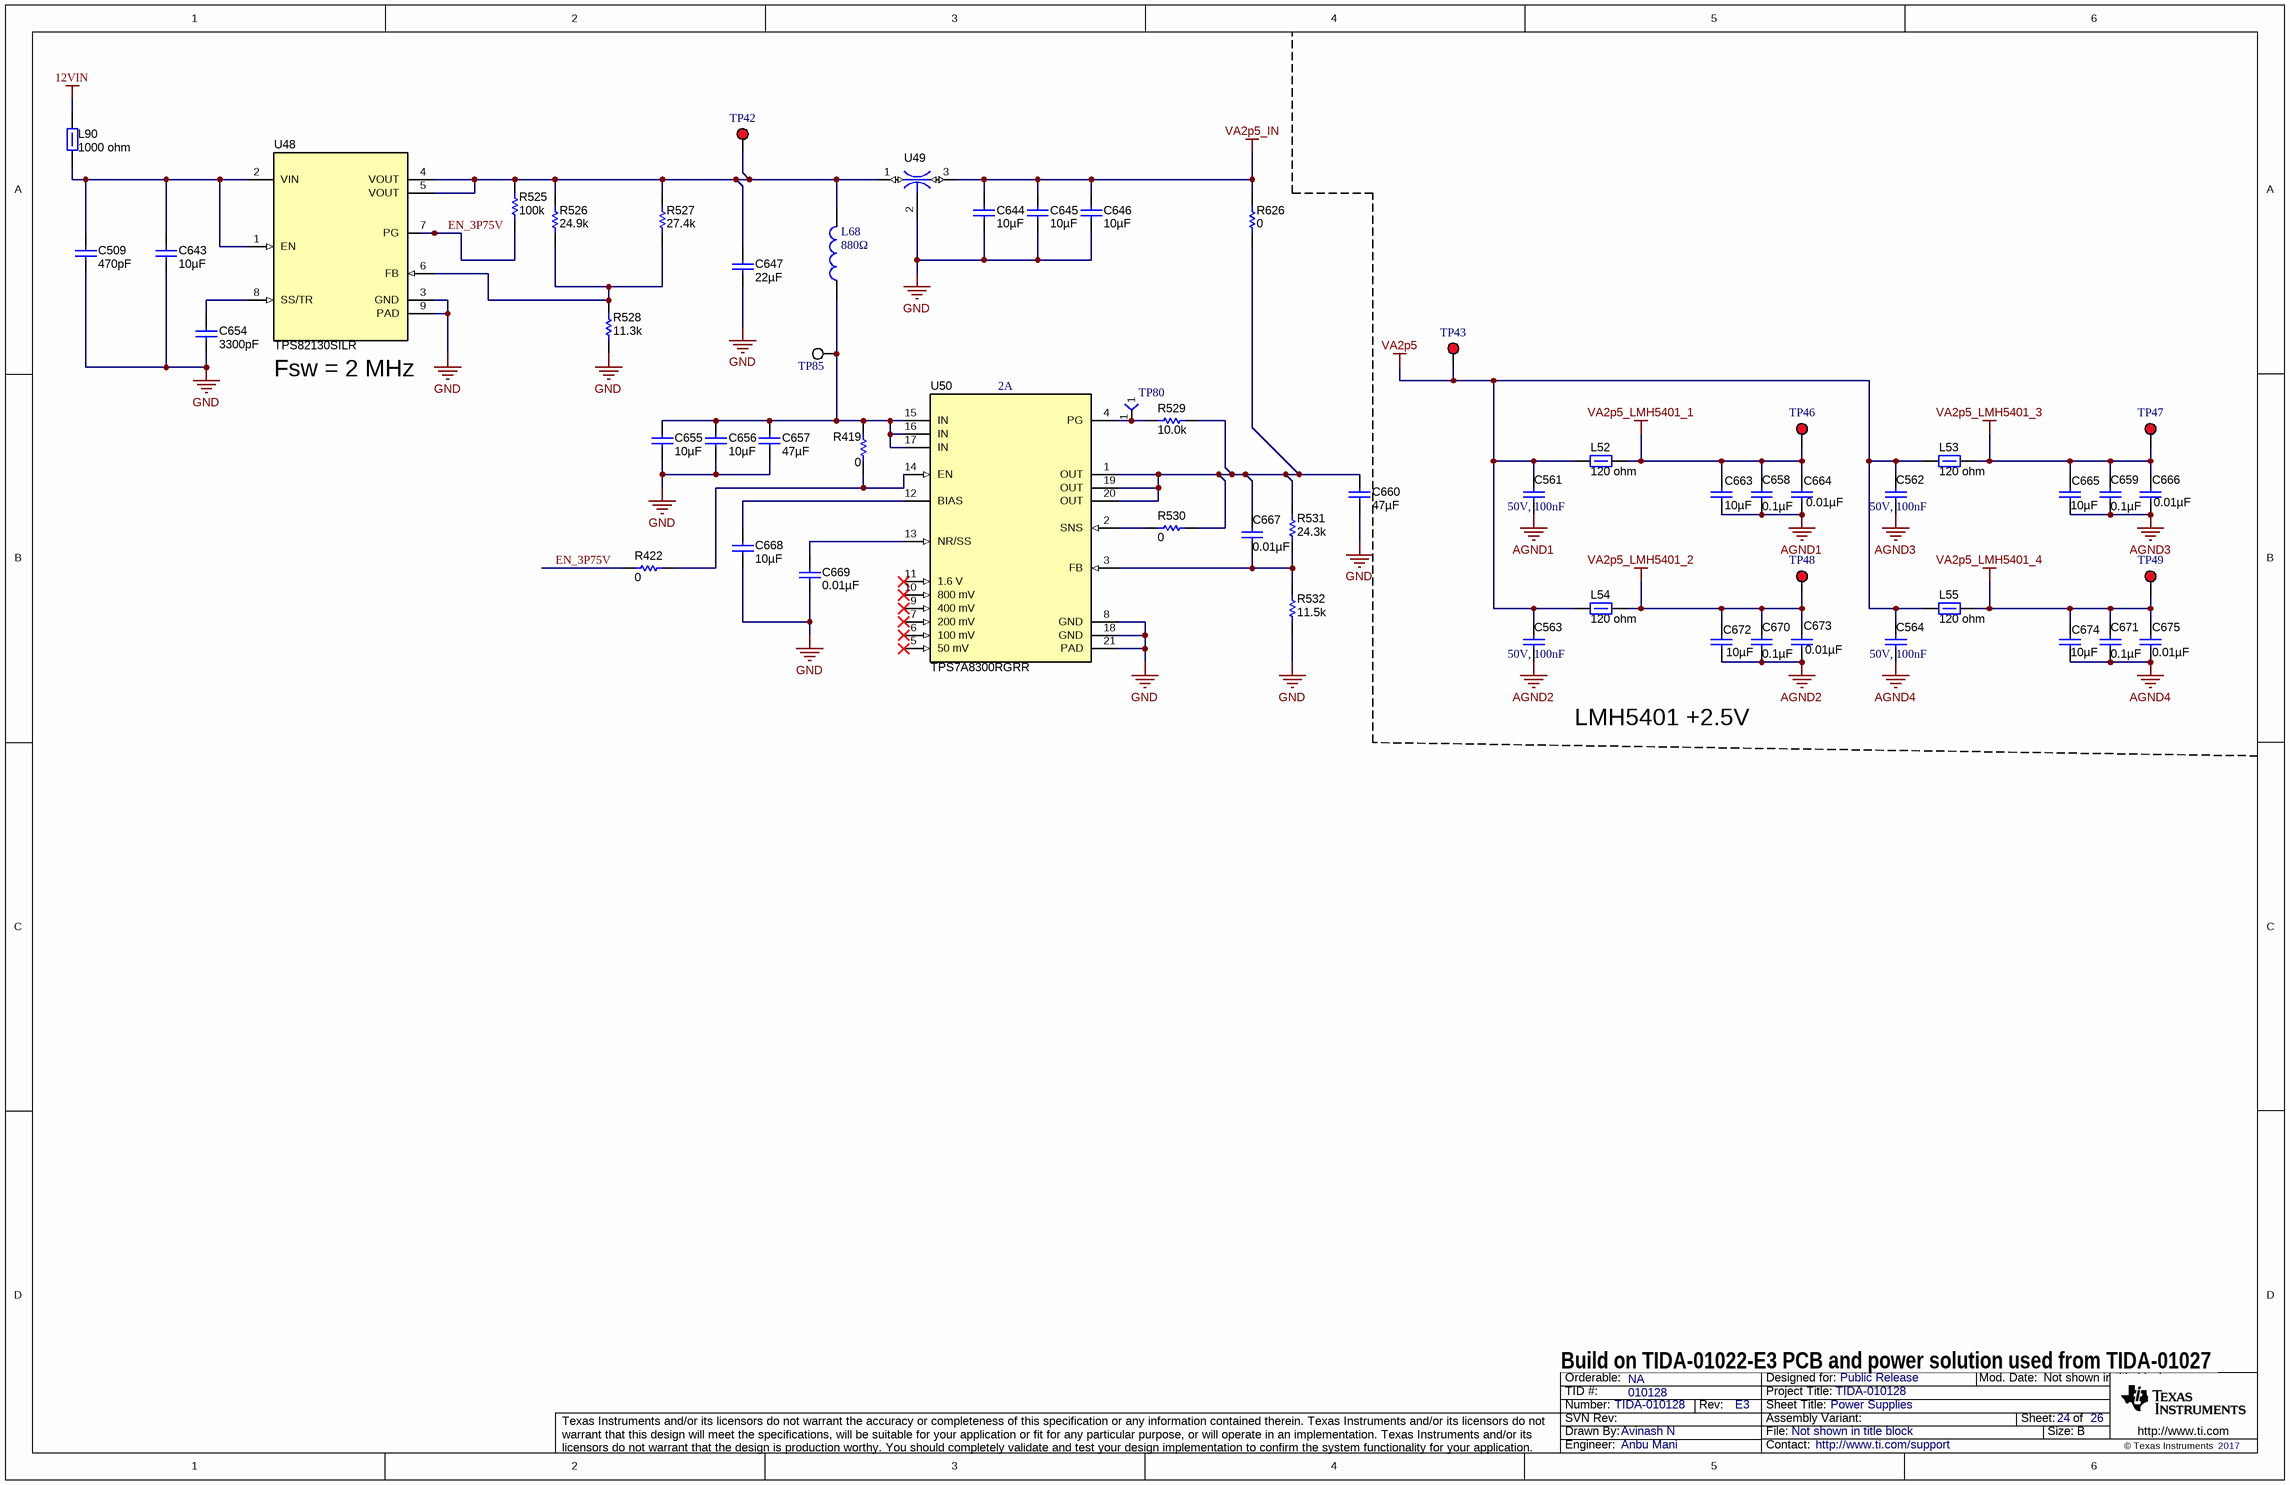
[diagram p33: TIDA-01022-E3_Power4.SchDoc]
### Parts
C509  ValueDisplayed: 470pF  [0402]  (hidden comment: GRM1555C1H471JA01D)
C561  50V, 100nF  [0603_1.6x0.8x0.8mm_Reflow Soldering]
C562  50V, 100nF  [0603_1.6x0.8x0.8mm_Reflow Soldering]
C563  50V, 100nF  [0603_1.6x0.8x0.8mm_Reflow Soldering]
C564  50V, 100nF  [0603_1.6x0.8x0.8mm_Reflow Soldering]
C643  ValueDisplayed: 10µF  [1206_190]  (hidden comment: C3216X7R1E106M160AE)
C644  ValueDisplayed: 10µF  [1206_190]  (hidden comment: C3216X7R1E106M160AE)
C645  ValueDisplayed: 10µF  [1206_190]  (hidden comment: C3216X7R1E106M160AE)
C646  ValueDisplayed: 10µF  [1206_190]  (hidden comment: C3216X7R1E106M160AE)
C647  ValueDisplayed: 22µF  [0805_HV]  (hidden comment: JMK212BJ226MG-T)
C654  ValueDisplayed: 3300pF  [0603]  (hidden comment: GRM1885C1H332JA01D)
C655  ValueDisplayed: 10µF  [0805_HV]  (hidden comment: GRM21BR61C106KE15L)
C656  ValueDisplayed: 10µF  [0805_HV]  (hidden comment: GRM21BR61C106KE15L)
C657  ValueDisplayed: 47µF  [0805_HV]  (hidden comment: GRM219R60G476ME44D)
C658  ValueDisplayed: 0.1µF  [0603]  (hidden comment: CGA3E2X7R1H104K080AA)
C659  ValueDisplayed: 0.1µF  [0603]  (hidden comment: CGA3E2X7R1H104K080AA)
C660  ValueDisplayed: 47µF  [0805_HV]  (hidden comment: GRM219R60G476ME44D)
C663  ValueDisplayed: 10µF  [1206_190]  (hidden comment: C3216X7R1E106M160AE)
C664  ValueDisplayed: 0.01µF  [0603]  (hidden comment: GCM188R71H103KA37D)
C665  ValueDisplayed: 10µF  [1206_190]  (hidden comment: C3216X7R1E106M160AE)
C666  ValueDisplayed: 0.01µF  [0603]  (hidden comment: GCM188R71H103KA37D)
C667  ValueDisplayed: 0.01µF  [0603]  (hidden comment: GRM188R71H103KA01D)
C668  ValueDisplayed: 10µF  [0805_HV]  (hidden comment: GRM21BR61C106KE15L)
C669  ValueDisplayed: 0.01µF  [0603]  (hidden comment: GRM188R71H103KA01D)
C670  ValueDisplayed: 0.1µF  [0603]  (hidden comment: CGA3E2X7R1H104K080AA)
C671  ValueDisplayed: 0.1µF  [0603]  (hidden comment: CGA3E2X7R1H104K080AA)
C672  ValueDisplayed: 10µF  [1206_190]  (hidden comment: C3216X7R1E106M160AE)
C673  ValueDisplayed: 0.01µF  [0603]  (hidden comment: GCM188R71H103KA37D)
C674  ValueDisplayed: 10µF  [1206_190]  (hidden comment: C3216X7R1E106M160AE)
C675  ValueDisplayed: 0.01µF  [0603]  (hidden comment: GCM188R71H103KA37D)
L52  ValueDisplayed: 120 ohm  [0603]  (hidden comment: BLM18SG121TN1D)
L53  ValueDisplayed: 120 ohm  [0603]  (hidden comment: BLM18SG121TN1D)
L54  ValueDisplayed: 120 ohm  [0603]  (hidden comment: BLM18SG121TN1D)
L55  ValueDisplayed: 120 ohm  [0603]  (hidden comment: BLM18SG121TN1D)
L68  880Ω  [WE-CBF_1812_High Current]
L90  ValueDisplayed: 1000 ohm  [1806_HighSpeed]  (hidden comment: BLM41PG102SN1L)
R419  ValueDisplayed: 0  [0603]  (hidden comment: CRCW06030000Z0EA)
R422  ValueDisplayed: 0  [0603]  (hidden comment: CRCW06030000Z0EA)
R525  ValueDisplayed: 100k  [0402]  (hidden comment: CRCW0402100KFKED)
R526  ValueDisplayed: 24.9k  [0603]  (hidden comment: CRCW060324K9FKEA)
R527  ValueDisplayed: 27.4k  [0402]  (hidden comment: CRCW040227K4FKED)
R528  ValueDisplayed: 11.3k  [0402]  (hidden comment: CRCW040211K3FKED)
R529  ValueDisplayed: 10.0k  [0603]  (hidden comment: CRCW060310K0FKEA)
R530  ValueDisplayed: 0  [0603]  (hidden comment: CRCW06030000Z0EA)
R531  ValueDisplayed: 24.3k  [0603]  (hidden comment: CRCW060324K3FKEA)
R532  ValueDisplayed: 11.5k  [0603]  (hidden comment: CRCW060311K5FKEA)
R626  ValueDisplayed: 0  [1206]  (hidden comment: CRCW12060000Z0EA)
TP42  5000  [Keystone5000]  (value not drawn)
TP43  5000  [Keystone5000]  (value not drawn)
TP46  5000  [Keystone5000]  (value not drawn)
TP47  5000  [Keystone5000]  (value not drawn)
TP48  5000  [Keystone5000]  (value not drawn)
TP49  5000  [Keystone5000]  (value not drawn)
TP80  TP-025-SMT  [PROBE_POINT_30PAD]  (value not drawn)
TP85  5015  [Testpoint_Keystone_Miniature]  (value not drawn)
U48  TPS82130SILR  [SIL0008D_SMD]
U49  NFM31PC276B0J3L  [Murata_NFM31P]  (value not drawn)
U50  TPS7A8300RGRR  [RGR0020A]

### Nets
12VIN: L90.2
AGND1: C561.1 C562.1 C563.1 C564.1 C658.2 C659.2 C663.1 C664.2 C665.1 C666.2 C670.2 C671.2 C672.1 C673.2 C674.1 C675.2  [also labelled AGND2, AGND3, AGND4]  [project net AGND]
GND: C509.2 C643.2 C644.1 C645.1 C646.1 C647.2 C654.1 C655.2 C656.2 C657.2 C660.2 C668.2 C669.2 R528.1 R532.1 U48.3(GND) U48.9(PAD) U49.2 U50.8(GND) U50.18(GND) U50.21(PAD)
VA2p5: C561.2 C562.2 C563.2 C564.2 L52.1 L53.1 L54.1 L55.1 TP43.1
VA2p5_IN: C644.2 C645.2 C646.2 R626.2 U49.3
VA2p5_LMH5401_1: C658.1 C663.2 C664.1 L52.2 TP46.1
VA2p5_LMH5401_2: C670.1 C672.2 C673.1 L54.2 TP48.1
VA2p5_LMH5401_3: C659.1 C665.2 C666.1 L53.2 TP47.1
VA2p5_LMH5401_4: C671.1 C674.2 C675.1 L55.2 TP49.1
EN_3P75V: R422.2 R525.1 U48.7(PG)
NetC509_1: C509.1 C643.1 L90.1 U48.1(EN) U48.2(VIN)
NetC647_1: C647.1 L68.2 R525.2 R526.2 R527.2 TP42.1 U48.4(VOUT) U48.5(VOUT) U49.1
NetC654_2: C654.2 U48.8(SS/TR)
NetC655_1: C655.1 C656.1 C657.1 L68.1 R419.1 TP85.1 U50.15(IN) U50.16(IN) U50.17(IN)
NetC660_1: C660.1 C667.1 R529.1 R530.2 R531.2 R626.1 U50.1(OUT) U50.19(OUT) U50.20(OUT)
NetC667_2: C667.2 R531.1 R532.2 U50.3(FB)
NetC668_1: C668.1 U50.12(BIAS)
NetC669_1: C669.1 U50.13(NR/SS)
NetR419_2: R419.2 R422.1 U50.14(EN)
NetR526_1: R526.1 R527.1 R528.2 U48.6(FB)
NetR529_2: R529.2 TP80.1 U50.4(PG)
NetR530_1: R530.1 U50.2(SNS)

Not connected (* = marked no-connect by the designer): U50 5(50_mV)* 6(100_mV)* 7(200_mV)* 9(400_mV)* 10(800_mV)* 11(1.6_V)*

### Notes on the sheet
- (near U48) Fsw = 2 MHz
- (near U50) 2A
- LMH5401 +2.5V
- Build on TIDA-01022-E3 PCB and power solution used from TIDA-01027

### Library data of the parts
C509 = GRM1555C1H471JA01D: as C371 on sheet TIDA-01022-E3_Power3
C561-C564 = 885012206095: as C546 on sheet TIDA-01022-E3_Power3
C643-C646 C663 C665 C672 C674 = C3216X7R1E106M160AE: as C487 on sheet TIDA-01022-E3_Power3
C647 = JMK212BJ226MG-T: as C601 on sheet TIDA-01022-E3_Power3
C654 = GRM1885C1H332JA01D: as C608 on sheet TIDA-01022-E3_Power3
C655 C656 C668 = GRM21BR61C106KE15L: as C613 on sheet TIDA-01022-E3_Power3
C657 C660 = GRM219R60G476ME44D: as C615 on sheet TIDA-01022-E3_Power3
C658 C659 C670 C671 = CGA3E2X7R1H104K080AA: as C485 on sheet TIDA-01022-E3_Power3
C664 C666 C673 C675 = GCM188R71H103KA37D: as C488 on sheet TIDA-01022-E3_Power3
C667 C669 = GRM188R71H103KA01D: as C619 on sheet TIDA-01022-E3_Power3
L52-L55 = BLM18SG121TN1D: Ferrite Bead, 120 ohm @ 100 MHz, 3 A, 0603; Manufacturer: MuRata; Value: 120 ohm; Imax_A: 3; DCR_ohm: 0.025; Value1: 0.025 ohm; Value2: 3A; SizeAreaWB_mm2: 4.68; SizeArea_mm2: 1.28; SizeX_mm: 1.6; SizeY_mm: 0.8; SizeZ_mm: 1; ZTyp@100MHz_Ohm: 120
L68 = WE-CBF, 74279252: as L59 on sheet TIDA-01022-E3_Power3
L90 = BLM41PG102SN1L: as L41-L47 on sheet TIDA-01022-E3_Power3
R419 R422 = CRCW06030000Z0EA: as R417 on sheet TIDA-01022-E3_Power3
R525 = CRCW0402100KFKED: as R513 on sheet TIDA-01022-E3_Power3
R526 = CRCW060324K9FKEA: RES, 24.9 k, 1%, 0.1 W, 0603; Manufacturer: Vishay-Dale; CompType: Resistor; Value: 24.9k; Res_ohm: 24900; Value_Code: 24k9; Tolerance_%: 1; Power_W: 0.1; Value2: 0.1W; VDC_V: 75; TempCo: 100 ppm/C; SizeArea_mm2: 1.28; SizeX_mm: 1.6; SizeY_mm: 0.8; EIA_Code: E96; U/M: EA; AEC Category: Q200
R527 = CRCW040227K4FKED: RES, 27.4 k, 1%, 0.063 W, 0402; Manufacturer: Vishay-Dale; CompType: Resistor; Value: 27.4k; Res_ohm: 27400; Value_Code: 27k4; Tolerance_%: 1; Power_W: 0.063; Value2: 0.063W; VDC_V: 50; TempCo: 100 ppm/C; SizeArea_mm2: 0.5; SizeZ_mm: 0.6; EIA_Code: E96; U/M: EA; AEC Category: Q200; Green_Lifecycle: Not Set; Green_REACh: Incomplete
R528 = CRCW040211K3FKED: as R516 on sheet TIDA-01022-E3_Power3
R529 = CRCW060310K0FKEA: as R517 on sheet TIDA-01022-E3_Power3
R530 = CRCW06030000Z0EA: as R518 on sheet TIDA-01022-E3_Power3
R531 = CRCW060324K3FKEA: RES, 24.3 k, 1%, 0.1 W, 0603; Manufacturer: Vishay-Dale; CompType: Resistor; Value: 24.3k; Res_ohm: 24300; Value_Code: 24k3; Tolerance_%: 1; Power_W: 0.1; Value2: 0.1W; VDC_V: 75; TempCo: 100 ppm/C; SizeArea_mm2: 1.28; SizeX_mm: 1.6; SizeY_mm: 0.8; EIA_Code: E96; U/M: EA; AEC Category: Q200
R532 = CRCW060311K5FKEA: RES, 11.5 k, 1%, 0.1 W, 0603; Manufacturer: Vishay-Dale; CompType: Resistor; Value: 11.5k; Res_ohm: 11500; Value_Code: 11k5; Tolerance_%: 1; Power_W: 0.1; Value2: 0.1W; VDC_V: 75; TempCo: 100 ppm/C; SizeArea_mm2: 1.28; SizeX_mm: 1.6; SizeY_mm: 0.8; EIA_Code: E96; U/M: EA; AEC Category: Q200
R626 = CRCW12060000Z0EA: as R622 on sheet TIDA-01022-E3_Power3
TP42 TP43 TP46-TP49 = 5000: as TP24 on sheet TIDA-01022-E3_Power3
TP80 = TP-025-SMT: as TP79 on sheet TIDA-01022-E3_Power3
TP85 = 5015: as TP84 on sheet TIDA-01022-E3_Power3
U48 = TPS82130SILR: as U45 on sheet TIDA-01022-E3_Power3
U49 = NFM31PC276B0J3L: as U46 on sheet TIDA-01022-E3_Power3
U50 = TPS7A8300RGRR: 2A, Low-Dropout Voltage Regulator for High Speed Communication Systems, RGR0020A (VQFN-20); Alternate PartNumber: TPS7A8300RGRT; Manufacturer: Texas Instruments; SymbolCreator: a0411947; SizeArea_mm2: 12.25; SizeAreaWB_mm2: 20.25; SizeX_mm: 3.5; SizeZ_mm: 1; CompType: IC; U/M: EA

## Sheet TIDA-01022-E3_Power5.SchDoc: Power Supplies
size 431 x 279 mm; Date: Not shown in title block; ApprovedBy: Not shown in title block; CheckedBy: Not shown in title block; Author: Not shown in title block; CompanyName: Not shown in title block; DrawnBy: Avinash N; Engineer: Not shown in title block; Organization: Not shown in title block; Address1: Not shown in title block; Address2: Not shown in title block; Address3: Not shown in title block; Address4: Not shown in title block; DocumentNumber: 1; Revision: Use project parameter SCH_Rev; SheetNumber: 25; SheetTotal: 26; PageSetup: Record=PageOptions¦CenterHorizontal=True¦CenterVertical=True¦PrintScale=1.00¦XCorrection=1.00¦YCorrection=1.00¦PrintKind=0¦BorderSize=5000000¦LeftOffset=0¦BottomOffset=0¦Orientation=2¦PaperLength=1000¦PaperWidth=1000¦Scale=100¦PaperSource=15¦PrintQuality=600¦MediaType=1¦DitherType=10¦PaperKind=Letter¦PrintScaleMode=1

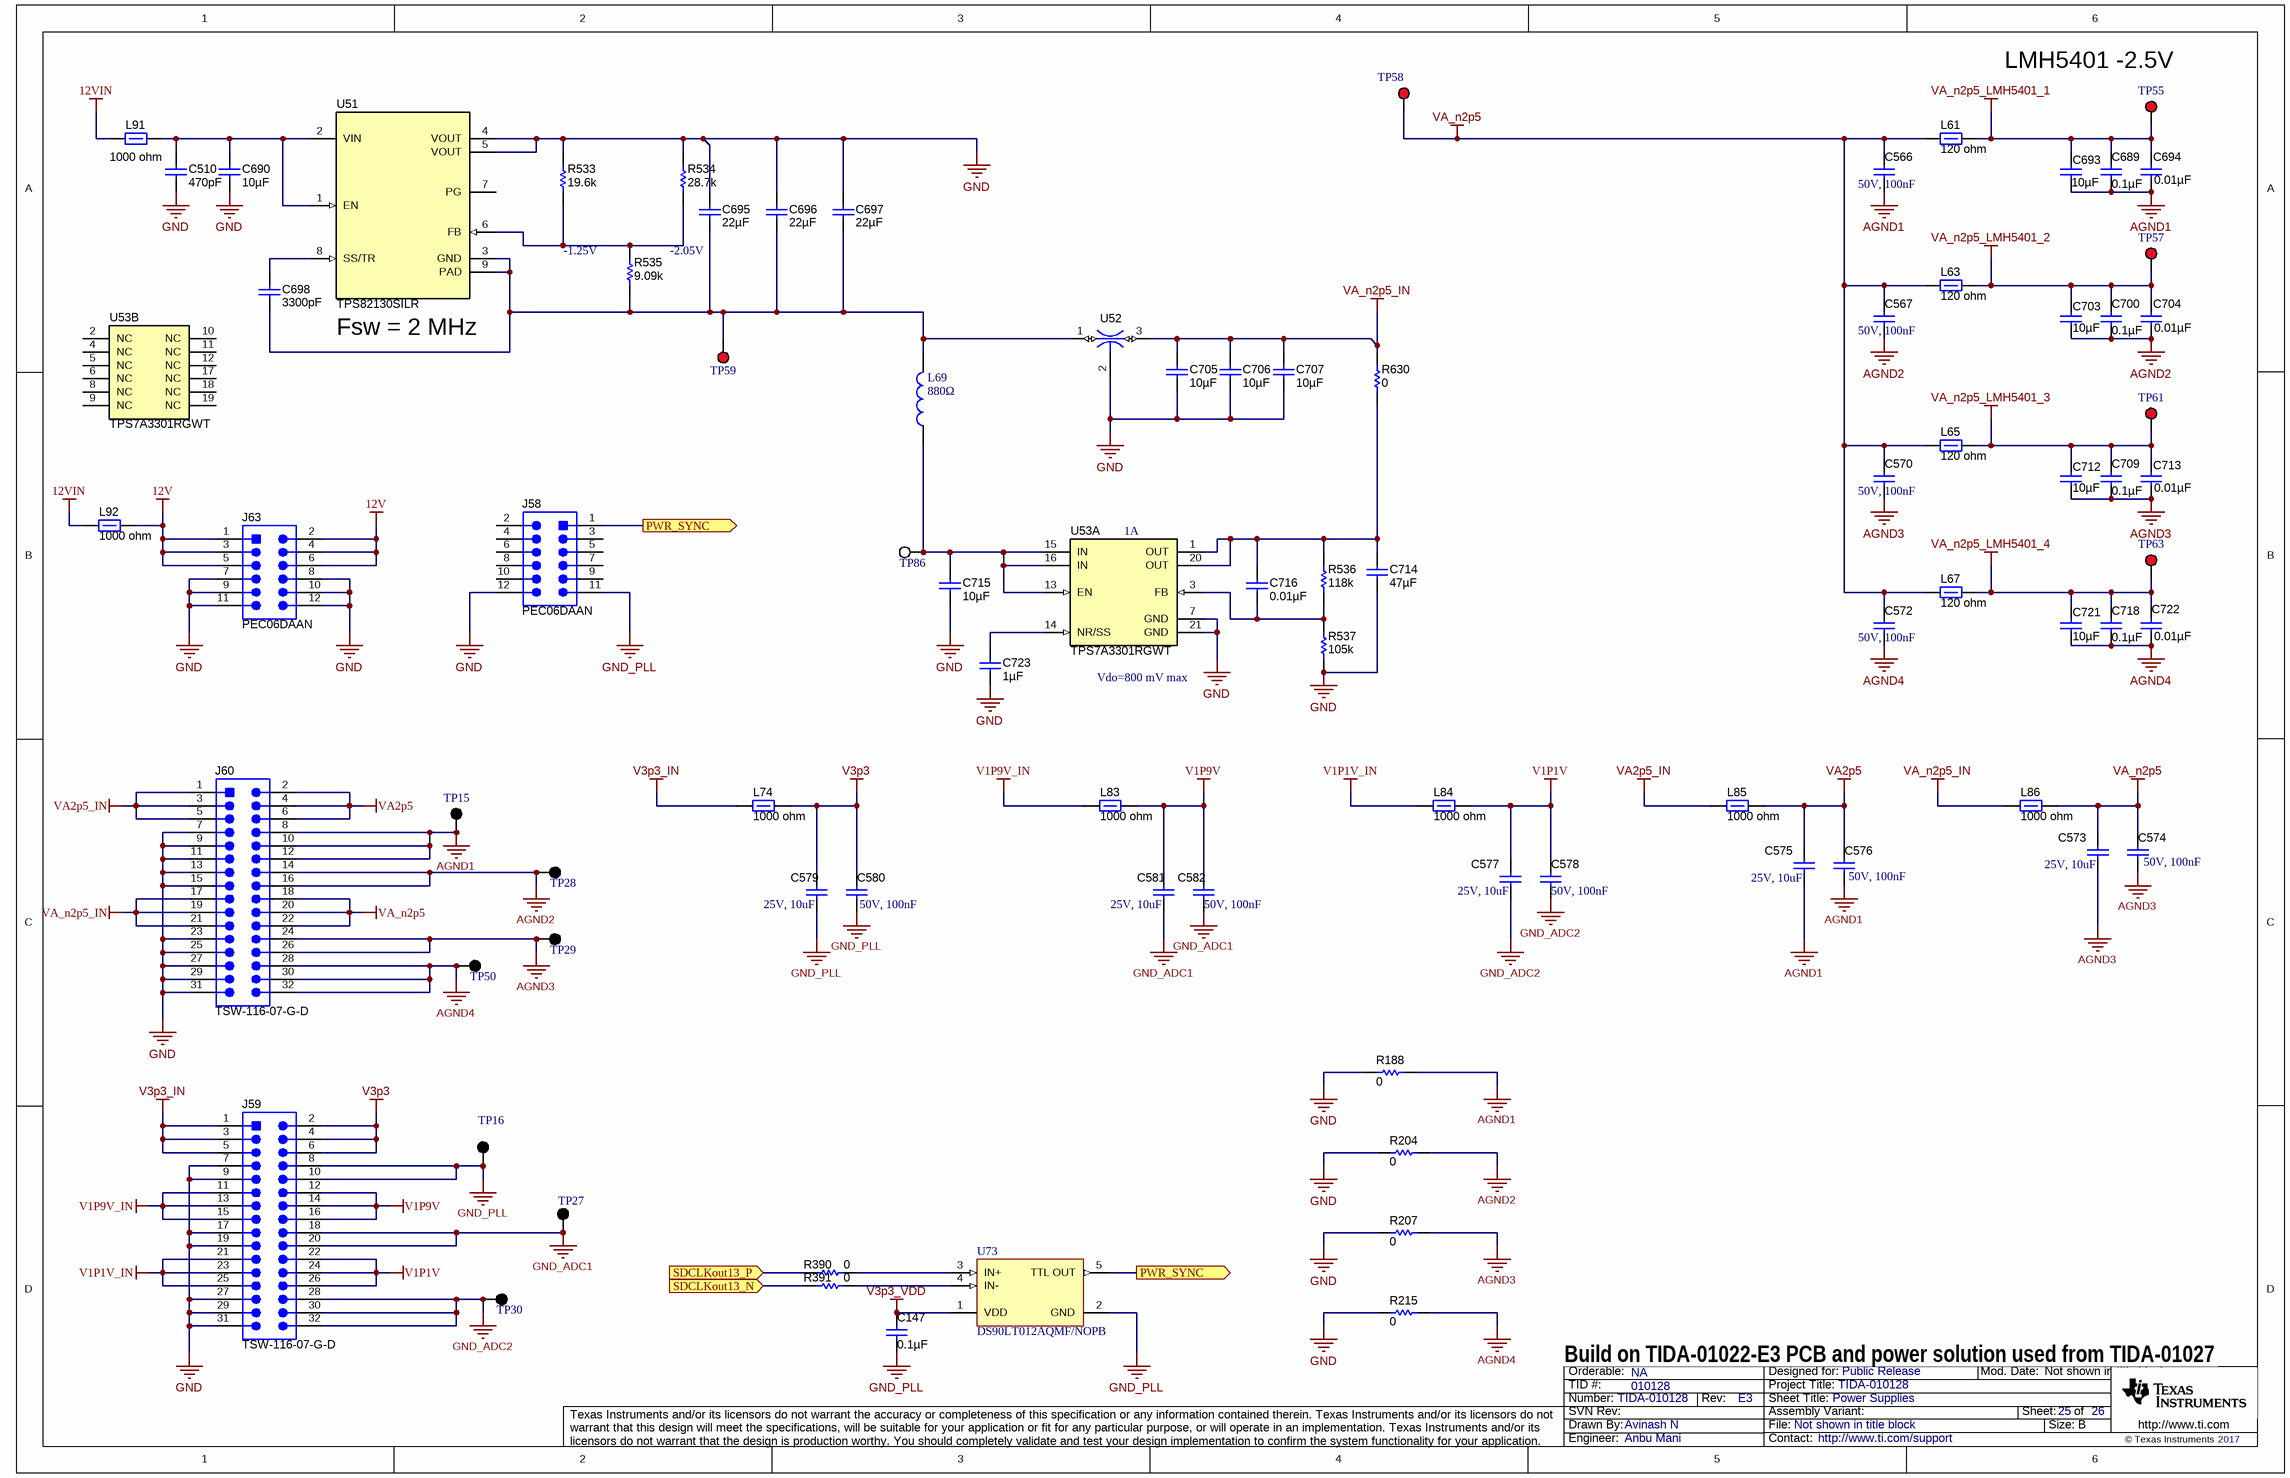
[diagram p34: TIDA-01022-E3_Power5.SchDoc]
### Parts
C147  ValueDisplayed: 0.1µF  [0603]  (hidden comment: CGA3E2X7R1H104K080AA)
C510  ValueDisplayed: 470pF  [0402]  (hidden comment: GRM1555C1H471JA01D)
C566  50V, 100nF  [0603_1.6x0.8x0.8mm_Reflow Soldering]
C567  50V, 100nF  [0603_1.6x0.8x0.8mm_Reflow Soldering]
C570  50V, 100nF  [0603_1.6x0.8x0.8mm_Reflow Soldering]
C572  50V, 100nF  [0603_1.6x0.8x0.8mm_Reflow Soldering]
C573  25V, 10uF  [1206_3.2x1.6x1.6mm]
C574  50V, 100nF  [0603_1.6x0.8x0.8mm_Reflow Soldering]
C575  25V, 10uF  [1206_3.2x1.6x1.6mm]
C576  50V, 100nF  [0603_1.6x0.8x0.8mm_Reflow Soldering]
C577  25V, 10uF  [1206_3.2x1.6x1.6mm]
C578  50V, 100nF  [0603_1.6x0.8x0.8mm_Reflow Soldering]
C579  25V, 10uF  [1206_3.2x1.6x1.6mm]
C580  50V, 100nF  [0603_1.6x0.8x0.8mm_Reflow Soldering]
C581  25V, 10uF  [1206_3.2x1.6x1.6mm]
C582  50V, 100nF  [0603_1.6x0.8x0.8mm_Reflow Soldering]
C689  ValueDisplayed: 0.1µF  [0603]  (hidden comment: CGA3E2X7R1H104K080AA)
C690  ValueDisplayed: 10µF  [1206_190]  (hidden comment: C3216X7R1E106M160AE)
C693  ValueDisplayed: 10µF  [1206_190]  (hidden comment: C3216X7R1E106M160AE)
C694  ValueDisplayed: 0.01µF  [0603]  (hidden comment: GCM188R71H103KA37D)
C695  ValueDisplayed: 22µF  [0805_HV]  (hidden comment: JMK212BJ226MG-T)
C696  ValueDisplayed: 22µF  [0805_HV]  (hidden comment: JMK212BJ226MG-T)
C697  ValueDisplayed: 22µF  [0805_HV]  (hidden comment: JMK212BJ226MG-T)
C698  ValueDisplayed: 3300pF  [0603]  (hidden comment: GRM1885C1H332JA01D)
C700  ValueDisplayed: 0.1µF  [0603]  (hidden comment: CGA3E2X7R1H104K080AA)
C703  ValueDisplayed: 10µF  [1206_190]  (hidden comment: C3216X7R1E106M160AE)
C704  ValueDisplayed: 0.01µF  [0603]  (hidden comment: GCM188R71H103KA37D)
C705  ValueDisplayed: 10µF  [1206_190]  (hidden comment: C3216X7R1E106M160AE)
C706  ValueDisplayed: 10µF  [1206_190]  (hidden comment: C3216X7R1E106M160AE)
C707  ValueDisplayed: 10µF  [1206_190]  (hidden comment: C3216X7R1E106M160AE)
C709  ValueDisplayed: 0.1µF  [0603]  (hidden comment: CGA3E2X7R1H104K080AA)
C712  ValueDisplayed: 10µF  [1206_190]  (hidden comment: C3216X7R1E106M160AE)
C713  ValueDisplayed: 0.01µF  [0603]  (hidden comment: GCM188R71H103KA37D)
C714  ValueDisplayed: 47µF  [0805_HV]  (hidden comment: GRM219R60G476ME44D)
C715  ValueDisplayed: 10µF  [1206_190]  (hidden comment: C3216X7R1E106M160AE)
C716  ValueDisplayed: 0.01µF  [0603]  (hidden comment: GRM188R71H103KA01D)
C718  ValueDisplayed: 0.1µF  [0603]  (hidden comment: CGA3E2X7R1H104K080AA)
C721  ValueDisplayed: 10µF  [1206_190]  (hidden comment: C3216X7R1E106M160AE)
C722  ValueDisplayed: 0.01µF  [0603]  (hidden comment: GCM188R71H103KA37D)
C723  ValueDisplayed: 1µF  [0805_HV]  (hidden comment: 08053D105KAT2A)
J58  PEC06DAAN  [CONN_PEC06DAAN]
J59  TSW-116-07-G-D  [TSW-116-07-G-D]
J60  TSW-116-07-G-D  [TSW-116-07-G-D]
J63  PEC06DAAN  [CONN_PEC06DAAN]
L61  ValueDisplayed: 120 ohm  [0603]  (hidden comment: BLM18SG121TN1D)
L63  ValueDisplayed: 120 ohm  [0603]  (hidden comment: BLM18SG121TN1D)
L65  ValueDisplayed: 120 ohm  [0603]  (hidden comment: BLM18SG121TN1D)
L67  ValueDisplayed: 120 ohm  [0603]  (hidden comment: BLM18SG121TN1D)
L69  880Ω  [WE-CBF_1812_High Current]
L74  ValueDisplayed: 1000 ohm  [1806_HighSpeed]  (hidden comment: BLM41PG102SN1L)
L83  ValueDisplayed: 1000 ohm  [1806_HighSpeed]  (hidden comment: BLM41PG102SN1L)
L84  ValueDisplayed: 1000 ohm  [1806_HighSpeed]  (hidden comment: BLM41PG102SN1L)
L85  ValueDisplayed: 1000 ohm  [1806_HighSpeed]  (hidden comment: BLM41PG102SN1L)
L86  ValueDisplayed: 1000 ohm  [1806_HighSpeed]  (hidden comment: BLM41PG102SN1L)
L91  ValueDisplayed: 1000 ohm  [1806_HighSpeed]  (hidden comment: BLM41PG102SN1L)
L92  ValueDisplayed: 1000 ohm  [1806_HighSpeed]  (hidden comment: BLM41PG102SN1L)
R188  ValueDisplayed: 0  [1206]  (hidden comment: CRCW12060000Z0EA)
R204  ValueDisplayed: 0  [1206]  (hidden comment: CRCW12060000Z0EA)
R207  ValueDisplayed: 0  [1206]  (hidden comment: CRCW12060000Z0EA)
R215  ValueDisplayed: 0  [1206]  (hidden comment: CRCW12060000Z0EA)
R390  ValueDisplayed: 0  [0402]  (hidden comment: CRCW04020000Z0ED)
R391  ValueDisplayed: 0  [0402]  (hidden comment: CRCW04020000Z0ED)
R533  ValueDisplayed: 19.6k  [0402]  (hidden comment: CRCW040219K6FKED)
R534  ValueDisplayed: 28.7k  [0402]  (hidden comment: CRCW040228K7FKED)
R535  ValueDisplayed: 9.09k  [0402]  (hidden comment: CRCW04029K09FKED)
R536  ValueDisplayed: 118k  [0402]  (hidden comment: CRCW0402118KFKED)
R537  ValueDisplayed: 105k  [0402]  (hidden comment: CRCW0402105KFKED)
R630  ValueDisplayed: 0  [1206]  (hidden comment: CRCW12060000Z0EA)
TP15  5001  [Keystone5001]  (value not drawn)
TP16  5001  [Keystone5001]  (value not drawn)
TP27  5001  [Keystone5001]  (value not drawn)
TP28  5001  [Keystone5001]  (value not drawn)
TP29  5001  [Keystone5001]  (value not drawn)
TP30  5001  [Keystone5001]  (value not drawn)
TP50  5001  [Keystone5001]  (value not drawn)
TP55  5000  [Keystone5000]  (value not drawn)
TP57  5000  [Keystone5000]  (value not drawn)
TP58  5000  [Keystone5000]  (value not drawn)
TP59  5000  [Keystone5000]  (value not drawn)
TP61  5000  [Keystone5000]  (value not drawn)
TP63  5000  [Keystone5000]  (value not drawn)
TP86  5015  [Testpoint_Keystone_Miniature]  (value not drawn)
U51  TPS82130SILR  [SIL0008D_SMD]
U52  NFM31PC276B0J3L  [Murata_NFM31P]  (value not drawn)
U53  TPS7A3301RGWT  [RGW0020A]  (parts A,B of 2)
U73  DS90LT012AQMF/NOPB  [MF05A_N]

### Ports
PWR_SYNC (out), SDCLKout13_N (in), SDCLKout13_P (in)

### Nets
12V: J63.1 J63.2 J63.3 J63.4 J63.5 J63.6 L92.1
12VIN: L91.1 L92.2
AGND1: C566.1 C567.1 C570.1 C572.1 C573.1 C574.1 C575.1 C576.1 C689.2 C693.1 C694.2 C700.2 C703.1 C704.2 C709.2 C712.1 C713.2 C718.2 C721.1 C722.2 J60.8 J60.10 J60.12 J60.14 J60.16 J60.24 J60.26 J60.28 J60.30 J60.32 R188.2 R204.2 R207.2 R215.2 TP15.1 TP28.1 TP29.1 TP50.1  [also labelled AGND2, AGND3, AGND4]  [project net AGND]
GND: C510.2 C690.2 C695.1 C696.1 C697.1 C705.1 C706.1 C707.1 C714.2 C715.1 C723.2 J58.12 J59.7 J59.9 J59.17 J59.19 J59.27 J59.29 J59.31 J60.7 J60.9 J60.11 J60.13 J60.15 J60.23 J60.25 J60.27 J60.29 J60.31 J63.7 J63.8 J63.9 J63.10 J63.11 J63.12 R188.1 R204.1 R207.1 R215.1 R533.2 R534.2 R537.1 U51.4(VOUT) U51.5(VOUT) U52.2 U53.7(GND) U53.21(GND)
GND_ADC1: C147.2 C577.1 C578.1 C579.1 C580.1 C581.1 C582.1 J58.11 J59.8 J59.10 J59.18 J59.20 J59.28 J59.30 J59.32 TP16.1 TP27.1 TP30.1 U73.2(GND)  [also labelled GND_ADC2, GND_PLL]  [project net DGND]
V1P1V: C577.2 C578.2 J59.22 J59.24 J59.26 L84.1
V1P1V_IN: J59.21 J59.23 J59.25 L84.2
V1P9V: C581.2 C582.2 J59.12 J59.14 J59.16 L83.1
V1P9V_IN: J59.11 J59.13 J59.15 L83.2
V3p3: C579.2 C580.2 J59.2 J59.4 J59.6 L74.1
V3p3_IN: J59.1 J59.3 J59.5 L74.2
V3p3_VDD: C147.1 U73.1(VDD)
VA2p5: C575.2 C576.2 J60.2 J60.4 J60.6 L85.1
VA2p5_IN: J60.1 J60.3 J60.5 L85.2
VA_n2p5: C566.2 C567.2 C570.2 C572.2 C573.2 C574.2 J60.18 J60.20 J60.22 L61.1 L63.1 L65.1 L67.1 L86.1 TP58.1
VA_n2p5_IN: C705.2 C706.2 C707.2 J60.17 J60.19 J60.21 L86.2 R630.2 U52.3
VA_n2p5_LMH5401_1: C689.1 C693.2 C694.1 L61.2 TP55.1
VA_n2p5_LMH5401_2: C700.1 C703.2 C704.1 L63.2 TP57.1
VA_n2p5_LMH5401_3: C709.1 C712.2 C713.1 L65.2 TP61.1
VA_n2p5_LMH5401_4: C718.1 C721.2 C722.1 L67.2 TP63.1
PWR_SYNC: J58.1 U73.5(TTL_OUT) ; port PWR_SYNC
SDCLKout13_N: R391.1 ; port SDCLKout13_N
SDCLKout13_P: R390.1 ; port SDCLKout13_P
NetC510_1: C510.1 C690.1 L91.2 U51.1(EN) U51.2(VIN)
NetC695_2: C695.2 C696.2 C697.2 C698.1 L69.2 R535.1 TP59.1 U51.3(GND) U51.9(PAD) U52.1
NetC698_2: C698.2 U51.8(SS/TR)
NetC714_1: C714.1 C716.1 R536.2 R630.1 U53.1(OUT) U53.20(OUT)
NetC715_2: C715.2 L69.1 TP86.1 U53.13(EN) U53.15(IN) U53.16(IN)
NetC716_2: C716.2 R536.1 R537.2 U53.3(FB)
NetC723_1: C723.1 U53.14(NR/SS)
NetR390_2: R390.2 U73.3(IN+)
NetR391_2: R391.2 U73.4(IN-)
NetR533_1: R533.1 R534.1 R535.2 U51.6(FB)

Not connected (* = marked no-connect by the designer): J58 2 3 4 5 6 7 8 9 10; U51 7(PG); U53 2(NC) 4(NC) 5(NC) 6(NC) 8(NC) 9(NC) 10(NC) 11(NC) 12(NC) 17(NC) 18(NC) 19(NC)

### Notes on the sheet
- (near TP55) LMH5401 -2.5V
- (near R535) -1.25V
- -2.05V
- (near U51) Fsw = 2 MHz
- (near U53) 1A
- (near U53) Vdo=800 mV max
- Build on TIDA-01022-E3 PCB and power solution used from TIDA-01027

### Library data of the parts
C147 C689 C700 C709 C718 = CGA3E2X7R1H104K080AA: as C485 on sheet TIDA-01022-E3_Power3
C510 = GRM1555C1H471JA01D: as C371 on sheet TIDA-01022-E3_Power3
C566 C567 C570 C572 C574 C576 C578 C580 C582 = 885012206095: as C546 on sheet TIDA-01022-E3_Power3
C573 C575 C577 C579 C581 = 885012208069: WCAP-CSGP Ceramic Capacitors, 1206, X7R, 25V, 10uF; Rated Voltage: 25V DC
C690 C693 C703 C705-C707 C712 C715 C721 = C3216X7R1E106M160AE: as C487 on sheet TIDA-01022-E3_Power3
C694 C704 C713 C722 = GCM188R71H103KA37D: as C488 on sheet TIDA-01022-E3_Power3
C695-C697 = JMK212BJ226MG-T: as C601 on sheet TIDA-01022-E3_Power3
C698 = GRM1885C1H332JA01D: as C608 on sheet TIDA-01022-E3_Power3
C714 = GRM219R60G476ME44D: as C615 on sheet TIDA-01022-E3_Power3
C716 = GRM188R71H103KA01D: as C619 on sheet TIDA-01022-E3_Power3
C723 = 08053D105KAT2A: CAP, CERM, 1 µF, 25 V, +/- 10%, X5R, 0805; Manufacturer: AVX; Polarized: N; CompType: Capacitor; Value: 1uF; U/M: EA; Cap_F: 0.000001; Tolerance_%: 10; ESR_ohm: 0.012; Value1: 0.012 ohm; VDC_V: 25; Value2: 25V; TaMin_C: -55; TaMax_C: 85; Cap_Case: 0805; SizeArea_mm2: 2.5; SizeAreaWB_mm2: 6.75; SizeX_mm: 2; SizeY_mm: 1.25; SizeZ_mm: 1.45; AEC Category: Q200
J58 J63 = PEC06DAAN: Header, 100mil, 6x2, Tin, TH; Manufacturer: Sullins Connector Solutions; SymbolCreator: a0412235; Pitch_mm: 2.54; Gender: Male; Shrouded: N; Row_Count: 2; Current_A: 3; Voltage_V: 1800; Cert_UL: Y; Green_Lifecycle: Not Set; Green_REACh: Incomplete
J59 J60 = TSW-116-07-G-D: Header, 100mil, 16x2, Gold, TH; Manufacturer: Samtec; SymbolCreator: a0412235; Pitch_mm: 2.54; Gender: Male; Shrouded: N; Row_Count: 2; Current_A: 6.3; Voltage_V: 550; Cert_CSA: Y; Green_Lifecycle: Active; Green_REACh: Passed
L61 L63 L65 L67 = BLM18SG121TN1D: as L52-L55 on sheet TIDA-01022-E3_Power4
L69 = WE-CBF, 74279252: as L59 on sheet TIDA-01022-E3_Power3
L74 L83-L86 L91 L92 = BLM41PG102SN1L: as L41-L47 on sheet TIDA-01022-E3_Power3
R188 R204 R207 R215 = CRCW12060000Z0EA: as R186 on sheet TIDA-01022-E3_Power3
R390 R391 = CRCW04020000Z0ED: as R519-R524 on sheet TIDA-01022-E3_Power3
R533 = CRCW040219K6FKED: RES, 19.6 k, 1%, 0.063 W, 0402; Manufacturer: Vishay-Dale; CompType: Resistor; Value: 19.6k; Res_ohm: 19600; Value_Code: 19k6; Tolerance_%: 1; Power_W: 0.063; Value2: 0.063W; VDC_V: 50; TempCo: 100 ppm/C; SizeArea_mm2: 0.5; SizeZ_mm: 0.6; EIA_Code: E96; U/M: EA; AEC Category: Q200
R534 = CRCW040228K7FKED: RES, 28.7 k, 1%, 0.063 W, 0402; Manufacturer: Vishay-Dale; CompType: Resistor; Value: 28.7k; Res_ohm: 28700; Value_Code: 28k7; Tolerance_%: 1; Power_W: 0.063; Value2: 0.063W; VDC_V: 50; TempCo: 100 ppm/C; SizeArea_mm2: 0.5; SizeZ_mm: 0.6; EIA_Code: E96; U/M: EA; AEC Category: Q200
R535 = CRCW04029K09FKED: RES, 9.09 k, 1%, 0.063 W, 0402; Manufacturer: Vishay-Dale; CompType: Resistor; Value: 9.09k; Res_ohm: 9090; Value_Code: 9k09; Tolerance_%: 1; Power_W: 0.063; Value2: 0.063W; VDC_V: 50; TempCo: 100 ppm/C; SizeArea_mm2: 0.5; SizeZ_mm: 0.6; EIA_Code: E96; U/M: EA; AEC Category: Q200
R536 = CRCW0402118KFKED: RES, 118 k, 1%, 0.063 W, 0402; Manufacturer: Vishay-Dale; CompType: Resistor; Value: 118k; Res_ohm: 118000; Tolerance_%: 1; Power_W: 0.063; Value2: 0.063W; VDC_V: 50; TempCo: 100 ppm/C; SizeArea_mm2: 0.5; SizeZ_mm: 0.6; EIA_Code: E96; U/M: EA; AEC Category: Q200
R537 = CRCW0402105KFKED: RES, 105 k, 1%, 0.063 W, 0402; Manufacturer: Vishay-Dale; CompType: Resistor; Value: 105k; Res_ohm: 105000; Tolerance_%: 1; Power_W: 0.063; Value2: 0.063W; VDC_V: 50; TempCo: 100 ppm/C; SizeArea_mm2: 0.5; SizeZ_mm: 0.6; EIA_Code: E96; U/M: EA; AEC Category: Q200
R630 = CRCW12060000Z0EA: as R622 on sheet TIDA-01022-E3_Power3
TP15 TP16 TP27-TP30 TP50 = 5001: Test Point, Miniature, Black, TH; Manufacturer: Keystone; CompType: Test Point Loop; ContactFinish: Silver; Green_Lifecycle: Active; Green_REACh: Passed
TP55 TP57-TP59 TP61 TP63 = 5000: as TP24 on sheet TIDA-01022-E3_Power3
TP86 = 5015: as TP84 on sheet TIDA-01022-E3_Power3
U51 = TPS82130SILR: as U45 on sheet TIDA-01022-E3_Power3
U52 = NFM31PC276B0J3L: as U46 on sheet TIDA-01022-E3_Power3
U53 = TPS7A3301RGWT: Single Output High PSRR LDO, 1 A, Adjustable -1.18 to -33 V Output, -3 to -36 V Input, with Ultra-Low Noise, 20-pin VQFN (RGW), -40 to 125 degC, Green (RoHS & no Sb/Br); Manufacturer: Texas Instruments; Alternate PartNumber: Equivalent; Accuracy(%): 1.5; Iout(Max)(A): 1; Iq(Typ)(mA): 0.21; SubFamily: Single Channel LDO; Vdo(Typ)(mV): 290
U73 = DS90LT012AQMF/NOPB: Automotive LVDS Differential Line Receiver, 5-pin SOT-23, Pb-Free; Manufacturer: Texas Instruments; PackageTopMarking: N03Q*XTT; PowerWise: N; CompType: Interface IC

## Sheet TIDA-01022-E3_Hardware.SchDoc: Hardware
size 431 x 279 mm; Date: Not shown in title block; ApprovedBy: Not shown in title block; CheckedBy: Not shown in title block; Author: Not shown in title block; CompanyName: Not shown in title block; DrawnBy: Avinash N; Engineer: Not shown in title block; Organization: Not shown in title block; Address1: Not shown in title block; Address2: Not shown in title block; Address3: Not shown in title block; Address4: Not shown in title block; DocumentNumber: 1; Revision: Use project parameter SCH_Rev; SheetNumber: 26; SheetTotal: 26; PageSetup: Record=PageOptions¦CenterHorizontal=True¦CenterVertical=True¦PrintScale=1.00¦XCorrection=1.00¦YCorrection=1.00¦PrintKind=0¦BorderSize=5000000¦LeftOffset=0¦BottomOffset=0¦Orientation=2¦PaperLength=1000¦PaperWidth=1000¦Scale=100¦PaperSource=15¦PrintQuality=600¦MediaType=1¦DitherType=10¦PaperKind=Letter¦PrintScaleMode=1

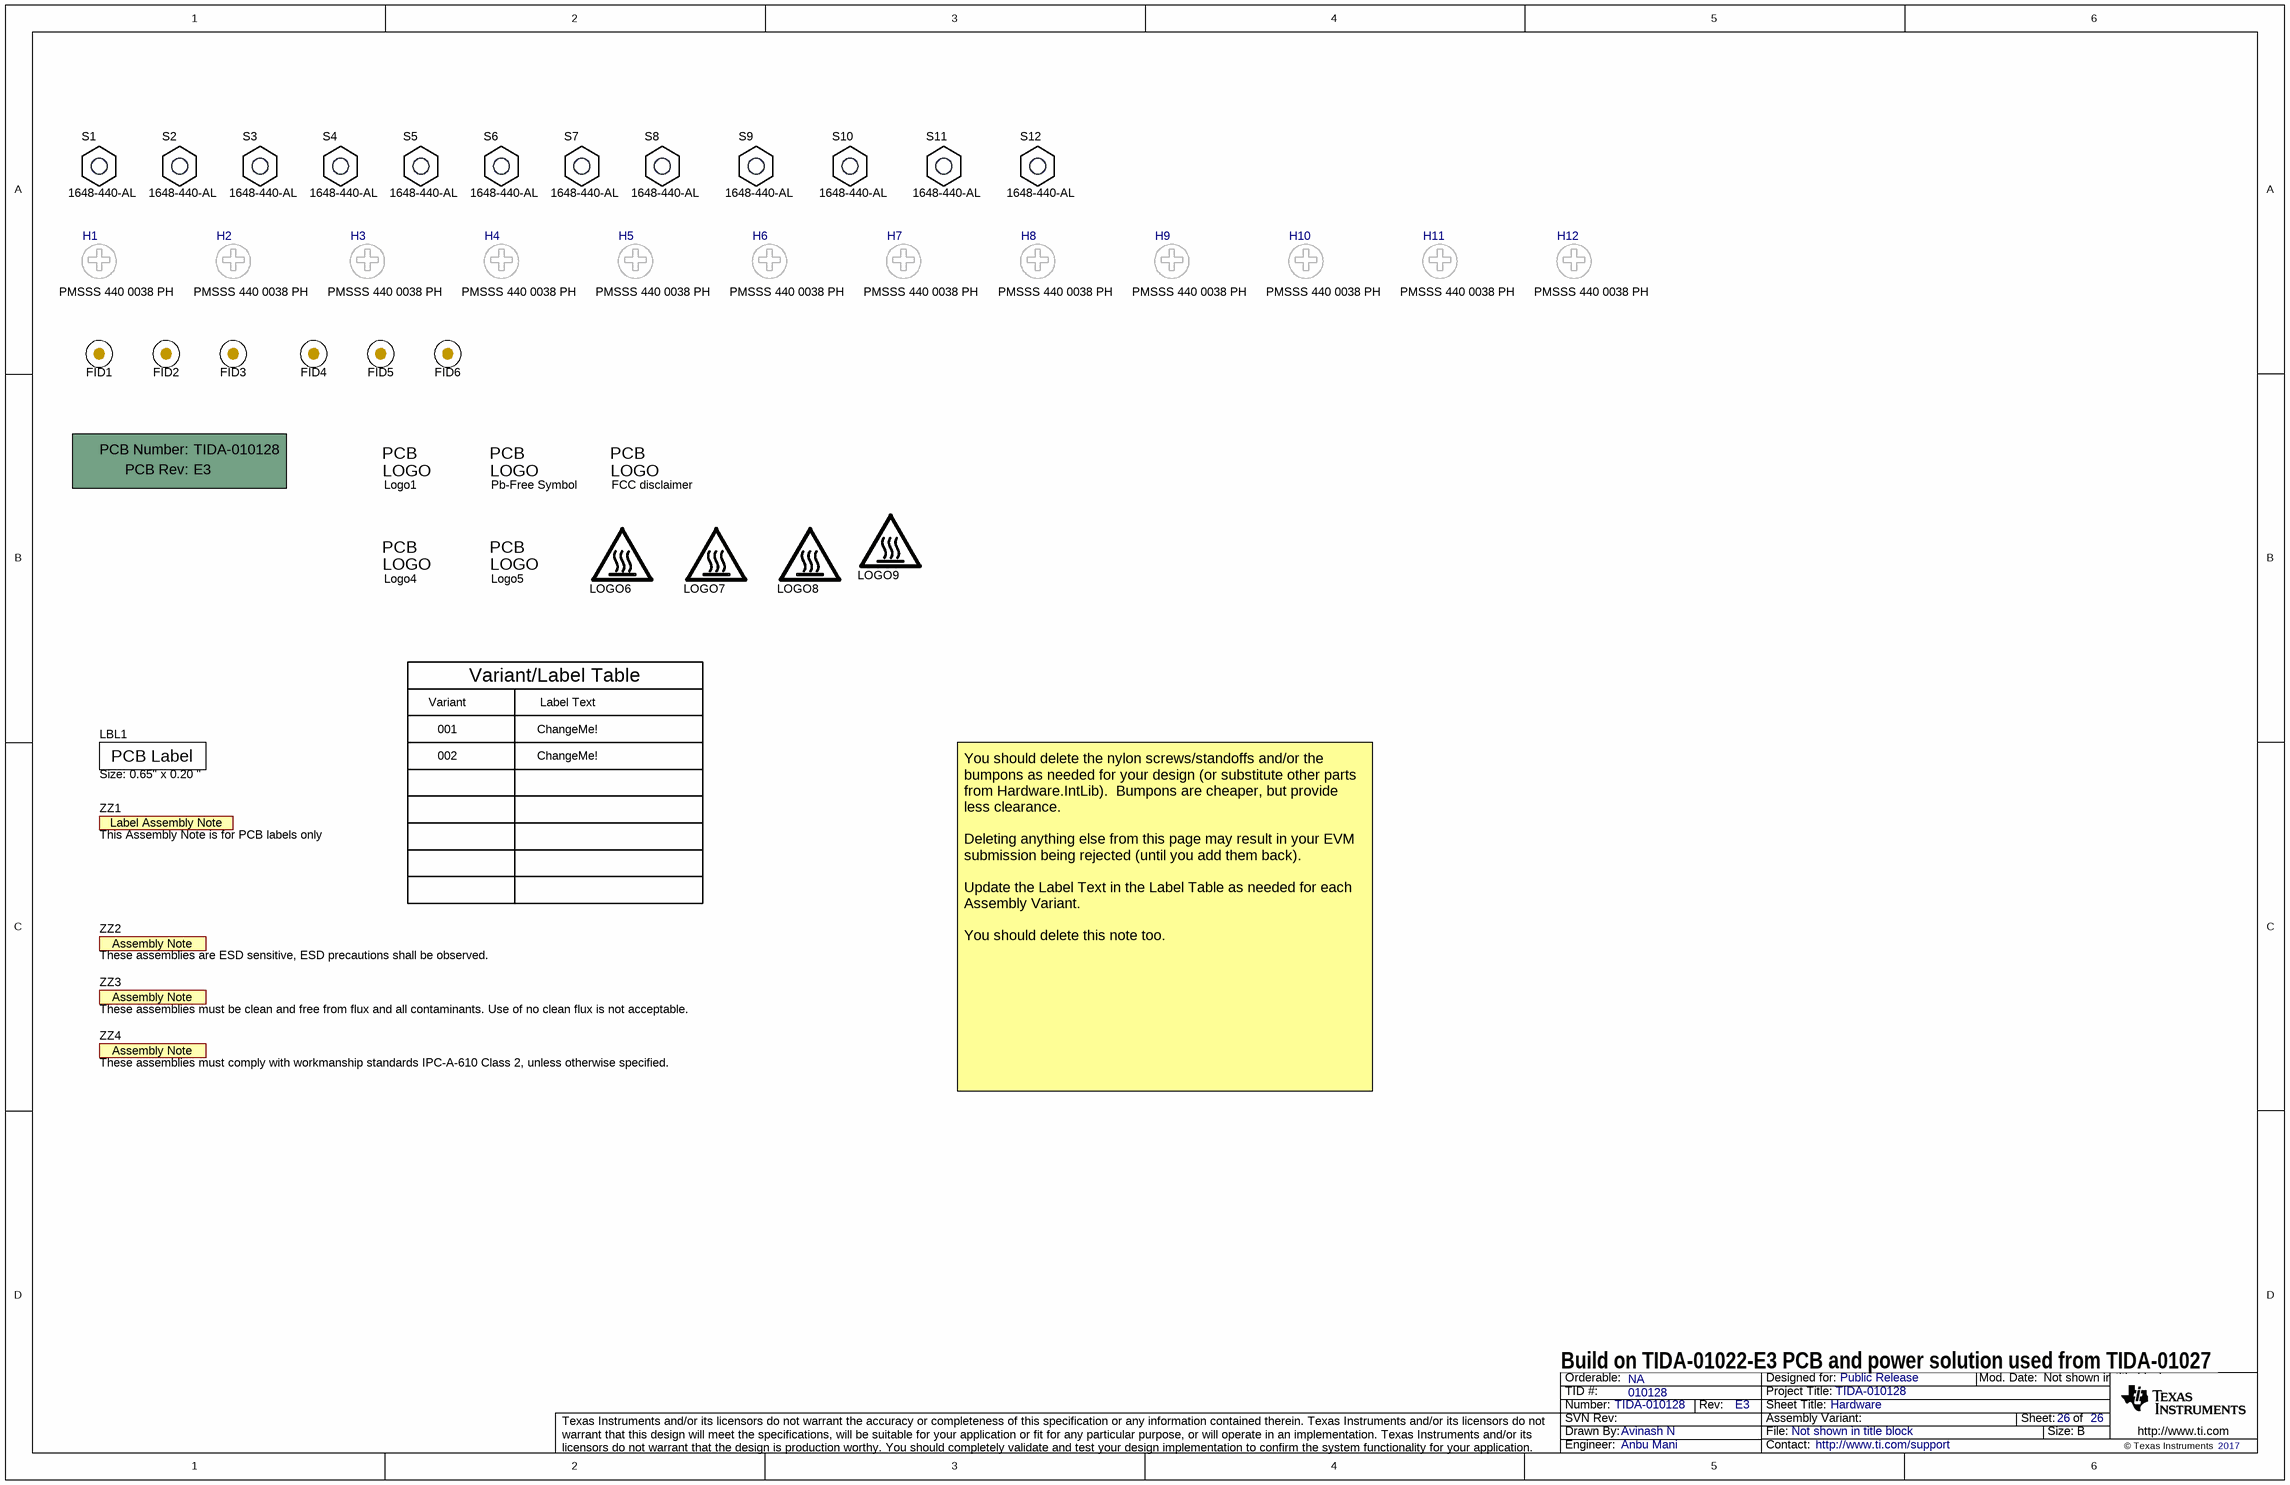
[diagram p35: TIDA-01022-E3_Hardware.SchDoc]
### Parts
!PCB1  Printed Circuit Board  (value not drawn)  (mechanical)
FID1  Fiducial  [Fiducial10-20]  (value not drawn)
FID2  Fiducial  [Fiducial10-20]  (value not drawn)
FID3  Fiducial  [Fiducial10-20]  (value not drawn)
FID4  Fiducial  [Fiducial10-20]  (value not drawn)
FID5  Fiducial  [Fiducial10-20]  (value not drawn)
FID6  Fiducial  [Fiducial10-20]  (value not drawn)
H1  PMSSS 440 0038 PH  [BuildingFastener_MPMS_003_0005_PH]  (mechanical)
H2  PMSSS 440 0038 PH  [BuildingFastener_MPMS_003_0005_PH]  (mechanical)
H3  PMSSS 440 0038 PH  [BuildingFastener_MPMS_003_0005_PH]  (mechanical)
H4  PMSSS 440 0038 PH  [BuildingFastener_MPMS_003_0005_PH]  (mechanical)
H5  PMSSS 440 0038 PH  [BuildingFastener_MPMS_003_0005_PH]  (mechanical)
H6  PMSSS 440 0038 PH  [BuildingFastener_MPMS_003_0005_PH]  (mechanical)
H7  PMSSS 440 0038 PH  [BuildingFastener_MPMS_003_0005_PH]  (mechanical)
H8  PMSSS 440 0038 PH  [BuildingFastener_MPMS_003_0005_PH]  (mechanical)
H9  PMSSS 440 0038 PH  [BuildingFastener_MPMS_003_0005_PH]  (mechanical)
H10  PMSSS 440 0038 PH  [BuildingFastener_MPMS_003_0005_PH]  (mechanical)
H11  PMSSS 440 0038 PH  [BuildingFastener_MPMS_003_0005_PH]  (mechanical)
H12  PMSSS 440 0038 PH  [BuildingFastener_MPMS_003_0005_PH]  (mechanical)
LBL1  Size: 0.65" x 0.20 "  [Label_650x200]
Logo1  ESD Susceptible  [ESD_Overlay_Large]  (value not drawn)  (no BOM)
Logo2  Pb-Free Symbol  [Pb-Free_Overlay_Small]  (no BOM)
Logo3  FCC disclaimer  [FCC_disclaimer]  (no BOM)
Logo4  EU RoHS Exempt Logo  [EURoHS_Exempt_60mil]  (value not drawn)  (no BOM)
Logo5  CAUTION.  READ USER GUIDE BEFORE USE  [IEC_Caution_Medium]  (value not drawn)  (no BOM)
LOGO6  CAUTION HOT SURFACE  [IEC_HotSurface_small]  (value not drawn)  (no BOM)
LOGO7  CAUTION HOT SURFACE  [IEC_HotSurface_small]  (value not drawn)  (no BOM)
LOGO8  CAUTION HOT SURFACE  [IEC_HotSurface_small]  (value not drawn)  (no BOM)
LOGO9  CAUTION HOT SURFACE  [IEC_HotSurface_small]  (value not drawn)  (no BOM)
S1  1648-440-AL  [TCBS-6-01]
S2  1648-440-AL  [TCBS-6-01]
S3  1648-440-AL  [TCBS-6-01]
S4  1648-440-AL  [TCBS-6-01]
S5  1648-440-AL  [TCBS-6-01]
S6  1648-440-AL  [TCBS-6-01]
S7  1648-440-AL  [TCBS-6-01]
S8  1648-440-AL  [TCBS-6-01]
S9  1648-440-AL  [TCBS-6-01]
S10  1648-440-AL  [TCBS-6-01]
S11  1648-440-AL  [TCBS-6-01]
S12  1648-440-AL  [TCBS-6-01]
ZZ1  This Assembly Note is for PCB labels only  [AssemblyNoteLabel]  (no BOM)
ZZ2  These assemblies are ESD sensitive, ESD precautions shall be observed.  [AssemblyNote]  (no BOM)
ZZ3  These assemblies must be clean and free from flux and all contaminants. Use of no clean flux is not acceptable.  [AssemblyNote]  (no BOM)
ZZ4  These assemblies must comply with workmanship standards IPC-A-610 Class 2, unless otherwise specified.  [AssemblyNote]  (no BOM)

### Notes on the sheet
- Variant
- Variant/Label Table
- Label Text
- 001
- 002
- ChangeMe!
- You should delete the nylon screws/standoffs and/or the bumpons as needed for your design (or substitute other parts from Hardware.IntLib).  Bumpons are cheaper, but provide less clearance.
  Deleting anything else from this page may result in your EVM submission being rejected (until you add them back).
  Update the Label Text in the Label Table as needed for each Assembly Variant.
  You should delete this note too.
- Build on TIDA-01022-E3 PCB and power solution used from TIDA-01027

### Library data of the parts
!PCB1 = PCB: Manufacturer: Any; PartNumber: TIDA-010128; SymbolCreator: a0412235
FID1-FID6 = Fiducial: Fiducial mark.  There is nothing to buy or mount.; SymbolCreator: codlsc
H1-H12 = MPMS 003 0005 PH: MACHINE SCREW PAN PHILLIPS 4-40; Manufacturer: B&F Fastener Supply; CompType: Hardware
LBL1 = THT-14-423-10: Thermal Transfer Printable Labels, 0.650" W x 0.200" H - 10,000 per roll; Manufacturer: Brady; SymbolCreator: a0412235; CompType: Label
Logo1 = ESD_Susceptible: ESD Susceptible Symbol; SymbolCreator: a0412235
Logo2 = Pb-Free: SymbolCreator: a0412235
Logo3 = FCC_disclaimer: SymbolCreator: codlsc
Logo4 = EURoHS_Exempt: SymbolCreator: a0412235
Logo5 = IEC_Caution: IEC 61010-1 Caution Warning; SymbolCreator: a0412235
LOGO6-LOGO9 = IEC_HotSurface: IEC 61010-1 Hot Surface Warning; SymbolCreator: a0412235
S1-S12 = TCBS-6-01: 3/16 RD X 1-3/16 LENGTH; Manufacturer: RAF Electronic Hardware; CompType: Standoff; SymbolCreator: a0412235
ZZ1 = AssemblyNoteLabel: SymbolCreator: a0412235
ZZ2-ZZ4 = AssemblyNote: SymbolCreator: codlsc

## Sheet Sheet1.SchDoc
size 431 x 279 mm; Date: Not shown in title block; ApprovedBy: Not shown in title block; CheckedBy: Not shown in title block; Author: Not shown in title block; CompanyName: Not shown in title block; Engineer: Not shown in title block; Organization: Not shown in title block; Address1: Not shown in title block; Address2: Not shown in title block; Address3: Not shown in title block; Address4: Not shown in title block; DocumentNumber: 1; Revision: Use project parameter SCH_Rev; SheetNumber: 2; SheetTotal: 3; PageSetup: Record=PageOptions¦CenterHorizontal=True¦CenterVertical=True¦PrintScale=1.00¦XCorrection=1.00¦YCorrection=1.00¦PrintKind=0¦BorderSize=5000000¦LeftOffset=0¦BottomOffset=0¦Orientation=2¦PaperLength=1000¦PaperWidth=1000¦Scale=100¦PaperSource=15¦PrintQuality=600¦MediaType=1¦DitherType=10¦PaperKind=Letter¦PrintScaleMode=1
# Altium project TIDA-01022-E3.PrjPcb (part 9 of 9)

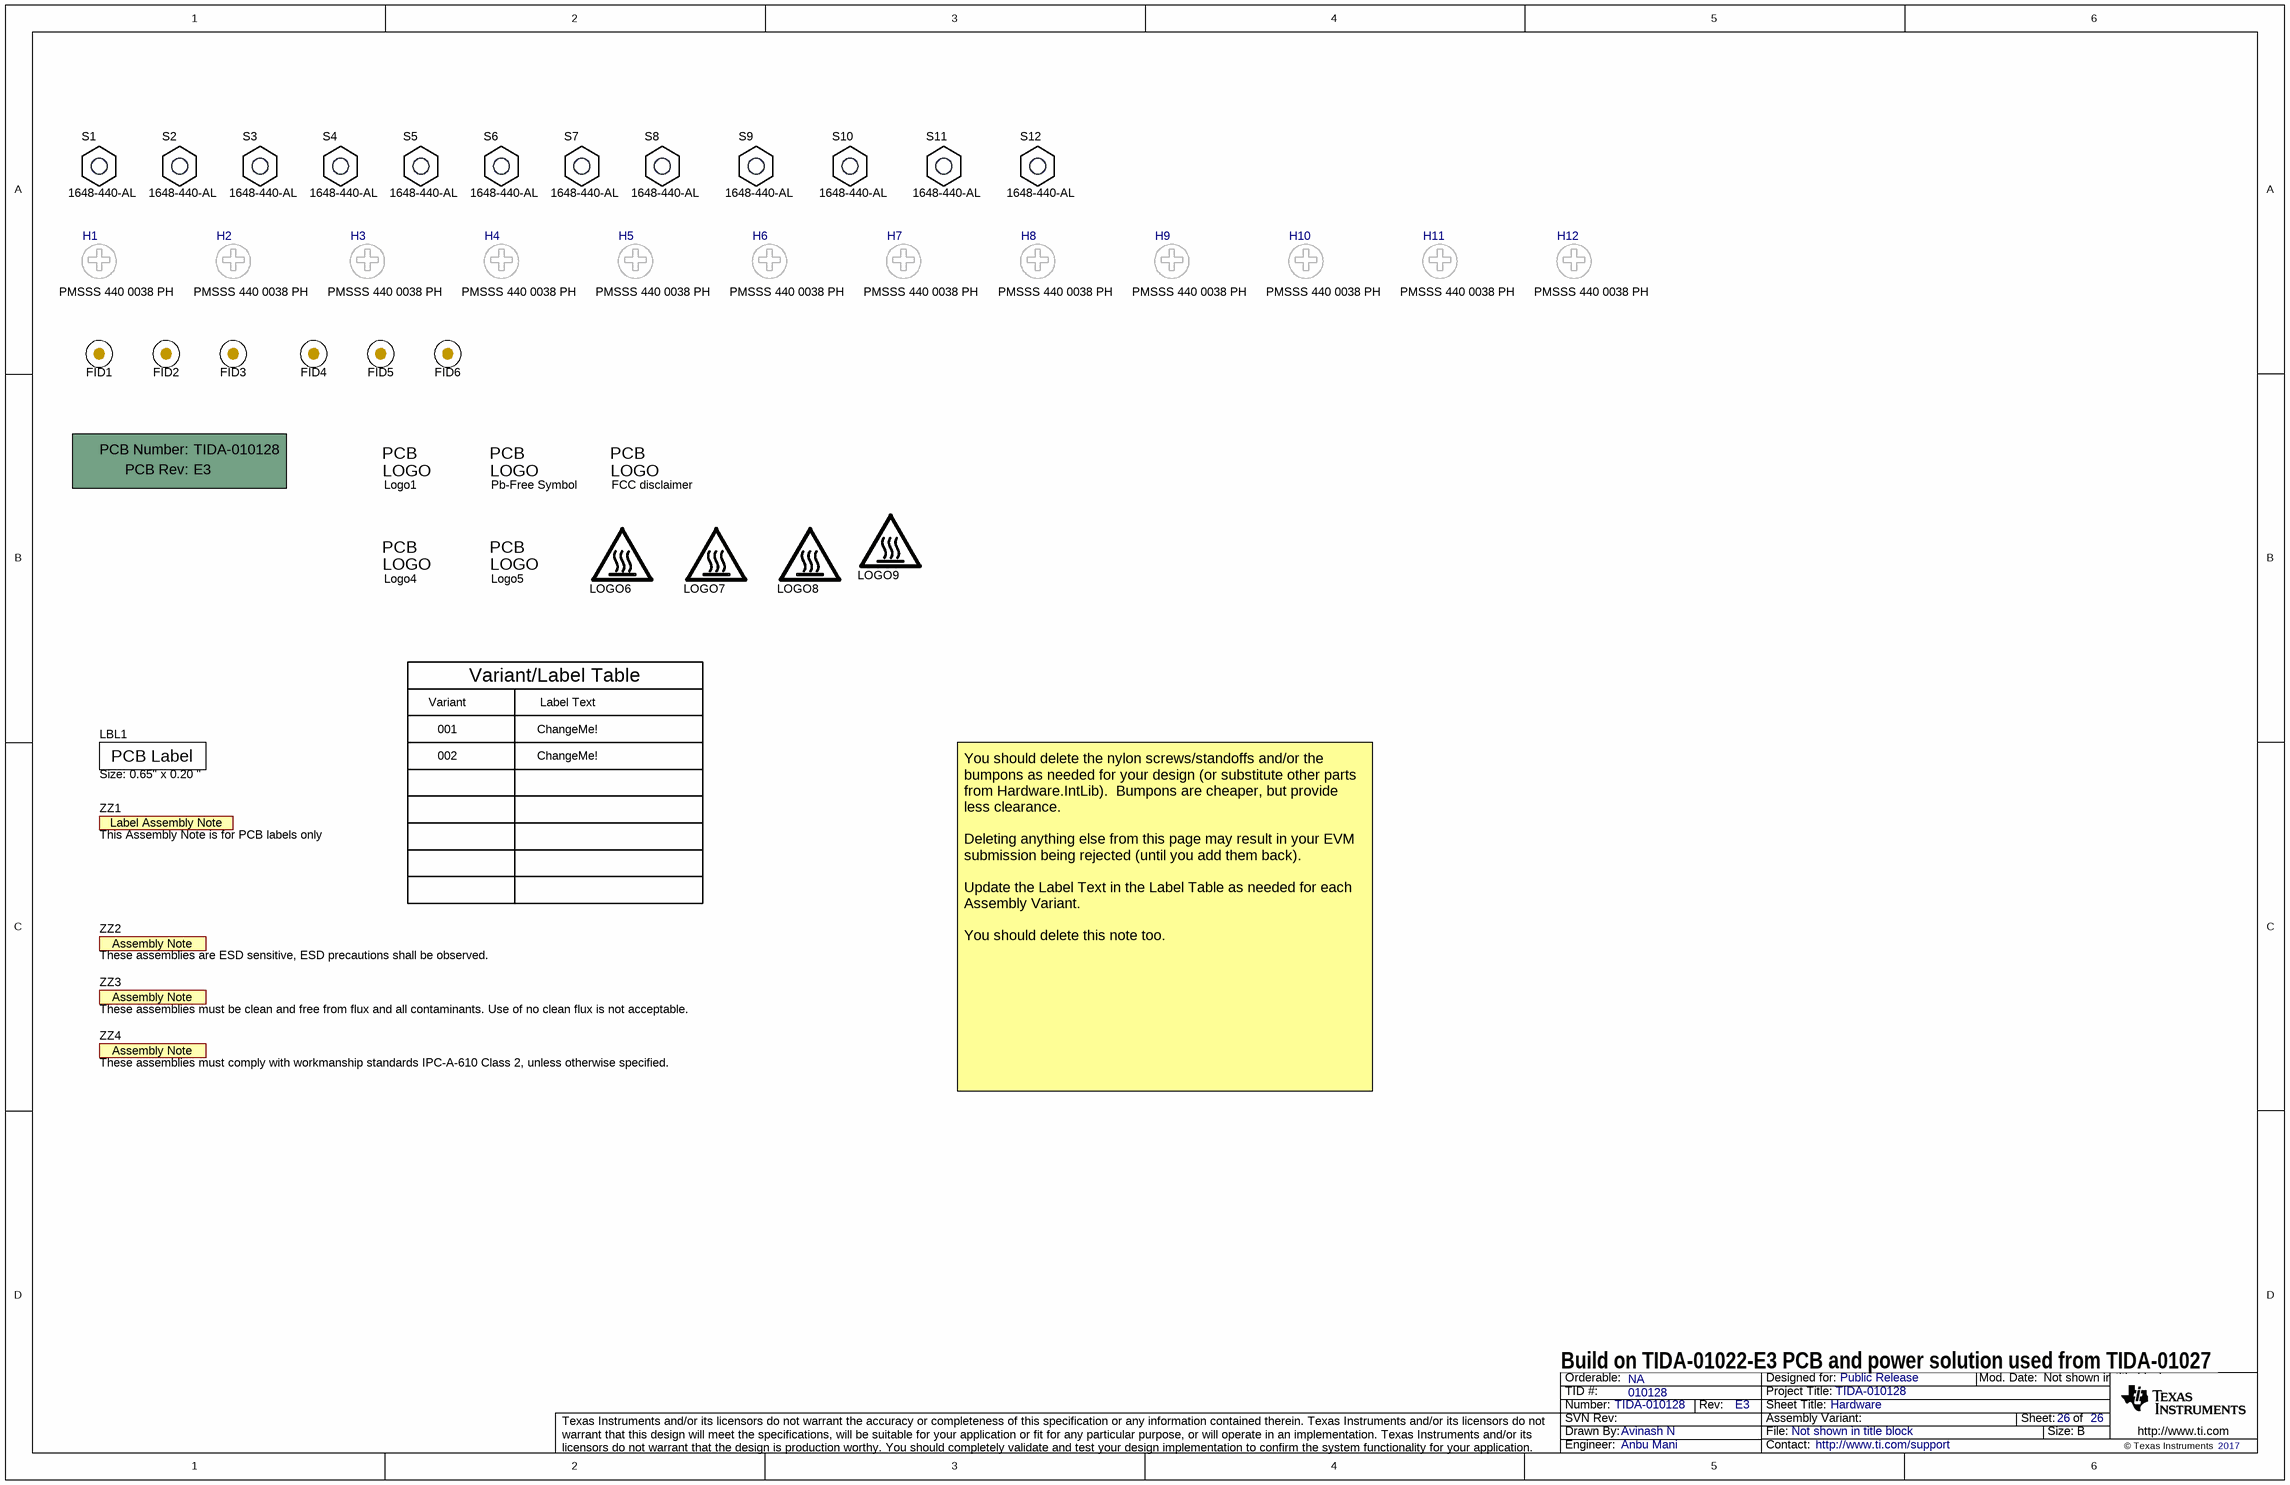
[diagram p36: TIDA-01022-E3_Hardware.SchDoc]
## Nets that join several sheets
12V: TIDA-01022-E3_Power1 (8 pins), TIDA-01022-E3_Power5 (7 pins)
12VIN: TIDA-01022-E3_Power1 (L87.2 TP77.1), TIDA-01022-E3_Power2 (L88.2), TIDA-01022-E3_Power3 (L89.2), TIDA-01022-E3_Power4 (L90.2), TIDA-01022-E3_Power5 (L91.1 L92.2)
AGND: TIDA-01022-E3_ADC ANALOG INP CH1 (72 pins), TIDA-01022-E3_ADC ANALOG INP CH2 (72 pins), TIDA-01022-E3_ADC ANALOG INP CH3 (72 pins), TIDA-01022-E3_ADC ANALOG INP CH4 (72 pins), TIDA-01022-E3_Power1 (8 pins), TIDA-01022-E3_Power4 (16 pins), TIDA-01022-E3_Power5 (38 pins)
DGND: TIDA-01022-E3_ADC12DJxx00_1 (37 pins), TIDA-01022-E3_ADC12DJxx00_1PWR (49 pins), TIDA-01022-E3_ADC12DJxx00_2 (36 pins), TIDA-01022-E3_ADC12DJxx00_2PWR (49 pins), TIDA-01022-E3_LMK00304_Buffer (23 pins), TIDA-01022-E3_LMK0482x (75 pins), TIDA-01022-E3_LMK0482x _PWR (67 pins), TIDA-01022-E3_LMX2594R_1 (51 pins), TIDA-01022-E3_LMX2594R_2 (51 pins), TIDA-01022-E3_Programming for ADC_LMK _LMX (54 pins), TIDA-01022-E3_USB (53 pins), TIDA-01022-E3_FMC+CONN1_1 (67 pins), TIDA-01022-E3_FMC+CONN1_2 (77 pins), TIDA-01022-E3_FMC+CONN2_1 (67 pins), TIDA-01022-E3_FMC+CONN2_2 (77 pins), TIDA-01022-E3_Power1 (49 pins), TIDA-01022-E3_Power2 (59 pins), TIDA-01022-E3_Power3 (43 pins), TIDA-01022-E3_Power5 (19 pins)
GND: TIDA-01022-E3_Power1 (43 pins), TIDA-01022-E3_Power2 (27 pins), TIDA-01022-E3_Power3 (27 pins), TIDA-01022-E3_Power4 (21 pins), TIDA-01022-E3_Power5 (47 pins)
V1P1V: TIDA-01022-E3_Power2 (9 pins), TIDA-01022-E3_Power5 (6 pins)
V1P1V_IN: TIDA-01022-E3_Power2 (5 pins), TIDA-01022-E3_Power5 (J59.21 J59.23 J59.25 L84.2)
V1P9V: TIDA-01022-E3_Power1 (7 pins), TIDA-01022-E3_Power5 (6 pins)
V1P9V_IN: TIDA-01022-E3_Power1 (5 pins), TIDA-01022-E3_Power5 (J59.11 J59.13 J59.15 L83.2)
V3p3: TIDA-01022-E3_Power3 (21 pins), TIDA-01022-E3_Power5 (6 pins)
V3p3_IN: TIDA-01022-E3_Power3 (5 pins), TIDA-01022-E3_Power5 (J59.1 J59.3 J59.5 L74.2)
V3p3_LMK48XX: TIDA-01022-E3_LMK0482x (R271.2 R286.2 R321.1 R340.1), TIDA-01022-E3_LMK0482x _PWR (9 pins), TIDA-01022-E3_Power3 (6 pins)
V3p3_LMK61E2: TIDA-01022-E3_LMK0482x (6 pins), TIDA-01022-E3_Power3 (6 pins)
V3p3_LMK00304: TIDA-01022-E3_LMK00304_Buffer (14 pins), TIDA-01022-E3_Power3 (6 pins)
V3p3_LMX1: TIDA-01022-E3_LMX2594R_1 (12 pins), TIDA-01022-E3_Power3 (6 pins)
V3p3_LMX1RF: TIDA-01022-E3_LMX2594R_1 (5 pins), TIDA-01022-E3_Power3 (5 pins)
V3p3_LMX2: TIDA-01022-E3_LMX2594R_2 (12 pins), TIDA-01022-E3_Power3 (6 pins)
V3p3_LMX2RF: TIDA-01022-E3_LMX2594R_2 (5 pins), TIDA-01022-E3_Power3 (5 pins)
V3p3_VDD: TIDA-01022-E3_ADC12DJxx00_1 (14 pins), TIDA-01022-E3_ADC12DJxx00_2 (15 pins), TIDA-01022-E3_LMK0482x _PWR (8 pins), TIDA-01022-E3_Programming for ADC_LMK _LMX (46 pins), TIDA-01022-E3_USB (14 pins), TIDA-01022-E3_Power3 (6 pins), TIDA-01022-E3_Power5 (C147.1 U73.1)
VA1P1_ADC1: TIDA-01022-E3_ADC12DJxx00_1PWR (12 pins), TIDA-01022-E3_Power2 (17 pins)
VA1P1_ADC2: TIDA-01022-E3_ADC12DJxx00_2PWR (12 pins), TIDA-01022-E3_Power2 (17 pins)
VA1P9_ADC1: TIDA-01022-E3_ADC12DJxx00_1 (6 pins), TIDA-01022-E3_ADC12DJxx00_1PWR (12 pins), TIDA-01022-E3_Power1 (15 pins)
VA1P9_ADC2: TIDA-01022-E3_ADC12DJxx00_2 (6 pins), TIDA-01022-E3_ADC12DJxx00_2PWR (12 pins), TIDA-01022-E3_Power1 (15 pins)
VA2p5: TIDA-01022-E3_Power4 (9 pins), TIDA-01022-E3_Power5 (6 pins)
VA2p5_IN: TIDA-01022-E3_Power4 (5 pins), TIDA-01022-E3_Power5 (J60.1 J60.3 J60.5 L85.2)
VA2p5_LMH5401_1: TIDA-01022-E3_ADC ANALOG INP CH1 (26 pins), TIDA-01022-E3_Power4 (5 pins)
VA2p5_LMH5401_2: TIDA-01022-E3_ADC ANALOG INP CH2 (26 pins), TIDA-01022-E3_Power4 (5 pins)
VA2p5_LMH5401_3: TIDA-01022-E3_ADC ANALOG INP CH3 (26 pins), TIDA-01022-E3_Power4 (5 pins)
VA2p5_LMH5401_4: TIDA-01022-E3_ADC ANALOG INP CH4 (26 pins), TIDA-01022-E3_Power4 (5 pins)
VA_n2p5_LMH5401_1: TIDA-01022-E3_ADC ANALOG INP CH1 (23 pins), TIDA-01022-E3_Power5 (5 pins)
VA_n2p5_LMH5401_2: TIDA-01022-E3_ADC ANALOG INP CH2 (23 pins), TIDA-01022-E3_Power5 (5 pins)
VA_n2p5_LMH5401_3: TIDA-01022-E3_ADC ANALOG INP CH3 (23 pins), TIDA-01022-E3_Power5 (5 pins)
VA_n2p5_LMH5401_4: TIDA-01022-E3_ADC ANALOG INP CH4 (23 pins), TIDA-01022-E3_Power5 (5 pins)
VADJ_RX1: TIDA-01022-E3_FMC+CONN1_1 (J46.E39 J46.F40 R473.2), TIDA-01022-E3_FMC+CONN1_2 (J46.G39 J46.H40 R477.2)
VADJ_RX2: TIDA-01022-E3_FMC+CONN2_1 (J51.E39 J51.F40 R478.2), TIDA-01022-E3_FMC+CONN2_2 (J51.G39 J51.H40 R482.2)
VD1P1_ADC1: TIDA-01022-E3_ADC12DJxx00_1PWR (10 pins), TIDA-01022-E3_Power2 (14 pins)
VD1P1_ADC2: TIDA-01022-E3_ADC12DJxx00_2PWR (10 pins), TIDA-01022-E3_Power2 (14 pins)
VDDL19: TIDA-01022-E3_LMK0482x _PWR (8 pins), TIDA-01022-E3_Programming for ADC_LMK _LMX (22 pins), TIDA-01022-E3_Power1 (5 pins)
3P5_VIN: TIDA-01022-E3_Power2 (C594.1 U44.12), TIDA-01022-E3_Power3 (9 pins)
AADC1_NCOA0: TIDA-01022-E3_ADC12DJxx00_1 (J5.2 R59.1 U8.C7), TIDA-01022-E3_Programming for ADC_LMK _LMX (R432.2)
AADC1_NCOA1: TIDA-01022-E3_ADC12DJxx00_1 (J5.4 R58.1 U8.D7), TIDA-01022-E3_Programming for ADC_LMK _LMX (R434.2)
AADC1_NCOB0: TIDA-01022-E3_ADC12DJxx00_1 (J5.6 R53.1 U8.K7), TIDA-01022-E3_Programming for ADC_LMK _LMX (R436.2)
AADC1_NCOB1: TIDA-01022-E3_ADC12DJxx00_1 (J5.8 R52.1 U8.J7), TIDA-01022-E3_Programming for ADC_LMK _LMX (R438.2)
AADC1_OVRA0: TIDA-01022-E3_ADC12DJxx00_1 (D2.2 U8.C8), TIDA-01022-E3_Programming for ADC_LMK _LMX (R455.2), TIDA-01022-E3_FMC+CONN1_2 (J46.G27)
AADC1_OVRA1: TIDA-01022-E3_ADC12DJxx00_1 (U8.D8), TIDA-01022-E3_Programming for ADC_LMK _LMX (R458.2)
AADC1_OVRB0: TIDA-01022-E3_ADC12DJxx00_1 (D4.2 U8.K8), TIDA-01022-E3_Programming for ADC_LMK _LMX (R461.2), TIDA-01022-E3_FMC+CONN1_1 (J46.D26)
AADC1_OVRB1: TIDA-01022-E3_ADC12DJxx00_1 (U8.J8), TIDA-01022-E3_Programming for ADC_LMK _LMX (R464.2)
AADC2_NCOA0: TIDA-01022-E3_ADC12DJxx00_2 (J16.2 R140.1 U17.C7), TIDA-01022-E3_Programming for ADC_LMK _LMX (R433.2)
AADC2_NCOA1: TIDA-01022-E3_ADC12DJxx00_2 (J16.4 R139.1 U17.D7), TIDA-01022-E3_Programming for ADC_LMK _LMX (R435.2)
AADC2_NCOB0: TIDA-01022-E3_ADC12DJxx00_2 (J16.6 R134.1 U17.K7), TIDA-01022-E3_Programming for ADC_LMK _LMX (R437.2)
AADC2_NCOB1: TIDA-01022-E3_ADC12DJxx00_2 (J16.8 R133.1 U17.J7), TIDA-01022-E3_Programming for ADC_LMK _LMX (R439.2)
AADC2_OVRA0: TIDA-01022-E3_ADC12DJxx00_2 (D7.2 U17.C8), TIDA-01022-E3_Programming for ADC_LMK _LMX (R456.2), TIDA-01022-E3_FMC+CONN2_2 (J51.G27)
AADC2_OVRA1: TIDA-01022-E3_ADC12DJxx00_2 (U17.D8), TIDA-01022-E3_Programming for ADC_LMK _LMX (R459.2)
AADC2_OVRB0: TIDA-01022-E3_ADC12DJxx00_2 (D9.2 U17.K8), TIDA-01022-E3_Programming for ADC_LMK _LMX (R462.2), TIDA-01022-E3_FMC+CONN2_1 (J51.D26)
AADC2_OVRB1: TIDA-01022-E3_ADC12DJxx00_2 (U17.J8), TIDA-01022-E3_Programming for ADC_LMK _LMX (R465.2)
ADC1_DA0_M: TIDA-01022-E3_ADC12DJxx00_1 (C72.2), TIDA-01022-E3_FMC+CONN1_1 (J46.A11)
ADC1_DA0_P: TIDA-01022-E3_ADC12DJxx00_1 (C71.2), TIDA-01022-E3_FMC+CONN1_1 (J46.A10)
ADC1_DA1_M: TIDA-01022-E3_ADC12DJxx00_1 (C75.2), TIDA-01022-E3_FMC+CONN1_1 (J46.C7)
ADC1_DA1_P: TIDA-01022-E3_ADC12DJxx00_1 (C73.2), TIDA-01022-E3_FMC+CONN1_1 (J46.C6)
ADC1_DA2_M: TIDA-01022-E3_ADC12DJxx00_1 (C77.2), TIDA-01022-E3_FMC+CONN1_1 (J46.A7)
ADC1_DA2_P: TIDA-01022-E3_ADC12DJxx00_1 (C76.2), TIDA-01022-E3_FMC+CONN1_1 (J46.A6)
ADC1_DA3_M: TIDA-01022-E3_ADC12DJxx00_1 (C79.2), TIDA-01022-E3_FMC+CONN1_1 (J46.A3)
ADC1_DA3_P: TIDA-01022-E3_ADC12DJxx00_1 (C78.2), TIDA-01022-E3_FMC+CONN1_1 (J46.A2)
ADC1_DA4_M: TIDA-01022-E3_ADC12DJxx00_1 (C81.2), TIDA-01022-E3_FMC+CONN1_2 (J46.Y15)
ADC1_DA4_P: TIDA-01022-E3_ADC12DJxx00_1 (C80.2), TIDA-01022-E3_FMC+CONN1_2 (J46.Y14)
ADC1_DA5_M: TIDA-01022-E3_ADC12DJxx00_1 (C85.2), TIDA-01022-E3_FMC+CONN1_2 (J46.Y11)
ADC1_DA5_P: TIDA-01022-E3_ADC12DJxx00_1 (C84.2), TIDA-01022-E3_FMC+CONN1_2 (J46.Y10)
ADC1_DA6_M: TIDA-01022-E3_ADC12DJxx00_1 (C87.2), TIDA-01022-E3_FMC+CONN1_1 (J46.B9)
ADC1_DA6_P: TIDA-01022-E3_ADC12DJxx00_1 (C86.2), TIDA-01022-E3_FMC+CONN1_1 (J46.B8)
ADC1_DA7_M: TIDA-01022-E3_ADC12DJxx00_1 (C89.2), TIDA-01022-E3_FMC+CONN1_1 (J46.B5)
ADC1_DA7_P: TIDA-01022-E3_ADC12DJxx00_1 (C88.2), TIDA-01022-E3_FMC+CONN1_1 (J46.B4)
ADC1_DB0_M: TIDA-01022-E3_ADC12DJxx00_1 (C98.2), TIDA-01022-E3_FMC+CONN1_1 (J46.B12)
ADC1_DB0_P: TIDA-01022-E3_ADC12DJxx00_1 (C96.2), TIDA-01022-E3_FMC+CONN1_1 (J46.B13)
ADC1_DB1_M: TIDA-01022-E3_ADC12DJxx00_1 (C101.2), TIDA-01022-E3_FMC+CONN1_1 (J46.A14)
ADC1_DB1_P: TIDA-01022-E3_ADC12DJxx00_1 (C100.2), TIDA-01022-E3_FMC+CONN1_1 (J46.A15)
ADC1_DB2_M: TIDA-01022-E3_ADC12DJxx00_1 (C103.2), TIDA-01022-E3_FMC+CONN1_1 (J46.B16)
ADC1_DB2_P: TIDA-01022-E3_ADC12DJxx00_1 (C102.2), TIDA-01022-E3_FMC+CONN1_1 (J46.B17)
ADC1_DB3_M: TIDA-01022-E3_ADC12DJxx00_1 (C105.2), TIDA-01022-E3_FMC+CONN1_1 (J46.A18)
ADC1_DB3_P: TIDA-01022-E3_ADC12DJxx00_1 (C104.2), TIDA-01022-E3_FMC+CONN1_1 (J46.A19)
ADC1_DB4_M: TIDA-01022-E3_ADC12DJxx00_1 (C110.2), TIDA-01022-E3_FMC+CONN1_2 (J46.Z12)
ADC1_DB4_P: TIDA-01022-E3_ADC12DJxx00_1 (C106.2), TIDA-01022-E3_FMC+CONN1_2 (J46.Z13)
ADC1_DB5_M: TIDA-01022-E3_ADC12DJxx00_1 (C112.2), TIDA-01022-E3_FMC+CONN1_2 (J46.Z16)
ADC1_DB5_P: TIDA-01022-E3_ADC12DJxx00_1 (C111.2), TIDA-01022-E3_FMC+CONN1_2 (J46.Z17)
ADC1_DB6_M: TIDA-01022-E3_ADC12DJxx00_1 (C114.2), TIDA-01022-E3_FMC+CONN1_2 (J46.Y18)
ADC1_DB6_P: TIDA-01022-E3_ADC12DJxx00_1 (C113.2), TIDA-01022-E3_FMC+CONN1_2 (J46.Y19)
ADC1_DB7_M: TIDA-01022-E3_ADC12DJxx00_1 (C118.2), TIDA-01022-E3_FMC+CONN1_2 (J46.Y22)
ADC1_DB7_P: TIDA-01022-E3_ADC12DJxx00_1 (C115.2), TIDA-01022-E3_FMC+CONN1_2 (J46.Y23)
ADC1_NCOA0: TIDA-01022-E3_Programming for ADC_LMK _LMX (U30.3), TIDA-01022-E3_USB (U55.9)
ADC1_NCOA1: TIDA-01022-E3_Programming for ADC_LMK _LMX (U30.4), TIDA-01022-E3_USB (U55.10)
ADC1_NCOB0: TIDA-01022-E3_Programming for ADC_LMK _LMX (U30.5), TIDA-01022-E3_USB (U55.11)
ADC1_NCOB1: TIDA-01022-E3_Programming for ADC_LMK _LMX (U30.6), TIDA-01022-E3_USB (U55.12)
ADC1_OVRA0: TIDA-01022-E3_Programming for ADC_LMK _LMX (U32.3), TIDA-01022-E3_USB (U55.4)
ADC1_OVRA1: TIDA-01022-E3_Programming for ADC_LMK _LMX (U32.4), TIDA-01022-E3_USB (U55.5)
ADC1_OVRB0: TIDA-01022-E3_Programming for ADC_LMK _LMX (U32.5), TIDA-01022-E3_USB (U55.6)
ADC1_OVRB1: TIDA-01022-E3_Programming for ADC_LMK _LMX (U32.6), TIDA-01022-E3_USB (U55.7)
ADC2_DA0_M: TIDA-01022-E3_ADC12DJxx00_2 (C232.2), TIDA-01022-E3_FMC+CONN2_1 (J51.A11)
ADC2_DA0_P: TIDA-01022-E3_ADC12DJxx00_2 (C231.2), TIDA-01022-E3_FMC+CONN2_1 (J51.A10)
ADC2_DA1_M: TIDA-01022-E3_ADC12DJxx00_2 (C235.2), TIDA-01022-E3_FMC+CONN2_1 (J51.C7)
ADC2_DA1_P: TIDA-01022-E3_ADC12DJxx00_2 (C233.2), TIDA-01022-E3_FMC+CONN2_1 (J51.C6)
ADC2_DA2_M: TIDA-01022-E3_ADC12DJxx00_2 (C237.2), TIDA-01022-E3_FMC+CONN2_1 (J51.A7)
ADC2_DA2_P: TIDA-01022-E3_ADC12DJxx00_2 (C236.2), TIDA-01022-E3_FMC+CONN2_1 (J51.A6)
ADC2_DA3_M: TIDA-01022-E3_ADC12DJxx00_2 (C239.2), TIDA-01022-E3_FMC+CONN2_1 (J51.A3)
ADC2_DA3_P: TIDA-01022-E3_ADC12DJxx00_2 (C238.2), TIDA-01022-E3_FMC+CONN2_1 (J51.A2)
ADC2_DA4_M: TIDA-01022-E3_ADC12DJxx00_2 (C241.2), TIDA-01022-E3_FMC+CONN2_2 (J51.Y15)
ADC2_DA4_P: TIDA-01022-E3_ADC12DJxx00_2 (C240.2), TIDA-01022-E3_FMC+CONN2_2 (J51.Y14)
ADC2_DA5_M: TIDA-01022-E3_ADC12DJxx00_2 (C245.2), TIDA-01022-E3_FMC+CONN2_2 (J51.Y11)
ADC2_DA5_P: TIDA-01022-E3_ADC12DJxx00_2 (C244.2), TIDA-01022-E3_FMC+CONN2_2 (J51.Y10)
ADC2_DA6_M: TIDA-01022-E3_ADC12DJxx00_2 (C247.2), TIDA-01022-E3_FMC+CONN2_1 (J51.B9)
ADC2_DA6_P: TIDA-01022-E3_ADC12DJxx00_2 (C246.2), TIDA-01022-E3_FMC+CONN2_1 (J51.B8)
ADC2_DA7_M: TIDA-01022-E3_ADC12DJxx00_2 (C249.2), TIDA-01022-E3_FMC+CONN2_1 (J51.B5)
ADC2_DA7_P: TIDA-01022-E3_ADC12DJxx00_2 (C248.2), TIDA-01022-E3_FMC+CONN2_1 (J51.B4)
ADC2_DB0_M: TIDA-01022-E3_ADC12DJxx00_2 (C258.2), TIDA-01022-E3_FMC+CONN2_1 (J51.B12)
ADC2_DB0_P: TIDA-01022-E3_ADC12DJxx00_2 (C256.2), TIDA-01022-E3_FMC+CONN2_1 (J51.B13)
ADC2_DB1_M: TIDA-01022-E3_ADC12DJxx00_2 (C261.2), TIDA-01022-E3_FMC+CONN2_1 (J51.A14)
ADC2_DB1_P: TIDA-01022-E3_ADC12DJxx00_2 (C260.2), TIDA-01022-E3_FMC+CONN2_1 (J51.A15)
ADC2_DB2_M: TIDA-01022-E3_ADC12DJxx00_2 (C263.2), TIDA-01022-E3_FMC+CONN2_1 (J51.B16)
ADC2_DB2_P: TIDA-01022-E3_ADC12DJxx00_2 (C262.2), TIDA-01022-E3_FMC+CONN2_1 (J51.B17)
ADC2_DB3_M: TIDA-01022-E3_ADC12DJxx00_2 (C265.2), TIDA-01022-E3_FMC+CONN2_1 (J51.A18)
ADC2_DB3_P: TIDA-01022-E3_ADC12DJxx00_2 (C264.2), TIDA-01022-E3_FMC+CONN2_1 (J51.A19)
ADC2_DB4_M: TIDA-01022-E3_ADC12DJxx00_2 (C270.2), TIDA-01022-E3_FMC+CONN2_2 (J51.Z12)
ADC2_DB4_P: TIDA-01022-E3_ADC12DJxx00_2 (C266.2), TIDA-01022-E3_FMC+CONN2_2 (J51.Z13)
ADC2_DB5_M: TIDA-01022-E3_ADC12DJxx00_2 (C272.2), TIDA-01022-E3_FMC+CONN2_2 (J51.Z16)
ADC2_DB5_P: TIDA-01022-E3_ADC12DJxx00_2 (C271.2), TIDA-01022-E3_FMC+CONN2_2 (J51.Z17)
ADC2_DB6_M: TIDA-01022-E3_ADC12DJxx00_2 (C274.2), TIDA-01022-E3_FMC+CONN2_2 (J51.Y18)
ADC2_DB6_P: TIDA-01022-E3_ADC12DJxx00_2 (C273.2), TIDA-01022-E3_FMC+CONN2_2 (J51.Y19)
ADC2_DB7_M: TIDA-01022-E3_ADC12DJxx00_2 (C278.2), TIDA-01022-E3_FMC+CONN2_2 (J51.Y22)
ADC2_DB7_P: TIDA-01022-E3_ADC12DJxx00_2 (C275.2), TIDA-01022-E3_FMC+CONN2_2 (J51.Y23)
ADC2_NCOA0: TIDA-01022-E3_Programming for ADC_LMK _LMX (U31.3), TIDA-01022-E3_USB (U57.9)
ADC2_NCOA1: TIDA-01022-E3_Programming for ADC_LMK _LMX (U31.4), TIDA-01022-E3_USB (U57.10)
ADC2_NCOB0: TIDA-01022-E3_Programming for ADC_LMK _LMX (U31.5), TIDA-01022-E3_USB (U57.11)
ADC2_NCOB1: TIDA-01022-E3_Programming for ADC_LMK _LMX (U31.6), TIDA-01022-E3_USB (U57.12)
ADC2_OVRA0: TIDA-01022-E3_Programming for ADC_LMK _LMX (U33.3), TIDA-01022-E3_USB (U57.4)
ADC2_OVRA1: TIDA-01022-E3_Programming for ADC_LMK _LMX (U33.4), TIDA-01022-E3_USB (U57.5)
ADC2_OVRB0: TIDA-01022-E3_Programming for ADC_LMK _LMX (U33.5), TIDA-01022-E3_USB (U57.6)
ADC2_OVRB1: TIDA-01022-E3_Programming for ADC_LMK _LMX (U33.6), TIDA-01022-E3_USB (U57.7)
ADC_SCK: TIDA-01022-E3_Programming for ADC_LMK _LMX (U26.3), TIDA-01022-E3_USB (U34.16)
ADC_SCS0: TIDA-01022-E3_Programming for ADC_LMK _LMX (U26.6), TIDA-01022-E3_USB (U34.19)
ADC_SCS1: TIDA-01022-E3_Programming for ADC_LMK _LMX (U28.2), TIDA-01022-E3_USB (U34.21)
ADC_SDI: TIDA-01022-E3_Programming for ADC_LMK _LMX (U26.4), TIDA-01022-E3_USB (U34.17)
ADC_SDO: TIDA-01022-E3_Programming for ADC_LMK _LMX (U26.5), TIDA-01022-E3_USB (U34.18)
BADC1_SCS: TIDA-01022-E3_ADC12DJxx00_1 (U8.E8), TIDA-01022-E3_Programming for ADC_LMK _LMX (J33.1 R380.2 R400.2)
BADC2_SCS: TIDA-01022-E3_ADC12DJxx00_2 (U17.E8), TIDA-01022-E3_Programming for ADC_LMK _LMX (J33.3 R382.2 R416.2)
BADC_SCK: TIDA-01022-E3_ADC12DJxx00_1 (U8.F8), TIDA-01022-E3_ADC12DJxx00_2 (U17.F8), TIDA-01022-E3_Programming for ADC_LMK _LMX (R375.1 R394.2)
BADC_SDI: TIDA-01022-E3_ADC12DJxx00_1 (U8.G8), TIDA-01022-E3_ADC12DJxx00_2 (U17.G8), TIDA-01022-E3_Programming for ADC_LMK _LMX (R377.1 R396.2)
BADC_SDO: TIDA-01022-E3_ADC12DJxx00_1 (U8.H8), TIDA-01022-E3_ADC12DJxx00_2 (U17.H8), TIDA-01022-E3_Programming for ADC_LMK _LMX (R379.1 R398.2)
BLMH1_SCS: TIDA-01022-E3_ADC ANALOG INP CH1 (U2.15), TIDA-01022-E3_Programming for ADC_LMK _LMX (J34.1 R381.2 R402.2)
BLMH2_SCS: TIDA-01022-E3_ADC ANALOG INP CH2 (U5.15), TIDA-01022-E3_Programming for ADC_LMK _LMX (J34.3 R383.2 R424.2)
BLMH3_SCS: TIDA-01022-E3_ADC ANALOG INP CH3 (U11.15), TIDA-01022-E3_Programming for ADC_LMK _LMX (J34.5 R384.2 R423.2)
BLMH4_SCS: TIDA-01022-E3_ADC ANALOG INP CH4 (U14.15), TIDA-01022-E3_Programming for ADC_LMK _LMX (J34.7 R385.2 R421.2)
BLMH_CLK: TIDA-01022-E3_ADC ANALOG INP CH1 (U2.14), TIDA-01022-E3_ADC ANALOG INP CH2 (U5.14), TIDA-01022-E3_ADC ANALOG INP CH3 (U11.14), TIDA-01022-E3_ADC ANALOG INP CH4 (U14.14), TIDA-01022-E3_Programming for ADC_LMK _LMX (R374.1 R409.2)
BLMH_SDI: TIDA-01022-E3_ADC ANALOG INP CH1 (U2.1), TIDA-01022-E3_ADC ANALOG INP CH2 (U5.1), TIDA-01022-E3_ADC ANALOG INP CH3 (U11.1), TIDA-01022-E3_ADC ANALOG INP CH4 (U14.1), TIDA-01022-E3_Programming for ADC_LMK _LMX (R378.1 R407.2)
BLMH_SDO: TIDA-01022-E3_ADC ANALOG INP CH1 (U2.4), TIDA-01022-E3_ADC ANALOG INP CH2 (U5.4), TIDA-01022-E3_ADC ANALOG INP CH3 (U11.4), TIDA-01022-E3_ADC ANALOG INP CH4 (U14.4), TIDA-01022-E3_Programming for ADC_LMK _LMX (R376.1 R405.2)
BLMK_LMX_SCK: TIDA-01022-E3_LMK0482x _PWR (C426.2 U24.19), TIDA-01022-E3_LMX2594R_1 (U19.16), TIDA-01022-E3_LMX2594R_2 (U21.16), TIDA-01022-E3_Programming for ADC_LMK _LMX (R426.1 R445.2)
BLMK_LMX_SDI: TIDA-01022-E3_LMK0482x _PWR (C425.2 U24.20), TIDA-01022-E3_LMX2594R_1 (U19.17), TIDA-01022-E3_LMX2594R_2 (U21.17), TIDA-01022-E3_Programming for ADC_LMK _LMX (R427.1 R447.2)
BLMK_LMX_SDO1: TIDA-01022-E3_LMX2594R_1 (R187.2), TIDA-01022-E3_Programming for ADC_LMK _LMX (U75.7)
BLMK_LMX_SDO2: TIDA-01022-E3_LMX2594R_2 (R227.2), TIDA-01022-E3_Programming for ADC_LMK _LMX (U75.6)
BLMK_SCS: TIDA-01022-E3_LMK0482x _PWR (C427.2 U24.18), TIDA-01022-E3_Programming for ADC_LMK _LMX (J40.1 R429.2 R451.2)
BLMX1_SCS: TIDA-01022-E3_LMX2594R_1 (U19.24), TIDA-01022-E3_Programming for ADC_LMK _LMX (J40.3 R410.2 R430.2 R452.2)
BLMX2_SCS: TIDA-01022-E3_LMX2594R_2 (U21.24), TIDA-01022-E3_Programming for ADC_LMK _LMX (J40.5 R431.2 R454.2)
BUF_CLKIN_SEL0: TIDA-01022-E3_LMK00304_Buffer (J23.2 U23.13), TIDA-01022-E3_USB (U58.6)
BUF_CLKIN_SEL1: TIDA-01022-E3_LMK00304_Buffer (J23.1 U23.16), TIDA-01022-E3_USB (U58.7)
CLK-IN*: TIDA-01022-E3_LMK0482x (R301.2 R308.2 R392.1), TIDA-01022-E3_LMK0482x _PWR (R401.1)
CLKin_SEL0: TIDA-01022-E3_LMK0482x _PWR (R371.1 U24.58), TIDA-01022-E3_Programming for ADC_LMK _LMX (R599.2)
CLKin_SEL1: TIDA-01022-E3_LMK0482x _PWR (R370.1 U24.59), TIDA-01022-E3_Programming for ADC_LMK _LMX (R602.1)
CLKINN*: TIDA-01022-E3_LMK0482x (C404.1 R305.1 R309.2 R312.2), TIDA-01022-E3_LMK0482x _PWR (R395.1)
CLKINP*: TIDA-01022-E3_LMK0482x (C403.1 R298.1 R302.2 R305.2), TIDA-01022-E3_LMK0482x _PWR (R399.1)
CLKOUT_TYPE0: TIDA-01022-E3_LMK00304_Buffer (J23.4 U23.9), TIDA-01022-E3_USB (U58.4)
CLKOUT_TYPE1: TIDA-01022-E3_LMK00304_Buffer (J23.3 U23.32), TIDA-01022-E3_USB (U58.5)
DCLKout12_N: TIDA-01022-E3_LMK0482x (C415.2), TIDA-01022-E3_LMK0482x _PWR (J4.1), TIDA-01022-E3_FMC+CONN1_2 (J46.Z21)
DCLKout12_P: TIDA-01022-E3_LMK0482x (C413.2), TIDA-01022-E3_LMK0482x _PWR (J3.1), TIDA-01022-E3_FMC+CONN1_2 (J46.Z20)
F_CORECLK1_N: TIDA-01022-E3_LMK0482x (R317.2), TIDA-01022-E3_FMC+CONN1_1 (J46.D5)
F_CORECLK1_P: TIDA-01022-E3_LMK0482x (R316.2), TIDA-01022-E3_FMC+CONN1_1 (J46.D4)
F_CORECLK2_N: TIDA-01022-E3_LMK0482x (R313.2), TIDA-01022-E3_FMC+CONN2_1 (J51.D5)
F_CORECLK2_P: TIDA-01022-E3_LMK0482x (R310.2), TIDA-01022-E3_FMC+CONN2_1 (J51.D4)
F_REFCLK1_N: TIDA-01022-E3_LMK0482x (R325.2), TIDA-01022-E3_FMC+CONN1_2 (J46.G7)
F_REFCLK1_P: TIDA-01022-E3_LMK0482x (R322.2), TIDA-01022-E3_FMC+CONN1_2 (J46.G6)
F_REFCLK2_N: TIDA-01022-E3_LMK0482x (R306.2), TIDA-01022-E3_FMC+CONN2_2 (J51.G7)
F_REFCLK2_P: TIDA-01022-E3_LMK0482x (R304.2), TIDA-01022-E3_FMC+CONN2_2 (J51.G6)
F_SYSREF1_N: TIDA-01022-E3_LMK0482x (R320.2), TIDA-01022-E3_FMC+CONN1_2 (J46.G10)
F_SYSREF1_P: TIDA-01022-E3_LMK0482x (R318.2), TIDA-01022-E3_FMC+CONN1_2 (J46.G9)
F_SYSREF2_N: TIDA-01022-E3_LMK0482x (R315.2), TIDA-01022-E3_FMC+CONN2_2 (J51.G10)
F_SYSREF2_P: TIDA-01022-E3_LMK0482x (R314.2), TIDA-01022-E3_FMC+CONN2_2 (J51.G9)
FREQ_DIV_RESET: TIDA-01022-E3_LMK0482x _PWR (R403.2), TIDA-01022-E3_USB (U58.9)
IOVLVL: TIDA-01022-E3_LMK0482x _PWR (U24.7), TIDA-01022-E3_Programming for ADC_LMK _LMX (R597.2)
LDO_PG_1P9V: TIDA-01022-E3_Power1 (R493.2 TP81.1 U41.4), TIDA-01022-E3_Power2 (R389.1)
LMH_CLK: TIDA-01022-E3_Programming for ADC_LMK _LMX (U27.6), TIDA-01022-E3_USB (U34.48)
LMH_CS1: TIDA-01022-E3_Programming for ADC_LMK _LMX (U27.3), TIDA-01022-E3_USB (U34.54)
LMH_CS2: TIDA-01022-E3_Programming for ADC_LMK _LMX (U29.5), TIDA-01022-E3_USB (U34.55)
LMH_CS3: TIDA-01022-E3_Programming for ADC_LMK _LMX (U29.4), TIDA-01022-E3_USB (U34.57)
LMH_CS4: TIDA-01022-E3_Programming for ADC_LMK _LMX (U29.3), TIDA-01022-E3_USB (U34.58)
LMH_SDI: TIDA-01022-E3_Programming for ADC_LMK _LMX (U27.5), TIDA-01022-E3_USB (U34.52)
LMH_SDO: TIDA-01022-E3_Programming for ADC_LMK _LMX (U27.4), TIDA-01022-E3_USB (U34.53)
LMK04828_SYNC1: TIDA-01022-E3_LMK0482x _PWR (R586.2), TIDA-01022-E3_FMC+CONN1_2 (J46.J15)
LMK04828_SYNC2: TIDA-01022-E3_LMK0482x _PWR (R590.1), TIDA-01022-E3_FMC+CONN2_2 (J51.J15)
LMK_ADC1_DCLKM: TIDA-01022-E3_ADC12DJxx00_1 (C99.2), TIDA-01022-E3_LMK0482x (C396.2), TIDA-01022-E3_LMX2594R_1 (R197.1)
LMK_ADC1_DCLKP: TIDA-01022-E3_ADC12DJxx00_1 (C90.2), TIDA-01022-E3_LMK0482x (C394.2), TIDA-01022-E3_LMX2594R_1 (R195.1)
LMK_ADC1_SYSREF_M: TIDA-01022-E3_ADC12DJxx00_1 (C95.1), TIDA-01022-E3_LMK0482x (R280.2), TIDA-01022-E3_LMX2594R_1 (R200.1 R201.1 U20.3)
LMK_ADC1_SYSREF_P: TIDA-01022-E3_ADC12DJxx00_1 (C94.1), TIDA-01022-E3_LMK0482x (R277.2), TIDA-01022-E3_LMX2594R_1 (R201.2 U20.4)
LMK_ADC2_DCLKM: TIDA-01022-E3_ADC12DJxx00_2 (C259.2), TIDA-01022-E3_LMK0482x (C402.2), TIDA-01022-E3_LMX2594R_2 (R238.1)
LMK_ADC2_DCLKP: TIDA-01022-E3_ADC12DJxx00_2 (C250.2), TIDA-01022-E3_LMK0482x (C401.2), TIDA-01022-E3_LMX2594R_2 (R236.1)
LMK_ADC2_SYSREF_M: TIDA-01022-E3_ADC12DJxx00_2 (C255.1), TIDA-01022-E3_LMK0482x (R295.2), TIDA-01022-E3_LMX2594R_2 (R239.1 R240.1 U22.3)
LMK_ADC2_SYSREF_P: TIDA-01022-E3_ADC12DJxx00_2 (C254.1), TIDA-01022-E3_LMK0482x (R293.2), TIDA-01022-E3_LMX2594R_2 (R240.2 U22.4)
LMK_CS: TIDA-01022-E3_Programming for ADC_LMK _LMX (R451.1), TIDA-01022-E3_USB (U34.40)
LMK_EXT_SYNC: TIDA-01022-E3_LMK0482x _PWR (R229.1), TIDA-01022-E3_Programming for ADC_LMK _LMX (R601.1)
LMK_LMX_SCK: TIDA-01022-E3_Programming for ADC_LMK _LMX (R445.1), TIDA-01022-E3_USB (U34.38)
LMK_SDIO_LMX_SDI: TIDA-01022-E3_Programming for ADC_LMK _LMX (R447.1), TIDA-01022-E3_USB (U34.39)
LMX1_CLKM: TIDA-01022-E3_ADC12DJxx00_1 (C93.2), TIDA-01022-E3_LMX2594R_1 (R168.1 U19.22)
LMX1_CLKP: TIDA-01022-E3_ADC12DJxx00_1 (C92.2), TIDA-01022-E3_LMX2594R_1 (R164.1 U19.23)
LMX1_CS: TIDA-01022-E3_Programming for ADC_LMK _LMX (R452.1), TIDA-01022-E3_USB (U34.41)
LMX1_REFN: TIDA-01022-E3_LMK00304_Buffer (R255.2 R256.1 R258.2), TIDA-01022-E3_LMX2594R_1 (R203.1)
LMX1_REFP: TIDA-01022-E3_LMK00304_Buffer (R252.1 R254.2 R259.2), TIDA-01022-E3_LMX2594R_1 (R185.2)
LMX2_CLKM: TIDA-01022-E3_ADC12DJxx00_2 (C253.2), TIDA-01022-E3_LMX2594R_2 (R209.1 U21.22)
LMX2_CLKP: TIDA-01022-E3_ADC12DJxx00_2 (C252.2), TIDA-01022-E3_LMX2594R_2 (R205.1 U21.23)
LMX2_CS: TIDA-01022-E3_Programming for ADC_LMK _LMX (R454.1), TIDA-01022-E3_USB (U34.45)
LMX2_REFN: TIDA-01022-E3_LMK00304_Buffer (R264.2 R265.1 R268.2), TIDA-01022-E3_LMX2594R_2 (R244.1)
LMX2_REFP: TIDA-01022-E3_LMK00304_Buffer (R260.1 R262.2 R269.2), TIDA-01022-E3_LMX2594R_2 (R226.2)
LMX_ADC1_SYSREF_M: TIDA-01022-E3_ADC12DJxx00_1 (C325.1), TIDA-01022-E3_LMX2594R_1 (R180.1 U19.19)
LMX_ADC1_SYSREF_P: TIDA-01022-E3_ADC12DJxx00_1 (C321.1), TIDA-01022-E3_LMX2594R_1 (R175.2 U19.18)
LMX_ADC2_SYSREF_M: TIDA-01022-E3_ADC12DJxx00_2 (C341.1), TIDA-01022-E3_LMX2594R_2 (R221.1 U21.19)
LMX_ADC2_SYSREF_P: TIDA-01022-E3_ADC12DJxx00_2 (C334.1), TIDA-01022-E3_LMX2594R_2 (R216.2 U21.18)
LMX_SDO: TIDA-01022-E3_Programming for ADC_LMK _LMX (R449.1), TIDA-01022-E3_USB (U34.43)
OSCout_N: TIDA-01022-E3_LMK00304_Buffer (R257.2 R266.2 R270.1), TIDA-01022-E3_LMK0482x (U24.41)
OSCout_P: TIDA-01022-E3_LMK00304_Buffer (R253.2 R261.2 R263.1), TIDA-01022-E3_LMK0482x (U24.40)
PG_3P3V: TIDA-01022-E3_Power1 (R386.2), TIDA-01022-E3_Power2 (R388.2), TIDA-01022-E3_Power3 (R418.2 R513.1 U45.7)
RESET: TIDA-01022-E3_LMK0482x _PWR (C423.2 R228.2 R368.2 U24.5), TIDA-01022-E3_Programming for ADC_LMK _LMX (R603.1), TIDA-01022-E3_USB (R591.2)
SDCLKout5_N: TIDA-01022-E3_LMK0482x (R346.2), TIDA-01022-E3_LMX2594R_2 (R235.1 U22.1)
SDCLKout5_P: TIDA-01022-E3_LMK0482x (R343.2), TIDA-01022-E3_LMX2594R_2 (R234.2 R235.2 U22.2)
SDCLKout11_N: TIDA-01022-E3_LMK0482x (R355.2), TIDA-01022-E3_LMX2594R_1 (R194.1 U20.1)
SDCLKout11_P: TIDA-01022-E3_LMK0482x (R350.2), TIDA-01022-E3_LMX2594R_1 (R193.2 R194.2 U20.2)
SDCLKout13_N: TIDA-01022-E3_LMK0482x (R361.2), TIDA-01022-E3_LMK0482x _PWR (J2.1), TIDA-01022-E3_FMC+CONN2_2 (J51.Z21), TIDA-01022-E3_Power5 (R391.1)
SDCLKout13_P: TIDA-01022-E3_LMK0482x (R360.2), TIDA-01022-E3_LMK0482x _PWR (J1.1), TIDA-01022-E3_FMC+CONN2_2 (J51.Z20), TIDA-01022-E3_Power5 (R390.1)
SMB_CLK: TIDA-01022-E3_ADC12DJxx00_1 (R81.1 U9.13), TIDA-01022-E3_ADC12DJxx00_2 (R162.1 U18.13), TIDA-01022-E3_LMK0482x (R352.1 U25.8), TIDA-01022-E3_Programming for ADC_LMK _LMX (J32.9 R594.1), TIDA-01022-E3_USB (J62.4 R442.2)
SMB_DAT: TIDA-01022-E3_ADC12DJxx00_1 (R80.1 U9.12), TIDA-01022-E3_ADC12DJxx00_2 (R161.1 U18.12), TIDA-01022-E3_LMK0482x (R353.1 U25.7), TIDA-01022-E3_Programming for ADC_LMK _LMX (J32.10), TIDA-01022-E3_USB (J62.2 J62.6 R443.2)
SYNC1_N: TIDA-01022-E3_ADC12DJxx00_1 (R69.1), TIDA-01022-E3_FMC+CONN1_2 (J46.G13)
SYNC1_P: TIDA-01022-E3_ADC12DJxx00_1 (R68.1), TIDA-01022-E3_FMC+CONN1_2 (J46.G12)
SYNC1_SE: TIDA-01022-E3_LMK0482x _PWR (R587.1 R633.1), TIDA-01022-E3_FMC+CONN1_2 (J46.H31)
SYNC2_N: TIDA-01022-E3_ADC12DJxx00_2 (R150.1), TIDA-01022-E3_FMC+CONN2_2 (J51.G13)
SYNC2_P: TIDA-01022-E3_ADC12DJxx00_2 (R149.1), TIDA-01022-E3_FMC+CONN2_2 (J51.G12)
SYNC2_SE: TIDA-01022-E3_LMK0482x _PWR (R589.1 R637.1), TIDA-01022-E3_FMC+CONN2_2 (J51.H31)
SYNC_ADC1: TIDA-01022-E3_ADC12DJxx00_1 (R71.2), TIDA-01022-E3_LMK0482x _PWR (R413.2 R633.2)
SYNC_ADC2: TIDA-01022-E3_ADC12DJxx00_2 (R152.2), TIDA-01022-E3_LMK0482x _PWR (R414.1 R637.2)
VIN1_N: TIDA-01022-E3_ADC ANALOG INP CH1 (R552.2 R604.2), TIDA-01022-E3_ADC12DJxx00_1 (U8.A4)
VIN1_P: TIDA-01022-E3_ADC ANALOG INP CH1 (R551.2 R592.2), TIDA-01022-E3_ADC12DJxx00_1 (U8.A5)
VIN2_N: TIDA-01022-E3_ADC ANALOG INP CH2 (R561.2 R606.2), TIDA-01022-E3_ADC12DJxx00_1 (U8.M5)
VIN2_P: TIDA-01022-E3_ADC ANALOG INP CH2 (R560.2 R605.2), TIDA-01022-E3_ADC12DJxx00_1 (U8.M4)
VIN3_N: TIDA-01022-E3_ADC ANALOG INP CH3 (R570.2 R608.2), TIDA-01022-E3_ADC12DJxx00_2 (U17.A4)
VIN3_P: TIDA-01022-E3_ADC ANALOG INP CH3 (R569.2 R607.2), TIDA-01022-E3_ADC12DJxx00_2 (U17.A5)
VIN4_N: TIDA-01022-E3_ADC ANALOG INP CH4 (R579.2 R610.2), TIDA-01022-E3_ADC12DJxx00_2 (U17.M5)
VIN4_P: TIDA-01022-E3_ADC ANALOG INP CH4 (R578.2 R609.2), TIDA-01022-E3_ADC12DJxx00_2 (U17.M4)

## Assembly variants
TIDA-01022A_Orderable: not fitted C13 C14 C26 C47 C48 C60 C90 C91 C94 C95 C97 C99 C173 C174 C186 C207 C208 C220 C250 C251 C254 C255 C257 C259 C336 C351 C366 C405 C406 C409 C410 C490 C491 C492 C493 C499 C500 C502 C503 C504 C505 C506 C507 L21 R5 R19 R22 R29 R43 R46 R67 R70 R80 R81 R86 R100 R103 R110 R124 R127 R148 R151 R161 R162 R189 R191 R193 R195 R197 R198 R200 R202 R228 R229 R230 R232 R234 R236 R238 R239 R241 R243 R252 R253 R256 R257 R260 R261 R265 R266 R271 R286 R296 R297 R298 R311 R312 R319 R321 R323 R326 R340 R341 R387 R389 R395 R399 R410 R412 R417 R419 R428 R442 R443 R483 R486 R490 R495 R497 R500 R501 R507 R508 R509 R514 R521 R522 R524 R526 R533 R553 R554 R558 R559 R562 R563 R567 R568 R571 R572 R576 R577 R580 R581 R585 R586 R590 R591 R592 R594 R601 R602 R603 R604 R605 R606 R607 R608 R609 R610 R633 R634 R635 R637 R646 R647 R650 R651 R654 R655 R658 R659 R662 R663 R666 R667 R670 R671 R674 R675 U3 U6 U12 U15
TIDA-01022A_Onboard_Power: not fitted C12 C26 C46 C60 C90 C91 C94 C95 C97 C99 C172 C186 C206 C220 C250 C251 C254 C255 C257 C259 C336 C351 C366 C405 C406 C409 C410 C490 C491 C493 C499 C502 C503 C505 C506 L21 L75 L76 L77 L78 L79 L80 L81 L82 L93 L94 L95 L96 R2 R5 R7 R17 R19 R22 R26 R29 R31 R41 R43 R46 R67 R70 R80 R81 R83 R86 R88 R98 R100 R103 R107 R110 R112 R122 R124 R127 R148 R151 R161 R162 R189 R191 R193 R195 R197 R198 R200 R202 R228 R229 R230 R232 R234 R236 R238 R239 R241 R243 R252 R253 R256 R257 R260 R261 R265 R266 R271 R286 R296 R297 R298 R311 R312 R319 R321 R323 R326 R340 R341 R387 R389 R395 R399 R410 R412 R417 R419 R428 R442 R443 R483 R486 R490 R495 R497 R498 R499 R500 R501 R507 R508 R510 R511 R512 R514 R521 R526 R530 R533 R553 R554 R558 R559 R562 R563 R567 R568 R571 R572 R576 R577 R580 R581 R585 R586 R590 R591 R592 R594 R601 R602 R603 R604 R605 R606 R607 R608 R609 R610 R633 R634 R635 R637 R648 R649 R652 R653 R656 R657 R660 R661 R664 R665 R668 R669 R672 R673 R676 R677 U3 U6 U12 U15 U40 U43 U46 U49 U52
TIDA-01022_E3_with_TIDA-01027Pwr: not fitted C12 C26 C46 C60 C90 C91 C94 C95 C97 C99 C172 C186 C206 C220 C250 C251 C254 C255 C257 C259 C336 C351 C366 C405 C406 C409 C410 C490 C491 C493 C499 C502 C503 C505 C506 L21 L74 L75 L76 L77 L78 L79 L80 L81 L82 L83 L84 L85 L86 L87 L88 L89 L90 L91 L92 L93 L94 L95 L96 R2 R5 R7 R17 R19 R22 R26 R29 R31 R41 R43 R46 R67 R70 R80 R81 R83 R86 R88 R98 R100 R103 R107 R110 R112 R122 R124 R127 R148 R151 R161 R162 R174 R181 R186 R188 R189 R191 R193 R195 R197 R198 R200 R202 R204 R207 R215 R228 R229 R230 R232 R234 R236 R238 R239 R241 R243 R252 R253 R256 R257 R260 R261 R265 R266 R271 R286 R296 R297 R298 R311 R312 R319 R321 R323 R326 R340 R341 R387 R389 R395 R399 R410 R412 R417 R419 R428 R442 R443 R483 R486 R490 R495 R497 R498 R499 R500 R501 R507 R508 R510 R511 R512 R514 R521 R526 R530 R533 R553 R554 R558 R559 R562 R563 R567 R568 R571 R572 R576 R577 R580 R581 R585 R586 R590 R591 R592 R594 R601 R602 R603 R604 R605 R606 R607 R608 R609 R610 R633 R634 R635 R637 R648 R649 R652 R653 R656 R657 R660 R661 R664 R665 R668 R669 R672 R673 R676 R677 U3 U6 U12 U15 U40 U43 U46 U49 U52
